VERSION 5.8 ;
BUSBITCHARS "[]" ;
DIVIDERCHAR "/" ;
UNITS
    DATABASE MICRONS 1000 ;
END UNITS

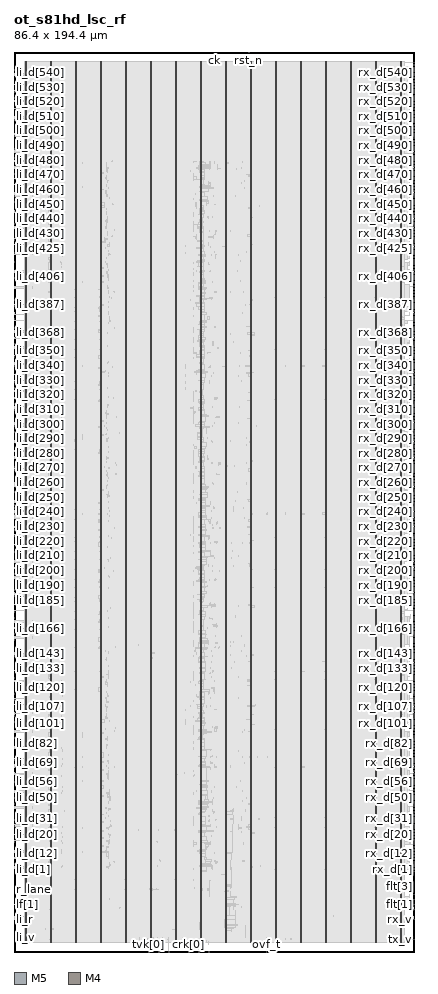
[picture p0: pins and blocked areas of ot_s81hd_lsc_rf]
MACRO ot_s81hd_lsc_rf
  FOREIGN ot_s81hd_lsc_rf 0 0 ;
  CLASS BLOCK ;
  SIZE 86.4 BY 194.4 ;
  PIN ck
    DIRECTION INPUT ;
    USE SIGNAL ;
    PORT
      LAYER M5 ;
        RECT  43.2 194.316 43.224 194.4 ;
    END
  END ck
  PIN crk[0]
    DIRECTION OUTPUT ;
    USE SIGNAL ;
    PORT
      LAYER M5 ;
        RECT  37.776 0 37.8 0.084 ;
    END
  END crk[0]
  PIN crk[1]
    DIRECTION OUTPUT ;
    USE SIGNAL ;
    PORT
      LAYER M5 ;
        RECT  39.936 0 39.96 0.084 ;
    END
  END crk[1]
  PIN crk[2]
    DIRECTION OUTPUT ;
    USE SIGNAL ;
    PORT
      LAYER M5 ;
        RECT  42.096 0 42.12 0.084 ;
    END
  END crk[2]
  PIN flt[0]
    DIRECTION OUTPUT ;
    USE SIGNAL ;
    PORT
      LAYER M4 ;
        RECT  86.316 9.168 86.4 9.192 ;
    END
  END flt[0]
  PIN flt[1]
    DIRECTION OUTPUT ;
    USE SIGNAL ;
    PORT
      LAYER M4 ;
        RECT  86.316 10.272 86.4 10.296 ;
    END
  END flt[1]
  PIN flt[2]
    DIRECTION OUTPUT ;
    USE SIGNAL ;
    PORT
      LAYER M4 ;
        RECT  86.316 11.328 86.4 11.352 ;
    END
  END flt[2]
  PIN flt[3]
    DIRECTION OUTPUT ;
    USE SIGNAL ;
    PORT
      LAYER M4 ;
        RECT  86.316 12.432 86.4 12.456 ;
    END
  END flt[3]
  PIN lf[0]
    DIRECTION INPUT ;
    USE SIGNAL ;
    PORT
      LAYER M4 ;
        RECT  0 9.168 0.084 9.192 ;
    END
  END lf[0]
  PIN lf[1]
    DIRECTION INPUT ;
    USE SIGNAL ;
    PORT
      LAYER M4 ;
        RECT  0 10.272 0.084 10.296 ;
    END
  END lf[1]
  PIN lf[2]
    DIRECTION INPUT ;
    USE SIGNAL ;
    PORT
      LAYER M4 ;
        RECT  0 11.328 0.084 11.352 ;
    END
  END lf[2]
  PIN li_d[0]
    DIRECTION INPUT ;
    USE SIGNAL ;
    PORT
      LAYER M4 ;
        RECT  0 17.424 0.084 17.448 ;
    END
  END li_d[0]
  PIN li_d[100]
    DIRECTION INPUT ;
    USE SIGNAL ;
    PORT
      LAYER M4 ;
        RECT  0 49.056 0.084 49.08 ;
    END
  END li_d[100]
  PIN li_d[101]
    DIRECTION INPUT ;
    USE SIGNAL ;
    PORT
      LAYER M4 ;
        RECT  0 49.392 0.084 49.416 ;
    END
  END li_d[101]
  PIN li_d[102]
    DIRECTION INPUT ;
    USE SIGNAL ;
    PORT
      LAYER M4 ;
        RECT  0 49.68 0.084 49.704 ;
    END
  END li_d[102]
  PIN li_d[103]
    DIRECTION INPUT ;
    USE SIGNAL ;
    PORT
      LAYER M4 ;
        RECT  0 50.016 0.084 50.04 ;
    END
  END li_d[103]
  PIN li_d[104]
    DIRECTION INPUT ;
    USE SIGNAL ;
    PORT
      LAYER M4 ;
        RECT  0 50.352 0.084 50.376 ;
    END
  END li_d[104]
  PIN li_d[105]
    DIRECTION INPUT ;
    USE SIGNAL ;
    PORT
      LAYER M4 ;
        RECT  0 50.64 0.084 50.664 ;
    END
  END li_d[105]
  PIN li_d[106]
    DIRECTION INPUT ;
    USE SIGNAL ;
    PORT
      LAYER M4 ;
        RECT  0 50.976 0.084 51 ;
    END
  END li_d[106]
  PIN li_d[107]
    DIRECTION INPUT ;
    USE SIGNAL ;
    PORT
      LAYER M4 ;
        RECT  0 51.264 0.084 51.288 ;
    END
  END li_d[107]
  PIN li_d[108]
    DIRECTION INPUT ;
    USE SIGNAL ;
    PORT
      LAYER M4 ;
        RECT  0 51.6 0.084 51.624 ;
    END
  END li_d[108]
  PIN li_d[109]
    DIRECTION INPUT ;
    USE SIGNAL ;
    PORT
      LAYER M4 ;
        RECT  0 51.936 0.084 51.96 ;
    END
  END li_d[109]
  PIN li_d[10]
    DIRECTION INPUT ;
    USE SIGNAL ;
    PORT
      LAYER M4 ;
        RECT  0 20.592 0.084 20.616 ;
    END
  END li_d[10]
  PIN li_d[110]
    DIRECTION INPUT ;
    USE SIGNAL ;
    PORT
      LAYER M4 ;
        RECT  0 52.224 0.084 52.248 ;
    END
  END li_d[110]
  PIN li_d[111]
    DIRECTION INPUT ;
    USE SIGNAL ;
    PORT
      LAYER M4 ;
        RECT  0 52.56 0.084 52.584 ;
    END
  END li_d[111]
  PIN li_d[112]
    DIRECTION INPUT ;
    USE SIGNAL ;
    PORT
      LAYER M4 ;
        RECT  0 52.848 0.084 52.872 ;
    END
  END li_d[112]
  PIN li_d[113]
    DIRECTION INPUT ;
    USE SIGNAL ;
    PORT
      LAYER M4 ;
        RECT  0 53.184 0.084 53.208 ;
    END
  END li_d[113]
  PIN li_d[114]
    DIRECTION INPUT ;
    USE SIGNAL ;
    PORT
      LAYER M4 ;
        RECT  0 53.472 0.084 53.496 ;
    END
  END li_d[114]
  PIN li_d[115]
    DIRECTION INPUT ;
    USE SIGNAL ;
    PORT
      LAYER M4 ;
        RECT  0 53.808 0.084 53.832 ;
    END
  END li_d[115]
  PIN li_d[116]
    DIRECTION INPUT ;
    USE SIGNAL ;
    PORT
      LAYER M4 ;
        RECT  0 54.144 0.084 54.168 ;
    END
  END li_d[116]
  PIN li_d[117]
    DIRECTION INPUT ;
    USE SIGNAL ;
    PORT
      LAYER M4 ;
        RECT  0 54.432 0.084 54.456 ;
    END
  END li_d[117]
  PIN li_d[118]
    DIRECTION INPUT ;
    USE SIGNAL ;
    PORT
      LAYER M4 ;
        RECT  0 54.768 0.084 54.792 ;
    END
  END li_d[118]
  PIN li_d[119]
    DIRECTION INPUT ;
    USE SIGNAL ;
    PORT
      LAYER M4 ;
        RECT  0 55.056 0.084 55.08 ;
    END
  END li_d[119]
  PIN li_d[11]
    DIRECTION INPUT ;
    USE SIGNAL ;
    PORT
      LAYER M4 ;
        RECT  0 20.928 0.084 20.952 ;
    END
  END li_d[11]
  PIN li_d[120]
    DIRECTION INPUT ;
    USE SIGNAL ;
    PORT
      LAYER M4 ;
        RECT  0 55.392 0.084 55.416 ;
    END
  END li_d[120]
  PIN li_d[121]
    DIRECTION INPUT ;
    USE SIGNAL ;
    PORT
      LAYER M4 ;
        RECT  0 55.728 0.084 55.752 ;
    END
  END li_d[121]
  PIN li_d[122]
    DIRECTION INPUT ;
    USE SIGNAL ;
    PORT
      LAYER M4 ;
        RECT  0 56.016 0.084 56.04 ;
    END
  END li_d[122]
  PIN li_d[123]
    DIRECTION INPUT ;
    USE SIGNAL ;
    PORT
      LAYER M4 ;
        RECT  0 56.352 0.084 56.376 ;
    END
  END li_d[123]
  PIN li_d[124]
    DIRECTION INPUT ;
    USE SIGNAL ;
    PORT
      LAYER M4 ;
        RECT  0 56.64 0.084 56.664 ;
    END
  END li_d[124]
  PIN li_d[125]
    DIRECTION INPUT ;
    USE SIGNAL ;
    PORT
      LAYER M4 ;
        RECT  0 56.976 0.084 57 ;
    END
  END li_d[125]
  PIN li_d[126]
    DIRECTION INPUT ;
    USE SIGNAL ;
    PORT
      LAYER M4 ;
        RECT  0 57.312 0.084 57.336 ;
    END
  END li_d[126]
  PIN li_d[127]
    DIRECTION INPUT ;
    USE SIGNAL ;
    PORT
      LAYER M4 ;
        RECT  0 57.6 0.084 57.624 ;
    END
  END li_d[127]
  PIN li_d[128]
    DIRECTION INPUT ;
    USE SIGNAL ;
    PORT
      LAYER M4 ;
        RECT  0 57.936 0.084 57.96 ;
    END
  END li_d[128]
  PIN li_d[129]
    DIRECTION INPUT ;
    USE SIGNAL ;
    PORT
      LAYER M4 ;
        RECT  0 58.224 0.084 58.248 ;
    END
  END li_d[129]
  PIN li_d[12]
    DIRECTION INPUT ;
    USE SIGNAL ;
    PORT
      LAYER M4 ;
        RECT  0 21.216 0.084 21.24 ;
    END
  END li_d[12]
  PIN li_d[130]
    DIRECTION INPUT ;
    USE SIGNAL ;
    PORT
      LAYER M4 ;
        RECT  0 58.56 0.084 58.584 ;
    END
  END li_d[130]
  PIN li_d[131]
    DIRECTION INPUT ;
    USE SIGNAL ;
    PORT
      LAYER M4 ;
        RECT  0 58.896 0.084 58.92 ;
    END
  END li_d[131]
  PIN li_d[132]
    DIRECTION INPUT ;
    USE SIGNAL ;
    PORT
      LAYER M4 ;
        RECT  0 59.184 0.084 59.208 ;
    END
  END li_d[132]
  PIN li_d[133]
    DIRECTION INPUT ;
    USE SIGNAL ;
    PORT
      LAYER M4 ;
        RECT  0 59.52 0.084 59.544 ;
    END
  END li_d[133]
  PIN li_d[134]
    DIRECTION INPUT ;
    USE SIGNAL ;
    PORT
      LAYER M4 ;
        RECT  0 59.808 0.084 59.832 ;
    END
  END li_d[134]
  PIN li_d[135]
    DIRECTION INPUT ;
    USE SIGNAL ;
    PORT
      LAYER M4 ;
        RECT  0 60.144 0.084 60.168 ;
    END
  END li_d[135]
  PIN li_d[136]
    DIRECTION INPUT ;
    USE SIGNAL ;
    PORT
      LAYER M4 ;
        RECT  0 60.432 0.084 60.456 ;
    END
  END li_d[136]
  PIN li_d[137]
    DIRECTION INPUT ;
    USE SIGNAL ;
    PORT
      LAYER M4 ;
        RECT  0 60.768 0.084 60.792 ;
    END
  END li_d[137]
  PIN li_d[138]
    DIRECTION INPUT ;
    USE SIGNAL ;
    PORT
      LAYER M4 ;
        RECT  0 61.104 0.084 61.128 ;
    END
  END li_d[138]
  PIN li_d[139]
    DIRECTION INPUT ;
    USE SIGNAL ;
    PORT
      LAYER M4 ;
        RECT  0 61.392 0.084 61.416 ;
    END
  END li_d[139]
  PIN li_d[13]
    DIRECTION INPUT ;
    USE SIGNAL ;
    PORT
      LAYER M4 ;
        RECT  0 21.552 0.084 21.576 ;
    END
  END li_d[13]
  PIN li_d[140]
    DIRECTION INPUT ;
    USE SIGNAL ;
    PORT
      LAYER M4 ;
        RECT  0 61.728 0.084 61.752 ;
    END
  END li_d[140]
  PIN li_d[141]
    DIRECTION INPUT ;
    USE SIGNAL ;
    PORT
      LAYER M4 ;
        RECT  0 62.016 0.084 62.04 ;
    END
  END li_d[141]
  PIN li_d[142]
    DIRECTION INPUT ;
    USE SIGNAL ;
    PORT
      LAYER M4 ;
        RECT  0 62.352 0.084 62.376 ;
    END
  END li_d[142]
  PIN li_d[143]
    DIRECTION INPUT ;
    USE SIGNAL ;
    PORT
      LAYER M4 ;
        RECT  0 62.688 0.084 62.712 ;
    END
  END li_d[143]
  PIN li_d[144]
    DIRECTION INPUT ;
    USE SIGNAL ;
    PORT
      LAYER M4 ;
        RECT  0 62.976 0.084 63 ;
    END
  END li_d[144]
  PIN li_d[145]
    DIRECTION INPUT ;
    USE SIGNAL ;
    PORT
      LAYER M4 ;
        RECT  0 63.312 0.084 63.336 ;
    END
  END li_d[145]
  PIN li_d[146]
    DIRECTION INPUT ;
    USE SIGNAL ;
    PORT
      LAYER M4 ;
        RECT  0 63.6 0.084 63.624 ;
    END
  END li_d[146]
  PIN li_d[147]
    DIRECTION INPUT ;
    USE SIGNAL ;
    PORT
      LAYER M4 ;
        RECT  0 63.936 0.084 63.96 ;
    END
  END li_d[147]
  PIN li_d[148]
    DIRECTION INPUT ;
    USE SIGNAL ;
    PORT
      LAYER M4 ;
        RECT  0 64.272 0.084 64.296 ;
    END
  END li_d[148]
  PIN li_d[149]
    DIRECTION INPUT ;
    USE SIGNAL ;
    PORT
      LAYER M4 ;
        RECT  0 64.56 0.084 64.584 ;
    END
  END li_d[149]
  PIN li_d[14]
    DIRECTION INPUT ;
    USE SIGNAL ;
    PORT
      LAYER M4 ;
        RECT  0 21.84 0.084 21.864 ;
    END
  END li_d[14]
  PIN li_d[150]
    DIRECTION INPUT ;
    USE SIGNAL ;
    PORT
      LAYER M4 ;
        RECT  0 64.896 0.084 64.92 ;
    END
  END li_d[150]
  PIN li_d[151]
    DIRECTION INPUT ;
    USE SIGNAL ;
    PORT
      LAYER M4 ;
        RECT  0 65.184 0.084 65.208 ;
    END
  END li_d[151]
  PIN li_d[152]
    DIRECTION INPUT ;
    USE SIGNAL ;
    PORT
      LAYER M4 ;
        RECT  0 65.52 0.084 65.544 ;
    END
  END li_d[152]
  PIN li_d[153]
    DIRECTION INPUT ;
    USE SIGNAL ;
    PORT
      LAYER M4 ;
        RECT  0 65.856 0.084 65.88 ;
    END
  END li_d[153]
  PIN li_d[154]
    DIRECTION INPUT ;
    USE SIGNAL ;
    PORT
      LAYER M4 ;
        RECT  0 66.144 0.084 66.168 ;
    END
  END li_d[154]
  PIN li_d[155]
    DIRECTION INPUT ;
    USE SIGNAL ;
    PORT
      LAYER M4 ;
        RECT  0 66.48 0.084 66.504 ;
    END
  END li_d[155]
  PIN li_d[156]
    DIRECTION INPUT ;
    USE SIGNAL ;
    PORT
      LAYER M4 ;
        RECT  0 66.768 0.084 66.792 ;
    END
  END li_d[156]
  PIN li_d[157]
    DIRECTION INPUT ;
    USE SIGNAL ;
    PORT
      LAYER M4 ;
        RECT  0 67.104 0.084 67.128 ;
    END
  END li_d[157]
  PIN li_d[158]
    DIRECTION INPUT ;
    USE SIGNAL ;
    PORT
      LAYER M4 ;
        RECT  0 67.392 0.084 67.416 ;
    END
  END li_d[158]
  PIN li_d[159]
    DIRECTION INPUT ;
    USE SIGNAL ;
    PORT
      LAYER M4 ;
        RECT  0 67.728 0.084 67.752 ;
    END
  END li_d[159]
  PIN li_d[15]
    DIRECTION INPUT ;
    USE SIGNAL ;
    PORT
      LAYER M4 ;
        RECT  0 22.176 0.084 22.2 ;
    END
  END li_d[15]
  PIN li_d[160]
    DIRECTION INPUT ;
    USE SIGNAL ;
    PORT
      LAYER M4 ;
        RECT  0 68.064 0.084 68.088 ;
    END
  END li_d[160]
  PIN li_d[161]
    DIRECTION INPUT ;
    USE SIGNAL ;
    PORT
      LAYER M4 ;
        RECT  0 68.352 0.084 68.376 ;
    END
  END li_d[161]
  PIN li_d[162]
    DIRECTION INPUT ;
    USE SIGNAL ;
    PORT
      LAYER M4 ;
        RECT  0 68.688 0.084 68.712 ;
    END
  END li_d[162]
  PIN li_d[163]
    DIRECTION INPUT ;
    USE SIGNAL ;
    PORT
      LAYER M4 ;
        RECT  0 68.976 0.084 69 ;
    END
  END li_d[163]
  PIN li_d[164]
    DIRECTION INPUT ;
    USE SIGNAL ;
    PORT
      LAYER M4 ;
        RECT  0 69.312 0.084 69.336 ;
    END
  END li_d[164]
  PIN li_d[165]
    DIRECTION INPUT ;
    USE SIGNAL ;
    PORT
      LAYER M4 ;
        RECT  0 69.648 0.084 69.672 ;
    END
  END li_d[165]
  PIN li_d[166]
    DIRECTION INPUT ;
    USE SIGNAL ;
    PORT
      LAYER M4 ;
        RECT  0 69.936 0.084 69.96 ;
    END
  END li_d[166]
  PIN li_d[167]
    DIRECTION INPUT ;
    USE SIGNAL ;
    PORT
      LAYER M4 ;
        RECT  0 70.272 0.084 70.296 ;
    END
  END li_d[167]
  PIN li_d[168]
    DIRECTION INPUT ;
    USE SIGNAL ;
    PORT
      LAYER M4 ;
        RECT  0 70.56 0.084 70.584 ;
    END
  END li_d[168]
  PIN li_d[169]
    DIRECTION INPUT ;
    USE SIGNAL ;
    PORT
      LAYER M4 ;
        RECT  0 70.896 0.084 70.92 ;
    END
  END li_d[169]
  PIN li_d[16]
    DIRECTION INPUT ;
    USE SIGNAL ;
    PORT
      LAYER M4 ;
        RECT  0 22.512 0.084 22.536 ;
    END
  END li_d[16]
  PIN li_d[170]
    DIRECTION INPUT ;
    USE SIGNAL ;
    PORT
      LAYER M4 ;
        RECT  0 71.232 0.084 71.256 ;
    END
  END li_d[170]
  PIN li_d[171]
    DIRECTION INPUT ;
    USE SIGNAL ;
    PORT
      LAYER M4 ;
        RECT  0 71.52 0.084 71.544 ;
    END
  END li_d[171]
  PIN li_d[172]
    DIRECTION INPUT ;
    USE SIGNAL ;
    PORT
      LAYER M4 ;
        RECT  0 71.856 0.084 71.88 ;
    END
  END li_d[172]
  PIN li_d[173]
    DIRECTION INPUT ;
    USE SIGNAL ;
    PORT
      LAYER M4 ;
        RECT  0 72.144 0.084 72.168 ;
    END
  END li_d[173]
  PIN li_d[174]
    DIRECTION INPUT ;
    USE SIGNAL ;
    PORT
      LAYER M4 ;
        RECT  0 72.48 0.084 72.504 ;
    END
  END li_d[174]
  PIN li_d[175]
    DIRECTION INPUT ;
    USE SIGNAL ;
    PORT
      LAYER M4 ;
        RECT  0 72.816 0.084 72.84 ;
    END
  END li_d[175]
  PIN li_d[176]
    DIRECTION INPUT ;
    USE SIGNAL ;
    PORT
      LAYER M4 ;
        RECT  0 73.104 0.084 73.128 ;
    END
  END li_d[176]
  PIN li_d[177]
    DIRECTION INPUT ;
    USE SIGNAL ;
    PORT
      LAYER M4 ;
        RECT  0 73.44 0.084 73.464 ;
    END
  END li_d[177]
  PIN li_d[178]
    DIRECTION INPUT ;
    USE SIGNAL ;
    PORT
      LAYER M4 ;
        RECT  0 73.728 0.084 73.752 ;
    END
  END li_d[178]
  PIN li_d[179]
    DIRECTION INPUT ;
    USE SIGNAL ;
    PORT
      LAYER M4 ;
        RECT  0 74.064 0.084 74.088 ;
    END
  END li_d[179]
  PIN li_d[17]
    DIRECTION INPUT ;
    USE SIGNAL ;
    PORT
      LAYER M4 ;
        RECT  0 22.8 0.084 22.824 ;
    END
  END li_d[17]
  PIN li_d[180]
    DIRECTION INPUT ;
    USE SIGNAL ;
    PORT
      LAYER M4 ;
        RECT  0 74.352 0.084 74.376 ;
    END
  END li_d[180]
  PIN li_d[181]
    DIRECTION INPUT ;
    USE SIGNAL ;
    PORT
      LAYER M4 ;
        RECT  0 74.688 0.084 74.712 ;
    END
  END li_d[181]
  PIN li_d[182]
    DIRECTION INPUT ;
    USE SIGNAL ;
    PORT
      LAYER M4 ;
        RECT  0 75.024 0.084 75.048 ;
    END
  END li_d[182]
  PIN li_d[183]
    DIRECTION INPUT ;
    USE SIGNAL ;
    PORT
      LAYER M4 ;
        RECT  0 75.312 0.084 75.336 ;
    END
  END li_d[183]
  PIN li_d[184]
    DIRECTION INPUT ;
    USE SIGNAL ;
    PORT
      LAYER M4 ;
        RECT  0 75.648 0.084 75.672 ;
    END
  END li_d[184]
  PIN li_d[185]
    DIRECTION INPUT ;
    USE SIGNAL ;
    PORT
      LAYER M4 ;
        RECT  0 75.936 0.084 75.96 ;
    END
  END li_d[185]
  PIN li_d[186]
    DIRECTION INPUT ;
    USE SIGNAL ;
    PORT
      LAYER M4 ;
        RECT  0 76.272 0.084 76.296 ;
    END
  END li_d[186]
  PIN li_d[187]
    DIRECTION INPUT ;
    USE SIGNAL ;
    PORT
      LAYER M4 ;
        RECT  0 76.608 0.084 76.632 ;
    END
  END li_d[187]
  PIN li_d[188]
    DIRECTION INPUT ;
    USE SIGNAL ;
    PORT
      LAYER M4 ;
        RECT  0 76.896 0.084 76.92 ;
    END
  END li_d[188]
  PIN li_d[189]
    DIRECTION INPUT ;
    USE SIGNAL ;
    PORT
      LAYER M4 ;
        RECT  0 77.232 0.084 77.256 ;
    END
  END li_d[189]
  PIN li_d[18]
    DIRECTION INPUT ;
    USE SIGNAL ;
    PORT
      LAYER M4 ;
        RECT  0 23.136 0.084 23.16 ;
    END
  END li_d[18]
  PIN li_d[190]
    DIRECTION INPUT ;
    USE SIGNAL ;
    PORT
      LAYER M4 ;
        RECT  0 77.52 0.084 77.544 ;
    END
  END li_d[190]
  PIN li_d[191]
    DIRECTION INPUT ;
    USE SIGNAL ;
    PORT
      LAYER M4 ;
        RECT  0 77.856 0.084 77.88 ;
    END
  END li_d[191]
  PIN li_d[192]
    DIRECTION INPUT ;
    USE SIGNAL ;
    PORT
      LAYER M4 ;
        RECT  0 78.192 0.084 78.216 ;
    END
  END li_d[192]
  PIN li_d[193]
    DIRECTION INPUT ;
    USE SIGNAL ;
    PORT
      LAYER M4 ;
        RECT  0 78.48 0.084 78.504 ;
    END
  END li_d[193]
  PIN li_d[194]
    DIRECTION INPUT ;
    USE SIGNAL ;
    PORT
      LAYER M4 ;
        RECT  0 78.816 0.084 78.84 ;
    END
  END li_d[194]
  PIN li_d[195]
    DIRECTION INPUT ;
    USE SIGNAL ;
    PORT
      LAYER M4 ;
        RECT  0 79.104 0.084 79.128 ;
    END
  END li_d[195]
  PIN li_d[196]
    DIRECTION INPUT ;
    USE SIGNAL ;
    PORT
      LAYER M4 ;
        RECT  0 79.44 0.084 79.464 ;
    END
  END li_d[196]
  PIN li_d[197]
    DIRECTION INPUT ;
    USE SIGNAL ;
    PORT
      LAYER M4 ;
        RECT  0 79.776 0.084 79.8 ;
    END
  END li_d[197]
  PIN li_d[198]
    DIRECTION INPUT ;
    USE SIGNAL ;
    PORT
      LAYER M4 ;
        RECT  0 80.064 0.084 80.088 ;
    END
  END li_d[198]
  PIN li_d[199]
    DIRECTION INPUT ;
    USE SIGNAL ;
    PORT
      LAYER M4 ;
        RECT  0 80.4 0.084 80.424 ;
    END
  END li_d[199]
  PIN li_d[19]
    DIRECTION INPUT ;
    USE SIGNAL ;
    PORT
      LAYER M4 ;
        RECT  0 23.424 0.084 23.448 ;
    END
  END li_d[19]
  PIN li_d[1]
    DIRECTION INPUT ;
    USE SIGNAL ;
    PORT
      LAYER M4 ;
        RECT  0 17.76 0.084 17.784 ;
    END
  END li_d[1]
  PIN li_d[200]
    DIRECTION INPUT ;
    USE SIGNAL ;
    PORT
      LAYER M4 ;
        RECT  0 80.688 0.084 80.712 ;
    END
  END li_d[200]
  PIN li_d[201]
    DIRECTION INPUT ;
    USE SIGNAL ;
    PORT
      LAYER M4 ;
        RECT  0 81.024 0.084 81.048 ;
    END
  END li_d[201]
  PIN li_d[202]
    DIRECTION INPUT ;
    USE SIGNAL ;
    PORT
      LAYER M4 ;
        RECT  0 81.36 0.084 81.384 ;
    END
  END li_d[202]
  PIN li_d[203]
    DIRECTION INPUT ;
    USE SIGNAL ;
    PORT
      LAYER M4 ;
        RECT  0 81.648 0.084 81.672 ;
    END
  END li_d[203]
  PIN li_d[204]
    DIRECTION INPUT ;
    USE SIGNAL ;
    PORT
      LAYER M4 ;
        RECT  0 81.984 0.084 82.008 ;
    END
  END li_d[204]
  PIN li_d[205]
    DIRECTION INPUT ;
    USE SIGNAL ;
    PORT
      LAYER M4 ;
        RECT  0 82.272 0.084 82.296 ;
    END
  END li_d[205]
  PIN li_d[206]
    DIRECTION INPUT ;
    USE SIGNAL ;
    PORT
      LAYER M4 ;
        RECT  0 82.608 0.084 82.632 ;
    END
  END li_d[206]
  PIN li_d[207]
    DIRECTION INPUT ;
    USE SIGNAL ;
    PORT
      LAYER M4 ;
        RECT  0 82.896 0.084 82.92 ;
    END
  END li_d[207]
  PIN li_d[208]
    DIRECTION INPUT ;
    USE SIGNAL ;
    PORT
      LAYER M4 ;
        RECT  0 83.232 0.084 83.256 ;
    END
  END li_d[208]
  PIN li_d[209]
    DIRECTION INPUT ;
    USE SIGNAL ;
    PORT
      LAYER M4 ;
        RECT  0 83.568 0.084 83.592 ;
    END
  END li_d[209]
  PIN li_d[20]
    DIRECTION INPUT ;
    USE SIGNAL ;
    PORT
      LAYER M4 ;
        RECT  0 23.76 0.084 23.784 ;
    END
  END li_d[20]
  PIN li_d[210]
    DIRECTION INPUT ;
    USE SIGNAL ;
    PORT
      LAYER M4 ;
        RECT  0 83.856 0.084 83.88 ;
    END
  END li_d[210]
  PIN li_d[211]
    DIRECTION INPUT ;
    USE SIGNAL ;
    PORT
      LAYER M4 ;
        RECT  0 84.192 0.084 84.216 ;
    END
  END li_d[211]
  PIN li_d[212]
    DIRECTION INPUT ;
    USE SIGNAL ;
    PORT
      LAYER M4 ;
        RECT  0 84.48 0.084 84.504 ;
    END
  END li_d[212]
  PIN li_d[213]
    DIRECTION INPUT ;
    USE SIGNAL ;
    PORT
      LAYER M4 ;
        RECT  0 84.816 0.084 84.84 ;
    END
  END li_d[213]
  PIN li_d[214]
    DIRECTION INPUT ;
    USE SIGNAL ;
    PORT
      LAYER M4 ;
        RECT  0 85.152 0.084 85.176 ;
    END
  END li_d[214]
  PIN li_d[215]
    DIRECTION INPUT ;
    USE SIGNAL ;
    PORT
      LAYER M4 ;
        RECT  0 85.44 0.084 85.464 ;
    END
  END li_d[215]
  PIN li_d[216]
    DIRECTION INPUT ;
    USE SIGNAL ;
    PORT
      LAYER M4 ;
        RECT  0 85.776 0.084 85.8 ;
    END
  END li_d[216]
  PIN li_d[217]
    DIRECTION INPUT ;
    USE SIGNAL ;
    PORT
      LAYER M4 ;
        RECT  0 86.064 0.084 86.088 ;
    END
  END li_d[217]
  PIN li_d[218]
    DIRECTION INPUT ;
    USE SIGNAL ;
    PORT
      LAYER M4 ;
        RECT  0 86.4 0.084 86.424 ;
    END
  END li_d[218]
  PIN li_d[219]
    DIRECTION INPUT ;
    USE SIGNAL ;
    PORT
      LAYER M4 ;
        RECT  0 86.736 0.084 86.76 ;
    END
  END li_d[219]
  PIN li_d[21]
    DIRECTION INPUT ;
    USE SIGNAL ;
    PORT
      LAYER M4 ;
        RECT  0 24.048 0.084 24.072 ;
    END
  END li_d[21]
  PIN li_d[220]
    DIRECTION INPUT ;
    USE SIGNAL ;
    PORT
      LAYER M4 ;
        RECT  0 87.024 0.084 87.048 ;
    END
  END li_d[220]
  PIN li_d[221]
    DIRECTION INPUT ;
    USE SIGNAL ;
    PORT
      LAYER M4 ;
        RECT  0 87.36 0.084 87.384 ;
    END
  END li_d[221]
  PIN li_d[222]
    DIRECTION INPUT ;
    USE SIGNAL ;
    PORT
      LAYER M4 ;
        RECT  0 87.648 0.084 87.672 ;
    END
  END li_d[222]
  PIN li_d[223]
    DIRECTION INPUT ;
    USE SIGNAL ;
    PORT
      LAYER M4 ;
        RECT  0 87.984 0.084 88.008 ;
    END
  END li_d[223]
  PIN li_d[224]
    DIRECTION INPUT ;
    USE SIGNAL ;
    PORT
      LAYER M4 ;
        RECT  0 88.32 0.084 88.344 ;
    END
  END li_d[224]
  PIN li_d[225]
    DIRECTION INPUT ;
    USE SIGNAL ;
    PORT
      LAYER M4 ;
        RECT  0 88.608 0.084 88.632 ;
    END
  END li_d[225]
  PIN li_d[226]
    DIRECTION INPUT ;
    USE SIGNAL ;
    PORT
      LAYER M4 ;
        RECT  0 88.944 0.084 88.968 ;
    END
  END li_d[226]
  PIN li_d[227]
    DIRECTION INPUT ;
    USE SIGNAL ;
    PORT
      LAYER M4 ;
        RECT  0 89.232 0.084 89.256 ;
    END
  END li_d[227]
  PIN li_d[228]
    DIRECTION INPUT ;
    USE SIGNAL ;
    PORT
      LAYER M4 ;
        RECT  0 89.568 0.084 89.592 ;
    END
  END li_d[228]
  PIN li_d[229]
    DIRECTION INPUT ;
    USE SIGNAL ;
    PORT
      LAYER M4 ;
        RECT  0 89.856 0.084 89.88 ;
    END
  END li_d[229]
  PIN li_d[22]
    DIRECTION INPUT ;
    USE SIGNAL ;
    PORT
      LAYER M4 ;
        RECT  0 24.384 0.084 24.408 ;
    END
  END li_d[22]
  PIN li_d[230]
    DIRECTION INPUT ;
    USE SIGNAL ;
    PORT
      LAYER M4 ;
        RECT  0 90.192 0.084 90.216 ;
    END
  END li_d[230]
  PIN li_d[231]
    DIRECTION INPUT ;
    USE SIGNAL ;
    PORT
      LAYER M4 ;
        RECT  0 90.528 0.084 90.552 ;
    END
  END li_d[231]
  PIN li_d[232]
    DIRECTION INPUT ;
    USE SIGNAL ;
    PORT
      LAYER M4 ;
        RECT  0 90.816 0.084 90.84 ;
    END
  END li_d[232]
  PIN li_d[233]
    DIRECTION INPUT ;
    USE SIGNAL ;
    PORT
      LAYER M4 ;
        RECT  0 91.152 0.084 91.176 ;
    END
  END li_d[233]
  PIN li_d[234]
    DIRECTION INPUT ;
    USE SIGNAL ;
    PORT
      LAYER M4 ;
        RECT  0 91.44 0.084 91.464 ;
    END
  END li_d[234]
  PIN li_d[235]
    DIRECTION INPUT ;
    USE SIGNAL ;
    PORT
      LAYER M4 ;
        RECT  0 91.776 0.084 91.8 ;
    END
  END li_d[235]
  PIN li_d[236]
    DIRECTION INPUT ;
    USE SIGNAL ;
    PORT
      LAYER M4 ;
        RECT  0 92.112 0.084 92.136 ;
    END
  END li_d[236]
  PIN li_d[237]
    DIRECTION INPUT ;
    USE SIGNAL ;
    PORT
      LAYER M4 ;
        RECT  0 92.4 0.084 92.424 ;
    END
  END li_d[237]
  PIN li_d[238]
    DIRECTION INPUT ;
    USE SIGNAL ;
    PORT
      LAYER M4 ;
        RECT  0 92.736 0.084 92.76 ;
    END
  END li_d[238]
  PIN li_d[239]
    DIRECTION INPUT ;
    USE SIGNAL ;
    PORT
      LAYER M4 ;
        RECT  0 93.024 0.084 93.048 ;
    END
  END li_d[239]
  PIN li_d[23]
    DIRECTION INPUT ;
    USE SIGNAL ;
    PORT
      LAYER M4 ;
        RECT  0 24.72 0.084 24.744 ;
    END
  END li_d[23]
  PIN li_d[240]
    DIRECTION INPUT ;
    USE SIGNAL ;
    PORT
      LAYER M4 ;
        RECT  0 93.36 0.084 93.384 ;
    END
  END li_d[240]
  PIN li_d[241]
    DIRECTION INPUT ;
    USE SIGNAL ;
    PORT
      LAYER M4 ;
        RECT  0 93.696 0.084 93.72 ;
    END
  END li_d[241]
  PIN li_d[242]
    DIRECTION INPUT ;
    USE SIGNAL ;
    PORT
      LAYER M4 ;
        RECT  0 93.984 0.084 94.008 ;
    END
  END li_d[242]
  PIN li_d[243]
    DIRECTION INPUT ;
    USE SIGNAL ;
    PORT
      LAYER M4 ;
        RECT  0 94.32 0.084 94.344 ;
    END
  END li_d[243]
  PIN li_d[244]
    DIRECTION INPUT ;
    USE SIGNAL ;
    PORT
      LAYER M4 ;
        RECT  0 94.608 0.084 94.632 ;
    END
  END li_d[244]
  PIN li_d[245]
    DIRECTION INPUT ;
    USE SIGNAL ;
    PORT
      LAYER M4 ;
        RECT  0 94.944 0.084 94.968 ;
    END
  END li_d[245]
  PIN li_d[246]
    DIRECTION INPUT ;
    USE SIGNAL ;
    PORT
      LAYER M4 ;
        RECT  0 95.28 0.084 95.304 ;
    END
  END li_d[246]
  PIN li_d[247]
    DIRECTION INPUT ;
    USE SIGNAL ;
    PORT
      LAYER M4 ;
        RECT  0 95.568 0.084 95.592 ;
    END
  END li_d[247]
  PIN li_d[248]
    DIRECTION INPUT ;
    USE SIGNAL ;
    PORT
      LAYER M4 ;
        RECT  0 95.904 0.084 95.928 ;
    END
  END li_d[248]
  PIN li_d[249]
    DIRECTION INPUT ;
    USE SIGNAL ;
    PORT
      LAYER M4 ;
        RECT  0 96.192 0.084 96.216 ;
    END
  END li_d[249]
  PIN li_d[24]
    DIRECTION INPUT ;
    USE SIGNAL ;
    PORT
      LAYER M4 ;
        RECT  0 25.008 0.084 25.032 ;
    END
  END li_d[24]
  PIN li_d[250]
    DIRECTION INPUT ;
    USE SIGNAL ;
    PORT
      LAYER M4 ;
        RECT  0 96.528 0.084 96.552 ;
    END
  END li_d[250]
  PIN li_d[251]
    DIRECTION INPUT ;
    USE SIGNAL ;
    PORT
      LAYER M4 ;
        RECT  0 96.816 0.084 96.84 ;
    END
  END li_d[251]
  PIN li_d[252]
    DIRECTION INPUT ;
    USE SIGNAL ;
    PORT
      LAYER M4 ;
        RECT  0 97.152 0.084 97.176 ;
    END
  END li_d[252]
  PIN li_d[253]
    DIRECTION INPUT ;
    USE SIGNAL ;
    PORT
      LAYER M4 ;
        RECT  0 97.488 0.084 97.512 ;
    END
  END li_d[253]
  PIN li_d[254]
    DIRECTION INPUT ;
    USE SIGNAL ;
    PORT
      LAYER M4 ;
        RECT  0 97.776 0.084 97.8 ;
    END
  END li_d[254]
  PIN li_d[255]
    DIRECTION INPUT ;
    USE SIGNAL ;
    PORT
      LAYER M4 ;
        RECT  0 98.112 0.084 98.136 ;
    END
  END li_d[255]
  PIN li_d[256]
    DIRECTION INPUT ;
    USE SIGNAL ;
    PORT
      LAYER M4 ;
        RECT  0 98.4 0.084 98.424 ;
    END
  END li_d[256]
  PIN li_d[257]
    DIRECTION INPUT ;
    USE SIGNAL ;
    PORT
      LAYER M4 ;
        RECT  0 98.736 0.084 98.76 ;
    END
  END li_d[257]
  PIN li_d[258]
    DIRECTION INPUT ;
    USE SIGNAL ;
    PORT
      LAYER M4 ;
        RECT  0 99.072 0.084 99.096 ;
    END
  END li_d[258]
  PIN li_d[259]
    DIRECTION INPUT ;
    USE SIGNAL ;
    PORT
      LAYER M4 ;
        RECT  0 99.36 0.084 99.384 ;
    END
  END li_d[259]
  PIN li_d[25]
    DIRECTION INPUT ;
    USE SIGNAL ;
    PORT
      LAYER M4 ;
        RECT  0 25.344 0.084 25.368 ;
    END
  END li_d[25]
  PIN li_d[260]
    DIRECTION INPUT ;
    USE SIGNAL ;
    PORT
      LAYER M4 ;
        RECT  0 99.696 0.084 99.72 ;
    END
  END li_d[260]
  PIN li_d[261]
    DIRECTION INPUT ;
    USE SIGNAL ;
    PORT
      LAYER M4 ;
        RECT  0 99.984 0.084 100.008 ;
    END
  END li_d[261]
  PIN li_d[262]
    DIRECTION INPUT ;
    USE SIGNAL ;
    PORT
      LAYER M4 ;
        RECT  0 100.32 0.084 100.344 ;
    END
  END li_d[262]
  PIN li_d[263]
    DIRECTION INPUT ;
    USE SIGNAL ;
    PORT
      LAYER M4 ;
        RECT  0 100.656 0.084 100.68 ;
    END
  END li_d[263]
  PIN li_d[264]
    DIRECTION INPUT ;
    USE SIGNAL ;
    PORT
      LAYER M4 ;
        RECT  0 100.944 0.084 100.968 ;
    END
  END li_d[264]
  PIN li_d[265]
    DIRECTION INPUT ;
    USE SIGNAL ;
    PORT
      LAYER M4 ;
        RECT  0 101.28 0.084 101.304 ;
    END
  END li_d[265]
  PIN li_d[266]
    DIRECTION INPUT ;
    USE SIGNAL ;
    PORT
      LAYER M4 ;
        RECT  0 101.568 0.084 101.592 ;
    END
  END li_d[266]
  PIN li_d[267]
    DIRECTION INPUT ;
    USE SIGNAL ;
    PORT
      LAYER M4 ;
        RECT  0 101.904 0.084 101.928 ;
    END
  END li_d[267]
  PIN li_d[268]
    DIRECTION INPUT ;
    USE SIGNAL ;
    PORT
      LAYER M4 ;
        RECT  0 102.24 0.084 102.264 ;
    END
  END li_d[268]
  PIN li_d[269]
    DIRECTION INPUT ;
    USE SIGNAL ;
    PORT
      LAYER M4 ;
        RECT  0 102.528 0.084 102.552 ;
    END
  END li_d[269]
  PIN li_d[26]
    DIRECTION INPUT ;
    USE SIGNAL ;
    PORT
      LAYER M4 ;
        RECT  0 25.632 0.084 25.656 ;
    END
  END li_d[26]
  PIN li_d[270]
    DIRECTION INPUT ;
    USE SIGNAL ;
    PORT
      LAYER M4 ;
        RECT  0 102.864 0.084 102.888 ;
    END
  END li_d[270]
  PIN li_d[271]
    DIRECTION INPUT ;
    USE SIGNAL ;
    PORT
      LAYER M4 ;
        RECT  0 103.152 0.084 103.176 ;
    END
  END li_d[271]
  PIN li_d[272]
    DIRECTION INPUT ;
    USE SIGNAL ;
    PORT
      LAYER M4 ;
        RECT  0 103.488 0.084 103.512 ;
    END
  END li_d[272]
  PIN li_d[273]
    DIRECTION INPUT ;
    USE SIGNAL ;
    PORT
      LAYER M4 ;
        RECT  0 103.776 0.084 103.8 ;
    END
  END li_d[273]
  PIN li_d[274]
    DIRECTION INPUT ;
    USE SIGNAL ;
    PORT
      LAYER M4 ;
        RECT  0 104.112 0.084 104.136 ;
    END
  END li_d[274]
  PIN li_d[275]
    DIRECTION INPUT ;
    USE SIGNAL ;
    PORT
      LAYER M4 ;
        RECT  0 104.448 0.084 104.472 ;
    END
  END li_d[275]
  PIN li_d[276]
    DIRECTION INPUT ;
    USE SIGNAL ;
    PORT
      LAYER M4 ;
        RECT  0 104.736 0.084 104.76 ;
    END
  END li_d[276]
  PIN li_d[277]
    DIRECTION INPUT ;
    USE SIGNAL ;
    PORT
      LAYER M4 ;
        RECT  0 105.072 0.084 105.096 ;
    END
  END li_d[277]
  PIN li_d[278]
    DIRECTION INPUT ;
    USE SIGNAL ;
    PORT
      LAYER M4 ;
        RECT  0 105.36 0.084 105.384 ;
    END
  END li_d[278]
  PIN li_d[279]
    DIRECTION INPUT ;
    USE SIGNAL ;
    PORT
      LAYER M4 ;
        RECT  0 105.696 0.084 105.72 ;
    END
  END li_d[279]
  PIN li_d[27]
    DIRECTION INPUT ;
    USE SIGNAL ;
    PORT
      LAYER M4 ;
        RECT  0 25.968 0.084 25.992 ;
    END
  END li_d[27]
  PIN li_d[280]
    DIRECTION INPUT ;
    USE SIGNAL ;
    PORT
      LAYER M4 ;
        RECT  0 106.032 0.084 106.056 ;
    END
  END li_d[280]
  PIN li_d[281]
    DIRECTION INPUT ;
    USE SIGNAL ;
    PORT
      LAYER M4 ;
        RECT  0 106.32 0.084 106.344 ;
    END
  END li_d[281]
  PIN li_d[282]
    DIRECTION INPUT ;
    USE SIGNAL ;
    PORT
      LAYER M4 ;
        RECT  0 106.656 0.084 106.68 ;
    END
  END li_d[282]
  PIN li_d[283]
    DIRECTION INPUT ;
    USE SIGNAL ;
    PORT
      LAYER M4 ;
        RECT  0 106.944 0.084 106.968 ;
    END
  END li_d[283]
  PIN li_d[284]
    DIRECTION INPUT ;
    USE SIGNAL ;
    PORT
      LAYER M4 ;
        RECT  0 107.28 0.084 107.304 ;
    END
  END li_d[284]
  PIN li_d[285]
    DIRECTION INPUT ;
    USE SIGNAL ;
    PORT
      LAYER M4 ;
        RECT  0 107.616 0.084 107.64 ;
    END
  END li_d[285]
  PIN li_d[286]
    DIRECTION INPUT ;
    USE SIGNAL ;
    PORT
      LAYER M4 ;
        RECT  0 107.904 0.084 107.928 ;
    END
  END li_d[286]
  PIN li_d[287]
    DIRECTION INPUT ;
    USE SIGNAL ;
    PORT
      LAYER M4 ;
        RECT  0 108.24 0.084 108.264 ;
    END
  END li_d[287]
  PIN li_d[288]
    DIRECTION INPUT ;
    USE SIGNAL ;
    PORT
      LAYER M4 ;
        RECT  0 108.528 0.084 108.552 ;
    END
  END li_d[288]
  PIN li_d[289]
    DIRECTION INPUT ;
    USE SIGNAL ;
    PORT
      LAYER M4 ;
        RECT  0 108.864 0.084 108.888 ;
    END
  END li_d[289]
  PIN li_d[28]
    DIRECTION INPUT ;
    USE SIGNAL ;
    PORT
      LAYER M4 ;
        RECT  0 26.304 0.084 26.328 ;
    END
  END li_d[28]
  PIN li_d[290]
    DIRECTION INPUT ;
    USE SIGNAL ;
    PORT
      LAYER M4 ;
        RECT  0 109.2 0.084 109.224 ;
    END
  END li_d[290]
  PIN li_d[291]
    DIRECTION INPUT ;
    USE SIGNAL ;
    PORT
      LAYER M4 ;
        RECT  0 109.488 0.084 109.512 ;
    END
  END li_d[291]
  PIN li_d[292]
    DIRECTION INPUT ;
    USE SIGNAL ;
    PORT
      LAYER M4 ;
        RECT  0 109.824 0.084 109.848 ;
    END
  END li_d[292]
  PIN li_d[293]
    DIRECTION INPUT ;
    USE SIGNAL ;
    PORT
      LAYER M4 ;
        RECT  0 110.112 0.084 110.136 ;
    END
  END li_d[293]
  PIN li_d[294]
    DIRECTION INPUT ;
    USE SIGNAL ;
    PORT
      LAYER M4 ;
        RECT  0 110.448 0.084 110.472 ;
    END
  END li_d[294]
  PIN li_d[295]
    DIRECTION INPUT ;
    USE SIGNAL ;
    PORT
      LAYER M4 ;
        RECT  0 110.736 0.084 110.76 ;
    END
  END li_d[295]
  PIN li_d[296]
    DIRECTION INPUT ;
    USE SIGNAL ;
    PORT
      LAYER M4 ;
        RECT  0 111.072 0.084 111.096 ;
    END
  END li_d[296]
  PIN li_d[297]
    DIRECTION INPUT ;
    USE SIGNAL ;
    PORT
      LAYER M4 ;
        RECT  0 111.408 0.084 111.432 ;
    END
  END li_d[297]
  PIN li_d[298]
    DIRECTION INPUT ;
    USE SIGNAL ;
    PORT
      LAYER M4 ;
        RECT  0 111.696 0.084 111.72 ;
    END
  END li_d[298]
  PIN li_d[299]
    DIRECTION INPUT ;
    USE SIGNAL ;
    PORT
      LAYER M4 ;
        RECT  0 112.032 0.084 112.056 ;
    END
  END li_d[299]
  PIN li_d[29]
    DIRECTION INPUT ;
    USE SIGNAL ;
    PORT
      LAYER M4 ;
        RECT  0 26.592 0.084 26.616 ;
    END
  END li_d[29]
  PIN li_d[2]
    DIRECTION INPUT ;
    USE SIGNAL ;
    PORT
      LAYER M4 ;
        RECT  0 18.048 0.084 18.072 ;
    END
  END li_d[2]
  PIN li_d[300]
    DIRECTION INPUT ;
    USE SIGNAL ;
    PORT
      LAYER M4 ;
        RECT  0 112.32 0.084 112.344 ;
    END
  END li_d[300]
  PIN li_d[301]
    DIRECTION INPUT ;
    USE SIGNAL ;
    PORT
      LAYER M4 ;
        RECT  0 112.656 0.084 112.68 ;
    END
  END li_d[301]
  PIN li_d[302]
    DIRECTION INPUT ;
    USE SIGNAL ;
    PORT
      LAYER M4 ;
        RECT  0 112.992 0.084 113.016 ;
    END
  END li_d[302]
  PIN li_d[303]
    DIRECTION INPUT ;
    USE SIGNAL ;
    PORT
      LAYER M4 ;
        RECT  0 113.28 0.084 113.304 ;
    END
  END li_d[303]
  PIN li_d[304]
    DIRECTION INPUT ;
    USE SIGNAL ;
    PORT
      LAYER M4 ;
        RECT  0 113.616 0.084 113.64 ;
    END
  END li_d[304]
  PIN li_d[305]
    DIRECTION INPUT ;
    USE SIGNAL ;
    PORT
      LAYER M4 ;
        RECT  0 113.904 0.084 113.928 ;
    END
  END li_d[305]
  PIN li_d[306]
    DIRECTION INPUT ;
    USE SIGNAL ;
    PORT
      LAYER M4 ;
        RECT  0 114.24 0.084 114.264 ;
    END
  END li_d[306]
  PIN li_d[307]
    DIRECTION INPUT ;
    USE SIGNAL ;
    PORT
      LAYER M4 ;
        RECT  0 114.576 0.084 114.6 ;
    END
  END li_d[307]
  PIN li_d[308]
    DIRECTION INPUT ;
    USE SIGNAL ;
    PORT
      LAYER M4 ;
        RECT  0 114.864 0.084 114.888 ;
    END
  END li_d[308]
  PIN li_d[309]
    DIRECTION INPUT ;
    USE SIGNAL ;
    PORT
      LAYER M4 ;
        RECT  0 115.2 0.084 115.224 ;
    END
  END li_d[309]
  PIN li_d[30]
    DIRECTION INPUT ;
    USE SIGNAL ;
    PORT
      LAYER M4 ;
        RECT  0 26.928 0.084 26.952 ;
    END
  END li_d[30]
  PIN li_d[310]
    DIRECTION INPUT ;
    USE SIGNAL ;
    PORT
      LAYER M4 ;
        RECT  0 115.488 0.084 115.512 ;
    END
  END li_d[310]
  PIN li_d[311]
    DIRECTION INPUT ;
    USE SIGNAL ;
    PORT
      LAYER M4 ;
        RECT  0 115.824 0.084 115.848 ;
    END
  END li_d[311]
  PIN li_d[312]
    DIRECTION INPUT ;
    USE SIGNAL ;
    PORT
      LAYER M4 ;
        RECT  0 116.16 0.084 116.184 ;
    END
  END li_d[312]
  PIN li_d[313]
    DIRECTION INPUT ;
    USE SIGNAL ;
    PORT
      LAYER M4 ;
        RECT  0 116.448 0.084 116.472 ;
    END
  END li_d[313]
  PIN li_d[314]
    DIRECTION INPUT ;
    USE SIGNAL ;
    PORT
      LAYER M4 ;
        RECT  0 116.784 0.084 116.808 ;
    END
  END li_d[314]
  PIN li_d[315]
    DIRECTION INPUT ;
    USE SIGNAL ;
    PORT
      LAYER M4 ;
        RECT  0 117.072 0.084 117.096 ;
    END
  END li_d[315]
  PIN li_d[316]
    DIRECTION INPUT ;
    USE SIGNAL ;
    PORT
      LAYER M4 ;
        RECT  0 117.408 0.084 117.432 ;
    END
  END li_d[316]
  PIN li_d[317]
    DIRECTION INPUT ;
    USE SIGNAL ;
    PORT
      LAYER M4 ;
        RECT  0 117.744 0.084 117.768 ;
    END
  END li_d[317]
  PIN li_d[318]
    DIRECTION INPUT ;
    USE SIGNAL ;
    PORT
      LAYER M4 ;
        RECT  0 118.032 0.084 118.056 ;
    END
  END li_d[318]
  PIN li_d[319]
    DIRECTION INPUT ;
    USE SIGNAL ;
    PORT
      LAYER M4 ;
        RECT  0 118.368 0.084 118.392 ;
    END
  END li_d[319]
  PIN li_d[31]
    DIRECTION INPUT ;
    USE SIGNAL ;
    PORT
      LAYER M4 ;
        RECT  0 27.216 0.084 27.24 ;
    END
  END li_d[31]
  PIN li_d[320]
    DIRECTION INPUT ;
    USE SIGNAL ;
    PORT
      LAYER M4 ;
        RECT  0 118.656 0.084 118.68 ;
    END
  END li_d[320]
  PIN li_d[321]
    DIRECTION INPUT ;
    USE SIGNAL ;
    PORT
      LAYER M4 ;
        RECT  0 118.992 0.084 119.016 ;
    END
  END li_d[321]
  PIN li_d[322]
    DIRECTION INPUT ;
    USE SIGNAL ;
    PORT
      LAYER M4 ;
        RECT  0 119.28 0.084 119.304 ;
    END
  END li_d[322]
  PIN li_d[323]
    DIRECTION INPUT ;
    USE SIGNAL ;
    PORT
      LAYER M4 ;
        RECT  0 119.616 0.084 119.64 ;
    END
  END li_d[323]
  PIN li_d[324]
    DIRECTION INPUT ;
    USE SIGNAL ;
    PORT
      LAYER M4 ;
        RECT  0 119.952 0.084 119.976 ;
    END
  END li_d[324]
  PIN li_d[325]
    DIRECTION INPUT ;
    USE SIGNAL ;
    PORT
      LAYER M4 ;
        RECT  0 120.24 0.084 120.264 ;
    END
  END li_d[325]
  PIN li_d[326]
    DIRECTION INPUT ;
    USE SIGNAL ;
    PORT
      LAYER M4 ;
        RECT  0 120.576 0.084 120.6 ;
    END
  END li_d[326]
  PIN li_d[327]
    DIRECTION INPUT ;
    USE SIGNAL ;
    PORT
      LAYER M4 ;
        RECT  0 120.864 0.084 120.888 ;
    END
  END li_d[327]
  PIN li_d[328]
    DIRECTION INPUT ;
    USE SIGNAL ;
    PORT
      LAYER M4 ;
        RECT  0 121.2 0.084 121.224 ;
    END
  END li_d[328]
  PIN li_d[329]
    DIRECTION INPUT ;
    USE SIGNAL ;
    PORT
      LAYER M4 ;
        RECT  0 121.536 0.084 121.56 ;
    END
  END li_d[329]
  PIN li_d[32]
    DIRECTION INPUT ;
    USE SIGNAL ;
    PORT
      LAYER M4 ;
        RECT  0 27.552 0.084 27.576 ;
    END
  END li_d[32]
  PIN li_d[330]
    DIRECTION INPUT ;
    USE SIGNAL ;
    PORT
      LAYER M4 ;
        RECT  0 121.824 0.084 121.848 ;
    END
  END li_d[330]
  PIN li_d[331]
    DIRECTION INPUT ;
    USE SIGNAL ;
    PORT
      LAYER M4 ;
        RECT  0 122.16 0.084 122.184 ;
    END
  END li_d[331]
  PIN li_d[332]
    DIRECTION INPUT ;
    USE SIGNAL ;
    PORT
      LAYER M4 ;
        RECT  0 122.448 0.084 122.472 ;
    END
  END li_d[332]
  PIN li_d[333]
    DIRECTION INPUT ;
    USE SIGNAL ;
    PORT
      LAYER M4 ;
        RECT  0 122.784 0.084 122.808 ;
    END
  END li_d[333]
  PIN li_d[334]
    DIRECTION INPUT ;
    USE SIGNAL ;
    PORT
      LAYER M4 ;
        RECT  0 123.12 0.084 123.144 ;
    END
  END li_d[334]
  PIN li_d[335]
    DIRECTION INPUT ;
    USE SIGNAL ;
    PORT
      LAYER M4 ;
        RECT  0 123.408 0.084 123.432 ;
    END
  END li_d[335]
  PIN li_d[336]
    DIRECTION INPUT ;
    USE SIGNAL ;
    PORT
      LAYER M4 ;
        RECT  0 123.744 0.084 123.768 ;
    END
  END li_d[336]
  PIN li_d[337]
    DIRECTION INPUT ;
    USE SIGNAL ;
    PORT
      LAYER M4 ;
        RECT  0 124.032 0.084 124.056 ;
    END
  END li_d[337]
  PIN li_d[338]
    DIRECTION INPUT ;
    USE SIGNAL ;
    PORT
      LAYER M4 ;
        RECT  0 124.368 0.084 124.392 ;
    END
  END li_d[338]
  PIN li_d[339]
    DIRECTION INPUT ;
    USE SIGNAL ;
    PORT
      LAYER M4 ;
        RECT  0 124.704 0.084 124.728 ;
    END
  END li_d[339]
  PIN li_d[33]
    DIRECTION INPUT ;
    USE SIGNAL ;
    PORT
      LAYER M4 ;
        RECT  0 27.888 0.084 27.912 ;
    END
  END li_d[33]
  PIN li_d[340]
    DIRECTION INPUT ;
    USE SIGNAL ;
    PORT
      LAYER M4 ;
        RECT  0 124.992 0.084 125.016 ;
    END
  END li_d[340]
  PIN li_d[341]
    DIRECTION INPUT ;
    USE SIGNAL ;
    PORT
      LAYER M4 ;
        RECT  0 125.328 0.084 125.352 ;
    END
  END li_d[341]
  PIN li_d[342]
    DIRECTION INPUT ;
    USE SIGNAL ;
    PORT
      LAYER M4 ;
        RECT  0 125.616 0.084 125.64 ;
    END
  END li_d[342]
  PIN li_d[343]
    DIRECTION INPUT ;
    USE SIGNAL ;
    PORT
      LAYER M4 ;
        RECT  0 125.952 0.084 125.976 ;
    END
  END li_d[343]
  PIN li_d[344]
    DIRECTION INPUT ;
    USE SIGNAL ;
    PORT
      LAYER M4 ;
        RECT  0 126.24 0.084 126.264 ;
    END
  END li_d[344]
  PIN li_d[345]
    DIRECTION INPUT ;
    USE SIGNAL ;
    PORT
      LAYER M4 ;
        RECT  0 126.576 0.084 126.6 ;
    END
  END li_d[345]
  PIN li_d[346]
    DIRECTION INPUT ;
    USE SIGNAL ;
    PORT
      LAYER M4 ;
        RECT  0 126.912 0.084 126.936 ;
    END
  END li_d[346]
  PIN li_d[347]
    DIRECTION INPUT ;
    USE SIGNAL ;
    PORT
      LAYER M4 ;
        RECT  0 127.2 0.084 127.224 ;
    END
  END li_d[347]
  PIN li_d[348]
    DIRECTION INPUT ;
    USE SIGNAL ;
    PORT
      LAYER M4 ;
        RECT  0 127.536 0.084 127.56 ;
    END
  END li_d[348]
  PIN li_d[349]
    DIRECTION INPUT ;
    USE SIGNAL ;
    PORT
      LAYER M4 ;
        RECT  0 127.824 0.084 127.848 ;
    END
  END li_d[349]
  PIN li_d[34]
    DIRECTION INPUT ;
    USE SIGNAL ;
    PORT
      LAYER M4 ;
        RECT  0 28.176 0.084 28.2 ;
    END
  END li_d[34]
  PIN li_d[350]
    DIRECTION INPUT ;
    USE SIGNAL ;
    PORT
      LAYER M4 ;
        RECT  0 128.16 0.084 128.184 ;
    END
  END li_d[350]
  PIN li_d[351]
    DIRECTION INPUT ;
    USE SIGNAL ;
    PORT
      LAYER M4 ;
        RECT  0 128.496 0.084 128.52 ;
    END
  END li_d[351]
  PIN li_d[352]
    DIRECTION INPUT ;
    USE SIGNAL ;
    PORT
      LAYER M4 ;
        RECT  0 128.784 0.084 128.808 ;
    END
  END li_d[352]
  PIN li_d[353]
    DIRECTION INPUT ;
    USE SIGNAL ;
    PORT
      LAYER M4 ;
        RECT  0 129.12 0.084 129.144 ;
    END
  END li_d[353]
  PIN li_d[354]
    DIRECTION INPUT ;
    USE SIGNAL ;
    PORT
      LAYER M4 ;
        RECT  0 129.408 0.084 129.432 ;
    END
  END li_d[354]
  PIN li_d[355]
    DIRECTION INPUT ;
    USE SIGNAL ;
    PORT
      LAYER M4 ;
        RECT  0 129.744 0.084 129.768 ;
    END
  END li_d[355]
  PIN li_d[356]
    DIRECTION INPUT ;
    USE SIGNAL ;
    PORT
      LAYER M4 ;
        RECT  0 130.08 0.084 130.104 ;
    END
  END li_d[356]
  PIN li_d[357]
    DIRECTION INPUT ;
    USE SIGNAL ;
    PORT
      LAYER M4 ;
        RECT  0 130.368 0.084 130.392 ;
    END
  END li_d[357]
  PIN li_d[358]
    DIRECTION INPUT ;
    USE SIGNAL ;
    PORT
      LAYER M4 ;
        RECT  0 130.704 0.084 130.728 ;
    END
  END li_d[358]
  PIN li_d[359]
    DIRECTION INPUT ;
    USE SIGNAL ;
    PORT
      LAYER M4 ;
        RECT  0 130.992 0.084 131.016 ;
    END
  END li_d[359]
  PIN li_d[35]
    DIRECTION INPUT ;
    USE SIGNAL ;
    PORT
      LAYER M4 ;
        RECT  0 28.512 0.084 28.536 ;
    END
  END li_d[35]
  PIN li_d[360]
    DIRECTION INPUT ;
    USE SIGNAL ;
    PORT
      LAYER M4 ;
        RECT  0 131.328 0.084 131.352 ;
    END
  END li_d[360]
  PIN li_d[361]
    DIRECTION INPUT ;
    USE SIGNAL ;
    PORT
      LAYER M4 ;
        RECT  0 131.664 0.084 131.688 ;
    END
  END li_d[361]
  PIN li_d[362]
    DIRECTION INPUT ;
    USE SIGNAL ;
    PORT
      LAYER M4 ;
        RECT  0 131.952 0.084 131.976 ;
    END
  END li_d[362]
  PIN li_d[363]
    DIRECTION INPUT ;
    USE SIGNAL ;
    PORT
      LAYER M4 ;
        RECT  0 132.288 0.084 132.312 ;
    END
  END li_d[363]
  PIN li_d[364]
    DIRECTION INPUT ;
    USE SIGNAL ;
    PORT
      LAYER M4 ;
        RECT  0 132.576 0.084 132.6 ;
    END
  END li_d[364]
  PIN li_d[365]
    DIRECTION INPUT ;
    USE SIGNAL ;
    PORT
      LAYER M4 ;
        RECT  0 132.912 0.084 132.936 ;
    END
  END li_d[365]
  PIN li_d[366]
    DIRECTION INPUT ;
    USE SIGNAL ;
    PORT
      LAYER M4 ;
        RECT  0 133.2 0.084 133.224 ;
    END
  END li_d[366]
  PIN li_d[367]
    DIRECTION INPUT ;
    USE SIGNAL ;
    PORT
      LAYER M4 ;
        RECT  0 133.536 0.084 133.56 ;
    END
  END li_d[367]
  PIN li_d[368]
    DIRECTION INPUT ;
    USE SIGNAL ;
    PORT
      LAYER M4 ;
        RECT  0 133.872 0.084 133.896 ;
    END
  END li_d[368]
  PIN li_d[369]
    DIRECTION INPUT ;
    USE SIGNAL ;
    PORT
      LAYER M4 ;
        RECT  0 134.16 0.084 134.184 ;
    END
  END li_d[369]
  PIN li_d[36]
    DIRECTION INPUT ;
    USE SIGNAL ;
    PORT
      LAYER M4 ;
        RECT  0 28.8 0.084 28.824 ;
    END
  END li_d[36]
  PIN li_d[370]
    DIRECTION INPUT ;
    USE SIGNAL ;
    PORT
      LAYER M4 ;
        RECT  0 134.496 0.084 134.52 ;
    END
  END li_d[370]
  PIN li_d[371]
    DIRECTION INPUT ;
    USE SIGNAL ;
    PORT
      LAYER M4 ;
        RECT  0 134.784 0.084 134.808 ;
    END
  END li_d[371]
  PIN li_d[372]
    DIRECTION INPUT ;
    USE SIGNAL ;
    PORT
      LAYER M4 ;
        RECT  0 135.12 0.084 135.144 ;
    END
  END li_d[372]
  PIN li_d[373]
    DIRECTION INPUT ;
    USE SIGNAL ;
    PORT
      LAYER M4 ;
        RECT  0 135.456 0.084 135.48 ;
    END
  END li_d[373]
  PIN li_d[374]
    DIRECTION INPUT ;
    USE SIGNAL ;
    PORT
      LAYER M4 ;
        RECT  0 135.744 0.084 135.768 ;
    END
  END li_d[374]
  PIN li_d[375]
    DIRECTION INPUT ;
    USE SIGNAL ;
    PORT
      LAYER M4 ;
        RECT  0 136.08 0.084 136.104 ;
    END
  END li_d[375]
  PIN li_d[376]
    DIRECTION INPUT ;
    USE SIGNAL ;
    PORT
      LAYER M4 ;
        RECT  0 136.368 0.084 136.392 ;
    END
  END li_d[376]
  PIN li_d[377]
    DIRECTION INPUT ;
    USE SIGNAL ;
    PORT
      LAYER M4 ;
        RECT  0 136.704 0.084 136.728 ;
    END
  END li_d[377]
  PIN li_d[378]
    DIRECTION INPUT ;
    USE SIGNAL ;
    PORT
      LAYER M4 ;
        RECT  0 137.04 0.084 137.064 ;
    END
  END li_d[378]
  PIN li_d[379]
    DIRECTION INPUT ;
    USE SIGNAL ;
    PORT
      LAYER M4 ;
        RECT  0 137.328 0.084 137.352 ;
    END
  END li_d[379]
  PIN li_d[37]
    DIRECTION INPUT ;
    USE SIGNAL ;
    PORT
      LAYER M4 ;
        RECT  0 29.136 0.084 29.16 ;
    END
  END li_d[37]
  PIN li_d[380]
    DIRECTION INPUT ;
    USE SIGNAL ;
    PORT
      LAYER M4 ;
        RECT  0 137.664 0.084 137.688 ;
    END
  END li_d[380]
  PIN li_d[381]
    DIRECTION INPUT ;
    USE SIGNAL ;
    PORT
      LAYER M4 ;
        RECT  0 137.952 0.084 137.976 ;
    END
  END li_d[381]
  PIN li_d[382]
    DIRECTION INPUT ;
    USE SIGNAL ;
    PORT
      LAYER M4 ;
        RECT  0 138.288 0.084 138.312 ;
    END
  END li_d[382]
  PIN li_d[383]
    DIRECTION INPUT ;
    USE SIGNAL ;
    PORT
      LAYER M4 ;
        RECT  0 138.624 0.084 138.648 ;
    END
  END li_d[383]
  PIN li_d[384]
    DIRECTION INPUT ;
    USE SIGNAL ;
    PORT
      LAYER M4 ;
        RECT  0 138.912 0.084 138.936 ;
    END
  END li_d[384]
  PIN li_d[385]
    DIRECTION INPUT ;
    USE SIGNAL ;
    PORT
      LAYER M4 ;
        RECT  0 139.248 0.084 139.272 ;
    END
  END li_d[385]
  PIN li_d[386]
    DIRECTION INPUT ;
    USE SIGNAL ;
    PORT
      LAYER M4 ;
        RECT  0 139.536 0.084 139.56 ;
    END
  END li_d[386]
  PIN li_d[387]
    DIRECTION INPUT ;
    USE SIGNAL ;
    PORT
      LAYER M4 ;
        RECT  0 139.872 0.084 139.896 ;
    END
  END li_d[387]
  PIN li_d[388]
    DIRECTION INPUT ;
    USE SIGNAL ;
    PORT
      LAYER M4 ;
        RECT  0 140.16 0.084 140.184 ;
    END
  END li_d[388]
  PIN li_d[389]
    DIRECTION INPUT ;
    USE SIGNAL ;
    PORT
      LAYER M4 ;
        RECT  0 140.496 0.084 140.52 ;
    END
  END li_d[389]
  PIN li_d[38]
    DIRECTION INPUT ;
    USE SIGNAL ;
    PORT
      LAYER M4 ;
        RECT  0 29.472 0.084 29.496 ;
    END
  END li_d[38]
  PIN li_d[390]
    DIRECTION INPUT ;
    USE SIGNAL ;
    PORT
      LAYER M4 ;
        RECT  0 140.832 0.084 140.856 ;
    END
  END li_d[390]
  PIN li_d[391]
    DIRECTION INPUT ;
    USE SIGNAL ;
    PORT
      LAYER M4 ;
        RECT  0 141.12 0.084 141.144 ;
    END
  END li_d[391]
  PIN li_d[392]
    DIRECTION INPUT ;
    USE SIGNAL ;
    PORT
      LAYER M4 ;
        RECT  0 141.456 0.084 141.48 ;
    END
  END li_d[392]
  PIN li_d[393]
    DIRECTION INPUT ;
    USE SIGNAL ;
    PORT
      LAYER M4 ;
        RECT  0 141.744 0.084 141.768 ;
    END
  END li_d[393]
  PIN li_d[394]
    DIRECTION INPUT ;
    USE SIGNAL ;
    PORT
      LAYER M4 ;
        RECT  0 142.08 0.084 142.104 ;
    END
  END li_d[394]
  PIN li_d[395]
    DIRECTION INPUT ;
    USE SIGNAL ;
    PORT
      LAYER M4 ;
        RECT  0 142.416 0.084 142.44 ;
    END
  END li_d[395]
  PIN li_d[396]
    DIRECTION INPUT ;
    USE SIGNAL ;
    PORT
      LAYER M4 ;
        RECT  0 142.704 0.084 142.728 ;
    END
  END li_d[396]
  PIN li_d[397]
    DIRECTION INPUT ;
    USE SIGNAL ;
    PORT
      LAYER M4 ;
        RECT  0 143.04 0.084 143.064 ;
    END
  END li_d[397]
  PIN li_d[398]
    DIRECTION INPUT ;
    USE SIGNAL ;
    PORT
      LAYER M4 ;
        RECT  0 143.328 0.084 143.352 ;
    END
  END li_d[398]
  PIN li_d[399]
    DIRECTION INPUT ;
    USE SIGNAL ;
    PORT
      LAYER M4 ;
        RECT  0 143.664 0.084 143.688 ;
    END
  END li_d[399]
  PIN li_d[39]
    DIRECTION INPUT ;
    USE SIGNAL ;
    PORT
      LAYER M4 ;
        RECT  0 29.76 0.084 29.784 ;
    END
  END li_d[39]
  PIN li_d[3]
    DIRECTION INPUT ;
    USE SIGNAL ;
    PORT
      LAYER M4 ;
        RECT  0 18.384 0.084 18.408 ;
    END
  END li_d[3]
  PIN li_d[400]
    DIRECTION INPUT ;
    USE SIGNAL ;
    PORT
      LAYER M4 ;
        RECT  0 144 0.084 144.024 ;
    END
  END li_d[400]
  PIN li_d[401]
    DIRECTION INPUT ;
    USE SIGNAL ;
    PORT
      LAYER M4 ;
        RECT  0 144.288 0.084 144.312 ;
    END
  END li_d[401]
  PIN li_d[402]
    DIRECTION INPUT ;
    USE SIGNAL ;
    PORT
      LAYER M4 ;
        RECT  0 144.624 0.084 144.648 ;
    END
  END li_d[402]
  PIN li_d[403]
    DIRECTION INPUT ;
    USE SIGNAL ;
    PORT
      LAYER M4 ;
        RECT  0 144.912 0.084 144.936 ;
    END
  END li_d[403]
  PIN li_d[404]
    DIRECTION INPUT ;
    USE SIGNAL ;
    PORT
      LAYER M4 ;
        RECT  0 145.248 0.084 145.272 ;
    END
  END li_d[404]
  PIN li_d[405]
    DIRECTION INPUT ;
    USE SIGNAL ;
    PORT
      LAYER M4 ;
        RECT  0 145.584 0.084 145.608 ;
    END
  END li_d[405]
  PIN li_d[406]
    DIRECTION INPUT ;
    USE SIGNAL ;
    PORT
      LAYER M4 ;
        RECT  0 145.872 0.084 145.896 ;
    END
  END li_d[406]
  PIN li_d[407]
    DIRECTION INPUT ;
    USE SIGNAL ;
    PORT
      LAYER M4 ;
        RECT  0 146.208 0.084 146.232 ;
    END
  END li_d[407]
  PIN li_d[408]
    DIRECTION INPUT ;
    USE SIGNAL ;
    PORT
      LAYER M4 ;
        RECT  0 146.496 0.084 146.52 ;
    END
  END li_d[408]
  PIN li_d[409]
    DIRECTION INPUT ;
    USE SIGNAL ;
    PORT
      LAYER M4 ;
        RECT  0 146.832 0.084 146.856 ;
    END
  END li_d[409]
  PIN li_d[40]
    DIRECTION INPUT ;
    USE SIGNAL ;
    PORT
      LAYER M4 ;
        RECT  0 30.096 0.084 30.12 ;
    END
  END li_d[40]
  PIN li_d[410]
    DIRECTION INPUT ;
    USE SIGNAL ;
    PORT
      LAYER M4 ;
        RECT  0 147.12 0.084 147.144 ;
    END
  END li_d[410]
  PIN li_d[411]
    DIRECTION INPUT ;
    USE SIGNAL ;
    PORT
      LAYER M4 ;
        RECT  0 147.456 0.084 147.48 ;
    END
  END li_d[411]
  PIN li_d[412]
    DIRECTION INPUT ;
    USE SIGNAL ;
    PORT
      LAYER M4 ;
        RECT  0 147.792 0.084 147.816 ;
    END
  END li_d[412]
  PIN li_d[413]
    DIRECTION INPUT ;
    USE SIGNAL ;
    PORT
      LAYER M4 ;
        RECT  0 148.08 0.084 148.104 ;
    END
  END li_d[413]
  PIN li_d[414]
    DIRECTION INPUT ;
    USE SIGNAL ;
    PORT
      LAYER M4 ;
        RECT  0 148.416 0.084 148.44 ;
    END
  END li_d[414]
  PIN li_d[415]
    DIRECTION INPUT ;
    USE SIGNAL ;
    PORT
      LAYER M4 ;
        RECT  0 148.704 0.084 148.728 ;
    END
  END li_d[415]
  PIN li_d[416]
    DIRECTION INPUT ;
    USE SIGNAL ;
    PORT
      LAYER M4 ;
        RECT  0 149.04 0.084 149.064 ;
    END
  END li_d[416]
  PIN li_d[417]
    DIRECTION INPUT ;
    USE SIGNAL ;
    PORT
      LAYER M4 ;
        RECT  0 149.376 0.084 149.4 ;
    END
  END li_d[417]
  PIN li_d[418]
    DIRECTION INPUT ;
    USE SIGNAL ;
    PORT
      LAYER M4 ;
        RECT  0 149.664 0.084 149.688 ;
    END
  END li_d[418]
  PIN li_d[419]
    DIRECTION INPUT ;
    USE SIGNAL ;
    PORT
      LAYER M4 ;
        RECT  0 150 0.084 150.024 ;
    END
  END li_d[419]
  PIN li_d[41]
    DIRECTION INPUT ;
    USE SIGNAL ;
    PORT
      LAYER M4 ;
        RECT  0 30.384 0.084 30.408 ;
    END
  END li_d[41]
  PIN li_d[420]
    DIRECTION INPUT ;
    USE SIGNAL ;
    PORT
      LAYER M4 ;
        RECT  0 150.288 0.084 150.312 ;
    END
  END li_d[420]
  PIN li_d[421]
    DIRECTION INPUT ;
    USE SIGNAL ;
    PORT
      LAYER M4 ;
        RECT  0 150.624 0.084 150.648 ;
    END
  END li_d[421]
  PIN li_d[422]
    DIRECTION INPUT ;
    USE SIGNAL ;
    PORT
      LAYER M4 ;
        RECT  0 150.96 0.084 150.984 ;
    END
  END li_d[422]
  PIN li_d[423]
    DIRECTION INPUT ;
    USE SIGNAL ;
    PORT
      LAYER M4 ;
        RECT  0 151.248 0.084 151.272 ;
    END
  END li_d[423]
  PIN li_d[424]
    DIRECTION INPUT ;
    USE SIGNAL ;
    PORT
      LAYER M4 ;
        RECT  0 151.584 0.084 151.608 ;
    END
  END li_d[424]
  PIN li_d[425]
    DIRECTION INPUT ;
    USE SIGNAL ;
    PORT
      LAYER M4 ;
        RECT  0 151.872 0.084 151.896 ;
    END
  END li_d[425]
  PIN li_d[426]
    DIRECTION INPUT ;
    USE SIGNAL ;
    PORT
      LAYER M4 ;
        RECT  0 152.208 0.084 152.232 ;
    END
  END li_d[426]
  PIN li_d[427]
    DIRECTION INPUT ;
    USE SIGNAL ;
    PORT
      LAYER M4 ;
        RECT  0 152.544 0.084 152.568 ;
    END
  END li_d[427]
  PIN li_d[428]
    DIRECTION INPUT ;
    USE SIGNAL ;
    PORT
      LAYER M4 ;
        RECT  0 152.832 0.084 152.856 ;
    END
  END li_d[428]
  PIN li_d[429]
    DIRECTION INPUT ;
    USE SIGNAL ;
    PORT
      LAYER M4 ;
        RECT  0 153.168 0.084 153.192 ;
    END
  END li_d[429]
  PIN li_d[42]
    DIRECTION INPUT ;
    USE SIGNAL ;
    PORT
      LAYER M4 ;
        RECT  0 30.72 0.084 30.744 ;
    END
  END li_d[42]
  PIN li_d[430]
    DIRECTION INPUT ;
    USE SIGNAL ;
    PORT
      LAYER M4 ;
        RECT  0 153.456 0.084 153.48 ;
    END
  END li_d[430]
  PIN li_d[431]
    DIRECTION INPUT ;
    USE SIGNAL ;
    PORT
      LAYER M4 ;
        RECT  0 153.792 0.084 153.816 ;
    END
  END li_d[431]
  PIN li_d[432]
    DIRECTION INPUT ;
    USE SIGNAL ;
    PORT
      LAYER M4 ;
        RECT  0 154.128 0.084 154.152 ;
    END
  END li_d[432]
  PIN li_d[433]
    DIRECTION INPUT ;
    USE SIGNAL ;
    PORT
      LAYER M4 ;
        RECT  0 154.416 0.084 154.44 ;
    END
  END li_d[433]
  PIN li_d[434]
    DIRECTION INPUT ;
    USE SIGNAL ;
    PORT
      LAYER M4 ;
        RECT  0 154.752 0.084 154.776 ;
    END
  END li_d[434]
  PIN li_d[435]
    DIRECTION INPUT ;
    USE SIGNAL ;
    PORT
      LAYER M4 ;
        RECT  0 155.04 0.084 155.064 ;
    END
  END li_d[435]
  PIN li_d[436]
    DIRECTION INPUT ;
    USE SIGNAL ;
    PORT
      LAYER M4 ;
        RECT  0 155.376 0.084 155.4 ;
    END
  END li_d[436]
  PIN li_d[437]
    DIRECTION INPUT ;
    USE SIGNAL ;
    PORT
      LAYER M4 ;
        RECT  0 155.664 0.084 155.688 ;
    END
  END li_d[437]
  PIN li_d[438]
    DIRECTION INPUT ;
    USE SIGNAL ;
    PORT
      LAYER M4 ;
        RECT  0 156 0.084 156.024 ;
    END
  END li_d[438]
  PIN li_d[439]
    DIRECTION INPUT ;
    USE SIGNAL ;
    PORT
      LAYER M4 ;
        RECT  0 156.336 0.084 156.36 ;
    END
  END li_d[439]
  PIN li_d[43]
    DIRECTION INPUT ;
    USE SIGNAL ;
    PORT
      LAYER M4 ;
        RECT  0 31.008 0.084 31.032 ;
    END
  END li_d[43]
  PIN li_d[440]
    DIRECTION INPUT ;
    USE SIGNAL ;
    PORT
      LAYER M4 ;
        RECT  0 156.624 0.084 156.648 ;
    END
  END li_d[440]
  PIN li_d[441]
    DIRECTION INPUT ;
    USE SIGNAL ;
    PORT
      LAYER M4 ;
        RECT  0 156.96 0.084 156.984 ;
    END
  END li_d[441]
  PIN li_d[442]
    DIRECTION INPUT ;
    USE SIGNAL ;
    PORT
      LAYER M4 ;
        RECT  0 157.248 0.084 157.272 ;
    END
  END li_d[442]
  PIN li_d[443]
    DIRECTION INPUT ;
    USE SIGNAL ;
    PORT
      LAYER M4 ;
        RECT  0 157.584 0.084 157.608 ;
    END
  END li_d[443]
  PIN li_d[444]
    DIRECTION INPUT ;
    USE SIGNAL ;
    PORT
      LAYER M4 ;
        RECT  0 157.92 0.084 157.944 ;
    END
  END li_d[444]
  PIN li_d[445]
    DIRECTION INPUT ;
    USE SIGNAL ;
    PORT
      LAYER M4 ;
        RECT  0 158.208 0.084 158.232 ;
    END
  END li_d[445]
  PIN li_d[446]
    DIRECTION INPUT ;
    USE SIGNAL ;
    PORT
      LAYER M4 ;
        RECT  0 158.544 0.084 158.568 ;
    END
  END li_d[446]
  PIN li_d[447]
    DIRECTION INPUT ;
    USE SIGNAL ;
    PORT
      LAYER M4 ;
        RECT  0 158.832 0.084 158.856 ;
    END
  END li_d[447]
  PIN li_d[448]
    DIRECTION INPUT ;
    USE SIGNAL ;
    PORT
      LAYER M4 ;
        RECT  0 159.168 0.084 159.192 ;
    END
  END li_d[448]
  PIN li_d[449]
    DIRECTION INPUT ;
    USE SIGNAL ;
    PORT
      LAYER M4 ;
        RECT  0 159.504 0.084 159.528 ;
    END
  END li_d[449]
  PIN li_d[44]
    DIRECTION INPUT ;
    USE SIGNAL ;
    PORT
      LAYER M4 ;
        RECT  0 31.344 0.084 31.368 ;
    END
  END li_d[44]
  PIN li_d[450]
    DIRECTION INPUT ;
    USE SIGNAL ;
    PORT
      LAYER M4 ;
        RECT  0 159.792 0.084 159.816 ;
    END
  END li_d[450]
  PIN li_d[451]
    DIRECTION INPUT ;
    USE SIGNAL ;
    PORT
      LAYER M4 ;
        RECT  0 160.128 0.084 160.152 ;
    END
  END li_d[451]
  PIN li_d[452]
    DIRECTION INPUT ;
    USE SIGNAL ;
    PORT
      LAYER M4 ;
        RECT  0 160.416 0.084 160.44 ;
    END
  END li_d[452]
  PIN li_d[453]
    DIRECTION INPUT ;
    USE SIGNAL ;
    PORT
      LAYER M4 ;
        RECT  0 160.752 0.084 160.776 ;
    END
  END li_d[453]
  PIN li_d[454]
    DIRECTION INPUT ;
    USE SIGNAL ;
    PORT
      LAYER M4 ;
        RECT  0 161.088 0.084 161.112 ;
    END
  END li_d[454]
  PIN li_d[455]
    DIRECTION INPUT ;
    USE SIGNAL ;
    PORT
      LAYER M4 ;
        RECT  0 161.376 0.084 161.4 ;
    END
  END li_d[455]
  PIN li_d[456]
    DIRECTION INPUT ;
    USE SIGNAL ;
    PORT
      LAYER M4 ;
        RECT  0 161.712 0.084 161.736 ;
    END
  END li_d[456]
  PIN li_d[457]
    DIRECTION INPUT ;
    USE SIGNAL ;
    PORT
      LAYER M4 ;
        RECT  0 162 0.084 162.024 ;
    END
  END li_d[457]
  PIN li_d[458]
    DIRECTION INPUT ;
    USE SIGNAL ;
    PORT
      LAYER M4 ;
        RECT  0 162.336 0.084 162.36 ;
    END
  END li_d[458]
  PIN li_d[459]
    DIRECTION INPUT ;
    USE SIGNAL ;
    PORT
      LAYER M4 ;
        RECT  0 162.624 0.084 162.648 ;
    END
  END li_d[459]
  PIN li_d[45]
    DIRECTION INPUT ;
    USE SIGNAL ;
    PORT
      LAYER M4 ;
        RECT  0 31.68 0.084 31.704 ;
    END
  END li_d[45]
  PIN li_d[460]
    DIRECTION INPUT ;
    USE SIGNAL ;
    PORT
      LAYER M4 ;
        RECT  0 162.96 0.084 162.984 ;
    END
  END li_d[460]
  PIN li_d[461]
    DIRECTION INPUT ;
    USE SIGNAL ;
    PORT
      LAYER M4 ;
        RECT  0 163.296 0.084 163.32 ;
    END
  END li_d[461]
  PIN li_d[462]
    DIRECTION INPUT ;
    USE SIGNAL ;
    PORT
      LAYER M4 ;
        RECT  0 163.584 0.084 163.608 ;
    END
  END li_d[462]
  PIN li_d[463]
    DIRECTION INPUT ;
    USE SIGNAL ;
    PORT
      LAYER M4 ;
        RECT  0 163.92 0.084 163.944 ;
    END
  END li_d[463]
  PIN li_d[464]
    DIRECTION INPUT ;
    USE SIGNAL ;
    PORT
      LAYER M4 ;
        RECT  0 164.208 0.084 164.232 ;
    END
  END li_d[464]
  PIN li_d[465]
    DIRECTION INPUT ;
    USE SIGNAL ;
    PORT
      LAYER M4 ;
        RECT  0 164.544 0.084 164.568 ;
    END
  END li_d[465]
  PIN li_d[466]
    DIRECTION INPUT ;
    USE SIGNAL ;
    PORT
      LAYER M4 ;
        RECT  0 164.88 0.084 164.904 ;
    END
  END li_d[466]
  PIN li_d[467]
    DIRECTION INPUT ;
    USE SIGNAL ;
    PORT
      LAYER M4 ;
        RECT  0 165.168 0.084 165.192 ;
    END
  END li_d[467]
  PIN li_d[468]
    DIRECTION INPUT ;
    USE SIGNAL ;
    PORT
      LAYER M4 ;
        RECT  0 165.504 0.084 165.528 ;
    END
  END li_d[468]
  PIN li_d[469]
    DIRECTION INPUT ;
    USE SIGNAL ;
    PORT
      LAYER M4 ;
        RECT  0 165.792 0.084 165.816 ;
    END
  END li_d[469]
  PIN li_d[46]
    DIRECTION INPUT ;
    USE SIGNAL ;
    PORT
      LAYER M4 ;
        RECT  0 31.968 0.084 31.992 ;
    END
  END li_d[46]
  PIN li_d[470]
    DIRECTION INPUT ;
    USE SIGNAL ;
    PORT
      LAYER M4 ;
        RECT  0 166.128 0.084 166.152 ;
    END
  END li_d[470]
  PIN li_d[471]
    DIRECTION INPUT ;
    USE SIGNAL ;
    PORT
      LAYER M4 ;
        RECT  0 166.464 0.084 166.488 ;
    END
  END li_d[471]
  PIN li_d[472]
    DIRECTION INPUT ;
    USE SIGNAL ;
    PORT
      LAYER M4 ;
        RECT  0 166.752 0.084 166.776 ;
    END
  END li_d[472]
  PIN li_d[473]
    DIRECTION INPUT ;
    USE SIGNAL ;
    PORT
      LAYER M4 ;
        RECT  0 167.088 0.084 167.112 ;
    END
  END li_d[473]
  PIN li_d[474]
    DIRECTION INPUT ;
    USE SIGNAL ;
    PORT
      LAYER M4 ;
        RECT  0 167.376 0.084 167.4 ;
    END
  END li_d[474]
  PIN li_d[475]
    DIRECTION INPUT ;
    USE SIGNAL ;
    PORT
      LAYER M4 ;
        RECT  0 167.712 0.084 167.736 ;
    END
  END li_d[475]
  PIN li_d[476]
    DIRECTION INPUT ;
    USE SIGNAL ;
    PORT
      LAYER M4 ;
        RECT  0 168.048 0.084 168.072 ;
    END
  END li_d[476]
  PIN li_d[477]
    DIRECTION INPUT ;
    USE SIGNAL ;
    PORT
      LAYER M4 ;
        RECT  0 168.336 0.084 168.36 ;
    END
  END li_d[477]
  PIN li_d[478]
    DIRECTION INPUT ;
    USE SIGNAL ;
    PORT
      LAYER M4 ;
        RECT  0 168.672 0.084 168.696 ;
    END
  END li_d[478]
  PIN li_d[479]
    DIRECTION INPUT ;
    USE SIGNAL ;
    PORT
      LAYER M4 ;
        RECT  0 168.96 0.084 168.984 ;
    END
  END li_d[479]
  PIN li_d[47]
    DIRECTION INPUT ;
    USE SIGNAL ;
    PORT
      LAYER M4 ;
        RECT  0 32.304 0.084 32.328 ;
    END
  END li_d[47]
  PIN li_d[480]
    DIRECTION INPUT ;
    USE SIGNAL ;
    PORT
      LAYER M4 ;
        RECT  0 169.296 0.084 169.32 ;
    END
  END li_d[480]
  PIN li_d[481]
    DIRECTION INPUT ;
    USE SIGNAL ;
    PORT
      LAYER M4 ;
        RECT  0 169.584 0.084 169.608 ;
    END
  END li_d[481]
  PIN li_d[482]
    DIRECTION INPUT ;
    USE SIGNAL ;
    PORT
      LAYER M4 ;
        RECT  0 169.92 0.084 169.944 ;
    END
  END li_d[482]
  PIN li_d[483]
    DIRECTION INPUT ;
    USE SIGNAL ;
    PORT
      LAYER M4 ;
        RECT  0 170.256 0.084 170.28 ;
    END
  END li_d[483]
  PIN li_d[484]
    DIRECTION INPUT ;
    USE SIGNAL ;
    PORT
      LAYER M4 ;
        RECT  0 170.544 0.084 170.568 ;
    END
  END li_d[484]
  PIN li_d[485]
    DIRECTION INPUT ;
    USE SIGNAL ;
    PORT
      LAYER M4 ;
        RECT  0 170.88 0.084 170.904 ;
    END
  END li_d[485]
  PIN li_d[486]
    DIRECTION INPUT ;
    USE SIGNAL ;
    PORT
      LAYER M4 ;
        RECT  0 171.168 0.084 171.192 ;
    END
  END li_d[486]
  PIN li_d[487]
    DIRECTION INPUT ;
    USE SIGNAL ;
    PORT
      LAYER M4 ;
        RECT  0 171.504 0.084 171.528 ;
    END
  END li_d[487]
  PIN li_d[488]
    DIRECTION INPUT ;
    USE SIGNAL ;
    PORT
      LAYER M4 ;
        RECT  0 171.84 0.084 171.864 ;
    END
  END li_d[488]
  PIN li_d[489]
    DIRECTION INPUT ;
    USE SIGNAL ;
    PORT
      LAYER M4 ;
        RECT  0 172.128 0.084 172.152 ;
    END
  END li_d[489]
  PIN li_d[48]
    DIRECTION INPUT ;
    USE SIGNAL ;
    PORT
      LAYER M4 ;
        RECT  0 32.592 0.084 32.616 ;
    END
  END li_d[48]
  PIN li_d[490]
    DIRECTION INPUT ;
    USE SIGNAL ;
    PORT
      LAYER M4 ;
        RECT  0 172.464 0.084 172.488 ;
    END
  END li_d[490]
  PIN li_d[491]
    DIRECTION INPUT ;
    USE SIGNAL ;
    PORT
      LAYER M4 ;
        RECT  0 172.752 0.084 172.776 ;
    END
  END li_d[491]
  PIN li_d[492]
    DIRECTION INPUT ;
    USE SIGNAL ;
    PORT
      LAYER M4 ;
        RECT  0 173.088 0.084 173.112 ;
    END
  END li_d[492]
  PIN li_d[493]
    DIRECTION INPUT ;
    USE SIGNAL ;
    PORT
      LAYER M4 ;
        RECT  0 173.424 0.084 173.448 ;
    END
  END li_d[493]
  PIN li_d[494]
    DIRECTION INPUT ;
    USE SIGNAL ;
    PORT
      LAYER M4 ;
        RECT  0 173.712 0.084 173.736 ;
    END
  END li_d[494]
  PIN li_d[495]
    DIRECTION INPUT ;
    USE SIGNAL ;
    PORT
      LAYER M4 ;
        RECT  0 174.048 0.084 174.072 ;
    END
  END li_d[495]
  PIN li_d[496]
    DIRECTION INPUT ;
    USE SIGNAL ;
    PORT
      LAYER M4 ;
        RECT  0 174.336 0.084 174.36 ;
    END
  END li_d[496]
  PIN li_d[497]
    DIRECTION INPUT ;
    USE SIGNAL ;
    PORT
      LAYER M4 ;
        RECT  0 174.672 0.084 174.696 ;
    END
  END li_d[497]
  PIN li_d[498]
    DIRECTION INPUT ;
    USE SIGNAL ;
    PORT
      LAYER M4 ;
        RECT  0 175.008 0.084 175.032 ;
    END
  END li_d[498]
  PIN li_d[499]
    DIRECTION INPUT ;
    USE SIGNAL ;
    PORT
      LAYER M4 ;
        RECT  0 175.296 0.084 175.32 ;
    END
  END li_d[499]
  PIN li_d[49]
    DIRECTION INPUT ;
    USE SIGNAL ;
    PORT
      LAYER M4 ;
        RECT  0 32.928 0.084 32.952 ;
    END
  END li_d[49]
  PIN li_d[4]
    DIRECTION INPUT ;
    USE SIGNAL ;
    PORT
      LAYER M4 ;
        RECT  0 18.672 0.084 18.696 ;
    END
  END li_d[4]
  PIN li_d[500]
    DIRECTION INPUT ;
    USE SIGNAL ;
    PORT
      LAYER M4 ;
        RECT  0 175.632 0.084 175.656 ;
    END
  END li_d[500]
  PIN li_d[501]
    DIRECTION INPUT ;
    USE SIGNAL ;
    PORT
      LAYER M4 ;
        RECT  0 175.92 0.084 175.944 ;
    END
  END li_d[501]
  PIN li_d[502]
    DIRECTION INPUT ;
    USE SIGNAL ;
    PORT
      LAYER M4 ;
        RECT  0 176.256 0.084 176.28 ;
    END
  END li_d[502]
  PIN li_d[503]
    DIRECTION INPUT ;
    USE SIGNAL ;
    PORT
      LAYER M4 ;
        RECT  0 176.544 0.084 176.568 ;
    END
  END li_d[503]
  PIN li_d[504]
    DIRECTION INPUT ;
    USE SIGNAL ;
    PORT
      LAYER M4 ;
        RECT  0 176.88 0.084 176.904 ;
    END
  END li_d[504]
  PIN li_d[505]
    DIRECTION INPUT ;
    USE SIGNAL ;
    PORT
      LAYER M4 ;
        RECT  0 177.216 0.084 177.24 ;
    END
  END li_d[505]
  PIN li_d[506]
    DIRECTION INPUT ;
    USE SIGNAL ;
    PORT
      LAYER M4 ;
        RECT  0 177.504 0.084 177.528 ;
    END
  END li_d[506]
  PIN li_d[507]
    DIRECTION INPUT ;
    USE SIGNAL ;
    PORT
      LAYER M4 ;
        RECT  0 177.84 0.084 177.864 ;
    END
  END li_d[507]
  PIN li_d[508]
    DIRECTION INPUT ;
    USE SIGNAL ;
    PORT
      LAYER M4 ;
        RECT  0 178.128 0.084 178.152 ;
    END
  END li_d[508]
  PIN li_d[509]
    DIRECTION INPUT ;
    USE SIGNAL ;
    PORT
      LAYER M4 ;
        RECT  0 178.464 0.084 178.488 ;
    END
  END li_d[509]
  PIN li_d[50]
    DIRECTION INPUT ;
    USE SIGNAL ;
    PORT
      LAYER M4 ;
        RECT  0 33.264 0.084 33.288 ;
    END
  END li_d[50]
  PIN li_d[510]
    DIRECTION INPUT ;
    USE SIGNAL ;
    PORT
      LAYER M4 ;
        RECT  0 178.8 0.084 178.824 ;
    END
  END li_d[510]
  PIN li_d[511]
    DIRECTION INPUT ;
    USE SIGNAL ;
    PORT
      LAYER M4 ;
        RECT  0 179.088 0.084 179.112 ;
    END
  END li_d[511]
  PIN li_d[512]
    DIRECTION INPUT ;
    USE SIGNAL ;
    PORT
      LAYER M4 ;
        RECT  0 179.424 0.084 179.448 ;
    END
  END li_d[512]
  PIN li_d[513]
    DIRECTION INPUT ;
    USE SIGNAL ;
    PORT
      LAYER M4 ;
        RECT  0 179.712 0.084 179.736 ;
    END
  END li_d[513]
  PIN li_d[514]
    DIRECTION INPUT ;
    USE SIGNAL ;
    PORT
      LAYER M4 ;
        RECT  0 180.048 0.084 180.072 ;
    END
  END li_d[514]
  PIN li_d[515]
    DIRECTION INPUT ;
    USE SIGNAL ;
    PORT
      LAYER M4 ;
        RECT  0 180.384 0.084 180.408 ;
    END
  END li_d[515]
  PIN li_d[516]
    DIRECTION INPUT ;
    USE SIGNAL ;
    PORT
      LAYER M4 ;
        RECT  0 180.672 0.084 180.696 ;
    END
  END li_d[516]
  PIN li_d[517]
    DIRECTION INPUT ;
    USE SIGNAL ;
    PORT
      LAYER M4 ;
        RECT  0 181.008 0.084 181.032 ;
    END
  END li_d[517]
  PIN li_d[518]
    DIRECTION INPUT ;
    USE SIGNAL ;
    PORT
      LAYER M4 ;
        RECT  0 181.296 0.084 181.32 ;
    END
  END li_d[518]
  PIN li_d[519]
    DIRECTION INPUT ;
    USE SIGNAL ;
    PORT
      LAYER M4 ;
        RECT  0 181.632 0.084 181.656 ;
    END
  END li_d[519]
  PIN li_d[51]
    DIRECTION INPUT ;
    USE SIGNAL ;
    PORT
      LAYER M4 ;
        RECT  0 33.552 0.084 33.576 ;
    END
  END li_d[51]
  PIN li_d[520]
    DIRECTION INPUT ;
    USE SIGNAL ;
    PORT
      LAYER M4 ;
        RECT  0 181.968 0.084 181.992 ;
    END
  END li_d[520]
  PIN li_d[521]
    DIRECTION INPUT ;
    USE SIGNAL ;
    PORT
      LAYER M4 ;
        RECT  0 182.256 0.084 182.28 ;
    END
  END li_d[521]
  PIN li_d[522]
    DIRECTION INPUT ;
    USE SIGNAL ;
    PORT
      LAYER M4 ;
        RECT  0 182.592 0.084 182.616 ;
    END
  END li_d[522]
  PIN li_d[523]
    DIRECTION INPUT ;
    USE SIGNAL ;
    PORT
      LAYER M4 ;
        RECT  0 182.88 0.084 182.904 ;
    END
  END li_d[523]
  PIN li_d[524]
    DIRECTION INPUT ;
    USE SIGNAL ;
    PORT
      LAYER M4 ;
        RECT  0 183.216 0.084 183.24 ;
    END
  END li_d[524]
  PIN li_d[525]
    DIRECTION INPUT ;
    USE SIGNAL ;
    PORT
      LAYER M4 ;
        RECT  0 183.504 0.084 183.528 ;
    END
  END li_d[525]
  PIN li_d[526]
    DIRECTION INPUT ;
    USE SIGNAL ;
    PORT
      LAYER M4 ;
        RECT  0 183.84 0.084 183.864 ;
    END
  END li_d[526]
  PIN li_d[527]
    DIRECTION INPUT ;
    USE SIGNAL ;
    PORT
      LAYER M4 ;
        RECT  0 184.176 0.084 184.2 ;
    END
  END li_d[527]
  PIN li_d[528]
    DIRECTION INPUT ;
    USE SIGNAL ;
    PORT
      LAYER M4 ;
        RECT  0 184.464 0.084 184.488 ;
    END
  END li_d[528]
  PIN li_d[529]
    DIRECTION INPUT ;
    USE SIGNAL ;
    PORT
      LAYER M4 ;
        RECT  0 184.8 0.084 184.824 ;
    END
  END li_d[529]
  PIN li_d[52]
    DIRECTION INPUT ;
    USE SIGNAL ;
    PORT
      LAYER M4 ;
        RECT  0 33.888 0.084 33.912 ;
    END
  END li_d[52]
  PIN li_d[530]
    DIRECTION INPUT ;
    USE SIGNAL ;
    PORT
      LAYER M4 ;
        RECT  0 185.088 0.084 185.112 ;
    END
  END li_d[530]
  PIN li_d[531]
    DIRECTION INPUT ;
    USE SIGNAL ;
    PORT
      LAYER M4 ;
        RECT  0 185.424 0.084 185.448 ;
    END
  END li_d[531]
  PIN li_d[532]
    DIRECTION INPUT ;
    USE SIGNAL ;
    PORT
      LAYER M4 ;
        RECT  0 185.76 0.084 185.784 ;
    END
  END li_d[532]
  PIN li_d[533]
    DIRECTION INPUT ;
    USE SIGNAL ;
    PORT
      LAYER M4 ;
        RECT  0 186.048 0.084 186.072 ;
    END
  END li_d[533]
  PIN li_d[534]
    DIRECTION INPUT ;
    USE SIGNAL ;
    PORT
      LAYER M4 ;
        RECT  0 186.384 0.084 186.408 ;
    END
  END li_d[534]
  PIN li_d[535]
    DIRECTION INPUT ;
    USE SIGNAL ;
    PORT
      LAYER M4 ;
        RECT  0 186.672 0.084 186.696 ;
    END
  END li_d[535]
  PIN li_d[536]
    DIRECTION INPUT ;
    USE SIGNAL ;
    PORT
      LAYER M4 ;
        RECT  0 187.008 0.084 187.032 ;
    END
  END li_d[536]
  PIN li_d[537]
    DIRECTION INPUT ;
    USE SIGNAL ;
    PORT
      LAYER M4 ;
        RECT  0 187.344 0.084 187.368 ;
    END
  END li_d[537]
  PIN li_d[538]
    DIRECTION INPUT ;
    USE SIGNAL ;
    PORT
      LAYER M4 ;
        RECT  0 187.632 0.084 187.656 ;
    END
  END li_d[538]
  PIN li_d[539]
    DIRECTION INPUT ;
    USE SIGNAL ;
    PORT
      LAYER M4 ;
        RECT  0 187.968 0.084 187.992 ;
    END
  END li_d[539]
  PIN li_d[53]
    DIRECTION INPUT ;
    USE SIGNAL ;
    PORT
      LAYER M4 ;
        RECT  0 34.176 0.084 34.2 ;
    END
  END li_d[53]
  PIN li_d[540]
    DIRECTION INPUT ;
    USE SIGNAL ;
    PORT
      LAYER M4 ;
        RECT  0 188.256 0.084 188.28 ;
    END
  END li_d[540]
  PIN li_d[541]
    DIRECTION INPUT ;
    USE SIGNAL ;
    PORT
      LAYER M4 ;
        RECT  0 188.592 0.084 188.616 ;
    END
  END li_d[541]
  PIN li_d[542]
    DIRECTION INPUT ;
    USE SIGNAL ;
    PORT
      LAYER M4 ;
        RECT  0 188.928 0.084 188.952 ;
    END
  END li_d[542]
  PIN li_d[543]
    DIRECTION INPUT ;
    USE SIGNAL ;
    PORT
      LAYER M4 ;
        RECT  0 189.216 0.084 189.24 ;
    END
  END li_d[543]
  PIN li_d[544]
    DIRECTION INPUT ;
    USE SIGNAL ;
    PORT
      LAYER M4 ;
        RECT  0 189.552 0.084 189.576 ;
    END
  END li_d[544]
  PIN li_d[545]
    DIRECTION INPUT ;
    USE SIGNAL ;
    PORT
      LAYER M4 ;
        RECT  0 189.84 0.084 189.864 ;
    END
  END li_d[545]
  PIN li_d[546]
    DIRECTION INPUT ;
    USE SIGNAL ;
    PORT
      LAYER M4 ;
        RECT  0 190.176 0.084 190.2 ;
    END
  END li_d[546]
  PIN li_d[547]
    DIRECTION INPUT ;
    USE SIGNAL ;
    PORT
      LAYER M4 ;
        RECT  0 190.512 0.084 190.536 ;
    END
  END li_d[547]
  PIN li_d[548]
    DIRECTION INPUT ;
    USE SIGNAL ;
    PORT
      LAYER M4 ;
        RECT  0 190.8 0.084 190.824 ;
    END
  END li_d[548]
  PIN li_d[549]
    DIRECTION INPUT ;
    USE SIGNAL ;
    PORT
      LAYER M4 ;
        RECT  0 191.136 0.084 191.16 ;
    END
  END li_d[549]
  PIN li_d[54]
    DIRECTION INPUT ;
    USE SIGNAL ;
    PORT
      LAYER M4 ;
        RECT  0 34.512 0.084 34.536 ;
    END
  END li_d[54]
  PIN li_d[550]
    DIRECTION INPUT ;
    USE SIGNAL ;
    PORT
      LAYER M4 ;
        RECT  0 191.424 0.084 191.448 ;
    END
  END li_d[550]
  PIN li_d[551]
    DIRECTION INPUT ;
    USE SIGNAL ;
    PORT
      LAYER M4 ;
        RECT  0 191.76 0.084 191.784 ;
    END
  END li_d[551]
  PIN li_d[552]
    DIRECTION INPUT ;
    USE SIGNAL ;
    PORT
      LAYER M4 ;
        RECT  0 192.048 0.084 192.072 ;
    END
  END li_d[552]
  PIN li_d[55]
    DIRECTION INPUT ;
    USE SIGNAL ;
    PORT
      LAYER M4 ;
        RECT  0 34.848 0.084 34.872 ;
    END
  END li_d[55]
  PIN li_d[56]
    DIRECTION INPUT ;
    USE SIGNAL ;
    PORT
      LAYER M4 ;
        RECT  0 35.136 0.084 35.16 ;
    END
  END li_d[56]
  PIN li_d[57]
    DIRECTION INPUT ;
    USE SIGNAL ;
    PORT
      LAYER M4 ;
        RECT  0 35.472 0.084 35.496 ;
    END
  END li_d[57]
  PIN li_d[58]
    DIRECTION INPUT ;
    USE SIGNAL ;
    PORT
      LAYER M4 ;
        RECT  0 35.76 0.084 35.784 ;
    END
  END li_d[58]
  PIN li_d[59]
    DIRECTION INPUT ;
    USE SIGNAL ;
    PORT
      LAYER M4 ;
        RECT  0 36.096 0.084 36.12 ;
    END
  END li_d[59]
  PIN li_d[5]
    DIRECTION INPUT ;
    USE SIGNAL ;
    PORT
      LAYER M4 ;
        RECT  0 19.008 0.084 19.032 ;
    END
  END li_d[5]
  PIN li_d[60]
    DIRECTION INPUT ;
    USE SIGNAL ;
    PORT
      LAYER M4 ;
        RECT  0 36.432 0.084 36.456 ;
    END
  END li_d[60]
  PIN li_d[61]
    DIRECTION INPUT ;
    USE SIGNAL ;
    PORT
      LAYER M4 ;
        RECT  0 36.72 0.084 36.744 ;
    END
  END li_d[61]
  PIN li_d[62]
    DIRECTION INPUT ;
    USE SIGNAL ;
    PORT
      LAYER M4 ;
        RECT  0 37.056 0.084 37.08 ;
    END
  END li_d[62]
  PIN li_d[63]
    DIRECTION INPUT ;
    USE SIGNAL ;
    PORT
      LAYER M4 ;
        RECT  0 37.344 0.084 37.368 ;
    END
  END li_d[63]
  PIN li_d[64]
    DIRECTION INPUT ;
    USE SIGNAL ;
    PORT
      LAYER M4 ;
        RECT  0 37.68 0.084 37.704 ;
    END
  END li_d[64]
  PIN li_d[65]
    DIRECTION INPUT ;
    USE SIGNAL ;
    PORT
      LAYER M4 ;
        RECT  0 37.968 0.084 37.992 ;
    END
  END li_d[65]
  PIN li_d[66]
    DIRECTION INPUT ;
    USE SIGNAL ;
    PORT
      LAYER M4 ;
        RECT  0 38.304 0.084 38.328 ;
    END
  END li_d[66]
  PIN li_d[67]
    DIRECTION INPUT ;
    USE SIGNAL ;
    PORT
      LAYER M4 ;
        RECT  0 38.64 0.084 38.664 ;
    END
  END li_d[67]
  PIN li_d[68]
    DIRECTION INPUT ;
    USE SIGNAL ;
    PORT
      LAYER M4 ;
        RECT  0 38.928 0.084 38.952 ;
    END
  END li_d[68]
  PIN li_d[69]
    DIRECTION INPUT ;
    USE SIGNAL ;
    PORT
      LAYER M4 ;
        RECT  0 39.264 0.084 39.288 ;
    END
  END li_d[69]
  PIN li_d[6]
    DIRECTION INPUT ;
    USE SIGNAL ;
    PORT
      LAYER M4 ;
        RECT  0 19.344 0.084 19.368 ;
    END
  END li_d[6]
  PIN li_d[70]
    DIRECTION INPUT ;
    USE SIGNAL ;
    PORT
      LAYER M4 ;
        RECT  0 39.552 0.084 39.576 ;
    END
  END li_d[70]
  PIN li_d[71]
    DIRECTION INPUT ;
    USE SIGNAL ;
    PORT
      LAYER M4 ;
        RECT  0 39.888 0.084 39.912 ;
    END
  END li_d[71]
  PIN li_d[72]
    DIRECTION INPUT ;
    USE SIGNAL ;
    PORT
      LAYER M4 ;
        RECT  0 40.224 0.084 40.248 ;
    END
  END li_d[72]
  PIN li_d[73]
    DIRECTION INPUT ;
    USE SIGNAL ;
    PORT
      LAYER M4 ;
        RECT  0 40.512 0.084 40.536 ;
    END
  END li_d[73]
  PIN li_d[74]
    DIRECTION INPUT ;
    USE SIGNAL ;
    PORT
      LAYER M4 ;
        RECT  0 40.848 0.084 40.872 ;
    END
  END li_d[74]
  PIN li_d[75]
    DIRECTION INPUT ;
    USE SIGNAL ;
    PORT
      LAYER M4 ;
        RECT  0 41.136 0.084 41.16 ;
    END
  END li_d[75]
  PIN li_d[76]
    DIRECTION INPUT ;
    USE SIGNAL ;
    PORT
      LAYER M4 ;
        RECT  0 41.472 0.084 41.496 ;
    END
  END li_d[76]
  PIN li_d[77]
    DIRECTION INPUT ;
    USE SIGNAL ;
    PORT
      LAYER M4 ;
        RECT  0 41.808 0.084 41.832 ;
    END
  END li_d[77]
  PIN li_d[78]
    DIRECTION INPUT ;
    USE SIGNAL ;
    PORT
      LAYER M4 ;
        RECT  0 42.096 0.084 42.12 ;
    END
  END li_d[78]
  PIN li_d[79]
    DIRECTION INPUT ;
    USE SIGNAL ;
    PORT
      LAYER M4 ;
        RECT  0 42.432 0.084 42.456 ;
    END
  END li_d[79]
  PIN li_d[7]
    DIRECTION INPUT ;
    USE SIGNAL ;
    PORT
      LAYER M4 ;
        RECT  0 19.632 0.084 19.656 ;
    END
  END li_d[7]
  PIN li_d[80]
    DIRECTION INPUT ;
    USE SIGNAL ;
    PORT
      LAYER M4 ;
        RECT  0 42.72 0.084 42.744 ;
    END
  END li_d[80]
  PIN li_d[81]
    DIRECTION INPUT ;
    USE SIGNAL ;
    PORT
      LAYER M4 ;
        RECT  0 43.056 0.084 43.08 ;
    END
  END li_d[81]
  PIN li_d[82]
    DIRECTION INPUT ;
    USE SIGNAL ;
    PORT
      LAYER M4 ;
        RECT  0 43.392 0.084 43.416 ;
    END
  END li_d[82]
  PIN li_d[83]
    DIRECTION INPUT ;
    USE SIGNAL ;
    PORT
      LAYER M4 ;
        RECT  0 43.68 0.084 43.704 ;
    END
  END li_d[83]
  PIN li_d[84]
    DIRECTION INPUT ;
    USE SIGNAL ;
    PORT
      LAYER M4 ;
        RECT  0 44.016 0.084 44.04 ;
    END
  END li_d[84]
  PIN li_d[85]
    DIRECTION INPUT ;
    USE SIGNAL ;
    PORT
      LAYER M4 ;
        RECT  0 44.304 0.084 44.328 ;
    END
  END li_d[85]
  PIN li_d[86]
    DIRECTION INPUT ;
    USE SIGNAL ;
    PORT
      LAYER M4 ;
        RECT  0 44.64 0.084 44.664 ;
    END
  END li_d[86]
  PIN li_d[87]
    DIRECTION INPUT ;
    USE SIGNAL ;
    PORT
      LAYER M4 ;
        RECT  0 44.976 0.084 45 ;
    END
  END li_d[87]
  PIN li_d[88]
    DIRECTION INPUT ;
    USE SIGNAL ;
    PORT
      LAYER M4 ;
        RECT  0 45.264 0.084 45.288 ;
    END
  END li_d[88]
  PIN li_d[89]
    DIRECTION INPUT ;
    USE SIGNAL ;
    PORT
      LAYER M4 ;
        RECT  0 45.6 0.084 45.624 ;
    END
  END li_d[89]
  PIN li_d[8]
    DIRECTION INPUT ;
    USE SIGNAL ;
    PORT
      LAYER M4 ;
        RECT  0 19.968 0.084 19.992 ;
    END
  END li_d[8]
  PIN li_d[90]
    DIRECTION INPUT ;
    USE SIGNAL ;
    PORT
      LAYER M4 ;
        RECT  0 45.888 0.084 45.912 ;
    END
  END li_d[90]
  PIN li_d[91]
    DIRECTION INPUT ;
    USE SIGNAL ;
    PORT
      LAYER M4 ;
        RECT  0 46.224 0.084 46.248 ;
    END
  END li_d[91]
  PIN li_d[92]
    DIRECTION INPUT ;
    USE SIGNAL ;
    PORT
      LAYER M4 ;
        RECT  0 46.512 0.084 46.536 ;
    END
  END li_d[92]
  PIN li_d[93]
    DIRECTION INPUT ;
    USE SIGNAL ;
    PORT
      LAYER M4 ;
        RECT  0 46.848 0.084 46.872 ;
    END
  END li_d[93]
  PIN li_d[94]
    DIRECTION INPUT ;
    USE SIGNAL ;
    PORT
      LAYER M4 ;
        RECT  0 47.184 0.084 47.208 ;
    END
  END li_d[94]
  PIN li_d[95]
    DIRECTION INPUT ;
    USE SIGNAL ;
    PORT
      LAYER M4 ;
        RECT  0 47.472 0.084 47.496 ;
    END
  END li_d[95]
  PIN li_d[96]
    DIRECTION INPUT ;
    USE SIGNAL ;
    PORT
      LAYER M4 ;
        RECT  0 47.808 0.084 47.832 ;
    END
  END li_d[96]
  PIN li_d[97]
    DIRECTION INPUT ;
    USE SIGNAL ;
    PORT
      LAYER M4 ;
        RECT  0 48.096 0.084 48.12 ;
    END
  END li_d[97]
  PIN li_d[98]
    DIRECTION INPUT ;
    USE SIGNAL ;
    PORT
      LAYER M4 ;
        RECT  0 48.432 0.084 48.456 ;
    END
  END li_d[98]
  PIN li_d[99]
    DIRECTION INPUT ;
    USE SIGNAL ;
    PORT
      LAYER M4 ;
        RECT  0 48.768 0.084 48.792 ;
    END
  END li_d[99]
  PIN li_d[9]
    DIRECTION INPUT ;
    USE SIGNAL ;
    PORT
      LAYER M4 ;
        RECT  0 20.256 0.084 20.28 ;
    END
  END li_d[9]
  PIN li_r
    DIRECTION OUTPUT ;
    USE SIGNAL ;
    PORT
      LAYER M4 ;
        RECT  0 7.008 0.084 7.032 ;
    END
  END li_r
  PIN li_v
    DIRECTION INPUT ;
    USE SIGNAL ;
    PORT
      LAYER M4 ;
        RECT  0 4.848 0.084 4.872 ;
    END
  END li_v
  PIN lo_r
    DIRECTION INPUT ;
    USE SIGNAL ;
    PORT
      LAYER M4 ;
        RECT  0 2.688 0.084 2.712 ;
    END
  END lo_r
  PIN ovf_t
    DIRECTION INPUT ;
    USE SIGNAL ;
    PORT
      LAYER M5 ;
        RECT  54.528 0 54.552 0.084 ;
    END
  END ovf_t
  PIN r_lane
    DIRECTION OUTPUT ;
    USE SIGNAL ;
    PORT
      LAYER M4 ;
        RECT  0 13.488 0.084 13.512 ;
    END
  END r_lane
  PIN r_misc_o
    DIRECTION OUTPUT ;
    USE SIGNAL ;
    PORT
      LAYER M4 ;
        RECT  0 15.648 0.084 15.672 ;
    END
  END r_misc_o
  PIN rst_n
    DIRECTION INPUT ;
    USE SIGNAL ;
    PORT
      LAYER M5 ;
        RECT  50.736 194.316 50.76 194.4 ;
    END
  END rst_n
  PIN rx_d[0]
    DIRECTION OUTPUT ;
    USE SIGNAL ;
    PORT
      LAYER M4 ;
        RECT  86.316 17.424 86.4 17.448 ;
    END
  END rx_d[0]
  PIN rx_d[100]
    DIRECTION OUTPUT ;
    USE SIGNAL ;
    PORT
      LAYER M4 ;
        RECT  86.316 49.056 86.4 49.08 ;
    END
  END rx_d[100]
  PIN rx_d[101]
    DIRECTION OUTPUT ;
    USE SIGNAL ;
    PORT
      LAYER M4 ;
        RECT  86.316 49.392 86.4 49.416 ;
    END
  END rx_d[101]
  PIN rx_d[102]
    DIRECTION OUTPUT ;
    USE SIGNAL ;
    PORT
      LAYER M4 ;
        RECT  86.316 49.68 86.4 49.704 ;
    END
  END rx_d[102]
  PIN rx_d[103]
    DIRECTION OUTPUT ;
    USE SIGNAL ;
    PORT
      LAYER M4 ;
        RECT  86.316 50.016 86.4 50.04 ;
    END
  END rx_d[103]
  PIN rx_d[104]
    DIRECTION OUTPUT ;
    USE SIGNAL ;
    PORT
      LAYER M4 ;
        RECT  86.316 50.352 86.4 50.376 ;
    END
  END rx_d[104]
  PIN rx_d[105]
    DIRECTION OUTPUT ;
    USE SIGNAL ;
    PORT
      LAYER M4 ;
        RECT  86.316 50.64 86.4 50.664 ;
    END
  END rx_d[105]
  PIN rx_d[106]
    DIRECTION OUTPUT ;
    USE SIGNAL ;
    PORT
      LAYER M4 ;
        RECT  86.316 50.976 86.4 51 ;
    END
  END rx_d[106]
  PIN rx_d[107]
    DIRECTION OUTPUT ;
    USE SIGNAL ;
    PORT
      LAYER M4 ;
        RECT  86.316 51.264 86.4 51.288 ;
    END
  END rx_d[107]
  PIN rx_d[108]
    DIRECTION OUTPUT ;
    USE SIGNAL ;
    PORT
      LAYER M4 ;
        RECT  86.316 51.6 86.4 51.624 ;
    END
  END rx_d[108]
  PIN rx_d[109]
    DIRECTION OUTPUT ;
    USE SIGNAL ;
    PORT
      LAYER M4 ;
        RECT  86.316 51.936 86.4 51.96 ;
    END
  END rx_d[109]
  PIN rx_d[10]
    DIRECTION OUTPUT ;
    USE SIGNAL ;
    PORT
      LAYER M4 ;
        RECT  86.316 20.592 86.4 20.616 ;
    END
  END rx_d[10]
  PIN rx_d[110]
    DIRECTION OUTPUT ;
    USE SIGNAL ;
    PORT
      LAYER M4 ;
        RECT  86.316 52.224 86.4 52.248 ;
    END
  END rx_d[110]
  PIN rx_d[111]
    DIRECTION OUTPUT ;
    USE SIGNAL ;
    PORT
      LAYER M4 ;
        RECT  86.316 52.56 86.4 52.584 ;
    END
  END rx_d[111]
  PIN rx_d[112]
    DIRECTION OUTPUT ;
    USE SIGNAL ;
    PORT
      LAYER M4 ;
        RECT  86.316 52.848 86.4 52.872 ;
    END
  END rx_d[112]
  PIN rx_d[113]
    DIRECTION OUTPUT ;
    USE SIGNAL ;
    PORT
      LAYER M4 ;
        RECT  86.316 53.184 86.4 53.208 ;
    END
  END rx_d[113]
  PIN rx_d[114]
    DIRECTION OUTPUT ;
    USE SIGNAL ;
    PORT
      LAYER M4 ;
        RECT  86.316 53.472 86.4 53.496 ;
    END
  END rx_d[114]
  PIN rx_d[115]
    DIRECTION OUTPUT ;
    USE SIGNAL ;
    PORT
      LAYER M4 ;
        RECT  86.316 53.808 86.4 53.832 ;
    END
  END rx_d[115]
  PIN rx_d[116]
    DIRECTION OUTPUT ;
    USE SIGNAL ;
    PORT
      LAYER M4 ;
        RECT  86.316 54.144 86.4 54.168 ;
    END
  END rx_d[116]
  PIN rx_d[117]
    DIRECTION OUTPUT ;
    USE SIGNAL ;
    PORT
      LAYER M4 ;
        RECT  86.316 54.432 86.4 54.456 ;
    END
  END rx_d[117]
  PIN rx_d[118]
    DIRECTION OUTPUT ;
    USE SIGNAL ;
    PORT
      LAYER M4 ;
        RECT  86.316 54.768 86.4 54.792 ;
    END
  END rx_d[118]
  PIN rx_d[119]
    DIRECTION OUTPUT ;
    USE SIGNAL ;
    PORT
      LAYER M4 ;
        RECT  86.316 55.056 86.4 55.08 ;
    END
  END rx_d[119]
  PIN rx_d[11]
    DIRECTION OUTPUT ;
    USE SIGNAL ;
    PORT
      LAYER M4 ;
        RECT  86.316 20.928 86.4 20.952 ;
    END
  END rx_d[11]
  PIN rx_d[120]
    DIRECTION OUTPUT ;
    USE SIGNAL ;
    PORT
      LAYER M4 ;
        RECT  86.316 55.392 86.4 55.416 ;
    END
  END rx_d[120]
  PIN rx_d[121]
    DIRECTION OUTPUT ;
    USE SIGNAL ;
    PORT
      LAYER M4 ;
        RECT  86.316 55.728 86.4 55.752 ;
    END
  END rx_d[121]
  PIN rx_d[122]
    DIRECTION OUTPUT ;
    USE SIGNAL ;
    PORT
      LAYER M4 ;
        RECT  86.316 56.016 86.4 56.04 ;
    END
  END rx_d[122]
  PIN rx_d[123]
    DIRECTION OUTPUT ;
    USE SIGNAL ;
    PORT
      LAYER M4 ;
        RECT  86.316 56.352 86.4 56.376 ;
    END
  END rx_d[123]
  PIN rx_d[124]
    DIRECTION OUTPUT ;
    USE SIGNAL ;
    PORT
      LAYER M4 ;
        RECT  86.316 56.64 86.4 56.664 ;
    END
  END rx_d[124]
  PIN rx_d[125]
    DIRECTION OUTPUT ;
    USE SIGNAL ;
    PORT
      LAYER M4 ;
        RECT  86.316 56.976 86.4 57 ;
    END
  END rx_d[125]
  PIN rx_d[126]
    DIRECTION OUTPUT ;
    USE SIGNAL ;
    PORT
      LAYER M4 ;
        RECT  86.316 57.312 86.4 57.336 ;
    END
  END rx_d[126]
  PIN rx_d[127]
    DIRECTION OUTPUT ;
    USE SIGNAL ;
    PORT
      LAYER M4 ;
        RECT  86.316 57.6 86.4 57.624 ;
    END
  END rx_d[127]
  PIN rx_d[128]
    DIRECTION OUTPUT ;
    USE SIGNAL ;
    PORT
      LAYER M4 ;
        RECT  86.316 57.936 86.4 57.96 ;
    END
  END rx_d[128]
  PIN rx_d[129]
    DIRECTION OUTPUT ;
    USE SIGNAL ;
    PORT
      LAYER M4 ;
        RECT  86.316 58.224 86.4 58.248 ;
    END
  END rx_d[129]
  PIN rx_d[12]
    DIRECTION OUTPUT ;
    USE SIGNAL ;
    PORT
      LAYER M4 ;
        RECT  86.316 21.216 86.4 21.24 ;
    END
  END rx_d[12]
  PIN rx_d[130]
    DIRECTION OUTPUT ;
    USE SIGNAL ;
    PORT
      LAYER M4 ;
        RECT  86.316 58.56 86.4 58.584 ;
    END
  END rx_d[130]
  PIN rx_d[131]
    DIRECTION OUTPUT ;
    USE SIGNAL ;
    PORT
      LAYER M4 ;
        RECT  86.316 58.896 86.4 58.92 ;
    END
  END rx_d[131]
  PIN rx_d[132]
    DIRECTION OUTPUT ;
    USE SIGNAL ;
    PORT
      LAYER M4 ;
        RECT  86.316 59.184 86.4 59.208 ;
    END
  END rx_d[132]
  PIN rx_d[133]
    DIRECTION OUTPUT ;
    USE SIGNAL ;
    PORT
      LAYER M4 ;
        RECT  86.316 59.52 86.4 59.544 ;
    END
  END rx_d[133]
  PIN rx_d[134]
    DIRECTION OUTPUT ;
    USE SIGNAL ;
    PORT
      LAYER M4 ;
        RECT  86.316 59.808 86.4 59.832 ;
    END
  END rx_d[134]
  PIN rx_d[135]
    DIRECTION OUTPUT ;
    USE SIGNAL ;
    PORT
      LAYER M4 ;
        RECT  86.316 60.144 86.4 60.168 ;
    END
  END rx_d[135]
  PIN rx_d[136]
    DIRECTION OUTPUT ;
    USE SIGNAL ;
    PORT
      LAYER M4 ;
        RECT  86.316 60.432 86.4 60.456 ;
    END
  END rx_d[136]
  PIN rx_d[137]
    DIRECTION OUTPUT ;
    USE SIGNAL ;
    PORT
      LAYER M4 ;
        RECT  86.316 60.768 86.4 60.792 ;
    END
  END rx_d[137]
  PIN rx_d[138]
    DIRECTION OUTPUT ;
    USE SIGNAL ;
    PORT
      LAYER M4 ;
        RECT  86.316 61.104 86.4 61.128 ;
    END
  END rx_d[138]
  PIN rx_d[139]
    DIRECTION OUTPUT ;
    USE SIGNAL ;
    PORT
      LAYER M4 ;
        RECT  86.316 61.392 86.4 61.416 ;
    END
  END rx_d[139]
  PIN rx_d[13]
    DIRECTION OUTPUT ;
    USE SIGNAL ;
    PORT
      LAYER M4 ;
        RECT  86.316 21.552 86.4 21.576 ;
    END
  END rx_d[13]
  PIN rx_d[140]
    DIRECTION OUTPUT ;
    USE SIGNAL ;
    PORT
      LAYER M4 ;
        RECT  86.316 61.728 86.4 61.752 ;
    END
  END rx_d[140]
  PIN rx_d[141]
    DIRECTION OUTPUT ;
    USE SIGNAL ;
    PORT
      LAYER M4 ;
        RECT  86.316 62.016 86.4 62.04 ;
    END
  END rx_d[141]
  PIN rx_d[142]
    DIRECTION OUTPUT ;
    USE SIGNAL ;
    PORT
      LAYER M4 ;
        RECT  86.316 62.352 86.4 62.376 ;
    END
  END rx_d[142]
  PIN rx_d[143]
    DIRECTION OUTPUT ;
    USE SIGNAL ;
    PORT
      LAYER M4 ;
        RECT  86.316 62.688 86.4 62.712 ;
    END
  END rx_d[143]
  PIN rx_d[144]
    DIRECTION OUTPUT ;
    USE SIGNAL ;
    PORT
      LAYER M4 ;
        RECT  86.316 62.976 86.4 63 ;
    END
  END rx_d[144]
  PIN rx_d[145]
    DIRECTION OUTPUT ;
    USE SIGNAL ;
    PORT
      LAYER M4 ;
        RECT  86.316 63.312 86.4 63.336 ;
    END
  END rx_d[145]
  PIN rx_d[146]
    DIRECTION OUTPUT ;
    USE SIGNAL ;
    PORT
      LAYER M4 ;
        RECT  86.316 63.6 86.4 63.624 ;
    END
  END rx_d[146]
  PIN rx_d[147]
    DIRECTION OUTPUT ;
    USE SIGNAL ;
    PORT
      LAYER M4 ;
        RECT  86.316 63.936 86.4 63.96 ;
    END
  END rx_d[147]
  PIN rx_d[148]
    DIRECTION OUTPUT ;
    USE SIGNAL ;
    PORT
      LAYER M4 ;
        RECT  86.316 64.272 86.4 64.296 ;
    END
  END rx_d[148]
  PIN rx_d[149]
    DIRECTION OUTPUT ;
    USE SIGNAL ;
    PORT
      LAYER M4 ;
        RECT  86.316 64.56 86.4 64.584 ;
    END
  END rx_d[149]
  PIN rx_d[14]
    DIRECTION OUTPUT ;
    USE SIGNAL ;
    PORT
      LAYER M4 ;
        RECT  86.316 21.84 86.4 21.864 ;
    END
  END rx_d[14]
  PIN rx_d[150]
    DIRECTION OUTPUT ;
    USE SIGNAL ;
    PORT
      LAYER M4 ;
        RECT  86.316 64.896 86.4 64.92 ;
    END
  END rx_d[150]
  PIN rx_d[151]
    DIRECTION OUTPUT ;
    USE SIGNAL ;
    PORT
      LAYER M4 ;
        RECT  86.316 65.184 86.4 65.208 ;
    END
  END rx_d[151]
  PIN rx_d[152]
    DIRECTION OUTPUT ;
    USE SIGNAL ;
    PORT
      LAYER M4 ;
        RECT  86.316 65.52 86.4 65.544 ;
    END
  END rx_d[152]
  PIN rx_d[153]
    DIRECTION OUTPUT ;
    USE SIGNAL ;
    PORT
      LAYER M4 ;
        RECT  86.316 65.856 86.4 65.88 ;
    END
  END rx_d[153]
  PIN rx_d[154]
    DIRECTION OUTPUT ;
    USE SIGNAL ;
    PORT
      LAYER M4 ;
        RECT  86.316 66.144 86.4 66.168 ;
    END
  END rx_d[154]
  PIN rx_d[155]
    DIRECTION OUTPUT ;
    USE SIGNAL ;
    PORT
      LAYER M4 ;
        RECT  86.316 66.48 86.4 66.504 ;
    END
  END rx_d[155]
  PIN rx_d[156]
    DIRECTION OUTPUT ;
    USE SIGNAL ;
    PORT
      LAYER M4 ;
        RECT  86.316 66.768 86.4 66.792 ;
    END
  END rx_d[156]
  PIN rx_d[157]
    DIRECTION OUTPUT ;
    USE SIGNAL ;
    PORT
      LAYER M4 ;
        RECT  86.316 67.104 86.4 67.128 ;
    END
  END rx_d[157]
  PIN rx_d[158]
    DIRECTION OUTPUT ;
    USE SIGNAL ;
    PORT
      LAYER M4 ;
        RECT  86.316 67.392 86.4 67.416 ;
    END
  END rx_d[158]
  PIN rx_d[159]
    DIRECTION OUTPUT ;
    USE SIGNAL ;
    PORT
      LAYER M4 ;
        RECT  86.316 67.728 86.4 67.752 ;
    END
  END rx_d[159]
  PIN rx_d[15]
    DIRECTION OUTPUT ;
    USE SIGNAL ;
    PORT
      LAYER M4 ;
        RECT  86.316 22.176 86.4 22.2 ;
    END
  END rx_d[15]
  PIN rx_d[160]
    DIRECTION OUTPUT ;
    USE SIGNAL ;
    PORT
      LAYER M4 ;
        RECT  86.316 68.064 86.4 68.088 ;
    END
  END rx_d[160]
  PIN rx_d[161]
    DIRECTION OUTPUT ;
    USE SIGNAL ;
    PORT
      LAYER M4 ;
        RECT  86.316 68.352 86.4 68.376 ;
    END
  END rx_d[161]
  PIN rx_d[162]
    DIRECTION OUTPUT ;
    USE SIGNAL ;
    PORT
      LAYER M4 ;
        RECT  86.316 68.688 86.4 68.712 ;
    END
  END rx_d[162]
  PIN rx_d[163]
    DIRECTION OUTPUT ;
    USE SIGNAL ;
    PORT
      LAYER M4 ;
        RECT  86.316 68.976 86.4 69 ;
    END
  END rx_d[163]
  PIN rx_d[164]
    DIRECTION OUTPUT ;
    USE SIGNAL ;
    PORT
      LAYER M4 ;
        RECT  86.316 69.312 86.4 69.336 ;
    END
  END rx_d[164]
  PIN rx_d[165]
    DIRECTION OUTPUT ;
    USE SIGNAL ;
    PORT
      LAYER M4 ;
        RECT  86.316 69.648 86.4 69.672 ;
    END
  END rx_d[165]
  PIN rx_d[166]
    DIRECTION OUTPUT ;
    USE SIGNAL ;
    PORT
      LAYER M4 ;
        RECT  86.316 69.936 86.4 69.96 ;
    END
  END rx_d[166]
  PIN rx_d[167]
    DIRECTION OUTPUT ;
    USE SIGNAL ;
    PORT
      LAYER M4 ;
        RECT  86.316 70.272 86.4 70.296 ;
    END
  END rx_d[167]
  PIN rx_d[168]
    DIRECTION OUTPUT ;
    USE SIGNAL ;
    PORT
      LAYER M4 ;
        RECT  86.316 70.56 86.4 70.584 ;
    END
  END rx_d[168]
  PIN rx_d[169]
    DIRECTION OUTPUT ;
    USE SIGNAL ;
    PORT
      LAYER M4 ;
        RECT  86.316 70.896 86.4 70.92 ;
    END
  END rx_d[169]
  PIN rx_d[16]
    DIRECTION OUTPUT ;
    USE SIGNAL ;
    PORT
      LAYER M4 ;
        RECT  86.316 22.512 86.4 22.536 ;
    END
  END rx_d[16]
  PIN rx_d[170]
    DIRECTION OUTPUT ;
    USE SIGNAL ;
    PORT
      LAYER M4 ;
        RECT  86.316 71.232 86.4 71.256 ;
    END
  END rx_d[170]
  PIN rx_d[171]
    DIRECTION OUTPUT ;
    USE SIGNAL ;
    PORT
      LAYER M4 ;
        RECT  86.316 71.52 86.4 71.544 ;
    END
  END rx_d[171]
  PIN rx_d[172]
    DIRECTION OUTPUT ;
    USE SIGNAL ;
    PORT
      LAYER M4 ;
        RECT  86.316 71.856 86.4 71.88 ;
    END
  END rx_d[172]
  PIN rx_d[173]
    DIRECTION OUTPUT ;
    USE SIGNAL ;
    PORT
      LAYER M4 ;
        RECT  86.316 72.144 86.4 72.168 ;
    END
  END rx_d[173]
  PIN rx_d[174]
    DIRECTION OUTPUT ;
    USE SIGNAL ;
    PORT
      LAYER M4 ;
        RECT  86.316 72.48 86.4 72.504 ;
    END
  END rx_d[174]
  PIN rx_d[175]
    DIRECTION OUTPUT ;
    USE SIGNAL ;
    PORT
      LAYER M4 ;
        RECT  86.316 72.816 86.4 72.84 ;
    END
  END rx_d[175]
  PIN rx_d[176]
    DIRECTION OUTPUT ;
    USE SIGNAL ;
    PORT
      LAYER M4 ;
        RECT  86.316 73.104 86.4 73.128 ;
    END
  END rx_d[176]
  PIN rx_d[177]
    DIRECTION OUTPUT ;
    USE SIGNAL ;
    PORT
      LAYER M4 ;
        RECT  86.316 73.44 86.4 73.464 ;
    END
  END rx_d[177]
  PIN rx_d[178]
    DIRECTION OUTPUT ;
    USE SIGNAL ;
    PORT
      LAYER M4 ;
        RECT  86.316 73.728 86.4 73.752 ;
    END
  END rx_d[178]
  PIN rx_d[179]
    DIRECTION OUTPUT ;
    USE SIGNAL ;
    PORT
      LAYER M4 ;
        RECT  86.316 74.064 86.4 74.088 ;
    END
  END rx_d[179]
  PIN rx_d[17]
    DIRECTION OUTPUT ;
    USE SIGNAL ;
    PORT
      LAYER M4 ;
        RECT  86.316 22.8 86.4 22.824 ;
    END
  END rx_d[17]
  PIN rx_d[180]
    DIRECTION OUTPUT ;
    USE SIGNAL ;
    PORT
      LAYER M4 ;
        RECT  86.316 74.352 86.4 74.376 ;
    END
  END rx_d[180]
  PIN rx_d[181]
    DIRECTION OUTPUT ;
    USE SIGNAL ;
    PORT
      LAYER M4 ;
        RECT  86.316 74.688 86.4 74.712 ;
    END
  END rx_d[181]
  PIN rx_d[182]
    DIRECTION OUTPUT ;
    USE SIGNAL ;
    PORT
      LAYER M4 ;
        RECT  86.316 75.024 86.4 75.048 ;
    END
  END rx_d[182]
  PIN rx_d[183]
    DIRECTION OUTPUT ;
    USE SIGNAL ;
    PORT
      LAYER M4 ;
        RECT  86.316 75.312 86.4 75.336 ;
    END
  END rx_d[183]
  PIN rx_d[184]
    DIRECTION OUTPUT ;
    USE SIGNAL ;
    PORT
      LAYER M4 ;
        RECT  86.316 75.648 86.4 75.672 ;
    END
  END rx_d[184]
  PIN rx_d[185]
    DIRECTION OUTPUT ;
    USE SIGNAL ;
    PORT
      LAYER M4 ;
        RECT  86.316 75.936 86.4 75.96 ;
    END
  END rx_d[185]
  PIN rx_d[186]
    DIRECTION OUTPUT ;
    USE SIGNAL ;
    PORT
      LAYER M4 ;
        RECT  86.316 76.272 86.4 76.296 ;
    END
  END rx_d[186]
  PIN rx_d[187]
    DIRECTION OUTPUT ;
    USE SIGNAL ;
    PORT
      LAYER M4 ;
        RECT  86.316 76.608 86.4 76.632 ;
    END
  END rx_d[187]
  PIN rx_d[188]
    DIRECTION OUTPUT ;
    USE SIGNAL ;
    PORT
      LAYER M4 ;
        RECT  86.316 76.896 86.4 76.92 ;
    END
  END rx_d[188]
  PIN rx_d[189]
    DIRECTION OUTPUT ;
    USE SIGNAL ;
    PORT
      LAYER M4 ;
        RECT  86.316 77.232 86.4 77.256 ;
    END
  END rx_d[189]
  PIN rx_d[18]
    DIRECTION OUTPUT ;
    USE SIGNAL ;
    PORT
      LAYER M4 ;
        RECT  86.316 23.136 86.4 23.16 ;
    END
  END rx_d[18]
  PIN rx_d[190]
    DIRECTION OUTPUT ;
    USE SIGNAL ;
    PORT
      LAYER M4 ;
        RECT  86.316 77.52 86.4 77.544 ;
    END
  END rx_d[190]
  PIN rx_d[191]
    DIRECTION OUTPUT ;
    USE SIGNAL ;
    PORT
      LAYER M4 ;
        RECT  86.316 77.856 86.4 77.88 ;
    END
  END rx_d[191]
  PIN rx_d[192]
    DIRECTION OUTPUT ;
    USE SIGNAL ;
    PORT
      LAYER M4 ;
        RECT  86.316 78.192 86.4 78.216 ;
    END
  END rx_d[192]
  PIN rx_d[193]
    DIRECTION OUTPUT ;
    USE SIGNAL ;
    PORT
      LAYER M4 ;
        RECT  86.316 78.48 86.4 78.504 ;
    END
  END rx_d[193]
  PIN rx_d[194]
    DIRECTION OUTPUT ;
    USE SIGNAL ;
    PORT
      LAYER M4 ;
        RECT  86.316 78.816 86.4 78.84 ;
    END
  END rx_d[194]
  PIN rx_d[195]
    DIRECTION OUTPUT ;
    USE SIGNAL ;
    PORT
      LAYER M4 ;
        RECT  86.316 79.104 86.4 79.128 ;
    END
  END rx_d[195]
  PIN rx_d[196]
    DIRECTION OUTPUT ;
    USE SIGNAL ;
    PORT
      LAYER M4 ;
        RECT  86.316 79.44 86.4 79.464 ;
    END
  END rx_d[196]
  PIN rx_d[197]
    DIRECTION OUTPUT ;
    USE SIGNAL ;
    PORT
      LAYER M4 ;
        RECT  86.316 79.776 86.4 79.8 ;
    END
  END rx_d[197]
  PIN rx_d[198]
    DIRECTION OUTPUT ;
    USE SIGNAL ;
    PORT
      LAYER M4 ;
        RECT  86.316 80.064 86.4 80.088 ;
    END
  END rx_d[198]
  PIN rx_d[199]
    DIRECTION OUTPUT ;
    USE SIGNAL ;
    PORT
      LAYER M4 ;
        RECT  86.316 80.4 86.4 80.424 ;
    END
  END rx_d[199]
  PIN rx_d[19]
    DIRECTION OUTPUT ;
    USE SIGNAL ;
    PORT
      LAYER M4 ;
        RECT  86.316 23.424 86.4 23.448 ;
    END
  END rx_d[19]
  PIN rx_d[1]
    DIRECTION OUTPUT ;
    USE SIGNAL ;
    PORT
      LAYER M4 ;
        RECT  86.316 17.76 86.4 17.784 ;
    END
  END rx_d[1]
  PIN rx_d[200]
    DIRECTION OUTPUT ;
    USE SIGNAL ;
    PORT
      LAYER M4 ;
        RECT  86.316 80.688 86.4 80.712 ;
    END
  END rx_d[200]
  PIN rx_d[201]
    DIRECTION OUTPUT ;
    USE SIGNAL ;
    PORT
      LAYER M4 ;
        RECT  86.316 81.024 86.4 81.048 ;
    END
  END rx_d[201]
  PIN rx_d[202]
    DIRECTION OUTPUT ;
    USE SIGNAL ;
    PORT
      LAYER M4 ;
        RECT  86.316 81.36 86.4 81.384 ;
    END
  END rx_d[202]
  PIN rx_d[203]
    DIRECTION OUTPUT ;
    USE SIGNAL ;
    PORT
      LAYER M4 ;
        RECT  86.316 81.648 86.4 81.672 ;
    END
  END rx_d[203]
  PIN rx_d[204]
    DIRECTION OUTPUT ;
    USE SIGNAL ;
    PORT
      LAYER M4 ;
        RECT  86.316 81.984 86.4 82.008 ;
    END
  END rx_d[204]
  PIN rx_d[205]
    DIRECTION OUTPUT ;
    USE SIGNAL ;
    PORT
      LAYER M4 ;
        RECT  86.316 82.272 86.4 82.296 ;
    END
  END rx_d[205]
  PIN rx_d[206]
    DIRECTION OUTPUT ;
    USE SIGNAL ;
    PORT
      LAYER M4 ;
        RECT  86.316 82.608 86.4 82.632 ;
    END
  END rx_d[206]
  PIN rx_d[207]
    DIRECTION OUTPUT ;
    USE SIGNAL ;
    PORT
      LAYER M4 ;
        RECT  86.316 82.896 86.4 82.92 ;
    END
  END rx_d[207]
  PIN rx_d[208]
    DIRECTION OUTPUT ;
    USE SIGNAL ;
    PORT
      LAYER M4 ;
        RECT  86.316 83.232 86.4 83.256 ;
    END
  END rx_d[208]
  PIN rx_d[209]
    DIRECTION OUTPUT ;
    USE SIGNAL ;
    PORT
      LAYER M4 ;
        RECT  86.316 83.568 86.4 83.592 ;
    END
  END rx_d[209]
  PIN rx_d[20]
    DIRECTION OUTPUT ;
    USE SIGNAL ;
    PORT
      LAYER M4 ;
        RECT  86.316 23.76 86.4 23.784 ;
    END
  END rx_d[20]
  PIN rx_d[210]
    DIRECTION OUTPUT ;
    USE SIGNAL ;
    PORT
      LAYER M4 ;
        RECT  86.316 83.856 86.4 83.88 ;
    END
  END rx_d[210]
  PIN rx_d[211]
    DIRECTION OUTPUT ;
    USE SIGNAL ;
    PORT
      LAYER M4 ;
        RECT  86.316 84.192 86.4 84.216 ;
    END
  END rx_d[211]
  PIN rx_d[212]
    DIRECTION OUTPUT ;
    USE SIGNAL ;
    PORT
      LAYER M4 ;
        RECT  86.316 84.48 86.4 84.504 ;
    END
  END rx_d[212]
  PIN rx_d[213]
    DIRECTION OUTPUT ;
    USE SIGNAL ;
    PORT
      LAYER M4 ;
        RECT  86.316 84.816 86.4 84.84 ;
    END
  END rx_d[213]
  PIN rx_d[214]
    DIRECTION OUTPUT ;
    USE SIGNAL ;
    PORT
      LAYER M4 ;
        RECT  86.316 85.152 86.4 85.176 ;
    END
  END rx_d[214]
  PIN rx_d[215]
    DIRECTION OUTPUT ;
    USE SIGNAL ;
    PORT
      LAYER M4 ;
        RECT  86.316 85.44 86.4 85.464 ;
    END
  END rx_d[215]
  PIN rx_d[216]
    DIRECTION OUTPUT ;
    USE SIGNAL ;
    PORT
      LAYER M4 ;
        RECT  86.316 85.776 86.4 85.8 ;
    END
  END rx_d[216]
  PIN rx_d[217]
    DIRECTION OUTPUT ;
    USE SIGNAL ;
    PORT
      LAYER M4 ;
        RECT  86.316 86.064 86.4 86.088 ;
    END
  END rx_d[217]
  PIN rx_d[218]
    DIRECTION OUTPUT ;
    USE SIGNAL ;
    PORT
      LAYER M4 ;
        RECT  86.316 86.4 86.4 86.424 ;
    END
  END rx_d[218]
  PIN rx_d[219]
    DIRECTION OUTPUT ;
    USE SIGNAL ;
    PORT
      LAYER M4 ;
        RECT  86.316 86.736 86.4 86.76 ;
    END
  END rx_d[219]
  PIN rx_d[21]
    DIRECTION OUTPUT ;
    USE SIGNAL ;
    PORT
      LAYER M4 ;
        RECT  86.316 24.048 86.4 24.072 ;
    END
  END rx_d[21]
  PIN rx_d[220]
    DIRECTION OUTPUT ;
    USE SIGNAL ;
    PORT
      LAYER M4 ;
        RECT  86.316 87.024 86.4 87.048 ;
    END
  END rx_d[220]
  PIN rx_d[221]
    DIRECTION OUTPUT ;
    USE SIGNAL ;
    PORT
      LAYER M4 ;
        RECT  86.316 87.36 86.4 87.384 ;
    END
  END rx_d[221]
  PIN rx_d[222]
    DIRECTION OUTPUT ;
    USE SIGNAL ;
    PORT
      LAYER M4 ;
        RECT  86.316 87.648 86.4 87.672 ;
    END
  END rx_d[222]
  PIN rx_d[223]
    DIRECTION OUTPUT ;
    USE SIGNAL ;
    PORT
      LAYER M4 ;
        RECT  86.316 87.984 86.4 88.008 ;
    END
  END rx_d[223]
  PIN rx_d[224]
    DIRECTION OUTPUT ;
    USE SIGNAL ;
    PORT
      LAYER M4 ;
        RECT  86.316 88.32 86.4 88.344 ;
    END
  END rx_d[224]
  PIN rx_d[225]
    DIRECTION OUTPUT ;
    USE SIGNAL ;
    PORT
      LAYER M4 ;
        RECT  86.316 88.608 86.4 88.632 ;
    END
  END rx_d[225]
  PIN rx_d[226]
    DIRECTION OUTPUT ;
    USE SIGNAL ;
    PORT
      LAYER M4 ;
        RECT  86.316 88.944 86.4 88.968 ;
    END
  END rx_d[226]
  PIN rx_d[227]
    DIRECTION OUTPUT ;
    USE SIGNAL ;
    PORT
      LAYER M4 ;
        RECT  86.316 89.232 86.4 89.256 ;
    END
  END rx_d[227]
  PIN rx_d[228]
    DIRECTION OUTPUT ;
    USE SIGNAL ;
    PORT
      LAYER M4 ;
        RECT  86.316 89.568 86.4 89.592 ;
    END
  END rx_d[228]
  PIN rx_d[229]
    DIRECTION OUTPUT ;
    USE SIGNAL ;
    PORT
      LAYER M4 ;
        RECT  86.316 89.856 86.4 89.88 ;
    END
  END rx_d[229]
  PIN rx_d[22]
    DIRECTION OUTPUT ;
    USE SIGNAL ;
    PORT
      LAYER M4 ;
        RECT  86.316 24.384 86.4 24.408 ;
    END
  END rx_d[22]
  PIN rx_d[230]
    DIRECTION OUTPUT ;
    USE SIGNAL ;
    PORT
      LAYER M4 ;
        RECT  86.316 90.192 86.4 90.216 ;
    END
  END rx_d[230]
  PIN rx_d[231]
    DIRECTION OUTPUT ;
    USE SIGNAL ;
    PORT
      LAYER M4 ;
        RECT  86.316 90.528 86.4 90.552 ;
    END
  END rx_d[231]
  PIN rx_d[232]
    DIRECTION OUTPUT ;
    USE SIGNAL ;
    PORT
      LAYER M4 ;
        RECT  86.316 90.816 86.4 90.84 ;
    END
  END rx_d[232]
  PIN rx_d[233]
    DIRECTION OUTPUT ;
    USE SIGNAL ;
    PORT
      LAYER M4 ;
        RECT  86.316 91.152 86.4 91.176 ;
    END
  END rx_d[233]
  PIN rx_d[234]
    DIRECTION OUTPUT ;
    USE SIGNAL ;
    PORT
      LAYER M4 ;
        RECT  86.316 91.44 86.4 91.464 ;
    END
  END rx_d[234]
  PIN rx_d[235]
    DIRECTION OUTPUT ;
    USE SIGNAL ;
    PORT
      LAYER M4 ;
        RECT  86.316 91.776 86.4 91.8 ;
    END
  END rx_d[235]
  PIN rx_d[236]
    DIRECTION OUTPUT ;
    USE SIGNAL ;
    PORT
      LAYER M4 ;
        RECT  86.316 92.112 86.4 92.136 ;
    END
  END rx_d[236]
  PIN rx_d[237]
    DIRECTION OUTPUT ;
    USE SIGNAL ;
    PORT
      LAYER M4 ;
        RECT  86.316 92.4 86.4 92.424 ;
    END
  END rx_d[237]
  PIN rx_d[238]
    DIRECTION OUTPUT ;
    USE SIGNAL ;
    PORT
      LAYER M4 ;
        RECT  86.316 92.736 86.4 92.76 ;
    END
  END rx_d[238]
  PIN rx_d[239]
    DIRECTION OUTPUT ;
    USE SIGNAL ;
    PORT
      LAYER M4 ;
        RECT  86.316 93.024 86.4 93.048 ;
    END
  END rx_d[239]
  PIN rx_d[23]
    DIRECTION OUTPUT ;
    USE SIGNAL ;
    PORT
      LAYER M4 ;
        RECT  86.316 24.72 86.4 24.744 ;
    END
  END rx_d[23]
  PIN rx_d[240]
    DIRECTION OUTPUT ;
    USE SIGNAL ;
    PORT
      LAYER M4 ;
        RECT  86.316 93.36 86.4 93.384 ;
    END
  END rx_d[240]
  PIN rx_d[241]
    DIRECTION OUTPUT ;
    USE SIGNAL ;
    PORT
      LAYER M4 ;
        RECT  86.316 93.696 86.4 93.72 ;
    END
  END rx_d[241]
  PIN rx_d[242]
    DIRECTION OUTPUT ;
    USE SIGNAL ;
    PORT
      LAYER M4 ;
        RECT  86.316 93.984 86.4 94.008 ;
    END
  END rx_d[242]
  PIN rx_d[243]
    DIRECTION OUTPUT ;
    USE SIGNAL ;
    PORT
      LAYER M4 ;
        RECT  86.316 94.32 86.4 94.344 ;
    END
  END rx_d[243]
  PIN rx_d[244]
    DIRECTION OUTPUT ;
    USE SIGNAL ;
    PORT
      LAYER M4 ;
        RECT  86.316 94.608 86.4 94.632 ;
    END
  END rx_d[244]
  PIN rx_d[245]
    DIRECTION OUTPUT ;
    USE SIGNAL ;
    PORT
      LAYER M4 ;
        RECT  86.316 94.944 86.4 94.968 ;
    END
  END rx_d[245]
  PIN rx_d[246]
    DIRECTION OUTPUT ;
    USE SIGNAL ;
    PORT
      LAYER M4 ;
        RECT  86.316 95.28 86.4 95.304 ;
    END
  END rx_d[246]
  PIN rx_d[247]
    DIRECTION OUTPUT ;
    USE SIGNAL ;
    PORT
      LAYER M4 ;
        RECT  86.316 95.568 86.4 95.592 ;
    END
  END rx_d[247]
  PIN rx_d[248]
    DIRECTION OUTPUT ;
    USE SIGNAL ;
    PORT
      LAYER M4 ;
        RECT  86.316 95.904 86.4 95.928 ;
    END
  END rx_d[248]
  PIN rx_d[249]
    DIRECTION OUTPUT ;
    USE SIGNAL ;
    PORT
      LAYER M4 ;
        RECT  86.316 96.192 86.4 96.216 ;
    END
  END rx_d[249]
  PIN rx_d[24]
    DIRECTION OUTPUT ;
    USE SIGNAL ;
    PORT
      LAYER M4 ;
        RECT  86.316 25.008 86.4 25.032 ;
    END
  END rx_d[24]
  PIN rx_d[250]
    DIRECTION OUTPUT ;
    USE SIGNAL ;
    PORT
      LAYER M4 ;
        RECT  86.316 96.528 86.4 96.552 ;
    END
  END rx_d[250]
  PIN rx_d[251]
    DIRECTION OUTPUT ;
    USE SIGNAL ;
    PORT
      LAYER M4 ;
        RECT  86.316 96.816 86.4 96.84 ;
    END
  END rx_d[251]
  PIN rx_d[252]
    DIRECTION OUTPUT ;
    USE SIGNAL ;
    PORT
      LAYER M4 ;
        RECT  86.316 97.152 86.4 97.176 ;
    END
  END rx_d[252]
  PIN rx_d[253]
    DIRECTION OUTPUT ;
    USE SIGNAL ;
    PORT
      LAYER M4 ;
        RECT  86.316 97.488 86.4 97.512 ;
    END
  END rx_d[253]
  PIN rx_d[254]
    DIRECTION OUTPUT ;
    USE SIGNAL ;
    PORT
      LAYER M4 ;
        RECT  86.316 97.776 86.4 97.8 ;
    END
  END rx_d[254]
  PIN rx_d[255]
    DIRECTION OUTPUT ;
    USE SIGNAL ;
    PORT
      LAYER M4 ;
        RECT  86.316 98.112 86.4 98.136 ;
    END
  END rx_d[255]
  PIN rx_d[256]
    DIRECTION OUTPUT ;
    USE SIGNAL ;
    PORT
      LAYER M4 ;
        RECT  86.316 98.4 86.4 98.424 ;
    END
  END rx_d[256]
  PIN rx_d[257]
    DIRECTION OUTPUT ;
    USE SIGNAL ;
    PORT
      LAYER M4 ;
        RECT  86.316 98.736 86.4 98.76 ;
    END
  END rx_d[257]
  PIN rx_d[258]
    DIRECTION OUTPUT ;
    USE SIGNAL ;
    PORT
      LAYER M4 ;
        RECT  86.316 99.072 86.4 99.096 ;
    END
  END rx_d[258]
  PIN rx_d[259]
    DIRECTION OUTPUT ;
    USE SIGNAL ;
    PORT
      LAYER M4 ;
        RECT  86.316 99.36 86.4 99.384 ;
    END
  END rx_d[259]
  PIN rx_d[25]
    DIRECTION OUTPUT ;
    USE SIGNAL ;
    PORT
      LAYER M4 ;
        RECT  86.316 25.344 86.4 25.368 ;
    END
  END rx_d[25]
  PIN rx_d[260]
    DIRECTION OUTPUT ;
    USE SIGNAL ;
    PORT
      LAYER M4 ;
        RECT  86.316 99.696 86.4 99.72 ;
    END
  END rx_d[260]
  PIN rx_d[261]
    DIRECTION OUTPUT ;
    USE SIGNAL ;
    PORT
      LAYER M4 ;
        RECT  86.316 99.984 86.4 100.008 ;
    END
  END rx_d[261]
  PIN rx_d[262]
    DIRECTION OUTPUT ;
    USE SIGNAL ;
    PORT
      LAYER M4 ;
        RECT  86.316 100.32 86.4 100.344 ;
    END
  END rx_d[262]
  PIN rx_d[263]
    DIRECTION OUTPUT ;
    USE SIGNAL ;
    PORT
      LAYER M4 ;
        RECT  86.316 100.656 86.4 100.68 ;
    END
  END rx_d[263]
  PIN rx_d[264]
    DIRECTION OUTPUT ;
    USE SIGNAL ;
    PORT
      LAYER M4 ;
        RECT  86.316 100.944 86.4 100.968 ;
    END
  END rx_d[264]
  PIN rx_d[265]
    DIRECTION OUTPUT ;
    USE SIGNAL ;
    PORT
      LAYER M4 ;
        RECT  86.316 101.28 86.4 101.304 ;
    END
  END rx_d[265]
  PIN rx_d[266]
    DIRECTION OUTPUT ;
    USE SIGNAL ;
    PORT
      LAYER M4 ;
        RECT  86.316 101.568 86.4 101.592 ;
    END
  END rx_d[266]
  PIN rx_d[267]
    DIRECTION OUTPUT ;
    USE SIGNAL ;
    PORT
      LAYER M4 ;
        RECT  86.316 101.904 86.4 101.928 ;
    END
  END rx_d[267]
  PIN rx_d[268]
    DIRECTION OUTPUT ;
    USE SIGNAL ;
    PORT
      LAYER M4 ;
        RECT  86.316 102.24 86.4 102.264 ;
    END
  END rx_d[268]
  PIN rx_d[269]
    DIRECTION OUTPUT ;
    USE SIGNAL ;
    PORT
      LAYER M4 ;
        RECT  86.316 102.528 86.4 102.552 ;
    END
  END rx_d[269]
  PIN rx_d[26]
    DIRECTION OUTPUT ;
    USE SIGNAL ;
    PORT
      LAYER M4 ;
        RECT  86.316 25.632 86.4 25.656 ;
    END
  END rx_d[26]
  PIN rx_d[270]
    DIRECTION OUTPUT ;
    USE SIGNAL ;
    PORT
      LAYER M4 ;
        RECT  86.316 102.864 86.4 102.888 ;
    END
  END rx_d[270]
  PIN rx_d[271]
    DIRECTION OUTPUT ;
    USE SIGNAL ;
    PORT
      LAYER M4 ;
        RECT  86.316 103.152 86.4 103.176 ;
    END
  END rx_d[271]
  PIN rx_d[272]
    DIRECTION OUTPUT ;
    USE SIGNAL ;
    PORT
      LAYER M4 ;
        RECT  86.316 103.488 86.4 103.512 ;
    END
  END rx_d[272]
  PIN rx_d[273]
    DIRECTION OUTPUT ;
    USE SIGNAL ;
    PORT
      LAYER M4 ;
        RECT  86.316 103.776 86.4 103.8 ;
    END
  END rx_d[273]
  PIN rx_d[274]
    DIRECTION OUTPUT ;
    USE SIGNAL ;
    PORT
      LAYER M4 ;
        RECT  86.316 104.112 86.4 104.136 ;
    END
  END rx_d[274]
  PIN rx_d[275]
    DIRECTION OUTPUT ;
    USE SIGNAL ;
    PORT
      LAYER M4 ;
        RECT  86.316 104.448 86.4 104.472 ;
    END
  END rx_d[275]
  PIN rx_d[276]
    DIRECTION OUTPUT ;
    USE SIGNAL ;
    PORT
      LAYER M4 ;
        RECT  86.316 104.736 86.4 104.76 ;
    END
  END rx_d[276]
  PIN rx_d[277]
    DIRECTION OUTPUT ;
    USE SIGNAL ;
    PORT
      LAYER M4 ;
        RECT  86.316 105.072 86.4 105.096 ;
    END
  END rx_d[277]
  PIN rx_d[278]
    DIRECTION OUTPUT ;
    USE SIGNAL ;
    PORT
      LAYER M4 ;
        RECT  86.316 105.36 86.4 105.384 ;
    END
  END rx_d[278]
  PIN rx_d[279]
    DIRECTION OUTPUT ;
    USE SIGNAL ;
    PORT
      LAYER M4 ;
        RECT  86.316 105.696 86.4 105.72 ;
    END
  END rx_d[279]
  PIN rx_d[27]
    DIRECTION OUTPUT ;
    USE SIGNAL ;
    PORT
      LAYER M4 ;
        RECT  86.316 25.968 86.4 25.992 ;
    END
  END rx_d[27]
  PIN rx_d[280]
    DIRECTION OUTPUT ;
    USE SIGNAL ;
    PORT
      LAYER M4 ;
        RECT  86.316 106.032 86.4 106.056 ;
    END
  END rx_d[280]
  PIN rx_d[281]
    DIRECTION OUTPUT ;
    USE SIGNAL ;
    PORT
      LAYER M4 ;
        RECT  86.316 106.32 86.4 106.344 ;
    END
  END rx_d[281]
  PIN rx_d[282]
    DIRECTION OUTPUT ;
    USE SIGNAL ;
    PORT
      LAYER M4 ;
        RECT  86.316 106.656 86.4 106.68 ;
    END
  END rx_d[282]
  PIN rx_d[283]
    DIRECTION OUTPUT ;
    USE SIGNAL ;
    PORT
      LAYER M4 ;
        RECT  86.316 106.944 86.4 106.968 ;
    END
  END rx_d[283]
  PIN rx_d[284]
    DIRECTION OUTPUT ;
    USE SIGNAL ;
    PORT
      LAYER M4 ;
        RECT  86.316 107.28 86.4 107.304 ;
    END
  END rx_d[284]
  PIN rx_d[285]
    DIRECTION OUTPUT ;
    USE SIGNAL ;
    PORT
      LAYER M4 ;
        RECT  86.316 107.616 86.4 107.64 ;
    END
  END rx_d[285]
  PIN rx_d[286]
    DIRECTION OUTPUT ;
    USE SIGNAL ;
    PORT
      LAYER M4 ;
        RECT  86.316 107.904 86.4 107.928 ;
    END
  END rx_d[286]
  PIN rx_d[287]
    DIRECTION OUTPUT ;
    USE SIGNAL ;
    PORT
      LAYER M4 ;
        RECT  86.316 108.24 86.4 108.264 ;
    END
  END rx_d[287]
  PIN rx_d[288]
    DIRECTION OUTPUT ;
    USE SIGNAL ;
    PORT
      LAYER M4 ;
        RECT  86.316 108.528 86.4 108.552 ;
    END
  END rx_d[288]
  PIN rx_d[289]
    DIRECTION OUTPUT ;
    USE SIGNAL ;
    PORT
      LAYER M4 ;
        RECT  86.316 108.864 86.4 108.888 ;
    END
  END rx_d[289]
  PIN rx_d[28]
    DIRECTION OUTPUT ;
    USE SIGNAL ;
    PORT
      LAYER M4 ;
        RECT  86.316 26.304 86.4 26.328 ;
    END
  END rx_d[28]
  PIN rx_d[290]
    DIRECTION OUTPUT ;
    USE SIGNAL ;
    PORT
      LAYER M4 ;
        RECT  86.316 109.2 86.4 109.224 ;
    END
  END rx_d[290]
  PIN rx_d[291]
    DIRECTION OUTPUT ;
    USE SIGNAL ;
    PORT
      LAYER M4 ;
        RECT  86.316 109.488 86.4 109.512 ;
    END
  END rx_d[291]
  PIN rx_d[292]
    DIRECTION OUTPUT ;
    USE SIGNAL ;
    PORT
      LAYER M4 ;
        RECT  86.316 109.824 86.4 109.848 ;
    END
  END rx_d[292]
  PIN rx_d[293]
    DIRECTION OUTPUT ;
    USE SIGNAL ;
    PORT
      LAYER M4 ;
        RECT  86.316 110.112 86.4 110.136 ;
    END
  END rx_d[293]
  PIN rx_d[294]
    DIRECTION OUTPUT ;
    USE SIGNAL ;
    PORT
      LAYER M4 ;
        RECT  86.316 110.448 86.4 110.472 ;
    END
  END rx_d[294]
  PIN rx_d[295]
    DIRECTION OUTPUT ;
    USE SIGNAL ;
    PORT
      LAYER M4 ;
        RECT  86.316 110.736 86.4 110.76 ;
    END
  END rx_d[295]
  PIN rx_d[296]
    DIRECTION OUTPUT ;
    USE SIGNAL ;
    PORT
      LAYER M4 ;
        RECT  86.316 111.072 86.4 111.096 ;
    END
  END rx_d[296]
  PIN rx_d[297]
    DIRECTION OUTPUT ;
    USE SIGNAL ;
    PORT
      LAYER M4 ;
        RECT  86.316 111.408 86.4 111.432 ;
    END
  END rx_d[297]
  PIN rx_d[298]
    DIRECTION OUTPUT ;
    USE SIGNAL ;
    PORT
      LAYER M4 ;
        RECT  86.316 111.696 86.4 111.72 ;
    END
  END rx_d[298]
  PIN rx_d[299]
    DIRECTION OUTPUT ;
    USE SIGNAL ;
    PORT
      LAYER M4 ;
        RECT  86.316 112.032 86.4 112.056 ;
    END
  END rx_d[299]
  PIN rx_d[29]
    DIRECTION OUTPUT ;
    USE SIGNAL ;
    PORT
      LAYER M4 ;
        RECT  86.316 26.592 86.4 26.616 ;
    END
  END rx_d[29]
  PIN rx_d[2]
    DIRECTION OUTPUT ;
    USE SIGNAL ;
    PORT
      LAYER M4 ;
        RECT  86.316 18.048 86.4 18.072 ;
    END
  END rx_d[2]
  PIN rx_d[300]
    DIRECTION OUTPUT ;
    USE SIGNAL ;
    PORT
      LAYER M4 ;
        RECT  86.316 112.32 86.4 112.344 ;
    END
  END rx_d[300]
  PIN rx_d[301]
    DIRECTION OUTPUT ;
    USE SIGNAL ;
    PORT
      LAYER M4 ;
        RECT  86.316 112.656 86.4 112.68 ;
    END
  END rx_d[301]
  PIN rx_d[302]
    DIRECTION OUTPUT ;
    USE SIGNAL ;
    PORT
      LAYER M4 ;
        RECT  86.316 112.992 86.4 113.016 ;
    END
  END rx_d[302]
  PIN rx_d[303]
    DIRECTION OUTPUT ;
    USE SIGNAL ;
    PORT
      LAYER M4 ;
        RECT  86.316 113.28 86.4 113.304 ;
    END
  END rx_d[303]
  PIN rx_d[304]
    DIRECTION OUTPUT ;
    USE SIGNAL ;
    PORT
      LAYER M4 ;
        RECT  86.316 113.616 86.4 113.64 ;
    END
  END rx_d[304]
  PIN rx_d[305]
    DIRECTION OUTPUT ;
    USE SIGNAL ;
    PORT
      LAYER M4 ;
        RECT  86.316 113.904 86.4 113.928 ;
    END
  END rx_d[305]
  PIN rx_d[306]
    DIRECTION OUTPUT ;
    USE SIGNAL ;
    PORT
      LAYER M4 ;
        RECT  86.316 114.24 86.4 114.264 ;
    END
  END rx_d[306]
  PIN rx_d[307]
    DIRECTION OUTPUT ;
    USE SIGNAL ;
    PORT
      LAYER M4 ;
        RECT  86.316 114.576 86.4 114.6 ;
    END
  END rx_d[307]
  PIN rx_d[308]
    DIRECTION OUTPUT ;
    USE SIGNAL ;
    PORT
      LAYER M4 ;
        RECT  86.316 114.864 86.4 114.888 ;
    END
  END rx_d[308]
  PIN rx_d[309]
    DIRECTION OUTPUT ;
    USE SIGNAL ;
    PORT
      LAYER M4 ;
        RECT  86.316 115.2 86.4 115.224 ;
    END
  END rx_d[309]
  PIN rx_d[30]
    DIRECTION OUTPUT ;
    USE SIGNAL ;
    PORT
      LAYER M4 ;
        RECT  86.316 26.928 86.4 26.952 ;
    END
  END rx_d[30]
  PIN rx_d[310]
    DIRECTION OUTPUT ;
    USE SIGNAL ;
    PORT
      LAYER M4 ;
        RECT  86.316 115.488 86.4 115.512 ;
    END
  END rx_d[310]
  PIN rx_d[311]
    DIRECTION OUTPUT ;
    USE SIGNAL ;
    PORT
      LAYER M4 ;
        RECT  86.316 115.824 86.4 115.848 ;
    END
  END rx_d[311]
  PIN rx_d[312]
    DIRECTION OUTPUT ;
    USE SIGNAL ;
    PORT
      LAYER M4 ;
        RECT  86.316 116.16 86.4 116.184 ;
    END
  END rx_d[312]
  PIN rx_d[313]
    DIRECTION OUTPUT ;
    USE SIGNAL ;
    PORT
      LAYER M4 ;
        RECT  86.316 116.448 86.4 116.472 ;
    END
  END rx_d[313]
  PIN rx_d[314]
    DIRECTION OUTPUT ;
    USE SIGNAL ;
    PORT
      LAYER M4 ;
        RECT  86.316 116.784 86.4 116.808 ;
    END
  END rx_d[314]
  PIN rx_d[315]
    DIRECTION OUTPUT ;
    USE SIGNAL ;
    PORT
      LAYER M4 ;
        RECT  86.316 117.072 86.4 117.096 ;
    END
  END rx_d[315]
  PIN rx_d[316]
    DIRECTION OUTPUT ;
    USE SIGNAL ;
    PORT
      LAYER M4 ;
        RECT  86.316 117.408 86.4 117.432 ;
    END
  END rx_d[316]
  PIN rx_d[317]
    DIRECTION OUTPUT ;
    USE SIGNAL ;
    PORT
      LAYER M4 ;
        RECT  86.316 117.744 86.4 117.768 ;
    END
  END rx_d[317]
  PIN rx_d[318]
    DIRECTION OUTPUT ;
    USE SIGNAL ;
    PORT
      LAYER M4 ;
        RECT  86.316 118.032 86.4 118.056 ;
    END
  END rx_d[318]
  PIN rx_d[319]
    DIRECTION OUTPUT ;
    USE SIGNAL ;
    PORT
      LAYER M4 ;
        RECT  86.316 118.368 86.4 118.392 ;
    END
  END rx_d[319]
  PIN rx_d[31]
    DIRECTION OUTPUT ;
    USE SIGNAL ;
    PORT
      LAYER M4 ;
        RECT  86.316 27.216 86.4 27.24 ;
    END
  END rx_d[31]
  PIN rx_d[320]
    DIRECTION OUTPUT ;
    USE SIGNAL ;
    PORT
      LAYER M4 ;
        RECT  86.316 118.656 86.4 118.68 ;
    END
  END rx_d[320]
  PIN rx_d[321]
    DIRECTION OUTPUT ;
    USE SIGNAL ;
    PORT
      LAYER M4 ;
        RECT  86.316 118.992 86.4 119.016 ;
    END
  END rx_d[321]
  PIN rx_d[322]
    DIRECTION OUTPUT ;
    USE SIGNAL ;
    PORT
      LAYER M4 ;
        RECT  86.316 119.28 86.4 119.304 ;
    END
  END rx_d[322]
  PIN rx_d[323]
    DIRECTION OUTPUT ;
    USE SIGNAL ;
    PORT
      LAYER M4 ;
        RECT  86.316 119.616 86.4 119.64 ;
    END
  END rx_d[323]
  PIN rx_d[324]
    DIRECTION OUTPUT ;
    USE SIGNAL ;
    PORT
      LAYER M4 ;
        RECT  86.316 119.952 86.4 119.976 ;
    END
  END rx_d[324]
  PIN rx_d[325]
    DIRECTION OUTPUT ;
    USE SIGNAL ;
    PORT
      LAYER M4 ;
        RECT  86.316 120.24 86.4 120.264 ;
    END
  END rx_d[325]
  PIN rx_d[326]
    DIRECTION OUTPUT ;
    USE SIGNAL ;
    PORT
      LAYER M4 ;
        RECT  86.316 120.576 86.4 120.6 ;
    END
  END rx_d[326]
  PIN rx_d[327]
    DIRECTION OUTPUT ;
    USE SIGNAL ;
    PORT
      LAYER M4 ;
        RECT  86.316 120.864 86.4 120.888 ;
    END
  END rx_d[327]
  PIN rx_d[328]
    DIRECTION OUTPUT ;
    USE SIGNAL ;
    PORT
      LAYER M4 ;
        RECT  86.316 121.2 86.4 121.224 ;
    END
  END rx_d[328]
  PIN rx_d[329]
    DIRECTION OUTPUT ;
    USE SIGNAL ;
    PORT
      LAYER M4 ;
        RECT  86.316 121.536 86.4 121.56 ;
    END
  END rx_d[329]
  PIN rx_d[32]
    DIRECTION OUTPUT ;
    USE SIGNAL ;
    PORT
      LAYER M4 ;
        RECT  86.316 27.552 86.4 27.576 ;
    END
  END rx_d[32]
  PIN rx_d[330]
    DIRECTION OUTPUT ;
    USE SIGNAL ;
    PORT
      LAYER M4 ;
        RECT  86.316 121.824 86.4 121.848 ;
    END
  END rx_d[330]
  PIN rx_d[331]
    DIRECTION OUTPUT ;
    USE SIGNAL ;
    PORT
      LAYER M4 ;
        RECT  86.316 122.16 86.4 122.184 ;
    END
  END rx_d[331]
  PIN rx_d[332]
    DIRECTION OUTPUT ;
    USE SIGNAL ;
    PORT
      LAYER M4 ;
        RECT  86.316 122.448 86.4 122.472 ;
    END
  END rx_d[332]
  PIN rx_d[333]
    DIRECTION OUTPUT ;
    USE SIGNAL ;
    PORT
      LAYER M4 ;
        RECT  86.316 122.784 86.4 122.808 ;
    END
  END rx_d[333]
  PIN rx_d[334]
    DIRECTION OUTPUT ;
    USE SIGNAL ;
    PORT
      LAYER M4 ;
        RECT  86.316 123.12 86.4 123.144 ;
    END
  END rx_d[334]
  PIN rx_d[335]
    DIRECTION OUTPUT ;
    USE SIGNAL ;
    PORT
      LAYER M4 ;
        RECT  86.316 123.408 86.4 123.432 ;
    END
  END rx_d[335]
  PIN rx_d[336]
    DIRECTION OUTPUT ;
    USE SIGNAL ;
    PORT
      LAYER M4 ;
        RECT  86.316 123.744 86.4 123.768 ;
    END
  END rx_d[336]
  PIN rx_d[337]
    DIRECTION OUTPUT ;
    USE SIGNAL ;
    PORT
      LAYER M4 ;
        RECT  86.316 124.032 86.4 124.056 ;
    END
  END rx_d[337]
  PIN rx_d[338]
    DIRECTION OUTPUT ;
    USE SIGNAL ;
    PORT
      LAYER M4 ;
        RECT  86.316 124.368 86.4 124.392 ;
    END
  END rx_d[338]
  PIN rx_d[339]
    DIRECTION OUTPUT ;
    USE SIGNAL ;
    PORT
      LAYER M4 ;
        RECT  86.316 124.704 86.4 124.728 ;
    END
  END rx_d[339]
  PIN rx_d[33]
    DIRECTION OUTPUT ;
    USE SIGNAL ;
    PORT
      LAYER M4 ;
        RECT  86.316 27.888 86.4 27.912 ;
    END
  END rx_d[33]
  PIN rx_d[340]
    DIRECTION OUTPUT ;
    USE SIGNAL ;
    PORT
      LAYER M4 ;
        RECT  86.316 124.992 86.4 125.016 ;
    END
  END rx_d[340]
  PIN rx_d[341]
    DIRECTION OUTPUT ;
    USE SIGNAL ;
    PORT
      LAYER M4 ;
        RECT  86.316 125.328 86.4 125.352 ;
    END
  END rx_d[341]
  PIN rx_d[342]
    DIRECTION OUTPUT ;
    USE SIGNAL ;
    PORT
      LAYER M4 ;
        RECT  86.316 125.616 86.4 125.64 ;
    END
  END rx_d[342]
  PIN rx_d[343]
    DIRECTION OUTPUT ;
    USE SIGNAL ;
    PORT
      LAYER M4 ;
        RECT  86.316 125.952 86.4 125.976 ;
    END
  END rx_d[343]
  PIN rx_d[344]
    DIRECTION OUTPUT ;
    USE SIGNAL ;
    PORT
      LAYER M4 ;
        RECT  86.316 126.24 86.4 126.264 ;
    END
  END rx_d[344]
  PIN rx_d[345]
    DIRECTION OUTPUT ;
    USE SIGNAL ;
    PORT
      LAYER M4 ;
        RECT  86.316 126.576 86.4 126.6 ;
    END
  END rx_d[345]
  PIN rx_d[346]
    DIRECTION OUTPUT ;
    USE SIGNAL ;
    PORT
      LAYER M4 ;
        RECT  86.316 126.912 86.4 126.936 ;
    END
  END rx_d[346]
  PIN rx_d[347]
    DIRECTION OUTPUT ;
    USE SIGNAL ;
    PORT
      LAYER M4 ;
        RECT  86.316 127.2 86.4 127.224 ;
    END
  END rx_d[347]
  PIN rx_d[348]
    DIRECTION OUTPUT ;
    USE SIGNAL ;
    PORT
      LAYER M4 ;
        RECT  86.316 127.536 86.4 127.56 ;
    END
  END rx_d[348]
  PIN rx_d[349]
    DIRECTION OUTPUT ;
    USE SIGNAL ;
    PORT
      LAYER M4 ;
        RECT  86.316 127.824 86.4 127.848 ;
    END
  END rx_d[349]
  PIN rx_d[34]
    DIRECTION OUTPUT ;
    USE SIGNAL ;
    PORT
      LAYER M4 ;
        RECT  86.316 28.176 86.4 28.2 ;
    END
  END rx_d[34]
  PIN rx_d[350]
    DIRECTION OUTPUT ;
    USE SIGNAL ;
    PORT
      LAYER M4 ;
        RECT  86.316 128.16 86.4 128.184 ;
    END
  END rx_d[350]
  PIN rx_d[351]
    DIRECTION OUTPUT ;
    USE SIGNAL ;
    PORT
      LAYER M4 ;
        RECT  86.316 128.496 86.4 128.52 ;
    END
  END rx_d[351]
  PIN rx_d[352]
    DIRECTION OUTPUT ;
    USE SIGNAL ;
    PORT
      LAYER M4 ;
        RECT  86.316 128.784 86.4 128.808 ;
    END
  END rx_d[352]
  PIN rx_d[353]
    DIRECTION OUTPUT ;
    USE SIGNAL ;
    PORT
      LAYER M4 ;
        RECT  86.316 129.12 86.4 129.144 ;
    END
  END rx_d[353]
  PIN rx_d[354]
    DIRECTION OUTPUT ;
    USE SIGNAL ;
    PORT
      LAYER M4 ;
        RECT  86.316 129.408 86.4 129.432 ;
    END
  END rx_d[354]
  PIN rx_d[355]
    DIRECTION OUTPUT ;
    USE SIGNAL ;
    PORT
      LAYER M4 ;
        RECT  86.316 129.744 86.4 129.768 ;
    END
  END rx_d[355]
  PIN rx_d[356]
    DIRECTION OUTPUT ;
    USE SIGNAL ;
    PORT
      LAYER M4 ;
        RECT  86.316 130.08 86.4 130.104 ;
    END
  END rx_d[356]
  PIN rx_d[357]
    DIRECTION OUTPUT ;
    USE SIGNAL ;
    PORT
      LAYER M4 ;
        RECT  86.316 130.368 86.4 130.392 ;
    END
  END rx_d[357]
  PIN rx_d[358]
    DIRECTION OUTPUT ;
    USE SIGNAL ;
    PORT
      LAYER M4 ;
        RECT  86.316 130.704 86.4 130.728 ;
    END
  END rx_d[358]
  PIN rx_d[359]
    DIRECTION OUTPUT ;
    USE SIGNAL ;
    PORT
      LAYER M4 ;
        RECT  86.316 130.992 86.4 131.016 ;
    END
  END rx_d[359]
  PIN rx_d[35]
    DIRECTION OUTPUT ;
    USE SIGNAL ;
    PORT
      LAYER M4 ;
        RECT  86.316 28.512 86.4 28.536 ;
    END
  END rx_d[35]
  PIN rx_d[360]
    DIRECTION OUTPUT ;
    USE SIGNAL ;
    PORT
      LAYER M4 ;
        RECT  86.316 131.328 86.4 131.352 ;
    END
  END rx_d[360]
  PIN rx_d[361]
    DIRECTION OUTPUT ;
    USE SIGNAL ;
    PORT
      LAYER M4 ;
        RECT  86.316 131.664 86.4 131.688 ;
    END
  END rx_d[361]
  PIN rx_d[362]
    DIRECTION OUTPUT ;
    USE SIGNAL ;
    PORT
      LAYER M4 ;
        RECT  86.316 131.952 86.4 131.976 ;
    END
  END rx_d[362]
  PIN rx_d[363]
    DIRECTION OUTPUT ;
    USE SIGNAL ;
    PORT
      LAYER M4 ;
        RECT  86.316 132.288 86.4 132.312 ;
    END
  END rx_d[363]
  PIN rx_d[364]
    DIRECTION OUTPUT ;
    USE SIGNAL ;
    PORT
      LAYER M4 ;
        RECT  86.316 132.576 86.4 132.6 ;
    END
  END rx_d[364]
  PIN rx_d[365]
    DIRECTION OUTPUT ;
    USE SIGNAL ;
    PORT
      LAYER M4 ;
        RECT  86.316 132.912 86.4 132.936 ;
    END
  END rx_d[365]
  PIN rx_d[366]
    DIRECTION OUTPUT ;
    USE SIGNAL ;
    PORT
      LAYER M4 ;
        RECT  86.316 133.2 86.4 133.224 ;
    END
  END rx_d[366]
  PIN rx_d[367]
    DIRECTION OUTPUT ;
    USE SIGNAL ;
    PORT
      LAYER M4 ;
        RECT  86.316 133.536 86.4 133.56 ;
    END
  END rx_d[367]
  PIN rx_d[368]
    DIRECTION OUTPUT ;
    USE SIGNAL ;
    PORT
      LAYER M4 ;
        RECT  86.316 133.872 86.4 133.896 ;
    END
  END rx_d[368]
  PIN rx_d[369]
    DIRECTION OUTPUT ;
    USE SIGNAL ;
    PORT
      LAYER M4 ;
        RECT  86.316 134.16 86.4 134.184 ;
    END
  END rx_d[369]
  PIN rx_d[36]
    DIRECTION OUTPUT ;
    USE SIGNAL ;
    PORT
      LAYER M4 ;
        RECT  86.316 28.8 86.4 28.824 ;
    END
  END rx_d[36]
  PIN rx_d[370]
    DIRECTION OUTPUT ;
    USE SIGNAL ;
    PORT
      LAYER M4 ;
        RECT  86.316 134.496 86.4 134.52 ;
    END
  END rx_d[370]
  PIN rx_d[371]
    DIRECTION OUTPUT ;
    USE SIGNAL ;
    PORT
      LAYER M4 ;
        RECT  86.316 134.784 86.4 134.808 ;
    END
  END rx_d[371]
  PIN rx_d[372]
    DIRECTION OUTPUT ;
    USE SIGNAL ;
    PORT
      LAYER M4 ;
        RECT  86.316 135.12 86.4 135.144 ;
    END
  END rx_d[372]
  PIN rx_d[373]
    DIRECTION OUTPUT ;
    USE SIGNAL ;
    PORT
      LAYER M4 ;
        RECT  86.316 135.456 86.4 135.48 ;
    END
  END rx_d[373]
  PIN rx_d[374]
    DIRECTION OUTPUT ;
    USE SIGNAL ;
    PORT
      LAYER M4 ;
        RECT  86.316 135.744 86.4 135.768 ;
    END
  END rx_d[374]
  PIN rx_d[375]
    DIRECTION OUTPUT ;
    USE SIGNAL ;
    PORT
      LAYER M4 ;
        RECT  86.316 136.08 86.4 136.104 ;
    END
  END rx_d[375]
  PIN rx_d[376]
    DIRECTION OUTPUT ;
    USE SIGNAL ;
    PORT
      LAYER M4 ;
        RECT  86.316 136.368 86.4 136.392 ;
    END
  END rx_d[376]
  PIN rx_d[377]
    DIRECTION OUTPUT ;
    USE SIGNAL ;
    PORT
      LAYER M4 ;
        RECT  86.316 136.704 86.4 136.728 ;
    END
  END rx_d[377]
  PIN rx_d[378]
    DIRECTION OUTPUT ;
    USE SIGNAL ;
    PORT
      LAYER M4 ;
        RECT  86.316 137.04 86.4 137.064 ;
    END
  END rx_d[378]
  PIN rx_d[379]
    DIRECTION OUTPUT ;
    USE SIGNAL ;
    PORT
      LAYER M4 ;
        RECT  86.316 137.328 86.4 137.352 ;
    END
  END rx_d[379]
  PIN rx_d[37]
    DIRECTION OUTPUT ;
    USE SIGNAL ;
    PORT
      LAYER M4 ;
        RECT  86.316 29.136 86.4 29.16 ;
    END
  END rx_d[37]
  PIN rx_d[380]
    DIRECTION OUTPUT ;
    USE SIGNAL ;
    PORT
      LAYER M4 ;
        RECT  86.316 137.664 86.4 137.688 ;
    END
  END rx_d[380]
  PIN rx_d[381]
    DIRECTION OUTPUT ;
    USE SIGNAL ;
    PORT
      LAYER M4 ;
        RECT  86.316 137.952 86.4 137.976 ;
    END
  END rx_d[381]
  PIN rx_d[382]
    DIRECTION OUTPUT ;
    USE SIGNAL ;
    PORT
      LAYER M4 ;
        RECT  86.316 138.288 86.4 138.312 ;
    END
  END rx_d[382]
  PIN rx_d[383]
    DIRECTION OUTPUT ;
    USE SIGNAL ;
    PORT
      LAYER M4 ;
        RECT  86.316 138.624 86.4 138.648 ;
    END
  END rx_d[383]
  PIN rx_d[384]
    DIRECTION OUTPUT ;
    USE SIGNAL ;
    PORT
      LAYER M4 ;
        RECT  86.316 138.912 86.4 138.936 ;
    END
  END rx_d[384]
  PIN rx_d[385]
    DIRECTION OUTPUT ;
    USE SIGNAL ;
    PORT
      LAYER M4 ;
        RECT  86.316 139.248 86.4 139.272 ;
    END
  END rx_d[385]
  PIN rx_d[386]
    DIRECTION OUTPUT ;
    USE SIGNAL ;
    PORT
      LAYER M4 ;
        RECT  86.316 139.536 86.4 139.56 ;
    END
  END rx_d[386]
  PIN rx_d[387]
    DIRECTION OUTPUT ;
    USE SIGNAL ;
    PORT
      LAYER M4 ;
        RECT  86.316 139.872 86.4 139.896 ;
    END
  END rx_d[387]
  PIN rx_d[388]
    DIRECTION OUTPUT ;
    USE SIGNAL ;
    PORT
      LAYER M4 ;
        RECT  86.316 140.16 86.4 140.184 ;
    END
  END rx_d[388]
  PIN rx_d[389]
    DIRECTION OUTPUT ;
    USE SIGNAL ;
    PORT
      LAYER M4 ;
        RECT  86.316 140.496 86.4 140.52 ;
    END
  END rx_d[389]
  PIN rx_d[38]
    DIRECTION OUTPUT ;
    USE SIGNAL ;
    PORT
      LAYER M4 ;
        RECT  86.316 29.472 86.4 29.496 ;
    END
  END rx_d[38]
  PIN rx_d[390]
    DIRECTION OUTPUT ;
    USE SIGNAL ;
    PORT
      LAYER M4 ;
        RECT  86.316 140.832 86.4 140.856 ;
    END
  END rx_d[390]
  PIN rx_d[391]
    DIRECTION OUTPUT ;
    USE SIGNAL ;
    PORT
      LAYER M4 ;
        RECT  86.316 141.12 86.4 141.144 ;
    END
  END rx_d[391]
  PIN rx_d[392]
    DIRECTION OUTPUT ;
    USE SIGNAL ;
    PORT
      LAYER M4 ;
        RECT  86.316 141.456 86.4 141.48 ;
    END
  END rx_d[392]
  PIN rx_d[393]
    DIRECTION OUTPUT ;
    USE SIGNAL ;
    PORT
      LAYER M4 ;
        RECT  86.316 141.744 86.4 141.768 ;
    END
  END rx_d[393]
  PIN rx_d[394]
    DIRECTION OUTPUT ;
    USE SIGNAL ;
    PORT
      LAYER M4 ;
        RECT  86.316 142.08 86.4 142.104 ;
    END
  END rx_d[394]
  PIN rx_d[395]
    DIRECTION OUTPUT ;
    USE SIGNAL ;
    PORT
      LAYER M4 ;
        RECT  86.316 142.416 86.4 142.44 ;
    END
  END rx_d[395]
  PIN rx_d[396]
    DIRECTION OUTPUT ;
    USE SIGNAL ;
    PORT
      LAYER M4 ;
        RECT  86.316 142.704 86.4 142.728 ;
    END
  END rx_d[396]
  PIN rx_d[397]
    DIRECTION OUTPUT ;
    USE SIGNAL ;
    PORT
      LAYER M4 ;
        RECT  86.316 143.04 86.4 143.064 ;
    END
  END rx_d[397]
  PIN rx_d[398]
    DIRECTION OUTPUT ;
    USE SIGNAL ;
    PORT
      LAYER M4 ;
        RECT  86.316 143.328 86.4 143.352 ;
    END
  END rx_d[398]
  PIN rx_d[399]
    DIRECTION OUTPUT ;
    USE SIGNAL ;
    PORT
      LAYER M4 ;
        RECT  86.316 143.664 86.4 143.688 ;
    END
  END rx_d[399]
  PIN rx_d[39]
    DIRECTION OUTPUT ;
    USE SIGNAL ;
    PORT
      LAYER M4 ;
        RECT  86.316 29.76 86.4 29.784 ;
    END
  END rx_d[39]
  PIN rx_d[3]
    DIRECTION OUTPUT ;
    USE SIGNAL ;
    PORT
      LAYER M4 ;
        RECT  86.316 18.384 86.4 18.408 ;
    END
  END rx_d[3]
  PIN rx_d[400]
    DIRECTION OUTPUT ;
    USE SIGNAL ;
    PORT
      LAYER M4 ;
        RECT  86.316 144 86.4 144.024 ;
    END
  END rx_d[400]
  PIN rx_d[401]
    DIRECTION OUTPUT ;
    USE SIGNAL ;
    PORT
      LAYER M4 ;
        RECT  86.316 144.288 86.4 144.312 ;
    END
  END rx_d[401]
  PIN rx_d[402]
    DIRECTION OUTPUT ;
    USE SIGNAL ;
    PORT
      LAYER M4 ;
        RECT  86.316 144.624 86.4 144.648 ;
    END
  END rx_d[402]
  PIN rx_d[403]
    DIRECTION OUTPUT ;
    USE SIGNAL ;
    PORT
      LAYER M4 ;
        RECT  86.316 144.912 86.4 144.936 ;
    END
  END rx_d[403]
  PIN rx_d[404]
    DIRECTION OUTPUT ;
    USE SIGNAL ;
    PORT
      LAYER M4 ;
        RECT  86.316 145.248 86.4 145.272 ;
    END
  END rx_d[404]
  PIN rx_d[405]
    DIRECTION OUTPUT ;
    USE SIGNAL ;
    PORT
      LAYER M4 ;
        RECT  86.316 145.584 86.4 145.608 ;
    END
  END rx_d[405]
  PIN rx_d[406]
    DIRECTION OUTPUT ;
    USE SIGNAL ;
    PORT
      LAYER M4 ;
        RECT  86.316 145.872 86.4 145.896 ;
    END
  END rx_d[406]
  PIN rx_d[407]
    DIRECTION OUTPUT ;
    USE SIGNAL ;
    PORT
      LAYER M4 ;
        RECT  86.316 146.208 86.4 146.232 ;
    END
  END rx_d[407]
  PIN rx_d[408]
    DIRECTION OUTPUT ;
    USE SIGNAL ;
    PORT
      LAYER M4 ;
        RECT  86.316 146.496 86.4 146.52 ;
    END
  END rx_d[408]
  PIN rx_d[409]
    DIRECTION OUTPUT ;
    USE SIGNAL ;
    PORT
      LAYER M4 ;
        RECT  86.316 146.832 86.4 146.856 ;
    END
  END rx_d[409]
  PIN rx_d[40]
    DIRECTION OUTPUT ;
    USE SIGNAL ;
    PORT
      LAYER M4 ;
        RECT  86.316 30.096 86.4 30.12 ;
    END
  END rx_d[40]
  PIN rx_d[410]
    DIRECTION OUTPUT ;
    USE SIGNAL ;
    PORT
      LAYER M4 ;
        RECT  86.316 147.12 86.4 147.144 ;
    END
  END rx_d[410]
  PIN rx_d[411]
    DIRECTION OUTPUT ;
    USE SIGNAL ;
    PORT
      LAYER M4 ;
        RECT  86.316 147.456 86.4 147.48 ;
    END
  END rx_d[411]
  PIN rx_d[412]
    DIRECTION OUTPUT ;
    USE SIGNAL ;
    PORT
      LAYER M4 ;
        RECT  86.316 147.792 86.4 147.816 ;
    END
  END rx_d[412]
  PIN rx_d[413]
    DIRECTION OUTPUT ;
    USE SIGNAL ;
    PORT
      LAYER M4 ;
        RECT  86.316 148.08 86.4 148.104 ;
    END
  END rx_d[413]
  PIN rx_d[414]
    DIRECTION OUTPUT ;
    USE SIGNAL ;
    PORT
      LAYER M4 ;
        RECT  86.316 148.416 86.4 148.44 ;
    END
  END rx_d[414]
  PIN rx_d[415]
    DIRECTION OUTPUT ;
    USE SIGNAL ;
    PORT
      LAYER M4 ;
        RECT  86.316 148.704 86.4 148.728 ;
    END
  END rx_d[415]
  PIN rx_d[416]
    DIRECTION OUTPUT ;
    USE SIGNAL ;
    PORT
      LAYER M4 ;
        RECT  86.316 149.04 86.4 149.064 ;
    END
  END rx_d[416]
  PIN rx_d[417]
    DIRECTION OUTPUT ;
    USE SIGNAL ;
    PORT
      LAYER M4 ;
        RECT  86.316 149.376 86.4 149.4 ;
    END
  END rx_d[417]
  PIN rx_d[418]
    DIRECTION OUTPUT ;
    USE SIGNAL ;
    PORT
      LAYER M4 ;
        RECT  86.316 149.664 86.4 149.688 ;
    END
  END rx_d[418]
  PIN rx_d[419]
    DIRECTION OUTPUT ;
    USE SIGNAL ;
    PORT
      LAYER M4 ;
        RECT  86.316 150 86.4 150.024 ;
    END
  END rx_d[419]
  PIN rx_d[41]
    DIRECTION OUTPUT ;
    USE SIGNAL ;
    PORT
      LAYER M4 ;
        RECT  86.316 30.384 86.4 30.408 ;
    END
  END rx_d[41]
  PIN rx_d[420]
    DIRECTION OUTPUT ;
    USE SIGNAL ;
    PORT
      LAYER M4 ;
        RECT  86.316 150.288 86.4 150.312 ;
    END
  END rx_d[420]
  PIN rx_d[421]
    DIRECTION OUTPUT ;
    USE SIGNAL ;
    PORT
      LAYER M4 ;
        RECT  86.316 150.624 86.4 150.648 ;
    END
  END rx_d[421]
  PIN rx_d[422]
    DIRECTION OUTPUT ;
    USE SIGNAL ;
    PORT
      LAYER M4 ;
        RECT  86.316 150.96 86.4 150.984 ;
    END
  END rx_d[422]
  PIN rx_d[423]
    DIRECTION OUTPUT ;
    USE SIGNAL ;
    PORT
      LAYER M4 ;
        RECT  86.316 151.248 86.4 151.272 ;
    END
  END rx_d[423]
  PIN rx_d[424]
    DIRECTION OUTPUT ;
    USE SIGNAL ;
    PORT
      LAYER M4 ;
        RECT  86.316 151.584 86.4 151.608 ;
    END
  END rx_d[424]
  PIN rx_d[425]
    DIRECTION OUTPUT ;
    USE SIGNAL ;
    PORT
      LAYER M4 ;
        RECT  86.316 151.872 86.4 151.896 ;
    END
  END rx_d[425]
  PIN rx_d[426]
    DIRECTION OUTPUT ;
    USE SIGNAL ;
    PORT
      LAYER M4 ;
        RECT  86.316 152.208 86.4 152.232 ;
    END
  END rx_d[426]
  PIN rx_d[427]
    DIRECTION OUTPUT ;
    USE SIGNAL ;
    PORT
      LAYER M4 ;
        RECT  86.316 152.544 86.4 152.568 ;
    END
  END rx_d[427]
  PIN rx_d[428]
    DIRECTION OUTPUT ;
    USE SIGNAL ;
    PORT
      LAYER M4 ;
        RECT  86.316 152.832 86.4 152.856 ;
    END
  END rx_d[428]
  PIN rx_d[429]
    DIRECTION OUTPUT ;
    USE SIGNAL ;
    PORT
      LAYER M4 ;
        RECT  86.316 153.168 86.4 153.192 ;
    END
  END rx_d[429]
  PIN rx_d[42]
    DIRECTION OUTPUT ;
    USE SIGNAL ;
    PORT
      LAYER M4 ;
        RECT  86.316 30.72 86.4 30.744 ;
    END
  END rx_d[42]
  PIN rx_d[430]
    DIRECTION OUTPUT ;
    USE SIGNAL ;
    PORT
      LAYER M4 ;
        RECT  86.316 153.456 86.4 153.48 ;
    END
  END rx_d[430]
  PIN rx_d[431]
    DIRECTION OUTPUT ;
    USE SIGNAL ;
    PORT
      LAYER M4 ;
        RECT  86.316 153.792 86.4 153.816 ;
    END
  END rx_d[431]
  PIN rx_d[432]
    DIRECTION OUTPUT ;
    USE SIGNAL ;
    PORT
      LAYER M4 ;
        RECT  86.316 154.128 86.4 154.152 ;
    END
  END rx_d[432]
  PIN rx_d[433]
    DIRECTION OUTPUT ;
    USE SIGNAL ;
    PORT
      LAYER M4 ;
        RECT  86.316 154.416 86.4 154.44 ;
    END
  END rx_d[433]
  PIN rx_d[434]
    DIRECTION OUTPUT ;
    USE SIGNAL ;
    PORT
      LAYER M4 ;
        RECT  86.316 154.752 86.4 154.776 ;
    END
  END rx_d[434]
  PIN rx_d[435]
    DIRECTION OUTPUT ;
    USE SIGNAL ;
    PORT
      LAYER M4 ;
        RECT  86.316 155.04 86.4 155.064 ;
    END
  END rx_d[435]
  PIN rx_d[436]
    DIRECTION OUTPUT ;
    USE SIGNAL ;
    PORT
      LAYER M4 ;
        RECT  86.316 155.376 86.4 155.4 ;
    END
  END rx_d[436]
  PIN rx_d[437]
    DIRECTION OUTPUT ;
    USE SIGNAL ;
    PORT
      LAYER M4 ;
        RECT  86.316 155.664 86.4 155.688 ;
    END
  END rx_d[437]
  PIN rx_d[438]
    DIRECTION OUTPUT ;
    USE SIGNAL ;
    PORT
      LAYER M4 ;
        RECT  86.316 156 86.4 156.024 ;
    END
  END rx_d[438]
  PIN rx_d[439]
    DIRECTION OUTPUT ;
    USE SIGNAL ;
    PORT
      LAYER M4 ;
        RECT  86.316 156.336 86.4 156.36 ;
    END
  END rx_d[439]
  PIN rx_d[43]
    DIRECTION OUTPUT ;
    USE SIGNAL ;
    PORT
      LAYER M4 ;
        RECT  86.316 31.008 86.4 31.032 ;
    END
  END rx_d[43]
  PIN rx_d[440]
    DIRECTION OUTPUT ;
    USE SIGNAL ;
    PORT
      LAYER M4 ;
        RECT  86.316 156.624 86.4 156.648 ;
    END
  END rx_d[440]
  PIN rx_d[441]
    DIRECTION OUTPUT ;
    USE SIGNAL ;
    PORT
      LAYER M4 ;
        RECT  86.316 156.96 86.4 156.984 ;
    END
  END rx_d[441]
  PIN rx_d[442]
    DIRECTION OUTPUT ;
    USE SIGNAL ;
    PORT
      LAYER M4 ;
        RECT  86.316 157.248 86.4 157.272 ;
    END
  END rx_d[442]
  PIN rx_d[443]
    DIRECTION OUTPUT ;
    USE SIGNAL ;
    PORT
      LAYER M4 ;
        RECT  86.316 157.584 86.4 157.608 ;
    END
  END rx_d[443]
  PIN rx_d[444]
    DIRECTION OUTPUT ;
    USE SIGNAL ;
    PORT
      LAYER M4 ;
        RECT  86.316 157.92 86.4 157.944 ;
    END
  END rx_d[444]
  PIN rx_d[445]
    DIRECTION OUTPUT ;
    USE SIGNAL ;
    PORT
      LAYER M4 ;
        RECT  86.316 158.208 86.4 158.232 ;
    END
  END rx_d[445]
  PIN rx_d[446]
    DIRECTION OUTPUT ;
    USE SIGNAL ;
    PORT
      LAYER M4 ;
        RECT  86.316 158.544 86.4 158.568 ;
    END
  END rx_d[446]
  PIN rx_d[447]
    DIRECTION OUTPUT ;
    USE SIGNAL ;
    PORT
      LAYER M4 ;
        RECT  86.316 158.832 86.4 158.856 ;
    END
  END rx_d[447]
  PIN rx_d[448]
    DIRECTION OUTPUT ;
    USE SIGNAL ;
    PORT
      LAYER M4 ;
        RECT  86.316 159.168 86.4 159.192 ;
    END
  END rx_d[448]
  PIN rx_d[449]
    DIRECTION OUTPUT ;
    USE SIGNAL ;
    PORT
      LAYER M4 ;
        RECT  86.316 159.504 86.4 159.528 ;
    END
  END rx_d[449]
  PIN rx_d[44]
    DIRECTION OUTPUT ;
    USE SIGNAL ;
    PORT
      LAYER M4 ;
        RECT  86.316 31.344 86.4 31.368 ;
    END
  END rx_d[44]
  PIN rx_d[450]
    DIRECTION OUTPUT ;
    USE SIGNAL ;
    PORT
      LAYER M4 ;
        RECT  86.316 159.792 86.4 159.816 ;
    END
  END rx_d[450]
  PIN rx_d[451]
    DIRECTION OUTPUT ;
    USE SIGNAL ;
    PORT
      LAYER M4 ;
        RECT  86.316 160.128 86.4 160.152 ;
    END
  END rx_d[451]
  PIN rx_d[452]
    DIRECTION OUTPUT ;
    USE SIGNAL ;
    PORT
      LAYER M4 ;
        RECT  86.316 160.416 86.4 160.44 ;
    END
  END rx_d[452]
  PIN rx_d[453]
    DIRECTION OUTPUT ;
    USE SIGNAL ;
    PORT
      LAYER M4 ;
        RECT  86.316 160.752 86.4 160.776 ;
    END
  END rx_d[453]
  PIN rx_d[454]
    DIRECTION OUTPUT ;
    USE SIGNAL ;
    PORT
      LAYER M4 ;
        RECT  86.316 161.088 86.4 161.112 ;
    END
  END rx_d[454]
  PIN rx_d[455]
    DIRECTION OUTPUT ;
    USE SIGNAL ;
    PORT
      LAYER M4 ;
        RECT  86.316 161.376 86.4 161.4 ;
    END
  END rx_d[455]
  PIN rx_d[456]
    DIRECTION OUTPUT ;
    USE SIGNAL ;
    PORT
      LAYER M4 ;
        RECT  86.316 161.712 86.4 161.736 ;
    END
  END rx_d[456]
  PIN rx_d[457]
    DIRECTION OUTPUT ;
    USE SIGNAL ;
    PORT
      LAYER M4 ;
        RECT  86.316 162 86.4 162.024 ;
    END
  END rx_d[457]
  PIN rx_d[458]
    DIRECTION OUTPUT ;
    USE SIGNAL ;
    PORT
      LAYER M4 ;
        RECT  86.316 162.336 86.4 162.36 ;
    END
  END rx_d[458]
  PIN rx_d[459]
    DIRECTION OUTPUT ;
    USE SIGNAL ;
    PORT
      LAYER M4 ;
        RECT  86.316 162.624 86.4 162.648 ;
    END
  END rx_d[459]
  PIN rx_d[45]
    DIRECTION OUTPUT ;
    USE SIGNAL ;
    PORT
      LAYER M4 ;
        RECT  86.316 31.68 86.4 31.704 ;
    END
  END rx_d[45]
  PIN rx_d[460]
    DIRECTION OUTPUT ;
    USE SIGNAL ;
    PORT
      LAYER M4 ;
        RECT  86.316 162.96 86.4 162.984 ;
    END
  END rx_d[460]
  PIN rx_d[461]
    DIRECTION OUTPUT ;
    USE SIGNAL ;
    PORT
      LAYER M4 ;
        RECT  86.316 163.296 86.4 163.32 ;
    END
  END rx_d[461]
  PIN rx_d[462]
    DIRECTION OUTPUT ;
    USE SIGNAL ;
    PORT
      LAYER M4 ;
        RECT  86.316 163.584 86.4 163.608 ;
    END
  END rx_d[462]
  PIN rx_d[463]
    DIRECTION OUTPUT ;
    USE SIGNAL ;
    PORT
      LAYER M4 ;
        RECT  86.316 163.92 86.4 163.944 ;
    END
  END rx_d[463]
  PIN rx_d[464]
    DIRECTION OUTPUT ;
    USE SIGNAL ;
    PORT
      LAYER M4 ;
        RECT  86.316 164.208 86.4 164.232 ;
    END
  END rx_d[464]
  PIN rx_d[465]
    DIRECTION OUTPUT ;
    USE SIGNAL ;
    PORT
      LAYER M4 ;
        RECT  86.316 164.544 86.4 164.568 ;
    END
  END rx_d[465]
  PIN rx_d[466]
    DIRECTION OUTPUT ;
    USE SIGNAL ;
    PORT
      LAYER M4 ;
        RECT  86.316 164.88 86.4 164.904 ;
    END
  END rx_d[466]
  PIN rx_d[467]
    DIRECTION OUTPUT ;
    USE SIGNAL ;
    PORT
      LAYER M4 ;
        RECT  86.316 165.168 86.4 165.192 ;
    END
  END rx_d[467]
  PIN rx_d[468]
    DIRECTION OUTPUT ;
    USE SIGNAL ;
    PORT
      LAYER M4 ;
        RECT  86.316 165.504 86.4 165.528 ;
    END
  END rx_d[468]
  PIN rx_d[469]
    DIRECTION OUTPUT ;
    USE SIGNAL ;
    PORT
      LAYER M4 ;
        RECT  86.316 165.792 86.4 165.816 ;
    END
  END rx_d[469]
  PIN rx_d[46]
    DIRECTION OUTPUT ;
    USE SIGNAL ;
    PORT
      LAYER M4 ;
        RECT  86.316 31.968 86.4 31.992 ;
    END
  END rx_d[46]
  PIN rx_d[470]
    DIRECTION OUTPUT ;
    USE SIGNAL ;
    PORT
      LAYER M4 ;
        RECT  86.316 166.128 86.4 166.152 ;
    END
  END rx_d[470]
  PIN rx_d[471]
    DIRECTION OUTPUT ;
    USE SIGNAL ;
    PORT
      LAYER M4 ;
        RECT  86.316 166.464 86.4 166.488 ;
    END
  END rx_d[471]
  PIN rx_d[472]
    DIRECTION OUTPUT ;
    USE SIGNAL ;
    PORT
      LAYER M4 ;
        RECT  86.316 166.752 86.4 166.776 ;
    END
  END rx_d[472]
  PIN rx_d[473]
    DIRECTION OUTPUT ;
    USE SIGNAL ;
    PORT
      LAYER M4 ;
        RECT  86.316 167.088 86.4 167.112 ;
    END
  END rx_d[473]
  PIN rx_d[474]
    DIRECTION OUTPUT ;
    USE SIGNAL ;
    PORT
      LAYER M4 ;
        RECT  86.316 167.376 86.4 167.4 ;
    END
  END rx_d[474]
  PIN rx_d[475]
    DIRECTION OUTPUT ;
    USE SIGNAL ;
    PORT
      LAYER M4 ;
        RECT  86.316 167.712 86.4 167.736 ;
    END
  END rx_d[475]
  PIN rx_d[476]
    DIRECTION OUTPUT ;
    USE SIGNAL ;
    PORT
      LAYER M4 ;
        RECT  86.316 168.048 86.4 168.072 ;
    END
  END rx_d[476]
  PIN rx_d[477]
    DIRECTION OUTPUT ;
    USE SIGNAL ;
    PORT
      LAYER M4 ;
        RECT  86.316 168.336 86.4 168.36 ;
    END
  END rx_d[477]
  PIN rx_d[478]
    DIRECTION OUTPUT ;
    USE SIGNAL ;
    PORT
      LAYER M4 ;
        RECT  86.316 168.672 86.4 168.696 ;
    END
  END rx_d[478]
  PIN rx_d[479]
    DIRECTION OUTPUT ;
    USE SIGNAL ;
    PORT
      LAYER M4 ;
        RECT  86.316 168.96 86.4 168.984 ;
    END
  END rx_d[479]
  PIN rx_d[47]
    DIRECTION OUTPUT ;
    USE SIGNAL ;
    PORT
      LAYER M4 ;
        RECT  86.316 32.304 86.4 32.328 ;
    END
  END rx_d[47]
  PIN rx_d[480]
    DIRECTION OUTPUT ;
    USE SIGNAL ;
    PORT
      LAYER M4 ;
        RECT  86.316 169.296 86.4 169.32 ;
    END
  END rx_d[480]
  PIN rx_d[481]
    DIRECTION OUTPUT ;
    USE SIGNAL ;
    PORT
      LAYER M4 ;
        RECT  86.316 169.584 86.4 169.608 ;
    END
  END rx_d[481]
  PIN rx_d[482]
    DIRECTION OUTPUT ;
    USE SIGNAL ;
    PORT
      LAYER M4 ;
        RECT  86.316 169.92 86.4 169.944 ;
    END
  END rx_d[482]
  PIN rx_d[483]
    DIRECTION OUTPUT ;
    USE SIGNAL ;
    PORT
      LAYER M4 ;
        RECT  86.316 170.256 86.4 170.28 ;
    END
  END rx_d[483]
  PIN rx_d[484]
    DIRECTION OUTPUT ;
    USE SIGNAL ;
    PORT
      LAYER M4 ;
        RECT  86.316 170.544 86.4 170.568 ;
    END
  END rx_d[484]
  PIN rx_d[485]
    DIRECTION OUTPUT ;
    USE SIGNAL ;
    PORT
      LAYER M4 ;
        RECT  86.316 170.88 86.4 170.904 ;
    END
  END rx_d[485]
  PIN rx_d[486]
    DIRECTION OUTPUT ;
    USE SIGNAL ;
    PORT
      LAYER M4 ;
        RECT  86.316 171.168 86.4 171.192 ;
    END
  END rx_d[486]
  PIN rx_d[487]
    DIRECTION OUTPUT ;
    USE SIGNAL ;
    PORT
      LAYER M4 ;
        RECT  86.316 171.504 86.4 171.528 ;
    END
  END rx_d[487]
  PIN rx_d[488]
    DIRECTION OUTPUT ;
    USE SIGNAL ;
    PORT
      LAYER M4 ;
        RECT  86.316 171.84 86.4 171.864 ;
    END
  END rx_d[488]
  PIN rx_d[489]
    DIRECTION OUTPUT ;
    USE SIGNAL ;
    PORT
      LAYER M4 ;
        RECT  86.316 172.128 86.4 172.152 ;
    END
  END rx_d[489]
  PIN rx_d[48]
    DIRECTION OUTPUT ;
    USE SIGNAL ;
    PORT
      LAYER M4 ;
        RECT  86.316 32.592 86.4 32.616 ;
    END
  END rx_d[48]
  PIN rx_d[490]
    DIRECTION OUTPUT ;
    USE SIGNAL ;
    PORT
      LAYER M4 ;
        RECT  86.316 172.464 86.4 172.488 ;
    END
  END rx_d[490]
  PIN rx_d[491]
    DIRECTION OUTPUT ;
    USE SIGNAL ;
    PORT
      LAYER M4 ;
        RECT  86.316 172.752 86.4 172.776 ;
    END
  END rx_d[491]
  PIN rx_d[492]
    DIRECTION OUTPUT ;
    USE SIGNAL ;
    PORT
      LAYER M4 ;
        RECT  86.316 173.088 86.4 173.112 ;
    END
  END rx_d[492]
  PIN rx_d[493]
    DIRECTION OUTPUT ;
    USE SIGNAL ;
    PORT
      LAYER M4 ;
        RECT  86.316 173.424 86.4 173.448 ;
    END
  END rx_d[493]
  PIN rx_d[494]
    DIRECTION OUTPUT ;
    USE SIGNAL ;
    PORT
      LAYER M4 ;
        RECT  86.316 173.712 86.4 173.736 ;
    END
  END rx_d[494]
  PIN rx_d[495]
    DIRECTION OUTPUT ;
    USE SIGNAL ;
    PORT
      LAYER M4 ;
        RECT  86.316 174.048 86.4 174.072 ;
    END
  END rx_d[495]
  PIN rx_d[496]
    DIRECTION OUTPUT ;
    USE SIGNAL ;
    PORT
      LAYER M4 ;
        RECT  86.316 174.336 86.4 174.36 ;
    END
  END rx_d[496]
  PIN rx_d[497]
    DIRECTION OUTPUT ;
    USE SIGNAL ;
    PORT
      LAYER M4 ;
        RECT  86.316 174.672 86.4 174.696 ;
    END
  END rx_d[497]
  PIN rx_d[498]
    DIRECTION OUTPUT ;
    USE SIGNAL ;
    PORT
      LAYER M4 ;
        RECT  86.316 175.008 86.4 175.032 ;
    END
  END rx_d[498]
  PIN rx_d[499]
    DIRECTION OUTPUT ;
    USE SIGNAL ;
    PORT
      LAYER M4 ;
        RECT  86.316 175.296 86.4 175.32 ;
    END
  END rx_d[499]
  PIN rx_d[49]
    DIRECTION OUTPUT ;
    USE SIGNAL ;
    PORT
      LAYER M4 ;
        RECT  86.316 32.928 86.4 32.952 ;
    END
  END rx_d[49]
  PIN rx_d[4]
    DIRECTION OUTPUT ;
    USE SIGNAL ;
    PORT
      LAYER M4 ;
        RECT  86.316 18.672 86.4 18.696 ;
    END
  END rx_d[4]
  PIN rx_d[500]
    DIRECTION OUTPUT ;
    USE SIGNAL ;
    PORT
      LAYER M4 ;
        RECT  86.316 175.632 86.4 175.656 ;
    END
  END rx_d[500]
  PIN rx_d[501]
    DIRECTION OUTPUT ;
    USE SIGNAL ;
    PORT
      LAYER M4 ;
        RECT  86.316 175.92 86.4 175.944 ;
    END
  END rx_d[501]
  PIN rx_d[502]
    DIRECTION OUTPUT ;
    USE SIGNAL ;
    PORT
      LAYER M4 ;
        RECT  86.316 176.256 86.4 176.28 ;
    END
  END rx_d[502]
  PIN rx_d[503]
    DIRECTION OUTPUT ;
    USE SIGNAL ;
    PORT
      LAYER M4 ;
        RECT  86.316 176.544 86.4 176.568 ;
    END
  END rx_d[503]
  PIN rx_d[504]
    DIRECTION OUTPUT ;
    USE SIGNAL ;
    PORT
      LAYER M4 ;
        RECT  86.316 176.88 86.4 176.904 ;
    END
  END rx_d[504]
  PIN rx_d[505]
    DIRECTION OUTPUT ;
    USE SIGNAL ;
    PORT
      LAYER M4 ;
        RECT  86.316 177.216 86.4 177.24 ;
    END
  END rx_d[505]
  PIN rx_d[506]
    DIRECTION OUTPUT ;
    USE SIGNAL ;
    PORT
      LAYER M4 ;
        RECT  86.316 177.504 86.4 177.528 ;
    END
  END rx_d[506]
  PIN rx_d[507]
    DIRECTION OUTPUT ;
    USE SIGNAL ;
    PORT
      LAYER M4 ;
        RECT  86.316 177.84 86.4 177.864 ;
    END
  END rx_d[507]
  PIN rx_d[508]
    DIRECTION OUTPUT ;
    USE SIGNAL ;
    PORT
      LAYER M4 ;
        RECT  86.316 178.128 86.4 178.152 ;
    END
  END rx_d[508]
  PIN rx_d[509]
    DIRECTION OUTPUT ;
    USE SIGNAL ;
    PORT
      LAYER M4 ;
        RECT  86.316 178.464 86.4 178.488 ;
    END
  END rx_d[509]
  PIN rx_d[50]
    DIRECTION OUTPUT ;
    USE SIGNAL ;
    PORT
      LAYER M4 ;
        RECT  86.316 33.264 86.4 33.288 ;
    END
  END rx_d[50]
  PIN rx_d[510]
    DIRECTION OUTPUT ;
    USE SIGNAL ;
    PORT
      LAYER M4 ;
        RECT  86.316 178.8 86.4 178.824 ;
    END
  END rx_d[510]
  PIN rx_d[511]
    DIRECTION OUTPUT ;
    USE SIGNAL ;
    PORT
      LAYER M4 ;
        RECT  86.316 179.088 86.4 179.112 ;
    END
  END rx_d[511]
  PIN rx_d[512]
    DIRECTION OUTPUT ;
    USE SIGNAL ;
    PORT
      LAYER M4 ;
        RECT  86.316 179.424 86.4 179.448 ;
    END
  END rx_d[512]
  PIN rx_d[513]
    DIRECTION OUTPUT ;
    USE SIGNAL ;
    PORT
      LAYER M4 ;
        RECT  86.316 179.712 86.4 179.736 ;
    END
  END rx_d[513]
  PIN rx_d[514]
    DIRECTION OUTPUT ;
    USE SIGNAL ;
    PORT
      LAYER M4 ;
        RECT  86.316 180.048 86.4 180.072 ;
    END
  END rx_d[514]
  PIN rx_d[515]
    DIRECTION OUTPUT ;
    USE SIGNAL ;
    PORT
      LAYER M4 ;
        RECT  86.316 180.384 86.4 180.408 ;
    END
  END rx_d[515]
  PIN rx_d[516]
    DIRECTION OUTPUT ;
    USE SIGNAL ;
    PORT
      LAYER M4 ;
        RECT  86.316 180.672 86.4 180.696 ;
    END
  END rx_d[516]
  PIN rx_d[517]
    DIRECTION OUTPUT ;
    USE SIGNAL ;
    PORT
      LAYER M4 ;
        RECT  86.316 181.008 86.4 181.032 ;
    END
  END rx_d[517]
  PIN rx_d[518]
    DIRECTION OUTPUT ;
    USE SIGNAL ;
    PORT
      LAYER M4 ;
        RECT  86.316 181.296 86.4 181.32 ;
    END
  END rx_d[518]
  PIN rx_d[519]
    DIRECTION OUTPUT ;
    USE SIGNAL ;
    PORT
      LAYER M4 ;
        RECT  86.316 181.632 86.4 181.656 ;
    END
  END rx_d[519]
  PIN rx_d[51]
    DIRECTION OUTPUT ;
    USE SIGNAL ;
    PORT
      LAYER M4 ;
        RECT  86.316 33.552 86.4 33.576 ;
    END
  END rx_d[51]
  PIN rx_d[520]
    DIRECTION OUTPUT ;
    USE SIGNAL ;
    PORT
      LAYER M4 ;
        RECT  86.316 181.968 86.4 181.992 ;
    END
  END rx_d[520]
  PIN rx_d[521]
    DIRECTION OUTPUT ;
    USE SIGNAL ;
    PORT
      LAYER M4 ;
        RECT  86.316 182.256 86.4 182.28 ;
    END
  END rx_d[521]
  PIN rx_d[522]
    DIRECTION OUTPUT ;
    USE SIGNAL ;
    PORT
      LAYER M4 ;
        RECT  86.316 182.592 86.4 182.616 ;
    END
  END rx_d[522]
  PIN rx_d[523]
    DIRECTION OUTPUT ;
    USE SIGNAL ;
    PORT
      LAYER M4 ;
        RECT  86.316 182.88 86.4 182.904 ;
    END
  END rx_d[523]
  PIN rx_d[524]
    DIRECTION OUTPUT ;
    USE SIGNAL ;
    PORT
      LAYER M4 ;
        RECT  86.316 183.216 86.4 183.24 ;
    END
  END rx_d[524]
  PIN rx_d[525]
    DIRECTION OUTPUT ;
    USE SIGNAL ;
    PORT
      LAYER M4 ;
        RECT  86.316 183.504 86.4 183.528 ;
    END
  END rx_d[525]
  PIN rx_d[526]
    DIRECTION OUTPUT ;
    USE SIGNAL ;
    PORT
      LAYER M4 ;
        RECT  86.316 183.84 86.4 183.864 ;
    END
  END rx_d[526]
  PIN rx_d[527]
    DIRECTION OUTPUT ;
    USE SIGNAL ;
    PORT
      LAYER M4 ;
        RECT  86.316 184.176 86.4 184.2 ;
    END
  END rx_d[527]
  PIN rx_d[528]
    DIRECTION OUTPUT ;
    USE SIGNAL ;
    PORT
      LAYER M4 ;
        RECT  86.316 184.464 86.4 184.488 ;
    END
  END rx_d[528]
  PIN rx_d[529]
    DIRECTION OUTPUT ;
    USE SIGNAL ;
    PORT
      LAYER M4 ;
        RECT  86.316 184.8 86.4 184.824 ;
    END
  END rx_d[529]
  PIN rx_d[52]
    DIRECTION OUTPUT ;
    USE SIGNAL ;
    PORT
      LAYER M4 ;
        RECT  86.316 33.888 86.4 33.912 ;
    END
  END rx_d[52]
  PIN rx_d[530]
    DIRECTION OUTPUT ;
    USE SIGNAL ;
    PORT
      LAYER M4 ;
        RECT  86.316 185.088 86.4 185.112 ;
    END
  END rx_d[530]
  PIN rx_d[531]
    DIRECTION OUTPUT ;
    USE SIGNAL ;
    PORT
      LAYER M4 ;
        RECT  86.316 185.424 86.4 185.448 ;
    END
  END rx_d[531]
  PIN rx_d[532]
    DIRECTION OUTPUT ;
    USE SIGNAL ;
    PORT
      LAYER M4 ;
        RECT  86.316 185.76 86.4 185.784 ;
    END
  END rx_d[532]
  PIN rx_d[533]
    DIRECTION OUTPUT ;
    USE SIGNAL ;
    PORT
      LAYER M4 ;
        RECT  86.316 186.048 86.4 186.072 ;
    END
  END rx_d[533]
  PIN rx_d[534]
    DIRECTION OUTPUT ;
    USE SIGNAL ;
    PORT
      LAYER M4 ;
        RECT  86.316 186.384 86.4 186.408 ;
    END
  END rx_d[534]
  PIN rx_d[535]
    DIRECTION OUTPUT ;
    USE SIGNAL ;
    PORT
      LAYER M4 ;
        RECT  86.316 186.672 86.4 186.696 ;
    END
  END rx_d[535]
  PIN rx_d[536]
    DIRECTION OUTPUT ;
    USE SIGNAL ;
    PORT
      LAYER M4 ;
        RECT  86.316 187.008 86.4 187.032 ;
    END
  END rx_d[536]
  PIN rx_d[537]
    DIRECTION OUTPUT ;
    USE SIGNAL ;
    PORT
      LAYER M4 ;
        RECT  86.316 187.344 86.4 187.368 ;
    END
  END rx_d[537]
  PIN rx_d[538]
    DIRECTION OUTPUT ;
    USE SIGNAL ;
    PORT
      LAYER M4 ;
        RECT  86.316 187.632 86.4 187.656 ;
    END
  END rx_d[538]
  PIN rx_d[539]
    DIRECTION OUTPUT ;
    USE SIGNAL ;
    PORT
      LAYER M4 ;
        RECT  86.316 187.968 86.4 187.992 ;
    END
  END rx_d[539]
  PIN rx_d[53]
    DIRECTION OUTPUT ;
    USE SIGNAL ;
    PORT
      LAYER M4 ;
        RECT  86.316 34.176 86.4 34.2 ;
    END
  END rx_d[53]
  PIN rx_d[540]
    DIRECTION OUTPUT ;
    USE SIGNAL ;
    PORT
      LAYER M4 ;
        RECT  86.316 188.256 86.4 188.28 ;
    END
  END rx_d[540]
  PIN rx_d[541]
    DIRECTION OUTPUT ;
    USE SIGNAL ;
    PORT
      LAYER M4 ;
        RECT  86.316 188.592 86.4 188.616 ;
    END
  END rx_d[541]
  PIN rx_d[542]
    DIRECTION OUTPUT ;
    USE SIGNAL ;
    PORT
      LAYER M4 ;
        RECT  86.316 188.928 86.4 188.952 ;
    END
  END rx_d[542]
  PIN rx_d[543]
    DIRECTION OUTPUT ;
    USE SIGNAL ;
    PORT
      LAYER M4 ;
        RECT  86.316 189.216 86.4 189.24 ;
    END
  END rx_d[543]
  PIN rx_d[544]
    DIRECTION OUTPUT ;
    USE SIGNAL ;
    PORT
      LAYER M4 ;
        RECT  86.316 189.552 86.4 189.576 ;
    END
  END rx_d[544]
  PIN rx_d[545]
    DIRECTION OUTPUT ;
    USE SIGNAL ;
    PORT
      LAYER M4 ;
        RECT  86.316 189.84 86.4 189.864 ;
    END
  END rx_d[545]
  PIN rx_d[546]
    DIRECTION OUTPUT ;
    USE SIGNAL ;
    PORT
      LAYER M4 ;
        RECT  86.316 190.176 86.4 190.2 ;
    END
  END rx_d[546]
  PIN rx_d[547]
    DIRECTION OUTPUT ;
    USE SIGNAL ;
    PORT
      LAYER M4 ;
        RECT  86.316 190.512 86.4 190.536 ;
    END
  END rx_d[547]
  PIN rx_d[548]
    DIRECTION OUTPUT ;
    USE SIGNAL ;
    PORT
      LAYER M4 ;
        RECT  86.316 190.8 86.4 190.824 ;
    END
  END rx_d[548]
  PIN rx_d[549]
    DIRECTION OUTPUT ;
    USE SIGNAL ;
    PORT
      LAYER M4 ;
        RECT  86.316 191.136 86.4 191.16 ;
    END
  END rx_d[549]
  PIN rx_d[54]
    DIRECTION OUTPUT ;
    USE SIGNAL ;
    PORT
      LAYER M4 ;
        RECT  86.316 34.512 86.4 34.536 ;
    END
  END rx_d[54]
  PIN rx_d[550]
    DIRECTION OUTPUT ;
    USE SIGNAL ;
    PORT
      LAYER M4 ;
        RECT  86.316 191.424 86.4 191.448 ;
    END
  END rx_d[550]
  PIN rx_d[551]
    DIRECTION OUTPUT ;
    USE SIGNAL ;
    PORT
      LAYER M4 ;
        RECT  86.316 191.76 86.4 191.784 ;
    END
  END rx_d[551]
  PIN rx_d[552]
    DIRECTION OUTPUT ;
    USE SIGNAL ;
    PORT
      LAYER M4 ;
        RECT  86.316 192.048 86.4 192.072 ;
    END
  END rx_d[552]
  PIN rx_d[55]
    DIRECTION OUTPUT ;
    USE SIGNAL ;
    PORT
      LAYER M4 ;
        RECT  86.316 34.848 86.4 34.872 ;
    END
  END rx_d[55]
  PIN rx_d[56]
    DIRECTION OUTPUT ;
    USE SIGNAL ;
    PORT
      LAYER M4 ;
        RECT  86.316 35.136 86.4 35.16 ;
    END
  END rx_d[56]
  PIN rx_d[57]
    DIRECTION OUTPUT ;
    USE SIGNAL ;
    PORT
      LAYER M4 ;
        RECT  86.316 35.472 86.4 35.496 ;
    END
  END rx_d[57]
  PIN rx_d[58]
    DIRECTION OUTPUT ;
    USE SIGNAL ;
    PORT
      LAYER M4 ;
        RECT  86.316 35.76 86.4 35.784 ;
    END
  END rx_d[58]
  PIN rx_d[59]
    DIRECTION OUTPUT ;
    USE SIGNAL ;
    PORT
      LAYER M4 ;
        RECT  86.316 36.096 86.4 36.12 ;
    END
  END rx_d[59]
  PIN rx_d[5]
    DIRECTION OUTPUT ;
    USE SIGNAL ;
    PORT
      LAYER M4 ;
        RECT  86.316 19.008 86.4 19.032 ;
    END
  END rx_d[5]
  PIN rx_d[60]
    DIRECTION OUTPUT ;
    USE SIGNAL ;
    PORT
      LAYER M4 ;
        RECT  86.316 36.432 86.4 36.456 ;
    END
  END rx_d[60]
  PIN rx_d[61]
    DIRECTION OUTPUT ;
    USE SIGNAL ;
    PORT
      LAYER M4 ;
        RECT  86.316 36.72 86.4 36.744 ;
    END
  END rx_d[61]
  PIN rx_d[62]
    DIRECTION OUTPUT ;
    USE SIGNAL ;
    PORT
      LAYER M4 ;
        RECT  86.316 37.056 86.4 37.08 ;
    END
  END rx_d[62]
  PIN rx_d[63]
    DIRECTION OUTPUT ;
    USE SIGNAL ;
    PORT
      LAYER M4 ;
        RECT  86.316 37.344 86.4 37.368 ;
    END
  END rx_d[63]
  PIN rx_d[64]
    DIRECTION OUTPUT ;
    USE SIGNAL ;
    PORT
      LAYER M4 ;
        RECT  86.316 37.68 86.4 37.704 ;
    END
  END rx_d[64]
  PIN rx_d[65]
    DIRECTION OUTPUT ;
    USE SIGNAL ;
    PORT
      LAYER M4 ;
        RECT  86.316 37.968 86.4 37.992 ;
    END
  END rx_d[65]
  PIN rx_d[66]
    DIRECTION OUTPUT ;
    USE SIGNAL ;
    PORT
      LAYER M4 ;
        RECT  86.316 38.304 86.4 38.328 ;
    END
  END rx_d[66]
  PIN rx_d[67]
    DIRECTION OUTPUT ;
    USE SIGNAL ;
    PORT
      LAYER M4 ;
        RECT  86.316 38.64 86.4 38.664 ;
    END
  END rx_d[67]
  PIN rx_d[68]
    DIRECTION OUTPUT ;
    USE SIGNAL ;
    PORT
      LAYER M4 ;
        RECT  86.316 38.928 86.4 38.952 ;
    END
  END rx_d[68]
  PIN rx_d[69]
    DIRECTION OUTPUT ;
    USE SIGNAL ;
    PORT
      LAYER M4 ;
        RECT  86.316 39.264 86.4 39.288 ;
    END
  END rx_d[69]
  PIN rx_d[6]
    DIRECTION OUTPUT ;
    USE SIGNAL ;
    PORT
      LAYER M4 ;
        RECT  86.316 19.344 86.4 19.368 ;
    END
  END rx_d[6]
  PIN rx_d[70]
    DIRECTION OUTPUT ;
    USE SIGNAL ;
    PORT
      LAYER M4 ;
        RECT  86.316 39.552 86.4 39.576 ;
    END
  END rx_d[70]
  PIN rx_d[71]
    DIRECTION OUTPUT ;
    USE SIGNAL ;
    PORT
      LAYER M4 ;
        RECT  86.316 39.888 86.4 39.912 ;
    END
  END rx_d[71]
  PIN rx_d[72]
    DIRECTION OUTPUT ;
    USE SIGNAL ;
    PORT
      LAYER M4 ;
        RECT  86.316 40.224 86.4 40.248 ;
    END
  END rx_d[72]
  PIN rx_d[73]
    DIRECTION OUTPUT ;
    USE SIGNAL ;
    PORT
      LAYER M4 ;
        RECT  86.316 40.512 86.4 40.536 ;
    END
  END rx_d[73]
  PIN rx_d[74]
    DIRECTION OUTPUT ;
    USE SIGNAL ;
    PORT
      LAYER M4 ;
        RECT  86.316 40.848 86.4 40.872 ;
    END
  END rx_d[74]
  PIN rx_d[75]
    DIRECTION OUTPUT ;
    USE SIGNAL ;
    PORT
      LAYER M4 ;
        RECT  86.316 41.136 86.4 41.16 ;
    END
  END rx_d[75]
  PIN rx_d[76]
    DIRECTION OUTPUT ;
    USE SIGNAL ;
    PORT
      LAYER M4 ;
        RECT  86.316 41.472 86.4 41.496 ;
    END
  END rx_d[76]
  PIN rx_d[77]
    DIRECTION OUTPUT ;
    USE SIGNAL ;
    PORT
      LAYER M4 ;
        RECT  86.316 41.808 86.4 41.832 ;
    END
  END rx_d[77]
  PIN rx_d[78]
    DIRECTION OUTPUT ;
    USE SIGNAL ;
    PORT
      LAYER M4 ;
        RECT  86.316 42.096 86.4 42.12 ;
    END
  END rx_d[78]
  PIN rx_d[79]
    DIRECTION OUTPUT ;
    USE SIGNAL ;
    PORT
      LAYER M4 ;
        RECT  86.316 42.432 86.4 42.456 ;
    END
  END rx_d[79]
  PIN rx_d[7]
    DIRECTION OUTPUT ;
    USE SIGNAL ;
    PORT
      LAYER M4 ;
        RECT  86.316 19.632 86.4 19.656 ;
    END
  END rx_d[7]
  PIN rx_d[80]
    DIRECTION OUTPUT ;
    USE SIGNAL ;
    PORT
      LAYER M4 ;
        RECT  86.316 42.72 86.4 42.744 ;
    END
  END rx_d[80]
  PIN rx_d[81]
    DIRECTION OUTPUT ;
    USE SIGNAL ;
    PORT
      LAYER M4 ;
        RECT  86.316 43.056 86.4 43.08 ;
    END
  END rx_d[81]
  PIN rx_d[82]
    DIRECTION OUTPUT ;
    USE SIGNAL ;
    PORT
      LAYER M4 ;
        RECT  86.316 43.392 86.4 43.416 ;
    END
  END rx_d[82]
  PIN rx_d[83]
    DIRECTION OUTPUT ;
    USE SIGNAL ;
    PORT
      LAYER M4 ;
        RECT  86.316 43.68 86.4 43.704 ;
    END
  END rx_d[83]
  PIN rx_d[84]
    DIRECTION OUTPUT ;
    USE SIGNAL ;
    PORT
      LAYER M4 ;
        RECT  86.316 44.016 86.4 44.04 ;
    END
  END rx_d[84]
  PIN rx_d[85]
    DIRECTION OUTPUT ;
    USE SIGNAL ;
    PORT
      LAYER M4 ;
        RECT  86.316 44.304 86.4 44.328 ;
    END
  END rx_d[85]
  PIN rx_d[86]
    DIRECTION OUTPUT ;
    USE SIGNAL ;
    PORT
      LAYER M4 ;
        RECT  86.316 44.64 86.4 44.664 ;
    END
  END rx_d[86]
  PIN rx_d[87]
    DIRECTION OUTPUT ;
    USE SIGNAL ;
    PORT
      LAYER M4 ;
        RECT  86.316 44.976 86.4 45 ;
    END
  END rx_d[87]
  PIN rx_d[88]
    DIRECTION OUTPUT ;
    USE SIGNAL ;
    PORT
      LAYER M4 ;
        RECT  86.316 45.264 86.4 45.288 ;
    END
  END rx_d[88]
  PIN rx_d[89]
    DIRECTION OUTPUT ;
    USE SIGNAL ;
    PORT
      LAYER M4 ;
        RECT  86.316 45.6 86.4 45.624 ;
    END
  END rx_d[89]
  PIN rx_d[8]
    DIRECTION OUTPUT ;
    USE SIGNAL ;
    PORT
      LAYER M4 ;
        RECT  86.316 19.968 86.4 19.992 ;
    END
  END rx_d[8]
  PIN rx_d[90]
    DIRECTION OUTPUT ;
    USE SIGNAL ;
    PORT
      LAYER M4 ;
        RECT  86.316 45.888 86.4 45.912 ;
    END
  END rx_d[90]
  PIN rx_d[91]
    DIRECTION OUTPUT ;
    USE SIGNAL ;
    PORT
      LAYER M4 ;
        RECT  86.316 46.224 86.4 46.248 ;
    END
  END rx_d[91]
  PIN rx_d[92]
    DIRECTION OUTPUT ;
    USE SIGNAL ;
    PORT
      LAYER M4 ;
        RECT  86.316 46.512 86.4 46.536 ;
    END
  END rx_d[92]
  PIN rx_d[93]
    DIRECTION OUTPUT ;
    USE SIGNAL ;
    PORT
      LAYER M4 ;
        RECT  86.316 46.848 86.4 46.872 ;
    END
  END rx_d[93]
  PIN rx_d[94]
    DIRECTION OUTPUT ;
    USE SIGNAL ;
    PORT
      LAYER M4 ;
        RECT  86.316 47.184 86.4 47.208 ;
    END
  END rx_d[94]
  PIN rx_d[95]
    DIRECTION OUTPUT ;
    USE SIGNAL ;
    PORT
      LAYER M4 ;
        RECT  86.316 47.472 86.4 47.496 ;
    END
  END rx_d[95]
  PIN rx_d[96]
    DIRECTION OUTPUT ;
    USE SIGNAL ;
    PORT
      LAYER M4 ;
        RECT  86.316 47.808 86.4 47.832 ;
    END
  END rx_d[96]
  PIN rx_d[97]
    DIRECTION OUTPUT ;
    USE SIGNAL ;
    PORT
      LAYER M4 ;
        RECT  86.316 48.096 86.4 48.12 ;
    END
  END rx_d[97]
  PIN rx_d[98]
    DIRECTION OUTPUT ;
    USE SIGNAL ;
    PORT
      LAYER M4 ;
        RECT  86.316 48.432 86.4 48.456 ;
    END
  END rx_d[98]
  PIN rx_d[99]
    DIRECTION OUTPUT ;
    USE SIGNAL ;
    PORT
      LAYER M4 ;
        RECT  86.316 48.768 86.4 48.792 ;
    END
  END rx_d[99]
  PIN rx_d[9]
    DIRECTION OUTPUT ;
    USE SIGNAL ;
    PORT
      LAYER M4 ;
        RECT  86.316 20.256 86.4 20.28 ;
    END
  END rx_d[9]
  PIN rx_v
    DIRECTION OUTPUT ;
    USE SIGNAL ;
    PORT
      LAYER M4 ;
        RECT  86.316 7.008 86.4 7.032 ;
    END
  END rx_v
  PIN tvk[0]
    DIRECTION OUTPUT ;
    USE SIGNAL ;
    PORT
      LAYER M5 ;
        RECT  29.136 0 29.16 0.084 ;
    END
  END tvk[0]
  PIN tvk[1]
    DIRECTION OUTPUT ;
    USE SIGNAL ;
    PORT
      LAYER M5 ;
        RECT  31.296 0 31.32 0.084 ;
    END
  END tvk[1]
  PIN tvk[2]
    DIRECTION OUTPUT ;
    USE SIGNAL ;
    PORT
      LAYER M5 ;
        RECT  33.456 0 33.48 0.084 ;
    END
  END tvk[2]
  PIN tx_v
    DIRECTION INPUT ;
    USE SIGNAL ;
    PORT
      LAYER M4 ;
        RECT  86.316 2.688 86.4 2.712 ;
    END
  END tx_v
  PIN VDD
    DIRECTION INOUT ;
    USE POWER ;
    PORT
      LAYER M5 ;
        RECT  83.592 2.151 83.712 192.249 ;
        RECT  78.192 2.151 78.312 192.249 ;
        RECT  72.792 2.151 72.912 192.249 ;
        RECT  67.392 2.151 67.512 192.249 ;
        RECT  61.992 2.151 62.112 192.249 ;
        RECT  56.592 2.151 56.712 192.249 ;
        RECT  51.192 2.151 51.312 192.249 ;
        RECT  45.792 2.151 45.912 192.249 ;
        RECT  40.392 2.151 40.512 192.249 ;
        RECT  34.992 2.151 35.112 192.249 ;
        RECT  29.592 2.151 29.712 192.249 ;
        RECT  24.192 2.151 24.312 192.249 ;
        RECT  18.792 2.151 18.912 192.249 ;
        RECT  13.392 2.151 13.512 192.249 ;
        RECT  7.992 2.151 8.112 192.249 ;
        RECT  2.592 2.151 2.712 192.249 ;
    END
  END VDD
  PIN VSS
    DIRECTION INOUT ;
    USE GROUND ;
    PORT
      LAYER M5 ;
        RECT  83.4 2.137 83.52 192.263 ;
        RECT  78 2.137 78.12 192.263 ;
        RECT  72.6 2.137 72.72 192.263 ;
        RECT  67.2 2.137 67.32 192.263 ;
        RECT  61.8 2.137 61.92 192.263 ;
        RECT  56.4 2.137 56.52 192.263 ;
        RECT  51 2.137 51.12 192.263 ;
        RECT  45.6 2.137 45.72 192.263 ;
        RECT  40.2 2.137 40.32 192.263 ;
        RECT  34.8 2.137 34.92 192.263 ;
        RECT  29.4 2.137 29.52 192.263 ;
        RECT  24 2.137 24.12 192.263 ;
        RECT  18.6 2.137 18.72 192.263 ;
        RECT  13.2 2.137 13.32 192.263 ;
        RECT  7.8 2.137 7.92 192.263 ;
        RECT  2.4 2.137 2.52 192.263 ;
    END
  END VSS
  OBS
    LAYER RVTN ;
     RECT  2.16 2.16 84.24 2.295 ;
     RECT  2.16 2.565 84.24 2.835 ;
     RECT  2.16 3.105 84.24 3.375 ;
     RECT  2.16 3.645 84.24 3.915 ;
     RECT  2.16 4.185 84.24 4.455 ;
     RECT  2.16 4.725 84.24 4.995 ;
     RECT  2.16 5.265 84.24 5.535 ;
     RECT  2.16 5.805 84.24 6.075 ;
     RECT  2.16 6.345 84.24 6.615 ;
     RECT  2.16 6.885 84.24 7.155 ;
     RECT  2.16 7.425 84.24 7.695 ;
     RECT  2.16 7.965 84.24 8.235 ;
     RECT  2.16 8.505 84.24 8.775 ;
     RECT  2.16 9.045 84.24 9.315 ;
     RECT  2.16 9.585 84.24 9.855 ;
     RECT  2.16 10.125 84.24 10.395 ;
     RECT  2.16 10.665 84.24 10.935 ;
     RECT  2.16 11.205 84.24 11.475 ;
     RECT  2.16 11.745 84.24 12.015 ;
     RECT  2.16 12.285 84.24 12.555 ;
     RECT  2.16 12.825 84.24 13.095 ;
     RECT  2.16 13.365 84.24 13.635 ;
     RECT  2.16 13.905 84.24 14.175 ;
     RECT  2.16 14.445 84.24 14.715 ;
     RECT  2.16 14.985 84.24 15.255 ;
     RECT  2.16 15.525 84.24 15.795 ;
     RECT  2.16 16.065 84.24 16.335 ;
     RECT  2.16 16.605 84.24 16.875 ;
     RECT  2.16 17.145 84.24 17.415 ;
     RECT  2.16 17.685 84.24 17.955 ;
     RECT  2.16 18.225 84.24 18.495 ;
     RECT  2.16 18.765 84.24 19.035 ;
     RECT  2.16 19.305 84.24 19.575 ;
     RECT  2.16 19.845 84.24 20.115 ;
     RECT  2.16 20.385 84.24 20.655 ;
     RECT  2.16 20.925 84.24 21.195 ;
     RECT  2.16 21.465 84.24 21.735 ;
     RECT  2.16 22.005 84.24 22.275 ;
     RECT  2.16 22.545 84.24 22.815 ;
     RECT  2.16 23.085 84.24 23.355 ;
     RECT  2.16 23.625 84.24 23.895 ;
     RECT  2.16 24.165 84.24 24.435 ;
     RECT  2.16 24.705 84.24 24.975 ;
     RECT  2.16 25.245 84.24 25.515 ;
     RECT  2.16 25.785 84.24 26.055 ;
     RECT  2.16 26.325 84.24 26.595 ;
     RECT  2.16 26.865 84.24 27.135 ;
     RECT  2.16 27.405 84.24 27.675 ;
     RECT  2.16 27.945 84.24 28.215 ;
     RECT  2.16 28.485 84.24 28.755 ;
     RECT  2.16 29.025 84.24 29.295 ;
     RECT  2.16 29.565 84.24 29.835 ;
     RECT  2.16 30.105 84.24 30.375 ;
     RECT  2.16 30.645 84.24 30.915 ;
     RECT  2.16 31.185 84.24 31.455 ;
     RECT  2.16 31.725 84.24 31.995 ;
     RECT  2.16 32.265 84.24 32.535 ;
     RECT  2.16 32.805 84.24 33.075 ;
     RECT  2.16 33.345 84.24 33.615 ;
     RECT  2.16 33.885 84.24 34.155 ;
     RECT  2.16 34.425 84.24 34.695 ;
     RECT  2.16 34.965 84.24 35.235 ;
     RECT  2.16 35.505 84.24 35.775 ;
     RECT  2.16 36.045 84.24 36.315 ;
     RECT  2.16 36.585 84.24 36.855 ;
     RECT  2.16 37.125 84.24 37.395 ;
     RECT  2.16 37.665 84.24 37.935 ;
     RECT  2.16 38.205 84.24 38.475 ;
     RECT  2.16 38.745 84.24 39.015 ;
     RECT  2.16 39.285 84.24 39.555 ;
     RECT  2.16 39.825 84.24 40.095 ;
     RECT  2.16 40.365 84.24 40.635 ;
     RECT  2.16 40.905 84.24 41.175 ;
     RECT  2.16 41.445 84.24 41.715 ;
     RECT  2.16 41.985 84.24 42.255 ;
     RECT  2.16 42.525 84.24 42.795 ;
     RECT  2.16 43.065 84.24 43.335 ;
     RECT  2.16 43.605 84.24 43.875 ;
     RECT  2.16 44.145 84.24 44.415 ;
     RECT  2.16 44.685 84.24 44.955 ;
     RECT  2.16 45.225 84.24 45.495 ;
     RECT  2.16 45.765 84.24 46.035 ;
     RECT  2.16 46.305 84.24 46.575 ;
     RECT  2.16 46.845 84.24 47.115 ;
     RECT  2.16 47.385 84.24 47.655 ;
     RECT  2.16 47.925 84.24 48.195 ;
     RECT  2.16 48.465 84.24 48.735 ;
     RECT  2.16 49.005 84.24 49.275 ;
     RECT  2.16 49.545 84.24 49.815 ;
     RECT  2.16 50.085 84.24 50.355 ;
     RECT  2.16 50.625 84.24 50.895 ;
     RECT  2.16 51.165 84.24 51.435 ;
     RECT  2.16 51.705 84.24 51.975 ;
     RECT  2.16 52.245 84.24 52.515 ;
     RECT  2.16 52.785 84.24 53.055 ;
     RECT  2.16 53.325 84.24 53.595 ;
     RECT  2.16 53.865 84.24 54.135 ;
     RECT  2.16 54.405 84.24 54.675 ;
     RECT  2.16 54.945 84.24 55.215 ;
     RECT  2.16 55.485 84.24 55.755 ;
     RECT  2.16 56.025 84.24 56.295 ;
     RECT  2.16 56.565 84.24 56.835 ;
     RECT  2.16 57.105 84.24 57.375 ;
     RECT  2.16 57.645 84.24 57.915 ;
     RECT  2.16 58.185 84.24 58.455 ;
     RECT  2.16 58.725 84.24 58.995 ;
     RECT  2.16 59.265 84.24 59.535 ;
     RECT  2.16 59.805 84.24 60.075 ;
     RECT  2.16 60.345 84.24 60.615 ;
     RECT  2.16 60.885 84.24 61.155 ;
     RECT  2.16 61.425 84.24 61.695 ;
     RECT  2.16 61.965 84.24 62.235 ;
     RECT  2.16 62.505 84.24 62.775 ;
     RECT  2.16 63.045 84.24 63.315 ;
     RECT  2.16 63.585 84.24 63.855 ;
     RECT  2.16 64.125 84.24 64.395 ;
     RECT  2.16 64.665 84.24 64.935 ;
     RECT  2.16 65.205 84.24 65.475 ;
     RECT  2.16 65.745 84.24 66.015 ;
     RECT  2.16 66.285 84.24 66.555 ;
     RECT  2.16 66.825 84.24 67.095 ;
     RECT  2.16 67.365 84.24 67.635 ;
     RECT  2.16 67.905 84.24 68.175 ;
     RECT  2.16 68.445 84.24 68.715 ;
     RECT  2.16 68.985 84.24 69.255 ;
     RECT  2.16 69.525 84.24 69.795 ;
     RECT  2.16 70.065 84.24 70.335 ;
     RECT  2.16 70.605 84.24 70.875 ;
     RECT  2.16 71.145 84.24 71.415 ;
     RECT  2.16 71.685 84.24 71.955 ;
     RECT  2.16 72.225 84.24 72.495 ;
     RECT  2.16 72.765 84.24 73.035 ;
     RECT  2.16 73.305 84.24 73.575 ;
     RECT  2.16 73.845 84.24 74.115 ;
     RECT  2.16 74.385 84.24 74.655 ;
     RECT  2.16 74.925 84.24 75.195 ;
     RECT  2.16 75.465 84.24 75.735 ;
     RECT  2.16 76.005 84.24 76.275 ;
     RECT  2.16 76.545 84.24 76.815 ;
     RECT  2.16 77.085 84.24 77.355 ;
     RECT  2.16 77.625 84.24 77.895 ;
     RECT  2.16 78.165 84.24 78.435 ;
     RECT  2.16 78.705 84.24 78.975 ;
     RECT  2.16 79.245 84.24 79.515 ;
     RECT  2.16 79.785 84.24 80.055 ;
     RECT  2.16 80.325 84.24 80.595 ;
     RECT  2.16 80.865 84.24 81.135 ;
     RECT  2.16 81.405 84.24 81.675 ;
     RECT  2.16 81.945 84.24 82.215 ;
     RECT  2.16 82.485 84.24 82.755 ;
     RECT  2.16 83.025 84.24 83.295 ;
     RECT  2.16 83.565 84.24 83.835 ;
     RECT  2.16 84.105 84.24 84.375 ;
     RECT  2.16 84.645 84.24 84.915 ;
     RECT  2.16 85.185 84.24 85.455 ;
     RECT  2.16 85.725 84.24 85.995 ;
     RECT  2.16 86.265 84.24 86.535 ;
     RECT  2.16 86.805 84.24 87.075 ;
     RECT  2.16 87.345 84.24 87.615 ;
     RECT  2.16 87.885 84.24 88.155 ;
     RECT  2.16 88.425 84.24 88.695 ;
     RECT  2.16 88.965 84.24 89.235 ;
     RECT  2.16 89.505 84.24 89.775 ;
     RECT  2.16 90.045 84.24 90.315 ;
     RECT  2.16 90.585 84.24 90.855 ;
     RECT  2.16 91.125 84.24 91.395 ;
     RECT  2.16 91.665 84.24 91.935 ;
     RECT  2.16 92.205 84.24 92.475 ;
     RECT  2.16 92.745 84.24 93.015 ;
     RECT  2.16 93.285 84.24 93.555 ;
     RECT  2.16 93.825 84.24 94.095 ;
     RECT  2.16 94.365 84.24 94.635 ;
     RECT  2.16 94.905 84.24 95.175 ;
     RECT  2.16 95.445 84.24 95.715 ;
     RECT  2.16 95.985 84.24 96.255 ;
     RECT  2.16 96.525 84.24 96.795 ;
     RECT  2.16 97.065 84.24 97.335 ;
     RECT  2.16 97.605 84.24 97.875 ;
     RECT  2.16 98.145 84.24 98.415 ;
     RECT  2.16 98.685 84.24 98.955 ;
     RECT  2.16 99.225 84.24 99.495 ;
     RECT  2.16 99.765 84.24 100.035 ;
     RECT  2.16 100.305 84.24 100.575 ;
     RECT  2.16 100.845 84.24 101.115 ;
     RECT  2.16 101.385 84.24 101.655 ;
     RECT  2.16 101.925 84.24 102.195 ;
     RECT  2.16 102.465 84.24 102.735 ;
     RECT  2.16 103.005 84.24 103.275 ;
     RECT  2.16 103.545 84.24 103.815 ;
     RECT  2.16 104.085 84.24 104.355 ;
     RECT  2.16 104.625 84.24 104.895 ;
     RECT  2.16 105.165 84.24 105.435 ;
     RECT  2.16 105.705 84.24 105.975 ;
     RECT  2.16 106.245 84.24 106.515 ;
     RECT  2.16 106.785 84.24 107.055 ;
     RECT  2.16 107.325 84.24 107.595 ;
     RECT  2.16 107.865 84.24 108.135 ;
     RECT  2.16 108.405 84.24 108.675 ;
     RECT  2.16 108.945 84.24 109.215 ;
     RECT  2.16 109.485 84.24 109.755 ;
     RECT  2.16 110.025 84.24 110.295 ;
     RECT  2.16 110.565 84.24 110.835 ;
     RECT  2.16 111.105 84.24 111.375 ;
     RECT  2.16 111.645 84.24 111.915 ;
     RECT  2.16 112.185 84.24 112.455 ;
     RECT  2.16 112.725 84.24 112.995 ;
     RECT  2.16 113.265 84.24 113.535 ;
     RECT  2.16 113.805 84.24 114.075 ;
     RECT  2.16 114.345 84.24 114.615 ;
     RECT  2.16 114.885 84.24 115.155 ;
     RECT  2.16 115.425 84.24 115.695 ;
     RECT  2.16 115.965 84.24 116.235 ;
     RECT  2.16 116.505 84.24 116.775 ;
     RECT  2.16 117.045 84.24 117.315 ;
     RECT  2.16 117.585 84.24 117.855 ;
     RECT  2.16 118.125 84.24 118.395 ;
     RECT  2.16 118.665 84.24 118.935 ;
     RECT  2.16 119.205 84.24 119.475 ;
     RECT  2.16 119.745 84.24 120.015 ;
     RECT  2.16 120.285 84.24 120.555 ;
     RECT  2.16 120.825 84.24 121.095 ;
     RECT  2.16 121.365 84.24 121.635 ;
     RECT  2.16 121.905 84.24 122.175 ;
     RECT  2.16 122.445 84.24 122.715 ;
     RECT  2.16 122.985 84.24 123.255 ;
     RECT  2.16 123.525 84.24 123.795 ;
     RECT  2.16 124.065 84.24 124.335 ;
     RECT  2.16 124.605 84.24 124.875 ;
     RECT  2.16 125.145 84.24 125.415 ;
     RECT  2.16 125.685 84.24 125.955 ;
     RECT  2.16 126.225 84.24 126.495 ;
     RECT  2.16 126.765 84.24 127.035 ;
     RECT  2.16 127.305 84.24 127.575 ;
     RECT  2.16 127.845 84.24 128.115 ;
     RECT  2.16 128.385 84.24 128.655 ;
     RECT  2.16 128.925 84.24 129.195 ;
     RECT  2.16 129.465 84.24 129.735 ;
     RECT  2.16 130.005 84.24 130.275 ;
     RECT  2.16 130.545 84.24 130.815 ;
     RECT  2.16 131.085 84.24 131.355 ;
     RECT  2.16 131.625 84.24 131.895 ;
     RECT  2.16 132.165 84.24 132.435 ;
     RECT  2.16 132.705 84.24 132.975 ;
     RECT  2.16 133.245 84.24 133.515 ;
     RECT  2.16 133.785 84.24 134.055 ;
     RECT  2.16 134.325 84.24 134.595 ;
     RECT  2.16 134.865 84.24 135.135 ;
     RECT  2.16 135.405 84.24 135.675 ;
     RECT  2.16 135.945 84.24 136.215 ;
     RECT  2.16 136.485 84.24 136.755 ;
     RECT  2.16 137.025 84.24 137.295 ;
     RECT  2.16 137.565 84.24 137.835 ;
     RECT  2.16 138.105 84.24 138.375 ;
     RECT  2.16 138.645 84.24 138.915 ;
     RECT  2.16 139.185 84.24 139.455 ;
     RECT  2.16 139.725 84.24 139.995 ;
     RECT  2.16 140.265 84.24 140.535 ;
     RECT  2.16 140.805 84.24 141.075 ;
     RECT  2.16 141.345 84.24 141.615 ;
     RECT  2.16 141.885 84.24 142.155 ;
     RECT  2.16 142.425 84.24 142.695 ;
     RECT  2.16 142.965 84.24 143.235 ;
     RECT  2.16 143.505 84.24 143.775 ;
     RECT  2.16 144.045 84.24 144.315 ;
     RECT  2.16 144.585 84.24 144.855 ;
     RECT  2.16 145.125 84.24 145.395 ;
     RECT  2.16 145.665 84.24 145.935 ;
     RECT  2.16 146.205 84.24 146.475 ;
     RECT  2.16 146.745 84.24 147.015 ;
     RECT  2.16 147.285 84.24 147.555 ;
     RECT  2.16 147.825 84.24 148.095 ;
     RECT  2.16 148.365 84.24 148.635 ;
     RECT  2.16 148.905 84.24 149.175 ;
     RECT  2.16 149.445 84.24 149.715 ;
     RECT  2.16 149.985 84.24 150.255 ;
     RECT  2.16 150.525 84.24 150.795 ;
     RECT  2.16 151.065 84.24 151.335 ;
     RECT  2.16 151.605 84.24 151.875 ;
     RECT  2.16 152.145 84.24 152.415 ;
     RECT  2.16 152.685 84.24 152.955 ;
     RECT  2.16 153.225 84.24 153.495 ;
     RECT  2.16 153.765 84.24 154.035 ;
     RECT  2.16 154.305 84.24 154.575 ;
     RECT  2.16 154.845 84.24 155.115 ;
     RECT  2.16 155.385 84.24 155.655 ;
     RECT  2.16 155.925 84.24 156.195 ;
     RECT  2.16 156.465 84.24 156.735 ;
     RECT  2.16 157.005 84.24 157.275 ;
     RECT  2.16 157.545 84.24 157.815 ;
     RECT  2.16 158.085 84.24 158.355 ;
     RECT  2.16 158.625 84.24 158.895 ;
     RECT  2.16 159.165 84.24 159.435 ;
     RECT  2.16 159.705 84.24 159.975 ;
     RECT  2.16 160.245 84.24 160.515 ;
     RECT  2.16 160.785 84.24 161.055 ;
     RECT  2.16 161.325 84.24 161.595 ;
     RECT  2.16 161.865 84.24 162.135 ;
     RECT  2.16 162.405 84.24 162.675 ;
     RECT  2.16 162.945 84.24 163.215 ;
     RECT  2.16 163.485 84.24 163.755 ;
     RECT  2.16 164.025 84.24 164.295 ;
     RECT  2.16 164.565 84.24 164.835 ;
     RECT  2.16 165.105 84.24 165.375 ;
     RECT  2.16 165.645 84.24 165.915 ;
     RECT  2.16 166.185 84.24 166.455 ;
     RECT  2.16 166.725 84.24 166.995 ;
     RECT  2.16 167.265 84.24 167.535 ;
     RECT  2.16 167.805 84.24 168.075 ;
     RECT  2.16 168.345 84.24 168.615 ;
     RECT  2.16 168.885 84.24 169.155 ;
     RECT  2.16 169.425 84.24 169.695 ;
     RECT  2.16 169.965 84.24 170.235 ;
     RECT  2.16 170.505 84.24 170.775 ;
     RECT  2.16 171.045 84.24 171.315 ;
     RECT  2.16 171.585 84.24 171.855 ;
     RECT  2.16 172.125 84.24 172.395 ;
     RECT  2.16 172.665 84.24 172.935 ;
     RECT  2.16 173.205 84.24 173.475 ;
     RECT  2.16 173.745 84.24 174.015 ;
     RECT  2.16 174.285 84.24 174.555 ;
     RECT  2.16 174.825 84.24 175.095 ;
     RECT  2.16 175.365 84.24 175.635 ;
     RECT  2.16 175.905 84.24 176.175 ;
     RECT  2.16 176.445 84.24 176.715 ;
     RECT  2.16 176.985 84.24 177.255 ;
     RECT  2.16 177.525 84.24 177.795 ;
     RECT  2.16 178.065 84.24 178.335 ;
     RECT  2.16 178.605 84.24 178.875 ;
     RECT  2.16 179.145 84.24 179.415 ;
     RECT  2.16 179.685 84.24 179.955 ;
     RECT  2.16 180.225 84.24 180.495 ;
     RECT  2.16 180.765 84.24 181.035 ;
     RECT  2.16 181.305 84.24 181.575 ;
     RECT  2.16 181.845 84.24 182.115 ;
     RECT  2.16 182.385 84.24 182.655 ;
     RECT  2.16 182.925 84.24 183.195 ;
     RECT  2.16 183.465 84.24 183.735 ;
     RECT  2.16 184.005 84.24 184.275 ;
     RECT  2.16 184.545 84.24 184.815 ;
     RECT  2.16 185.085 84.24 185.355 ;
     RECT  2.16 185.625 84.24 185.895 ;
     RECT  2.16 186.165 84.24 186.435 ;
     RECT  2.16 186.705 84.24 186.975 ;
     RECT  2.16 187.245 84.24 187.515 ;
     RECT  2.16 187.785 84.24 188.055 ;
     RECT  2.16 188.325 84.24 188.595 ;
     RECT  2.16 188.865 84.24 189.135 ;
     RECT  2.16 189.405 84.24 189.675 ;
     RECT  2.16 189.945 84.24 190.215 ;
     RECT  2.16 190.485 84.24 190.755 ;
     RECT  2.16 191.025 84.24 191.295 ;
     RECT  2.16 191.565 84.24 191.835 ;
     RECT  2.16 192.105 84.24 192.24 ;
    LAYER RVTP ;
     RECT  2.16 2.295 84.24 2.565 ;
     RECT  2.16 2.835 84.24 3.105 ;
     RECT  2.16 3.375 84.24 3.645 ;
     RECT  2.16 3.915 84.24 4.185 ;
     RECT  2.16 4.455 84.24 4.725 ;
     RECT  2.16 4.995 84.24 5.265 ;
     RECT  2.16 5.535 84.24 5.805 ;
     RECT  2.16 6.075 84.24 6.345 ;
     RECT  2.16 6.615 84.24 6.885 ;
     RECT  2.16 7.155 84.24 7.425 ;
     RECT  2.16 7.695 84.24 7.965 ;
     RECT  2.16 8.235 84.24 8.505 ;
     RECT  2.16 8.775 84.24 9.045 ;
     RECT  2.16 9.315 84.24 9.585 ;
     RECT  2.16 9.855 84.24 10.125 ;
     RECT  2.16 10.395 84.24 10.665 ;
     RECT  2.16 10.935 84.24 11.205 ;
     RECT  2.16 11.475 84.24 11.745 ;
     RECT  2.16 12.015 84.24 12.285 ;
     RECT  2.16 12.555 84.24 12.825 ;
     RECT  2.16 13.095 84.24 13.365 ;
     RECT  2.16 13.635 84.24 13.905 ;
     RECT  2.16 14.175 84.24 14.445 ;
     RECT  2.16 14.715 84.24 14.985 ;
     RECT  2.16 15.255 84.24 15.525 ;
     RECT  2.16 15.795 84.24 16.065 ;
     RECT  2.16 16.335 84.24 16.605 ;
     RECT  2.16 16.875 84.24 17.145 ;
     RECT  2.16 17.415 84.24 17.685 ;
     RECT  2.16 17.955 84.24 18.225 ;
     RECT  2.16 18.495 84.24 18.765 ;
     RECT  2.16 19.035 84.24 19.305 ;
     RECT  2.16 19.575 84.24 19.845 ;
     RECT  2.16 20.115 84.24 20.385 ;
     RECT  2.16 20.655 84.24 20.925 ;
     RECT  2.16 21.195 84.24 21.465 ;
     RECT  2.16 21.735 84.24 22.005 ;
     RECT  2.16 22.275 84.24 22.545 ;
     RECT  2.16 22.815 84.24 23.085 ;
     RECT  2.16 23.355 84.24 23.625 ;
     RECT  2.16 23.895 84.24 24.165 ;
     RECT  2.16 24.435 84.24 24.705 ;
     RECT  2.16 24.975 84.24 25.245 ;
     RECT  2.16 25.515 84.24 25.785 ;
     RECT  2.16 26.055 84.24 26.325 ;
     RECT  2.16 26.595 84.24 26.865 ;
     RECT  2.16 27.135 84.24 27.405 ;
     RECT  2.16 27.675 84.24 27.945 ;
     RECT  2.16 28.215 84.24 28.485 ;
     RECT  2.16 28.755 84.24 29.025 ;
     RECT  2.16 29.295 84.24 29.565 ;
     RECT  2.16 29.835 84.24 30.105 ;
     RECT  2.16 30.375 84.24 30.645 ;
     RECT  2.16 30.915 84.24 31.185 ;
     RECT  2.16 31.455 84.24 31.725 ;
     RECT  2.16 31.995 84.24 32.265 ;
     RECT  2.16 32.535 84.24 32.805 ;
     RECT  2.16 33.075 84.24 33.345 ;
     RECT  2.16 33.615 84.24 33.885 ;
     RECT  2.16 34.155 84.24 34.425 ;
     RECT  2.16 34.695 84.24 34.965 ;
     RECT  2.16 35.235 84.24 35.505 ;
     RECT  2.16 35.775 84.24 36.045 ;
     RECT  2.16 36.315 84.24 36.585 ;
     RECT  2.16 36.855 84.24 37.125 ;
     RECT  2.16 37.395 84.24 37.665 ;
     RECT  2.16 37.935 84.24 38.205 ;
     RECT  2.16 38.475 84.24 38.745 ;
     RECT  2.16 39.015 84.24 39.285 ;
     RECT  2.16 39.555 84.24 39.825 ;
     RECT  2.16 40.095 84.24 40.365 ;
     RECT  2.16 40.635 84.24 40.905 ;
     RECT  2.16 41.175 84.24 41.445 ;
     RECT  2.16 41.715 84.24 41.985 ;
     RECT  2.16 42.255 84.24 42.525 ;
     RECT  2.16 42.795 84.24 43.065 ;
     RECT  2.16 43.335 84.24 43.605 ;
     RECT  2.16 43.875 84.24 44.145 ;
     RECT  2.16 44.415 84.24 44.685 ;
     RECT  2.16 44.955 84.24 45.225 ;
     RECT  2.16 45.495 84.24 45.765 ;
     RECT  2.16 46.035 84.24 46.305 ;
     RECT  2.16 46.575 84.24 46.845 ;
     RECT  2.16 47.115 84.24 47.385 ;
     RECT  2.16 47.655 84.24 47.925 ;
     RECT  2.16 48.195 84.24 48.465 ;
     RECT  2.16 48.735 84.24 49.005 ;
     RECT  2.16 49.275 84.24 49.545 ;
     RECT  2.16 49.815 84.24 50.085 ;
     RECT  2.16 50.355 84.24 50.625 ;
     RECT  2.16 50.895 84.24 51.165 ;
     RECT  2.16 51.435 84.24 51.705 ;
     RECT  2.16 51.975 84.24 52.245 ;
     RECT  2.16 52.515 84.24 52.785 ;
     RECT  2.16 53.055 84.24 53.325 ;
     RECT  2.16 53.595 84.24 53.865 ;
     RECT  2.16 54.135 84.24 54.405 ;
     RECT  2.16 54.675 84.24 54.945 ;
     RECT  2.16 55.215 84.24 55.485 ;
     RECT  2.16 55.755 84.24 56.025 ;
     RECT  2.16 56.295 84.24 56.565 ;
     RECT  2.16 56.835 84.24 57.105 ;
     RECT  2.16 57.375 84.24 57.645 ;
     RECT  2.16 57.915 84.24 58.185 ;
     RECT  2.16 58.455 84.24 58.725 ;
     RECT  2.16 58.995 84.24 59.265 ;
     RECT  2.16 59.535 84.24 59.805 ;
     RECT  2.16 60.075 84.24 60.345 ;
     RECT  2.16 60.615 84.24 60.885 ;
     RECT  2.16 61.155 84.24 61.425 ;
     RECT  2.16 61.695 84.24 61.965 ;
     RECT  2.16 62.235 84.24 62.505 ;
     RECT  2.16 62.775 84.24 63.045 ;
     RECT  2.16 63.315 84.24 63.585 ;
     RECT  2.16 63.855 84.24 64.125 ;
     RECT  2.16 64.395 84.24 64.665 ;
     RECT  2.16 64.935 84.24 65.205 ;
     RECT  2.16 65.475 84.24 65.745 ;
     RECT  2.16 66.015 84.24 66.285 ;
     RECT  2.16 66.555 84.24 66.825 ;
     RECT  2.16 67.095 84.24 67.365 ;
     RECT  2.16 67.635 84.24 67.905 ;
     RECT  2.16 68.175 84.24 68.445 ;
     RECT  2.16 68.715 84.24 68.985 ;
     RECT  2.16 69.255 84.24 69.525 ;
     RECT  2.16 69.795 84.24 70.065 ;
     RECT  2.16 70.335 84.24 70.605 ;
     RECT  2.16 70.875 84.24 71.145 ;
     RECT  2.16 71.415 84.24 71.685 ;
     RECT  2.16 71.955 84.24 72.225 ;
     RECT  2.16 72.495 84.24 72.765 ;
     RECT  2.16 73.035 84.24 73.305 ;
     RECT  2.16 73.575 84.24 73.845 ;
     RECT  2.16 74.115 84.24 74.385 ;
     RECT  2.16 74.655 84.24 74.925 ;
     RECT  2.16 75.195 84.24 75.465 ;
     RECT  2.16 75.735 84.24 76.005 ;
     RECT  2.16 76.275 84.24 76.545 ;
     RECT  2.16 76.815 84.24 77.085 ;
     RECT  2.16 77.355 84.24 77.625 ;
     RECT  2.16 77.895 84.24 78.165 ;
     RECT  2.16 78.435 84.24 78.705 ;
     RECT  2.16 78.975 84.24 79.245 ;
     RECT  2.16 79.515 84.24 79.785 ;
     RECT  2.16 80.055 84.24 80.325 ;
     RECT  2.16 80.595 84.24 80.865 ;
     RECT  2.16 81.135 84.24 81.405 ;
     RECT  2.16 81.675 84.24 81.945 ;
     RECT  2.16 82.215 84.24 82.485 ;
     RECT  2.16 82.755 84.24 83.025 ;
     RECT  2.16 83.295 84.24 83.565 ;
     RECT  2.16 83.835 84.24 84.105 ;
     RECT  2.16 84.375 84.24 84.645 ;
     RECT  2.16 84.915 84.24 85.185 ;
     RECT  2.16 85.455 84.24 85.725 ;
     RECT  2.16 85.995 84.24 86.265 ;
     RECT  2.16 86.535 84.24 86.805 ;
     RECT  2.16 87.075 84.24 87.345 ;
     RECT  2.16 87.615 84.24 87.885 ;
     RECT  2.16 88.155 84.24 88.425 ;
     RECT  2.16 88.695 84.24 88.965 ;
     RECT  2.16 89.235 84.24 89.505 ;
     RECT  2.16 89.775 84.24 90.045 ;
     RECT  2.16 90.315 84.24 90.585 ;
     RECT  2.16 90.855 84.24 91.125 ;
     RECT  2.16 91.395 84.24 91.665 ;
     RECT  2.16 91.935 84.24 92.205 ;
     RECT  2.16 92.475 84.24 92.745 ;
     RECT  2.16 93.015 84.24 93.285 ;
     RECT  2.16 93.555 84.24 93.825 ;
     RECT  2.16 94.095 84.24 94.365 ;
     RECT  2.16 94.635 84.24 94.905 ;
     RECT  2.16 95.175 84.24 95.445 ;
     RECT  2.16 95.715 84.24 95.985 ;
     RECT  2.16 96.255 84.24 96.525 ;
     RECT  2.16 96.795 84.24 97.065 ;
     RECT  2.16 97.335 84.24 97.605 ;
     RECT  2.16 97.875 84.24 98.145 ;
     RECT  2.16 98.415 84.24 98.685 ;
     RECT  2.16 98.955 84.24 99.225 ;
     RECT  2.16 99.495 84.24 99.765 ;
     RECT  2.16 100.035 84.24 100.305 ;
     RECT  2.16 100.575 84.24 100.845 ;
     RECT  2.16 101.115 84.24 101.385 ;
     RECT  2.16 101.655 84.24 101.925 ;
     RECT  2.16 102.195 84.24 102.465 ;
     RECT  2.16 102.735 84.24 103.005 ;
     RECT  2.16 103.275 84.24 103.545 ;
     RECT  2.16 103.815 84.24 104.085 ;
     RECT  2.16 104.355 84.24 104.625 ;
     RECT  2.16 104.895 84.24 105.165 ;
     RECT  2.16 105.435 84.24 105.705 ;
     RECT  2.16 105.975 84.24 106.245 ;
     RECT  2.16 106.515 84.24 106.785 ;
     RECT  2.16 107.055 84.24 107.325 ;
     RECT  2.16 107.595 84.24 107.865 ;
     RECT  2.16 108.135 84.24 108.405 ;
     RECT  2.16 108.675 84.24 108.945 ;
     RECT  2.16 109.215 84.24 109.485 ;
     RECT  2.16 109.755 84.24 110.025 ;
     RECT  2.16 110.295 84.24 110.565 ;
     RECT  2.16 110.835 84.24 111.105 ;
     RECT  2.16 111.375 84.24 111.645 ;
     RECT  2.16 111.915 84.24 112.185 ;
     RECT  2.16 112.455 84.24 112.725 ;
     RECT  2.16 112.995 84.24 113.265 ;
     RECT  2.16 113.535 84.24 113.805 ;
     RECT  2.16 114.075 84.24 114.345 ;
     RECT  2.16 114.615 84.24 114.885 ;
     RECT  2.16 115.155 84.24 115.425 ;
     RECT  2.16 115.695 84.24 115.965 ;
     RECT  2.16 116.235 84.24 116.505 ;
     RECT  2.16 116.775 84.24 117.045 ;
     RECT  2.16 117.315 84.24 117.585 ;
     RECT  2.16 117.855 84.24 118.125 ;
     RECT  2.16 118.395 84.24 118.665 ;
     RECT  2.16 118.935 84.24 119.205 ;
     RECT  2.16 119.475 84.24 119.745 ;
     RECT  2.16 120.015 84.24 120.285 ;
     RECT  2.16 120.555 84.24 120.825 ;
     RECT  2.16 121.095 84.24 121.365 ;
     RECT  2.16 121.635 84.24 121.905 ;
     RECT  2.16 122.175 84.24 122.445 ;
     RECT  2.16 122.715 84.24 122.985 ;
     RECT  2.16 123.255 84.24 123.525 ;
     RECT  2.16 123.795 84.24 124.065 ;
     RECT  2.16 124.335 84.24 124.605 ;
     RECT  2.16 124.875 84.24 125.145 ;
     RECT  2.16 125.415 84.24 125.685 ;
     RECT  2.16 125.955 84.24 126.225 ;
     RECT  2.16 126.495 84.24 126.765 ;
     RECT  2.16 127.035 84.24 127.305 ;
     RECT  2.16 127.575 84.24 127.845 ;
     RECT  2.16 128.115 84.24 128.385 ;
     RECT  2.16 128.655 84.24 128.925 ;
     RECT  2.16 129.195 84.24 129.465 ;
     RECT  2.16 129.735 84.24 130.005 ;
     RECT  2.16 130.275 84.24 130.545 ;
     RECT  2.16 130.815 84.24 131.085 ;
     RECT  2.16 131.355 84.24 131.625 ;
     RECT  2.16 131.895 84.24 132.165 ;
     RECT  2.16 132.435 84.24 132.705 ;
     RECT  2.16 132.975 84.24 133.245 ;
     RECT  2.16 133.515 84.24 133.785 ;
     RECT  2.16 134.055 84.24 134.325 ;
     RECT  2.16 134.595 84.24 134.865 ;
     RECT  2.16 135.135 84.24 135.405 ;
     RECT  2.16 135.675 84.24 135.945 ;
     RECT  2.16 136.215 84.24 136.485 ;
     RECT  2.16 136.755 84.24 137.025 ;
     RECT  2.16 137.295 84.24 137.565 ;
     RECT  2.16 137.835 84.24 138.105 ;
     RECT  2.16 138.375 84.24 138.645 ;
     RECT  2.16 138.915 84.24 139.185 ;
     RECT  2.16 139.455 84.24 139.725 ;
     RECT  2.16 139.995 84.24 140.265 ;
     RECT  2.16 140.535 84.24 140.805 ;
     RECT  2.16 141.075 84.24 141.345 ;
     RECT  2.16 141.615 84.24 141.885 ;
     RECT  2.16 142.155 84.24 142.425 ;
     RECT  2.16 142.695 84.24 142.965 ;
     RECT  2.16 143.235 84.24 143.505 ;
     RECT  2.16 143.775 84.24 144.045 ;
     RECT  2.16 144.315 84.24 144.585 ;
     RECT  2.16 144.855 84.24 145.125 ;
     RECT  2.16 145.395 84.24 145.665 ;
     RECT  2.16 145.935 84.24 146.205 ;
     RECT  2.16 146.475 84.24 146.745 ;
     RECT  2.16 147.015 84.24 147.285 ;
     RECT  2.16 147.555 84.24 147.825 ;
     RECT  2.16 148.095 84.24 148.365 ;
     RECT  2.16 148.635 84.24 148.905 ;
     RECT  2.16 149.175 84.24 149.445 ;
     RECT  2.16 149.715 84.24 149.985 ;
     RECT  2.16 150.255 84.24 150.525 ;
     RECT  2.16 150.795 84.24 151.065 ;
     RECT  2.16 151.335 84.24 151.605 ;
     RECT  2.16 151.875 84.24 152.145 ;
     RECT  2.16 152.415 84.24 152.685 ;
     RECT  2.16 152.955 84.24 153.225 ;
     RECT  2.16 153.495 84.24 153.765 ;
     RECT  2.16 154.035 84.24 154.305 ;
     RECT  2.16 154.575 84.24 154.845 ;
     RECT  2.16 155.115 84.24 155.385 ;
     RECT  2.16 155.655 84.24 155.925 ;
     RECT  2.16 156.195 84.24 156.465 ;
     RECT  2.16 156.735 84.24 157.005 ;
     RECT  2.16 157.275 84.24 157.545 ;
     RECT  2.16 157.815 84.24 158.085 ;
     RECT  2.16 158.355 84.24 158.625 ;
     RECT  2.16 158.895 84.24 159.165 ;
     RECT  2.16 159.435 84.24 159.705 ;
     RECT  2.16 159.975 84.24 160.245 ;
     RECT  2.16 160.515 84.24 160.785 ;
     RECT  2.16 161.055 84.24 161.325 ;
     RECT  2.16 161.595 84.24 161.865 ;
     RECT  2.16 162.135 84.24 162.405 ;
     RECT  2.16 162.675 84.24 162.945 ;
     RECT  2.16 163.215 84.24 163.485 ;
     RECT  2.16 163.755 84.24 164.025 ;
     RECT  2.16 164.295 84.24 164.565 ;
     RECT  2.16 164.835 84.24 165.105 ;
     RECT  2.16 165.375 84.24 165.645 ;
     RECT  2.16 165.915 84.24 166.185 ;
     RECT  2.16 166.455 84.24 166.725 ;
     RECT  2.16 166.995 84.24 167.265 ;
     RECT  2.16 167.535 84.24 167.805 ;
     RECT  2.16 168.075 84.24 168.345 ;
     RECT  2.16 168.615 84.24 168.885 ;
     RECT  2.16 169.155 84.24 169.425 ;
     RECT  2.16 169.695 84.24 169.965 ;
     RECT  2.16 170.235 84.24 170.505 ;
     RECT  2.16 170.775 84.24 171.045 ;
     RECT  2.16 171.315 84.24 171.585 ;
     RECT  2.16 171.855 84.24 172.125 ;
     RECT  2.16 172.395 84.24 172.665 ;
     RECT  2.16 172.935 84.24 173.205 ;
     RECT  2.16 173.475 84.24 173.745 ;
     RECT  2.16 174.015 84.24 174.285 ;
     RECT  2.16 174.555 84.24 174.825 ;
     RECT  2.16 175.095 84.24 175.365 ;
     RECT  2.16 175.635 84.24 175.905 ;
     RECT  2.16 176.175 84.24 176.445 ;
     RECT  2.16 176.715 84.24 176.985 ;
     RECT  2.16 177.255 84.24 177.525 ;
     RECT  2.16 177.795 84.24 178.065 ;
     RECT  2.16 178.335 84.24 178.605 ;
     RECT  2.16 178.875 84.24 179.145 ;
     RECT  2.16 179.415 84.24 179.685 ;
     RECT  2.16 179.955 84.24 180.225 ;
     RECT  2.16 180.495 84.24 180.765 ;
     RECT  2.16 181.035 84.24 181.305 ;
     RECT  2.16 181.575 84.24 181.845 ;
     RECT  2.16 182.115 84.24 182.385 ;
     RECT  2.16 182.655 84.24 182.925 ;
     RECT  2.16 183.195 84.24 183.465 ;
     RECT  2.16 183.735 84.24 184.005 ;
     RECT  2.16 184.275 84.24 184.545 ;
     RECT  2.16 184.815 84.24 185.085 ;
     RECT  2.16 185.355 84.24 185.625 ;
     RECT  2.16 185.895 84.24 186.165 ;
     RECT  2.16 186.435 84.24 186.705 ;
     RECT  2.16 186.975 84.24 187.245 ;
     RECT  2.16 187.515 84.24 187.785 ;
     RECT  2.16 188.055 84.24 188.325 ;
     RECT  2.16 188.595 84.24 188.865 ;
     RECT  2.16 189.135 84.24 189.405 ;
     RECT  2.16 189.675 84.24 189.945 ;
     RECT  2.16 190.215 84.24 190.485 ;
     RECT  2.16 190.755 84.24 191.025 ;
     RECT  2.16 191.295 84.24 191.565 ;
     RECT  2.16 191.835 84.24 192.105 ;
    LAYER M1 ;
     RECT  2.16 2.151 84.24 192.249 ;
    LAYER M2 ;
     RECT  0.103 18.036 0.139 18.054 ;
     RECT  0.103 89.856 0.139 89.874 ;
     RECT  0.103 110.466 0.139 110.484 ;
     RECT  0.103 130.356 0.139 130.374 ;
     RECT  0.103 189.216 0.139 189.594 ;
     RECT  0.103 51.174 0.203 51.624 ;
     RECT  0.103 7.596 2.16 7.614 ;
     RECT  0.103 10.296 2.16 10.314 ;
     RECT  0.139 18.036 2.16 18.414 ;
     RECT  0.103 20.286 2.16 20.304 ;
     RECT  0.103 21.546 2.16 21.834 ;
     RECT  0.103 24.066 2.16 24.084 ;
     RECT  0.103 25.326 2.16 25.344 ;
     RECT  0.103 27.216 2.16 27.594 ;
     RECT  0.103 30.996 2.16 31.374 ;
     RECT  0.103 34.506 2.16 34.884 ;
     RECT  0.139 38.286 2.16 38.664 ;
     RECT  0.103 40.536 2.16 40.554 ;
     RECT  0.103 41.796 2.16 41.814 ;
     RECT  0.103 44.046 2.16 44.334 ;
     RECT  0.103 47.466 2.16 47.844 ;
     RECT  0.203 51.606 2.16 51.624 ;
     RECT  0.103 53.496 2.16 53.514 ;
     RECT  0.139 54.756 2.16 54.774 ;
     RECT  0.103 58.536 2.16 58.554 ;
     RECT  0.103 60.786 2.16 60.804 ;
     RECT  0.103 63.936 2.16 64.584 ;
     RECT  0.103 67.716 2.16 68.094 ;
     RECT  0.103 69.966 2.16 69.984 ;
     RECT  0.103 71.226 2.16 71.514 ;
     RECT  0.103 73.746 2.16 73.764 ;
     RECT  0.103 75.006 2.16 75.024 ;
     RECT  0.103 76.896 2.16 77.544 ;
     RECT  0.103 80.676 2.16 81.054 ;
     RECT  0.139 82.926 2.16 82.944 ;
     RECT  0.103 84.186 2.16 84.474 ;
     RECT  0.103 87.966 2.16 87.984 ;
     RECT  0.139 89.856 2.16 90.234 ;
     RECT  0.103 93.726 2.16 94.014 ;
     RECT  0.103 95.256 2.16 95.274 ;
     RECT  0.103 97.146 2.16 97.524 ;
     RECT  0.103 100.656 2.16 101.304 ;
     RECT  0.103 104.436 2.16 104.454 ;
     RECT  0.103 106.686 2.16 106.974 ;
     RECT  0.103 108.216 2.16 108.234 ;
     RECT  0.139 110.106 2.16 110.484 ;
     RECT  0.103 113.616 2.16 114.264 ;
     RECT  0.103 117.756 2.16 117.774 ;
     RECT  0.103 119.646 2.16 119.664 ;
     RECT  0.103 121.176 2.16 121.194 ;
     RECT  0.103 123.426 2.16 123.444 ;
     RECT  0.103 124.686 2.16 124.704 ;
     RECT  0.103 126.936 2.16 127.224 ;
     RECT  0.139 130.356 2.16 130.734 ;
     RECT  0.103 132.606 2.16 132.624 ;
     RECT  0.139 133.866 2.16 134.154 ;
     RECT  0.103 136.386 2.16 136.404 ;
     RECT  0.139 137.646 2.16 137.664 ;
     RECT  0.103 139.896 2.16 139.914 ;
     RECT  0.103 143.316 2.16 143.694 ;
     RECT  0.103 146.826 2.16 147.114 ;
     RECT  0.103 150.606 2.16 150.984 ;
     RECT  0.103 152.856 2.16 152.874 ;
     RECT  0.139 154.116 2.16 154.134 ;
     RECT  0.103 156.366 2.16 156.654 ;
     RECT  0.103 159.786 2.16 159.804 ;
     RECT  0.103 163.296 2.16 163.944 ;
     RECT  0.139 165.816 2.16 165.834 ;
     RECT  0.103 167.076 2.16 167.094 ;
     RECT  0.103 169.326 2.16 169.614 ;
     RECT  0.139 170.856 2.16 170.874 ;
     RECT  0.103 172.746 2.16 173.124 ;
     RECT  0.103 176.256 2.16 176.904 ;
     RECT  0.103 180.036 2.16 180.414 ;
     RECT  0.103 182.286 2.16 182.304 ;
     RECT  0.103 183.816 2.16 183.834 ;
     RECT  0.103 186.066 2.16 186.084 ;
     RECT  0.103 187.326 2.16 187.344 ;
     RECT  0.139 189.216 2.16 189.864 ;
     RECT  2.16 2.151 84.24 192.249 ;
     RECT  84.24 114.246 84.371 128.304 ;
     RECT  84.24 140.976 84.371 148.824 ;
     RECT  84.24 17.316 84.407 22.464 ;
     RECT  84.24 23.292 84.407 27.054 ;
     RECT  84.24 37.566 84.407 47.61 ;
     RECT  84.24 48.366 84.407 52.434 ;
     RECT  84.24 58.626 84.407 65.664 ;
     RECT  84.24 73.206 84.407 74.034 ;
     RECT  84.24 92.106 84.407 98.874 ;
     RECT  84.24 100.746 84.407 104.544 ;
     RECT  84.24 112.086 84.407 113.454 ;
     RECT  84.371 117.756 84.407 128.304 ;
     RECT  84.24 129.096 84.407 134.784 ;
     RECT  84.24 135.846 84.407 137.484 ;
     RECT  84.24 138.276 84.407 139.914 ;
     RECT  84.24 149.616 84.407 155.304 ;
     RECT  84.24 167.976 84.407 170.694 ;
     RECT  84.24 178.776 84.407 185.814 ;
     RECT  84.407 42.156 84.911 47.61 ;
     RECT  84.407 49.176 84.911 52.434 ;
     RECT  84.407 92.106 84.911 98.604 ;
     RECT  84.407 112.086 84.911 112.374 ;
     RECT  84.407 117.756 84.911 128.034 ;
     RECT  84.24 27.846 84.947 28.71 ;
     RECT  84.24 29.736 84.947 36.504 ;
     RECT  84.407 37.566 84.947 41.364 ;
     RECT  84.911 49.986 84.947 52.434 ;
     RECT  84.24 53.226 84.947 57.834 ;
     RECT  84.407 58.626 84.947 64.314 ;
     RECT  84.24 66.456 84.947 72.414 ;
     RECT  84.407 73.746 84.947 74.034 ;
     RECT  84.24 75.636 84.947 82.134 ;
     RECT  84.911 92.106 84.947 95.364 ;
     RECT  84.24 99.666 84.947 99.954 ;
     RECT  84.24 106.416 84.947 111.294 ;
     RECT  84.911 123.426 84.947 128.034 ;
     RECT  84.407 135.846 84.947 136.404 ;
     RECT  84.407 138.276 84.947 139.374 ;
     RECT  84.371 145.296 84.947 148.824 ;
     RECT  84.407 149.616 84.947 151.524 ;
     RECT  84.24 156.096 84.947 161.01 ;
     RECT  84.407 178.776 84.947 179.604 ;
     RECT  84.24 186.606 84.947 187.164 ;
     RECT  84.24 187.956 84.947 191.214 ;
     RECT  84.407 19.206 85.487 21.924 ;
     RECT  84.947 28.386 85.487 28.71 ;
     RECT  84.407 100.746 85.487 104.454 ;
     RECT  84.947 125.856 85.487 128.034 ;
     RECT  84.947 145.296 85.487 147.474 ;
     RECT  84.407 167.976 85.487 170.154 ;
     RECT  84.24 11.376 85.523 11.934 ;
     RECT  84.407 17.856 85.523 18.45 ;
     RECT  85.487 19.206 85.523 19.764 ;
     RECT  85.487 20.556 85.523 21.924 ;
     RECT  84.407 24.606 85.523 27.054 ;
     RECT  85.487 28.386 85.523 28.674 ;
     RECT  84.947 30.006 85.523 31.374 ;
     RECT  84.947 32.166 85.523 36.504 ;
     RECT  84.947 37.566 85.523 39.204 ;
     RECT  84.947 39.996 85.523 41.094 ;
     RECT  84.911 42.156 85.523 47.574 ;
     RECT  84.407 48.366 85.523 48.384 ;
     RECT  84.911 49.176 85.523 49.194 ;
     RECT  84.947 49.986 85.523 52.164 ;
     RECT  84.947 53.226 85.523 53.244 ;
     RECT  84.947 54.306 85.523 57.834 ;
     RECT  84.947 59.436 85.523 64.08 ;
     RECT  84.407 65.106 85.523 65.664 ;
     RECT  84.947 66.456 85.523 68.364 ;
     RECT  84.947 69.156 85.523 69.714 ;
     RECT  84.947 70.506 85.523 72.414 ;
     RECT  84.24 74.862 85.523 74.88 ;
     RECT  84.947 75.906 85.523 82.134 ;
     RECT  84.24 82.926 85.523 83.484 ;
     RECT  84.24 84.276 85.523 86.184 ;
     RECT  84.24 86.976 85.523 88.344 ;
     RECT  84.24 89.136 85.523 89.694 ;
     RECT  84.24 90.486 85.523 91.314 ;
     RECT  84.947 92.646 85.523 95.364 ;
     RECT  84.911 96.156 85.523 98.604 ;
     RECT  84.947 99.936 85.523 99.954 ;
     RECT  85.487 101.826 85.523 104.454 ;
     RECT  84.24 105.336 85.523 105.624 ;
     RECT  84.947 106.416 85.523 111.024 ;
     RECT  84.407 113.166 85.523 113.454 ;
     RECT  84.371 114.246 85.523 116.964 ;
     RECT  84.911 117.756 85.523 122.634 ;
     RECT  84.947 123.426 85.523 125.1 ;
     RECT  85.487 125.856 85.523 126.684 ;
     RECT  85.487 127.476 85.523 128.034 ;
     RECT  84.407 129.636 85.523 134.784 ;
     RECT  84.407 137.466 85.523 137.484 ;
     RECT  84.947 138.276 85.523 138.564 ;
     RECT  84.947 139.356 85.523 139.374 ;
     RECT  84.371 140.976 85.523 144.234 ;
     RECT  85.487 145.566 85.523 147.474 ;
     RECT  84.947 148.266 85.523 148.824 ;
     RECT  84.947 149.886 85.523 151.254 ;
     RECT  84.407 152.316 85.523 155.304 ;
     RECT  84.947 156.096 85.523 157.194 ;
     RECT  84.947 157.986 85.523 159.624 ;
     RECT  84.947 160.416 85.523 160.434 ;
     RECT  84.24 161.766 85.523 167.184 ;
     RECT  85.487 167.976 85.523 168.534 ;
     RECT  85.487 169.326 85.523 170.154 ;
     RECT  84.24 171.486 85.523 171.774 ;
     RECT  84.24 172.566 85.523 177.984 ;
     RECT  84.947 178.776 85.523 178.794 ;
     RECT  84.947 179.586 85.523 179.604 ;
     RECT  84.407 180.396 85.523 185.814 ;
     RECT  84.947 187.146 85.523 187.164 ;
     RECT  84.947 188.496 85.523 191.214 ;
     RECT  84.407 23.292 85.559 23.814 ;
     RECT  85.523 28.656 85.559 28.674 ;
     RECT  85.523 69.696 85.559 69.714 ;
     RECT  85.523 72.126 85.559 72.144 ;
     RECT  85.523 97.506 85.559 97.524 ;
     RECT  85.523 102.906 85.559 102.924 ;
     RECT  84.24 2.772 86.315 2.79 ;
     RECT  84.24 7.596 86.315 7.614 ;
     RECT  84.24 9.486 86.315 9.504 ;
     RECT  85.523 11.376 86.315 11.394 ;
     RECT  85.523 18.432 86.315 18.45 ;
     RECT  85.559 23.292 86.315 23.31 ;
     RECT  85.523 25.416 86.315 25.434 ;
     RECT  85.523 31.356 86.315 31.374 ;
     RECT  85.523 34.866 86.315 34.884 ;
     RECT  85.523 38.646 86.315 38.664 ;
     RECT  85.523 40.536 86.315 40.554 ;
     RECT  85.523 51.246 86.315 51.624 ;
     RECT  85.523 54.846 86.315 54.864 ;
     RECT  84.947 58.626 86.315 58.644 ;
     RECT  85.523 62.406 86.315 62.424 ;
     RECT  85.523 64.062 86.315 64.08 ;
     RECT  85.523 68.076 86.315 68.094 ;
     RECT  84.947 73.746 86.315 73.764 ;
     RECT  85.523 77.526 86.315 77.544 ;
     RECT  85.523 81.036 86.315 81.054 ;
     RECT  85.523 82.926 86.315 82.944 ;
     RECT  85.523 84.276 86.315 84.564 ;
     RECT  85.523 93.726 86.315 94.014 ;
     RECT  85.523 95.346 86.315 95.364 ;
     RECT  85.487 100.746 86.315 101.034 ;
     RECT  85.523 104.436 86.315 104.454 ;
     RECT  85.523 106.416 86.315 106.974 ;
     RECT  85.523 108.576 86.315 108.594 ;
     RECT  85.523 110.232 86.315 110.25 ;
     RECT  84.911 112.356 86.315 112.374 ;
     RECT  85.523 114.246 86.315 114.264 ;
     RECT  85.523 117.756 86.315 117.774 ;
     RECT  85.523 123.426 86.315 123.444 ;
     RECT  85.523 125.046 86.315 125.064 ;
     RECT  85.523 130.716 86.315 130.734 ;
     RECT  85.523 132.336 86.315 132.624 ;
     RECT  85.523 134.226 86.315 134.244 ;
     RECT  84.947 136.386 86.315 136.404 ;
     RECT  85.523 143.676 86.315 143.694 ;
     RECT  85.523 147.096 86.315 147.114 ;
     RECT  85.523 150.606 86.315 150.984 ;
     RECT  85.523 152.316 86.315 152.874 ;
     RECT  85.523 156.096 86.315 156.654 ;
     RECT  85.523 157.986 86.315 158.58 ;
     RECT  85.523 161.766 86.315 161.784 ;
     RECT  85.523 163.386 86.315 163.944 ;
     RECT  85.523 165.546 86.315 165.834 ;
     RECT  85.523 167.076 86.315 167.094 ;
     RECT  85.523 169.326 86.315 169.614 ;
     RECT  85.523 172.566 86.315 173.124 ;
     RECT  85.523 176.256 86.315 176.904 ;
     RECT  85.523 183.906 86.315 183.924 ;
     RECT  85.523 185.796 86.315 185.814 ;
     RECT  85.523 189.846 86.315 189.864 ;
     RECT  84.24 192.042 86.315 192.06 ;
    LAYER M3 ;
     RECT  29.16 1.723 29.178 2.143 ;
     RECT  39.924 0.571 39.942 2.143 ;
     RECT  31.32 1.723 31.338 2.219 ;
     RECT  37.764 1.723 37.782 2.219 ;
     RECT  41.976 1.723 41.994 2.219 ;
     RECT  29.16 2.143 29.505 2.371 ;
     RECT  39.924 2.143 40.305 2.371 ;
     RECT  2.415 2.143 2.505 2.413 ;
     RECT  7.815 2.143 7.905 2.413 ;
     RECT  13.215 2.143 13.305 2.413 ;
     RECT  18.615 2.143 18.705 2.413 ;
     RECT  24.015 2.143 24.105 2.413 ;
     RECT  34.815 2.143 34.905 2.413 ;
     RECT  39.744 2.371 40.305 2.413 ;
     RECT  45.615 2.143 45.705 2.413 ;
     RECT  51.015 2.143 51.105 2.413 ;
     RECT  56.415 2.143 56.505 2.413 ;
     RECT  61.815 2.143 61.905 2.413 ;
     RECT  67.215 2.143 67.305 2.413 ;
     RECT  72.615 2.143 72.705 2.413 ;
     RECT  78.015 2.143 78.105 2.413 ;
     RECT  83.415 2.143 83.505 2.413 ;
     RECT  33.444 0.091 33.462 2.489 ;
     RECT  37.512 2.371 37.53 2.489 ;
     RECT  41.472 2.263 41.49 2.489 ;
     RECT  39.744 2.413 40.497 2.569 ;
     RECT  39.744 2.569 40.626 2.605 ;
     RECT  7.815 2.413 8.097 2.635 ;
     RECT  2.415 2.413 2.697 2.641 ;
     RECT  39.492 2.605 40.626 2.641 ;
     RECT  2.304 2.641 2.697 2.717 ;
     RECT  31.14 2.371 31.158 2.731 ;
     RECT  38.7 2.641 38.718 2.731 ;
     RECT  30.996 2.731 31.158 2.759 ;
     RECT  33.12 2.641 33.426 2.759 ;
     RECT  37.332 2.605 37.35 2.759 ;
     RECT  38.556 2.731 38.718 2.759 ;
     RECT  39.492 2.641 40.806 2.759 ;
     RECT  34.815 2.413 35.097 2.767 ;
     RECT  36.576 2.641 36.594 2.767 ;
     RECT  29.16 2.371 30.042 2.779 ;
     RECT  7.704 2.635 8.097 2.795 ;
     RECT  86.292 2.683 86.31 2.795 ;
     RECT  28.98 2.779 30.042 2.803 ;
     RECT  32.004 2.767 32.022 2.803 ;
     RECT  60.012 2.731 60.03 2.803 ;
     RECT  32.004 2.803 32.166 2.813 ;
     RECT  38.556 2.759 38.574 2.813 ;
     RECT  28.908 2.803 30.042 2.827 ;
     RECT  39.6 2.759 40.626 2.831 ;
     RECT  58.716 2.731 58.734 2.831 ;
     RECT  59.796 2.803 60.03 2.831 ;
     RECT  28.908 2.827 30.078 2.861 ;
     RECT  39.6 2.831 40.497 2.861 ;
     RECT  59.796 2.831 59.814 2.867 ;
     RECT  34.776 2.767 35.097 2.939 ;
     RECT  29.415 2.861 30.078 3.001 ;
     RECT  30.996 2.759 31.014 3.029 ;
     RECT  36.432 2.767 36.594 3.029 ;
     RECT  27.144 2.731 27.162 3.065 ;
     RECT  33.408 2.759 33.426 3.065 ;
     RECT  36.432 3.029 36.45 3.065 ;
     RECT  54.504 0.523 54.522 3.065 ;
     RECT  29.415 3.001 30.186 3.173 ;
     RECT  32.148 2.813 32.166 3.173 ;
     RECT  29.415 3.173 30.078 3.197 ;
     RECT  46.98 4.351 46.998 4.531 ;
     RECT  45.615 2.413 45.897 4.621 ;
     RECT  46.908 4.531 46.998 4.621 ;
     RECT  2.415 2.717 2.697 4.801 ;
     RECT  34.815 2.939 35.097 4.801 ;
     RECT  2.304 4.801 2.697 4.877 ;
     RECT  40.215 2.861 40.497 4.891 ;
     RECT  17.352 4.801 17.37 4.919 ;
     RECT  7.815 2.795 8.097 4.927 ;
     RECT  34.2 4.801 35.097 4.955 ;
     RECT  6.84 4.795 6.858 4.973 ;
     RECT  7.815 4.927 8.622 4.973 ;
     RECT  45.615 4.621 46.998 4.999 ;
     RECT  45.615 4.999 47.07 5.071 ;
     RECT  45.615 5.071 47.358 5.197 ;
     RECT  45.504 5.197 47.538 5.341 ;
     RECT  50.076 3.181 50.094 5.801 ;
     RECT  45.504 5.341 47.862 5.809 ;
     RECT  45.504 5.809 48.294 5.999 ;
     RECT  45.504 5.999 48.15 6.035 ;
     RECT  40.104 4.891 40.497 6.305 ;
     RECT  45.504 6.035 47.862 7.079 ;
     RECT  0.108 7.003 0.126 7.619 ;
     RECT  86.292 7.003 86.31 7.619 ;
     RECT  45.615 7.079 47.862 7.889 ;
     RECT  68.976 7.735 68.994 7.889 ;
     RECT  47.844 7.889 47.862 9.041 ;
     RECT  7.815 4.973 8.097 9.112 ;
     RECT  2.415 4.877 2.697 9.121 ;
     RECT  7.704 9.112 8.097 9.121 ;
     RECT  7.704 9.121 8.154 9.149 ;
     RECT  2.304 9.121 2.697 9.197 ;
     RECT  86.292 9.163 86.31 9.509 ;
     RECT  22.716 9.481 22.734 9.517 ;
     RECT  7.815 9.149 8.154 9.545 ;
     RECT  22.716 9.517 22.914 9.653 ;
     RECT  22.896 9.653 22.914 9.689 ;
     RECT  49.14 9.661 49.158 9.779 ;
     RECT  45.615 7.889 46.458 9.895 ;
     RECT  47.484 9.085 47.502 9.931 ;
     RECT  45.615 9.895 46.71 10.057 ;
     RECT  47.484 9.931 47.862 10.057 ;
     RECT  45.615 10.057 47.862 10.201 ;
     RECT  83.415 2.413 83.697 10.267 ;
     RECT  0.108 10.267 0.126 10.319 ;
     RECT  43.884 10.165 43.902 10.319 ;
     RECT  45.615 10.201 48.438 10.319 ;
     RECT  83.415 10.267 83.79 10.319 ;
     RECT  3.96 10.291 3.978 10.349 ;
     RECT  45.615 10.319 47.862 10.499 ;
     RECT  45.615 10.499 47.502 11.281 ;
     RECT  2.415 9.197 2.697 11.323 ;
     RECT  2.304 11.323 2.697 11.399 ;
     RECT  86.292 11.323 86.31 11.399 ;
     RECT  11.52 11.371 11.538 11.435 ;
     RECT  20.52 11.371 20.538 11.543 ;
     RECT  45.615 11.281 47.646 11.741 ;
     RECT  46.692 11.741 47.646 11.821 ;
     RECT  46.692 11.821 48.042 11.939 ;
     RECT  46.692 11.939 47.394 11.975 ;
     RECT  85.5 11.911 85.518 12.461 ;
     RECT  45.615 11.741 45.897 12.865 ;
     RECT  46.692 11.975 46.71 13.019 ;
     RECT  45.576 12.865 45.897 13.051 ;
     RECT  45.432 13.051 45.897 13.091 ;
     RECT  45.615 13.091 45.897 13.099 ;
     RECT  29.415 3.197 29.697 13.261 ;
     RECT  40.215 6.305 40.497 13.297 ;
     RECT  42.192 11.947 42.21 13.297 ;
     RECT  45.615 13.099 46.314 13.361 ;
     RECT  29.415 13.261 29.826 13.405 ;
     RECT  13.215 2.413 13.497 13.432 ;
     RECT  24.015 2.413 24.297 13.432 ;
     RECT  29.415 13.405 30.762 13.435 ;
     RECT  2.415 11.399 2.697 13.441 ;
     RECT  29.304 13.435 30.762 13.441 ;
     RECT  13.104 13.432 13.497 13.469 ;
     RECT  23.904 13.432 24.297 13.469 ;
     RECT  2.304 13.441 2.697 13.517 ;
     RECT  29.304 13.441 31.266 13.559 ;
     RECT  41.688 13.297 42.21 13.595 ;
     RECT  29.304 13.559 30.006 13.631 ;
     RECT  40.215 13.297 40.77 13.661 ;
     RECT  41.796 13.595 42.21 13.667 ;
     RECT  30.744 13.559 30.762 13.703 ;
     RECT  38.88 13.639 38.898 13.829 ;
     RECT  46.656 13.801 46.674 13.909 ;
     RECT  45.615 13.361 45.897 14.179 ;
     RECT  46.656 13.909 46.998 14.179 ;
     RECT  45.615 14.179 46.998 14.203 ;
     RECT  45.612 14.203 46.998 14.243 ;
     RECT  45.615 14.243 46.998 14.369 ;
     RECT  45.615 14.369 46.962 14.639 ;
     RECT  42.192 13.667 42.21 15.421 ;
     RECT  42.192 15.421 42.354 15.449 ;
     RECT  42.336 15.449 42.354 15.533 ;
     RECT  13.215 13.469 13.497 15.592 ;
     RECT  24.015 13.469 24.297 15.592 ;
     RECT  34.815 4.955 35.097 15.592 ;
     RECT  2.415 13.517 2.697 15.601 ;
     RECT  13.104 15.592 13.497 15.629 ;
     RECT  23.904 15.592 24.297 15.629 ;
     RECT  34.704 15.592 35.097 15.629 ;
     RECT  38.772 15.499 38.79 15.629 ;
     RECT  2.304 15.601 2.697 15.677 ;
     RECT  45.615 14.639 45.897 16.651 ;
     RECT  45.576 16.651 45.897 16.795 ;
     RECT  44.892 16.795 45.897 16.835 ;
     RECT  45.576 16.835 45.897 17.249 ;
     RECT  83.415 10.319 83.697 17.311 ;
     RECT  7.815 9.545 8.097 17.419 ;
     RECT  83.415 17.311 84.402 17.453 ;
     RECT  40.215 13.661 40.497 17.455 ;
     RECT  40.212 17.455 40.497 17.491 ;
     RECT  41.508 17.323 41.526 17.491 ;
     RECT  40.212 17.491 41.67 17.609 ;
     RECT  49.428 17.653 49.446 17.693 ;
     RECT  2.415 15.677 2.697 17.752 ;
     RECT  56.415 2.413 56.697 17.752 ;
     RECT  67.215 2.413 67.497 17.752 ;
     RECT  78.015 2.413 78.297 17.752 ;
     RECT  7.815 17.419 8.154 17.755 ;
     RECT  2.304 17.752 2.697 17.789 ;
     RECT  56.304 17.752 56.697 17.789 ;
     RECT  67.104 17.752 67.497 17.789 ;
     RECT  77.904 17.752 78.297 17.789 ;
     RECT  46.944 14.639 46.962 17.851 ;
     RECT  44.136 17.761 44.154 17.879 ;
     RECT  7.704 17.755 8.154 17.915 ;
     RECT  38.772 17.851 38.79 17.951 ;
     RECT  42.768 17.887 42.786 18.031 ;
     RECT  0.108 18.031 0.126 18.077 ;
     RECT  46.728 17.851 46.962 18.149 ;
     RECT  7.815 17.915 8.154 18.185 ;
     RECT  20.484 18.121 20.502 18.301 ;
     RECT  42.732 18.031 42.786 18.301 ;
     RECT  51.015 2.413 51.297 18.301 ;
     RECT  34.815 15.629 35.097 18.391 ;
     RECT  40.215 17.609 41.67 18.391 ;
     RECT  42.552 18.301 42.786 18.391 ;
     RECT  0.144 18.379 0.162 18.419 ;
     RECT  10.224 18.301 10.242 18.419 ;
     RECT  19.944 18.301 20.502 18.455 ;
     RECT  86.292 18.379 86.31 18.455 ;
     RECT  3.96 17.995 3.978 18.461 ;
     RECT  34.776 18.391 35.097 18.491 ;
     RECT  51.015 18.301 51.606 18.491 ;
     RECT  40.068 18.391 42.786 18.571 ;
     RECT  53.136 18.427 53.154 18.599 ;
     RECT  10.476 18.571 10.494 18.689 ;
     RECT  31.068 18.571 31.086 18.689 ;
     RECT  40.068 18.571 42.858 18.689 ;
     RECT  20.556 18.571 20.574 18.697 ;
     RECT  40.068 18.689 42.714 18.725 ;
     RECT  40.215 18.725 42.714 18.797 ;
     RECT  20.556 18.697 20.754 18.869 ;
     RECT  83.415 17.453 83.697 18.931 ;
     RECT  7.815 18.185 8.097 19.003 ;
     RECT  83.415 18.931 84.402 19.037 ;
     RECT  40.215 18.797 42.462 19.103 ;
     RECT  43.74 19.195 43.758 19.201 ;
     RECT  20.556 18.869 20.574 19.229 ;
     RECT  7.815 19.003 8.154 19.339 ;
     RECT  43.488 19.201 43.758 19.381 ;
     RECT  21.672 19.381 21.69 19.471 ;
     RECT  85.5 17.851 85.518 19.471 ;
     RECT  21.456 19.471 21.69 19.499 ;
     RECT  43.488 19.381 43.902 19.499 ;
     RECT  7.416 19.339 8.154 19.535 ;
     RECT  43.488 19.499 43.506 19.535 ;
     RECT  21.456 19.499 21.474 19.571 ;
     RECT  41.256 19.103 42.462 19.651 ;
     RECT  84.924 19.471 85.518 19.661 ;
     RECT  31.644 19.651 31.662 19.741 ;
     RECT  31.464 19.741 31.662 19.769 ;
     RECT  43.38 19.651 43.47 19.769 ;
     RECT  46.728 18.149 46.746 19.769 ;
     RECT  49.392 19.651 49.842 19.769 ;
     RECT  7.704 19.535 8.154 19.805 ;
     RECT  20.916 19.741 20.934 19.841 ;
     RECT  43.452 19.769 43.47 19.841 ;
     RECT  49.824 19.769 49.842 19.841 ;
     RECT  41.256 19.651 42.606 19.885 ;
     RECT  31.464 19.769 31.482 19.913 ;
     RECT  2.415 17.789 2.697 19.963 ;
     RECT  2.304 19.963 2.697 20.039 ;
     RECT  41.22 19.885 42.606 20.039 ;
     RECT  7.704 19.805 8.097 20.075 ;
     RECT  42.264 20.039 42.282 20.075 ;
     RECT  0.108 20.251 0.126 20.309 ;
     RECT  41.22 20.039 41.526 20.309 ;
     RECT  85.464 19.661 85.518 20.309 ;
     RECT  3.96 20.281 3.978 20.333 ;
     RECT  7.815 20.075 8.097 20.587 ;
     RECT  20.376 20.281 20.394 20.695 ;
     RECT  40.215 19.103 40.497 20.695 ;
     RECT  41.22 20.309 41.382 20.695 ;
     RECT  83.415 19.037 83.697 20.821 ;
     RECT  7.815 20.587 8.154 20.923 ;
     RECT  83.415 20.821 84.402 20.957 ;
     RECT  39.348 20.965 39.366 21.119 ;
     RECT  46.944 19.885 46.962 21.199 ;
     RECT  40.215 20.695 41.382 21.235 ;
     RECT  45.615 17.249 45.897 21.235 ;
     RECT  46.62 21.199 46.962 21.235 ;
     RECT  45.615 21.235 46.962 21.389 ;
     RECT  43.38 21.271 43.398 21.461 ;
     RECT  46.62 21.389 46.962 21.469 ;
     RECT  46.62 21.469 47.142 21.497 ;
     RECT  18.615 2.413 18.897 21.541 ;
     RECT  20.052 20.695 20.394 21.541 ;
     RECT  47.124 21.497 47.142 21.541 ;
     RECT  47.124 21.541 47.25 21.569 ;
     RECT  40.104 21.235 41.382 21.631 ;
     RECT  14.832 21.541 14.85 21.659 ;
     RECT  18.615 21.541 20.502 21.659 ;
     RECT  7.416 20.923 8.154 21.695 ;
     RECT  18.615 21.659 20.07 21.695 ;
     RECT  3.96 21.499 3.978 21.839 ;
     RECT  0.108 21.541 0.126 21.869 ;
     RECT  39.6 21.631 41.382 21.929 ;
     RECT  7.704 21.695 8.154 21.965 ;
     RECT  39.924 21.929 41.382 21.965 ;
     RECT  19.836 21.695 20.07 22.001 ;
     RECT  2.415 20.039 2.697 22.171 ;
     RECT  40.104 21.965 41.382 22.171 ;
     RECT  10.26 21.271 10.278 22.199 ;
     RECT  40.104 22.171 41.598 22.199 ;
     RECT  85.5 20.309 85.518 22.205 ;
     RECT  2.304 22.171 2.697 22.208 ;
     RECT  7.704 21.965 8.097 22.235 ;
     RECT  40.215 22.199 41.598 22.235 ;
     RECT  83.415 20.957 83.697 22.441 ;
     RECT  20.052 22.001 20.07 22.477 ;
     RECT  83.415 22.441 84.402 22.541 ;
     RECT  41.364 22.235 41.598 22.585 ;
     RECT  20.052 22.477 20.322 22.739 ;
     RECT  18.615 21.695 18.897 22.783 ;
     RECT  41.364 22.585 41.85 22.783 ;
     RECT  7.815 22.235 8.097 22.795 ;
     RECT  49.428 22.783 49.446 22.829 ;
     RECT  18.615 22.783 19.422 23.009 ;
     RECT  7.815 22.795 8.154 23.045 ;
     RECT  41.364 22.783 41.994 23.161 ;
     RECT  86.292 23.131 86.31 23.315 ;
     RECT  38.772 22.711 38.79 23.323 ;
     RECT  51.015 18.491 51.297 23.419 ;
     RECT  20.484 23.251 20.502 23.431 ;
     RECT  41.364 23.161 42.462 23.431 ;
     RECT  10.476 23.431 10.494 23.549 ;
     RECT  38.772 23.323 39.366 23.549 ;
     RECT  40.215 22.235 40.497 23.557 ;
     RECT  41.22 23.431 42.462 23.557 ;
     RECT  20.484 23.431 20.574 23.585 ;
     RECT  49.644 23.323 49.662 23.597 ;
     RECT  51.015 23.419 51.39 23.597 ;
     RECT  40.215 23.557 42.462 23.701 ;
     RECT  40.215 23.701 42.498 23.741 ;
     RECT  2.415 22.208 2.697 23.755 ;
     RECT  85.5 23.521 85.518 23.788 ;
     RECT  85.5 23.788 85.554 23.789 ;
     RECT  30.96 23.701 30.978 23.791 ;
     RECT  7.815 23.045 8.097 23.803 ;
     RECT  2.304 23.755 2.697 23.819 ;
     RECT  30.744 23.791 30.978 23.819 ;
     RECT  42.48 23.741 42.498 23.819 ;
     RECT  30.744 23.819 30.762 23.891 ;
     RECT  20.484 23.585 20.538 23.971 ;
     RECT  40.215 23.741 41.742 23.999 ;
     RECT  85.536 23.789 85.554 24.077 ;
     RECT  0.108 24.043 0.126 24.089 ;
     RECT  10.26 23.971 10.278 24.089 ;
     RECT  38.772 23.549 38.79 24.089 ;
     RECT  3.96 24.061 3.978 24.125 ;
     RECT  20.052 23.971 20.538 24.125 ;
     RECT  83.415 22.541 83.697 24.331 ;
     RECT  20.52 24.125 20.538 24.359 ;
     RECT  7.704 23.803 8.097 24.379 ;
     RECT  83.415 24.331 84.402 24.413 ;
     RECT  18.615 23.009 18.897 24.475 ;
     RECT  18.615 24.475 19.422 24.629 ;
     RECT  10.548 24.781 10.566 24.899 ;
     RECT  40.215 23.999 41.634 24.899 ;
     RECT  85.5 24.601 85.518 25.037 ;
     RECT  42.552 25.045 42.57 25.051 ;
     RECT  42.552 25.051 42.714 25.085 ;
     RECT  42.696 25.085 42.714 25.169 ;
     RECT  20.556 24.781 20.574 25.177 ;
     RECT  10.584 25.141 10.602 25.241 ;
     RECT  3.96 25.291 3.978 25.349 ;
     RECT  20.556 25.177 20.862 25.349 ;
     RECT  0.108 25.321 0.126 25.373 ;
     RECT  86.292 25.339 86.31 25.439 ;
     RECT  20.376 25.411 20.394 25.511 ;
     RECT  2.415 23.819 2.697 25.579 ;
     RECT  51.015 23.597 51.297 25.579 ;
     RECT  83.415 24.413 83.697 25.591 ;
     RECT  2.415 25.579 2.79 25.619 ;
     RECT  83.415 25.591 83.79 25.661 ;
     RECT  51.015 25.579 51.966 25.709 ;
     RECT  10.152 25.681 10.17 25.781 ;
     RECT  47.232 21.569 47.25 25.816 ;
     RECT  40.215 24.899 41.238 25.861 ;
     RECT  19.98 25.717 19.998 25.889 ;
     RECT  2.415 25.619 2.697 25.951 ;
     RECT  29.415 13.631 29.697 25.951 ;
     RECT  49.104 25.861 49.122 25.979 ;
     RECT  47.232 25.816 47.286 25.987 ;
     RECT  2.304 25.951 2.697 25.997 ;
     RECT  39.744 25.861 41.31 26.015 ;
     RECT  46.764 25.987 47.286 26.087 ;
     RECT  18.615 24.629 18.897 26.095 ;
     RECT  39.924 26.015 41.31 26.131 ;
     RECT  42.912 26.095 42.93 26.131 ;
     RECT  39.924 26.131 43.074 26.141 ;
     RECT  18.615 26.095 19.422 26.249 ;
     RECT  39.924 26.141 42.21 26.249 ;
     RECT  43.056 26.141 43.074 26.249 ;
     RECT  34.815 18.491 35.097 26.257 ;
     RECT  29.415 25.951 29.754 26.285 ;
     RECT  39.924 26.249 41.634 26.285 ;
     RECT  26.784 26.221 26.802 26.357 ;
     RECT  31.212 26.221 31.23 26.357 ;
     RECT  51.015 25.709 51.297 26.401 ;
     RECT  34.74 26.257 35.097 26.429 ;
     RECT  20.448 26.365 20.466 26.671 ;
     RECT  48.456 26.401 48.474 26.761 ;
     RECT  14.832 26.671 14.85 26.789 ;
     RECT  7.416 24.379 8.097 26.825 ;
     RECT  19.908 26.671 20.466 26.825 ;
     RECT  48.456 26.761 49.158 26.861 ;
     RECT  2.415 25.997 2.697 26.923 ;
     RECT  56.415 17.789 56.697 26.923 ;
     RECT  67.215 17.789 67.497 26.923 ;
     RECT  78.015 17.789 78.297 26.923 ;
     RECT  50.688 26.401 51.297 26.941 ;
     RECT  2.304 26.923 2.697 26.969 ;
     RECT  56.304 26.923 56.697 26.969 ;
     RECT  67.104 26.923 67.497 26.969 ;
     RECT  77.904 26.923 78.297 26.969 ;
     RECT  10.548 26.941 10.566 27.059 ;
     RECT  43.632 26.941 43.65 27.059 ;
     RECT  50.184 26.941 51.297 27.059 ;
     RECT  40.215 26.285 41.634 27.067 ;
     RECT  7.704 26.825 8.097 27.095 ;
     RECT  20.556 26.941 20.574 27.095 ;
     RECT  7.815 27.095 8.097 27.163 ;
     RECT  40.215 27.067 41.742 27.175 ;
     RECT  40.215 27.175 42.318 27.211 ;
     RECT  40.215 27.211 42.498 27.239 ;
     RECT  85.5 25.861 85.518 27.245 ;
     RECT  20.88 27.211 21.078 27.329 ;
     RECT  42.192 27.239 42.498 27.329 ;
     RECT  7.815 27.163 8.154 27.365 ;
     RECT  42.192 27.329 42.462 27.365 ;
     RECT  20.88 27.329 20.898 27.473 ;
     RECT  50.688 27.059 51.297 27.485 ;
     RECT  48.456 26.861 48.474 27.509 ;
     RECT  86.292 27.451 86.31 27.581 ;
     RECT  0.108 27.211 0.126 27.599 ;
     RECT  40.215 27.239 41.346 27.599 ;
     RECT  42.372 27.365 42.462 27.599 ;
     RECT  47.268 26.087 47.286 27.599 ;
     RECT  3.96 27.163 3.978 27.629 ;
     RECT  7.815 27.365 8.097 27.883 ;
     RECT  18.615 26.249 18.897 27.913 ;
     RECT  84.924 27.841 84.942 27.917 ;
     RECT  83.415 25.661 83.697 28.111 ;
     RECT  18.615 27.913 19.422 28.139 ;
     RECT  40.215 27.599 41.31 28.139 ;
     RECT  7.416 27.883 8.097 28.171 ;
     RECT  7.416 28.171 8.154 28.175 ;
     RECT  83.415 28.111 84.402 28.205 ;
     RECT  20.88 28.255 20.898 28.409 ;
     RECT  42.048 28.147 42.282 28.409 ;
     RECT  42.048 28.409 42.138 28.445 ;
     RECT  42.12 28.445 42.138 28.553 ;
     RECT  43.596 28.453 43.614 28.561 ;
     RECT  51.015 27.485 51.297 28.561 ;
     RECT  85.464 28.381 85.518 28.651 ;
     RECT  43.596 28.561 43.722 28.679 ;
     RECT  51.015 28.561 51.39 28.679 ;
     RECT  47.376 27.715 47.394 28.687 ;
     RECT  52.848 28.651 52.866 28.687 ;
     RECT  85.464 28.651 85.554 28.715 ;
     RECT  34.815 26.429 35.097 28.795 ;
     RECT  85.5 28.715 85.554 28.829 ;
     RECT  46.728 28.687 47.394 28.859 ;
     RECT  52.848 28.687 52.938 28.859 ;
     RECT  34.776 28.795 35.097 28.949 ;
     RECT  7.815 28.175 8.154 28.985 ;
     RECT  19.836 28.921 19.854 29.021 ;
     RECT  7.815 28.985 8.097 29.083 ;
     RECT  56.415 26.969 56.697 29.083 ;
     RECT  67.215 26.969 67.497 29.083 ;
     RECT  78.015 26.969 78.297 29.083 ;
     RECT  83.415 28.205 83.697 29.083 ;
     RECT  2.415 26.969 2.697 29.101 ;
     RECT  56.304 29.083 56.697 29.129 ;
     RECT  67.104 29.083 67.497 29.129 ;
     RECT  77.904 29.083 78.297 29.129 ;
     RECT  83.304 29.083 83.697 29.129 ;
     RECT  2.304 29.101 2.697 29.165 ;
     RECT  38.772 27.337 38.79 29.219 ;
     RECT  49.032 28.381 49.05 29.219 ;
     RECT  40.215 28.139 41.274 29.255 ;
     RECT  40.215 29.255 40.497 29.371 ;
     RECT  42.084 29.335 42.102 29.371 ;
     RECT  42.084 29.371 42.282 29.405 ;
     RECT  7.704 29.083 8.097 29.467 ;
     RECT  20.304 29.371 20.322 29.489 ;
     RECT  42.264 29.405 42.282 29.489 ;
     RECT  47.376 28.859 47.394 29.489 ;
     RECT  41.328 29.461 41.346 29.561 ;
     RECT  18.615 28.139 18.897 29.605 ;
     RECT  45.615 21.389 45.897 29.605 ;
     RECT  45.615 29.605 46.422 29.641 ;
     RECT  40.212 29.371 40.497 29.731 ;
     RECT  85.5 28.829 85.518 29.731 ;
     RECT  7.416 29.467 8.097 29.755 ;
     RECT  18.615 29.605 19.422 29.759 ;
     RECT  39.816 29.731 40.497 29.831 ;
     RECT  19.944 29.875 19.962 30.029 ;
     RECT  40.032 29.831 40.497 30.065 ;
     RECT  40.215 30.065 40.497 30.145 ;
     RECT  43.092 29.995 43.11 30.181 ;
     RECT  40.215 30.145 41.058 30.283 ;
     RECT  43.056 30.181 43.254 30.299 ;
     RECT  45.615 29.641 47.25 30.307 ;
     RECT  43.056 30.299 43.074 30.335 ;
     RECT  45.615 30.307 47.466 30.335 ;
     RECT  40.215 30.283 41.31 30.343 ;
     RECT  32.148 30.271 32.166 30.371 ;
     RECT  84.924 29.731 85.518 30.413 ;
     RECT  10.908 30.307 10.926 30.479 ;
     RECT  46.692 30.335 47.466 30.569 ;
     RECT  47.232 30.569 47.466 30.641 ;
     RECT  42.768 30.451 42.786 30.677 ;
     RECT  49.932 30.451 49.95 30.677 ;
     RECT  2.415 29.165 2.697 30.712 ;
     RECT  40.215 30.343 41.382 30.721 ;
     RECT  2.304 30.712 2.697 30.749 ;
     RECT  20.376 30.541 20.394 30.811 ;
     RECT  47.232 30.641 47.43 30.839 ;
     RECT  7.416 29.755 8.154 30.875 ;
     RECT  20.376 30.811 20.754 30.911 ;
     RECT  40.215 30.721 41.634 30.955 ;
     RECT  20.376 30.911 20.574 30.983 ;
     RECT  47.412 30.839 47.43 30.983 ;
     RECT  85.5 30.413 85.518 31.037 ;
     RECT  7.815 30.875 8.154 31.145 ;
     RECT  39.492 30.955 41.634 31.145 ;
     RECT  40.215 31.145 41.634 31.225 ;
     RECT  19.8 31.081 19.998 31.253 ;
     RECT  40.215 31.225 41.67 31.261 ;
     RECT  19.98 31.253 19.998 31.289 ;
     RECT  0.108 30.991 0.126 31.379 ;
     RECT  40.215 31.261 41.958 31.379 ;
     RECT  86.292 31.339 86.31 31.379 ;
     RECT  3.96 30.955 3.978 31.421 ;
     RECT  10.584 31.351 10.602 31.451 ;
     RECT  7.815 31.145 8.097 31.675 ;
     RECT  84.924 31.621 84.942 31.709 ;
     RECT  40.215 31.379 41.778 31.891 ;
     RECT  51.015 28.679 51.297 31.891 ;
     RECT  20.484 31.765 20.502 31.919 ;
     RECT  7.416 31.675 8.097 31.955 ;
     RECT  7.815 31.955 8.097 31.963 ;
     RECT  50.688 31.891 51.297 31.997 ;
     RECT  39.924 31.891 41.778 32.161 ;
     RECT  39.924 32.161 42.03 32.341 ;
     RECT  42.768 31.915 42.786 32.341 ;
     RECT  39.924 32.341 42.786 32.459 ;
     RECT  20.448 32.035 20.466 32.603 ;
     RECT  49.32 32.467 49.338 32.621 ;
     RECT  39.924 32.459 40.497 32.729 ;
     RECT  20.556 32.701 20.574 32.737 ;
     RECT  7.815 31.963 8.154 32.765 ;
     RECT  7.815 32.765 8.097 32.875 ;
     RECT  2.415 30.749 2.697 32.881 ;
     RECT  2.304 32.881 2.697 32.957 ;
     RECT  10.548 32.881 10.566 32.999 ;
     RECT  41.22 32.459 42.102 32.999 ;
     RECT  42.912 32.611 42.93 32.999 ;
     RECT  41.328 32.999 42.102 33.035 ;
     RECT  42.984 33.151 43.002 33.269 ;
     RECT  50.184 33.151 50.202 33.269 ;
     RECT  20.556 32.737 20.754 33.385 ;
     RECT  40.215 32.729 40.497 33.385 ;
     RECT  20.232 33.385 20.754 33.421 ;
     RECT  20.232 33.421 20.862 33.539 ;
     RECT  7.704 32.875 8.097 33.547 ;
     RECT  18.615 29.759 18.897 33.583 ;
     RECT  18.615 33.583 19.422 33.809 ;
     RECT  40.215 33.385 40.59 33.889 ;
     RECT  41.328 33.035 41.886 33.889 ;
     RECT  20.232 33.539 20.61 34.079 ;
     RECT  40.215 33.889 41.886 34.079 ;
     RECT  20.232 34.079 20.574 34.231 ;
     RECT  10.26 34.231 10.278 34.349 ;
     RECT  38.772 34.087 38.79 34.349 ;
     RECT  7.416 33.547 8.097 34.385 ;
     RECT  20.016 34.231 20.574 34.385 ;
     RECT  85.5 32.161 85.518 34.541 ;
     RECT  40.215 34.079 41.742 34.799 ;
     RECT  83.415 29.129 83.697 34.861 ;
     RECT  0.108 34.501 0.126 34.889 ;
     RECT  10.476 34.771 10.494 34.889 ;
     RECT  39.348 34.735 39.366 34.889 ;
     RECT  42.732 34.501 42.75 34.889 ;
     RECT  86.292 34.843 86.31 34.889 ;
     RECT  3.96 34.459 3.978 34.925 ;
     RECT  49.428 34.735 49.446 34.925 ;
     RECT  83.415 34.861 83.826 34.925 ;
     RECT  2.415 32.957 2.697 35.131 ;
     RECT  7.815 34.385 8.097 35.131 ;
     RECT  20.52 34.385 20.574 35.159 ;
     RECT  84.924 35.125 84.942 35.165 ;
     RECT  2.304 35.131 2.697 35.168 ;
     RECT  18.615 33.809 18.897 35.275 ;
     RECT  40.215 34.799 41.67 35.581 ;
     RECT  20.592 35.509 20.61 35.609 ;
     RECT  10.548 35.581 10.566 35.699 ;
     RECT  43.272 35.581 43.29 35.699 ;
     RECT  48.024 35.581 48.042 35.699 ;
     RECT  40.215 35.581 41.742 35.851 ;
     RECT  18.615 35.275 19.422 35.969 ;
     RECT  40.215 35.851 41.85 35.969 ;
     RECT  40.215 35.969 41.562 36.085 ;
     RECT  83.415 34.925 83.697 36.211 ;
     RECT  10.26 36.121 10.278 36.239 ;
     RECT  40.032 36.085 41.562 36.239 ;
     RECT  20.052 36.121 20.07 36.275 ;
     RECT  40.176 36.239 41.562 36.275 ;
     RECT  2.415 35.168 2.697 36.379 ;
     RECT  2.415 36.379 2.79 36.419 ;
     RECT  83.415 36.211 84.402 36.461 ;
     RECT  7.416 35.131 8.097 36.545 ;
     RECT  2.415 36.419 2.697 36.715 ;
     RECT  85.5 35.401 85.518 36.749 ;
     RECT  2.304 36.715 2.697 36.779 ;
     RECT  7.704 36.545 8.097 36.815 ;
     RECT  20.484 36.751 20.502 36.851 ;
     RECT  18.615 35.969 18.897 36.931 ;
     RECT  40.215 36.275 41.562 36.931 ;
     RECT  14.832 36.931 14.85 37.049 ;
     RECT  40.215 36.931 42.066 37.049 ;
     RECT  18.615 36.931 19.422 37.085 ;
     RECT  48.996 36.931 49.014 37.085 ;
     RECT  83.415 36.461 83.697 37.291 ;
     RECT  7.815 36.815 8.097 37.339 ;
     RECT  83.415 37.291 83.826 37.373 ;
     RECT  20.304 37.327 20.322 37.435 ;
     RECT  20.124 37.435 20.322 37.831 ;
     RECT  85.5 37.561 85.518 37.831 ;
     RECT  38.772 37.867 38.79 37.939 ;
     RECT  84.924 37.831 85.518 37.997 ;
     RECT  38.772 37.939 38.826 38.003 ;
     RECT  10.26 38.011 10.278 38.129 ;
     RECT  38.808 38.003 38.826 38.137 ;
     RECT  7.815 37.339 8.154 38.165 ;
     RECT  38.808 38.137 38.898 38.201 ;
     RECT  38.88 38.201 38.898 38.309 ;
     RECT  20.124 37.831 20.394 38.371 ;
     RECT  34.815 28.949 35.097 38.371 ;
     RECT  34.815 38.371 35.37 38.429 ;
     RECT  19.944 38.371 20.394 38.471 ;
     RECT  0.144 38.281 0.162 38.669 ;
     RECT  86.292 38.632 86.31 38.669 ;
     RECT  3.96 38.251 3.978 38.717 ;
     RECT  36.9 38.551 36.918 38.717 ;
     RECT  20.376 38.471 20.394 38.741 ;
     RECT  36.756 38.779 36.774 38.819 ;
     RECT  2.415 36.779 2.697 38.911 ;
     RECT  2.304 38.911 2.697 38.957 ;
     RECT  7.815 38.165 8.097 39.019 ;
     RECT  18.615 37.085 18.897 39.019 ;
     RECT  6.84 38.923 6.858 39.053 ;
     RECT  20.484 39.091 20.502 39.209 ;
     RECT  38.772 39.091 38.79 39.245 ;
     RECT  7.815 39.019 8.154 39.259 ;
     RECT  18.615 39.019 18.954 39.289 ;
     RECT  85.5 37.997 85.518 39.451 ;
     RECT  18.615 39.289 19.422 39.479 ;
     RECT  7.416 39.259 8.154 39.515 ;
     RECT  84.924 39.451 85.518 39.581 ;
     RECT  42.444 39.361 42.462 39.749 ;
     RECT  7.815 39.515 8.154 39.785 ;
     RECT  40.215 37.049 41.526 39.829 ;
     RECT  2.415 38.957 2.697 39.883 ;
     RECT  13.215 15.629 13.497 39.883 ;
     RECT  56.415 29.129 56.697 39.883 ;
     RECT  61.815 2.413 62.097 39.883 ;
     RECT  78.015 29.129 78.297 39.883 ;
     RECT  20.448 39.721 20.466 39.893 ;
     RECT  43.344 39.865 43.614 39.901 ;
     RECT  13.104 39.883 13.497 39.929 ;
     RECT  46.692 39.883 46.782 39.929 ;
     RECT  56.304 39.883 56.697 39.929 ;
     RECT  77.904 39.883 78.678 39.929 ;
     RECT  40.215 39.829 42.174 39.979 ;
     RECT  21.6 39.901 21.618 40.019 ;
     RECT  40.104 39.979 42.174 40.019 ;
     RECT  43.344 39.901 43.794 40.019 ;
     RECT  2.415 39.883 2.862 40.061 ;
     RECT  14.832 39.883 14.85 40.061 ;
     RECT  46.764 39.929 46.782 40.061 ;
     RECT  61.815 39.883 62.73 40.061 ;
     RECT  78.015 39.929 78.678 40.061 ;
     RECT  42.156 40.019 42.174 40.091 ;
     RECT  40.104 40.019 41.31 40.135 ;
     RECT  43.344 40.019 43.398 40.171 ;
     RECT  10.224 40.171 10.242 40.289 ;
     RECT  39.888 40.135 41.31 40.289 ;
     RECT  2.415 40.061 2.79 40.301 ;
     RECT  19.944 40.171 19.962 40.325 ;
     RECT  40.068 40.289 41.31 40.325 ;
     RECT  46.8 40.171 46.818 40.325 ;
     RECT  43.272 40.171 43.398 40.397 ;
     RECT  40.104 40.325 41.31 40.469 ;
     RECT  83.415 37.373 83.697 40.531 ;
     RECT  0.108 39.883 0.126 40.559 ;
     RECT  86.292 39.883 86.31 40.559 ;
     RECT  3.96 40.531 3.978 40.589 ;
     RECT  49.428 40.441 49.446 40.589 ;
     RECT  83.415 40.531 83.826 40.589 ;
     RECT  10.368 40.567 10.386 40.739 ;
     RECT  20.484 40.711 20.502 40.829 ;
     RECT  42.48 40.711 42.786 40.829 ;
     RECT  49.752 40.711 49.77 40.829 ;
     RECT  7.815 39.785 8.097 40.843 ;
     RECT  40.215 40.469 41.31 40.909 ;
     RECT  18.615 39.479 18.897 40.945 ;
     RECT  18.615 40.945 19.422 41.099 ;
     RECT  40.215 40.909 41.346 41.099 ;
     RECT  42.48 40.829 42.498 41.099 ;
     RECT  7.416 40.843 8.097 41.131 ;
     RECT  85.5 39.581 85.518 41.165 ;
     RECT  20.304 41.107 20.322 41.215 ;
     RECT  20.124 41.215 20.322 41.279 ;
     RECT  20.124 41.279 20.142 41.369 ;
     RECT  84.924 41.341 84.942 41.501 ;
     RECT  83.415 40.589 83.697 41.611 ;
     RECT  3.96 41.755 3.978 41.819 ;
     RECT  10.368 41.647 10.386 41.819 ;
     RECT  0.108 41.791 0.126 41.837 ;
     RECT  83.415 41.611 84.402 41.837 ;
     RECT  40.215 41.099 41.13 41.881 ;
     RECT  7.416 41.131 8.154 41.945 ;
     RECT  51.015 31.997 51.297 41.989 ;
     RECT  2.415 40.301 2.697 42.061 ;
     RECT  18.615 41.099 18.897 42.061 ;
     RECT  2.304 42.061 2.697 42.125 ;
     RECT  83.415 41.837 83.826 42.125 ;
     RECT  40.215 41.881 41.31 42.151 ;
     RECT  42.516 42.025 42.534 42.151 ;
     RECT  14.832 42.061 14.85 42.179 ;
     RECT  42.516 42.151 42.786 42.179 ;
     RECT  43.812 42.061 43.83 42.179 ;
     RECT  49.392 42.061 49.41 42.179 ;
     RECT  50.94 41.989 51.297 42.179 ;
     RECT  52.56 42.061 52.578 42.179 ;
     RECT  54.684 41.989 54.702 42.179 ;
     RECT  39.924 42.151 41.562 42.251 ;
     RECT  42.768 42.179 42.786 42.449 ;
     RECT  20.34 42.457 20.358 42.629 ;
     RECT  10.44 42.601 10.458 42.719 ;
     RECT  18.615 42.061 19.422 42.989 ;
     RECT  7.416 41.945 8.097 43.025 ;
     RECT  7.704 43.025 8.097 43.387 ;
     RECT  48.492 43.387 48.51 43.439 ;
     RECT  7.704 43.387 8.154 43.565 ;
     RECT  40.215 42.251 41.562 43.609 ;
     RECT  2.415 42.125 2.697 43.672 ;
     RECT  40.215 43.609 41.67 43.681 ;
     RECT  42.408 43.531 42.426 43.681 ;
     RECT  2.304 43.672 2.697 43.709 ;
     RECT  10.368 43.267 10.386 43.709 ;
     RECT  85.5 42.151 85.518 43.771 ;
     RECT  21.06 43.681 21.078 43.799 ;
     RECT  40.215 43.681 42.606 43.799 ;
     RECT  7.704 43.565 8.097 43.835 ;
     RECT  40.215 43.799 41.886 43.835 ;
     RECT  84.924 43.771 85.518 44.045 ;
     RECT  10.26 43.951 10.278 44.069 ;
     RECT  38.772 43.843 38.79 44.069 ;
     RECT  0.108 44.011 0.126 44.339 ;
     RECT  40.215 43.835 41.238 44.339 ;
     RECT  3.96 44.041 3.978 44.381 ;
     RECT  20.052 43.951 20.07 44.617 ;
     RECT  20.052 44.617 20.214 44.725 ;
     RECT  20.016 44.725 20.214 44.789 ;
     RECT  85.5 44.045 85.518 44.851 ;
     RECT  20.016 44.789 20.034 44.879 ;
     RECT  7.815 43.835 8.097 44.971 ;
     RECT  7.416 44.971 8.097 45.185 ;
     RECT  40.215 44.339 41.094 45.301 ;
     RECT  38.772 44.995 38.79 45.419 ;
     RECT  84.924 44.851 85.518 45.629 ;
     RECT  42.012 45.643 42.03 45.689 ;
     RECT  0.108 45.595 0.126 45.725 ;
     RECT  40.215 45.301 41.238 45.805 ;
     RECT  2.415 43.709 2.697 45.841 ;
     RECT  2.304 45.841 2.697 45.917 ;
     RECT  20.268 45.661 20.286 45.931 ;
     RECT  39.672 45.805 41.238 45.959 ;
     RECT  42.156 45.841 42.174 45.959 ;
     RECT  19.836 45.931 20.286 46.031 ;
     RECT  39.78 45.959 41.238 46.139 ;
     RECT  39.78 46.139 40.806 46.373 ;
     RECT  85.5 45.629 85.518 46.471 ;
     RECT  20.268 46.031 20.286 46.499 ;
     RECT  7.704 45.185 8.097 46.507 ;
     RECT  40.104 46.373 40.806 46.535 ;
     RECT  84.924 46.471 85.518 46.541 ;
     RECT  18.615 42.989 18.897 46.615 ;
     RECT  40.215 46.535 40.806 46.921 ;
     RECT  40.215 46.921 40.986 47.155 ;
     RECT  18.615 46.615 18.954 47.191 ;
     RECT  40.215 47.155 41.526 47.191 ;
     RECT  14.832 46.345 14.85 47.309 ;
     RECT  7.416 46.507 8.097 47.345 ;
     RECT  18.615 47.191 19.422 47.345 ;
     RECT  40.215 47.191 41.67 47.461 ;
     RECT  85.5 46.541 85.518 47.467 ;
     RECT  40.215 47.461 42.57 47.551 ;
     RECT  51.015 42.179 51.297 47.551 ;
     RECT  39.78 47.551 42.57 47.579 ;
     RECT  49.392 47.461 49.41 47.579 ;
     RECT  84.888 47.467 85.518 47.615 ;
     RECT  39.78 47.579 42.174 47.651 ;
     RECT  50.688 47.551 51.297 47.651 ;
     RECT  19.908 47.551 19.926 47.723 ;
     RECT  39.78 47.651 41.598 47.723 ;
     RECT  43.704 47.563 43.722 47.731 ;
     RECT  0.108 47.461 0.126 47.849 ;
     RECT  21.708 47.731 21.726 47.849 ;
     RECT  3.96 47.419 3.978 47.885 ;
     RECT  39.888 47.723 41.598 47.885 ;
     RECT  49.752 47.857 49.77 47.981 ;
     RECT  2.415 45.917 2.697 48.091 ;
     RECT  7.815 47.345 8.097 48.091 ;
     RECT  56.415 39.929 56.697 48.091 ;
     RECT  67.215 29.129 67.497 48.091 ;
     RECT  78.015 40.061 78.297 48.091 ;
     RECT  39.924 47.885 41.598 48.119 ;
     RECT  2.304 48.091 2.697 48.128 ;
     RECT  56.304 48.091 56.697 48.128 ;
     RECT  67.104 48.091 67.497 48.128 ;
     RECT  77.904 48.091 78.297 48.128 ;
     RECT  7.704 48.091 8.097 48.155 ;
     RECT  39.924 48.119 40.914 48.155 ;
     RECT  19.836 48.091 19.854 48.191 ;
     RECT  43.38 47.731 43.722 48.271 ;
     RECT  43.344 48.271 43.722 48.361 ;
     RECT  21.888 48.271 21.906 48.389 ;
     RECT  43.344 48.361 43.902 48.425 ;
     RECT  43.524 48.425 43.902 48.541 ;
     RECT  83.415 42.125 83.697 48.631 ;
     RECT  42.768 48.541 42.786 48.659 ;
     RECT  43.524 48.541 44.01 48.659 ;
     RECT  43.524 48.659 43.542 48.695 ;
     RECT  7.815 48.155 8.097 48.763 ;
     RECT  83.415 48.631 84.402 48.797 ;
     RECT  40.215 48.155 40.914 48.901 ;
     RECT  38.772 46.885 38.79 48.929 ;
     RECT  7.815 48.763 8.154 48.965 ;
     RECT  51.015 47.651 51.297 49.051 ;
     RECT  51.015 49.051 51.858 49.109 ;
     RECT  2.415 48.128 2.697 49.339 ;
     RECT  40.215 48.901 41.094 49.351 ;
     RECT  2.415 49.339 2.79 49.379 ;
     RECT  10.368 48.937 10.386 49.379 ;
     RECT  40.215 49.351 41.31 49.469 ;
     RECT  18.615 47.345 18.897 49.621 ;
     RECT  2.415 49.379 2.697 49.675 ;
     RECT  85.5 47.615 85.518 49.675 ;
     RECT  7.815 48.965 8.097 49.723 ;
     RECT  2.304 49.675 2.697 49.739 ;
     RECT  10.008 49.621 10.026 49.739 ;
     RECT  84.888 49.675 85.518 49.739 ;
     RECT  40.215 49.469 41.13 49.891 ;
     RECT  20.52 49.891 20.538 50.009 ;
     RECT  39.204 49.891 41.13 50.009 ;
     RECT  7.704 49.723 8.097 50.011 ;
     RECT  39.204 50.009 41.094 50.045 ;
     RECT  37.044 49.045 37.062 50.153 ;
     RECT  51.015 49.109 51.297 50.161 ;
     RECT  18.615 49.621 19.53 50.279 ;
     RECT  42.3 50.161 42.318 50.279 ;
     RECT  50.292 50.161 51.297 50.279 ;
     RECT  7.416 50.011 8.097 50.347 ;
     RECT  39.708 50.045 41.094 50.459 ;
     RECT  19.728 50.431 20.106 50.549 ;
     RECT  39.924 50.459 41.094 50.585 ;
     RECT  38.772 50.665 38.79 50.819 ;
     RECT  19.728 50.549 20.07 50.891 ;
     RECT  0.18 50.923 0.198 50.971 ;
     RECT  85.5 49.739 85.518 51.005 ;
     RECT  10.26 50.971 10.278 51.089 ;
     RECT  7.416 50.347 8.154 51.125 ;
     RECT  19.98 50.891 20.07 51.125 ;
     RECT  51.015 50.279 51.297 51.211 ;
     RECT  83.415 48.797 83.697 51.211 ;
     RECT  83.415 51.211 83.826 51.269 ;
     RECT  51.015 51.211 51.642 51.359 ;
     RECT  0.108 50.971 0.198 51.389 ;
     RECT  7.416 51.125 8.097 51.395 ;
     RECT  18.615 50.279 18.897 51.511 ;
     RECT  40.032 50.585 40.806 51.511 ;
     RECT  19.98 51.125 19.998 51.539 ;
     RECT  40.032 51.511 41.094 51.601 ;
     RECT  0.108 51.389 0.126 51.629 ;
     RECT  10.224 51.511 10.242 51.629 ;
     RECT  39.888 51.601 41.094 51.629 ;
     RECT  86.292 51.241 86.31 51.629 ;
     RECT  18.615 51.511 18.954 51.665 ;
     RECT  3.96 51.601 3.978 51.677 ;
     RECT  39.888 51.629 40.914 51.773 ;
     RECT  7.815 51.395 8.097 51.931 ;
     RECT  40.215 51.773 40.914 52.169 ;
     RECT  85.5 51.871 85.518 52.253 ;
     RECT  37.044 52.141 37.062 52.313 ;
     RECT  43.56 52.285 43.578 52.321 ;
     RECT  43.272 52.321 43.722 52.405 ;
     RECT  43.2 52.405 43.722 52.411 ;
     RECT  43.2 52.411 43.794 52.445 ;
     RECT  43.272 52.445 43.794 52.448 ;
     RECT  43.272 52.448 43.29 52.475 ;
     RECT  40.215 52.169 40.77 52.555 ;
     RECT  84.924 52.411 84.942 52.589 ;
     RECT  20.052 52.015 20.07 52.681 ;
     RECT  7.815 51.931 8.154 52.745 ;
     RECT  2.415 49.739 2.697 52.843 ;
     RECT  7.815 52.745 8.097 52.843 ;
     RECT  19.908 52.681 20.07 52.861 ;
     RECT  2.304 52.843 2.697 52.889 ;
     RECT  19.908 52.861 20.286 52.979 ;
     RECT  39.708 52.555 40.77 52.987 ;
     RECT  83.415 51.269 83.697 52.987 ;
     RECT  7.704 52.843 8.097 53.015 ;
     RECT  19.908 52.979 20.07 53.051 ;
     RECT  51.015 51.359 51.297 53.083 ;
     RECT  51.015 53.083 51.75 53.131 ;
     RECT  50.472 53.131 52.038 53.159 ;
     RECT  83.196 52.987 83.697 53.159 ;
     RECT  86.292 52.843 86.31 53.213 ;
     RECT  2.415 52.889 2.697 53.221 ;
     RECT  52.02 53.159 52.038 53.221 ;
     RECT  38.196 52.987 38.214 53.249 ;
     RECT  41.616 52.861 41.634 53.249 ;
     RECT  42.444 53.131 42.462 53.249 ;
     RECT  50.472 53.159 51.297 53.249 ;
     RECT  52.02 53.221 52.11 53.249 ;
     RECT  2.415 53.221 2.79 53.261 ;
     RECT  39.708 52.987 40.842 53.365 ;
     RECT  52.092 53.249 52.11 53.429 ;
     RECT  85.5 53.221 85.518 53.501 ;
     RECT  0.108 53.467 0.126 53.519 ;
     RECT  10.116 53.131 10.134 53.519 ;
     RECT  39.492 53.365 40.842 53.519 ;
     RECT  3.96 53.491 3.978 53.549 ;
     RECT  19.8 53.131 19.818 53.555 ;
     RECT  39.708 53.519 40.842 53.555 ;
     RECT  40.215 53.555 40.842 53.671 ;
     RECT  20.052 53.905 20.358 54.059 ;
     RECT  7.815 53.015 8.097 54.139 ;
     RECT  84.924 53.761 84.942 54.173 ;
     RECT  10.26 54.211 10.278 54.329 ;
     RECT  38.772 54.067 38.79 54.329 ;
     RECT  40.215 53.671 41.094 54.445 ;
     RECT  85.5 54.301 85.518 54.461 ;
     RECT  40.104 54.445 41.094 54.481 ;
     RECT  10.224 54.481 10.242 54.599 ;
     RECT  40.104 54.481 41.202 54.599 ;
     RECT  3.96 54.715 3.978 54.779 ;
     RECT  0.144 54.751 0.162 54.797 ;
     RECT  20.052 54.059 20.07 54.841 ;
     RECT  42.444 54.751 42.462 54.869 ;
     RECT  48.564 54.751 48.582 54.869 ;
     RECT  86.292 54.763 86.31 54.869 ;
     RECT  7.815 54.139 8.154 54.905 ;
     RECT  19.728 54.841 20.07 54.941 ;
     RECT  7.815 54.905 8.097 55.003 ;
     RECT  2.415 53.261 2.697 55.021 ;
     RECT  40.104 54.599 41.094 55.021 ;
     RECT  2.304 55.021 2.697 55.085 ;
     RECT  39.6 55.021 41.094 55.111 ;
     RECT  84.888 55.051 84.906 55.139 ;
     RECT  7.704 55.003 8.097 55.175 ;
     RECT  39.348 55.111 41.094 55.175 ;
     RECT  10.368 55.147 10.386 55.319 ;
     RECT  20.124 55.291 20.322 55.409 ;
     RECT  39.348 55.175 39.366 55.553 ;
     RECT  20.124 55.409 20.142 55.589 ;
     RECT  41.904 55.687 41.922 55.831 ;
     RECT  20.088 55.687 20.106 55.859 ;
     RECT  40.14 55.175 41.094 56.065 ;
     RECT  10.26 55.561 10.278 56.219 ;
     RECT  39.996 56.065 41.094 56.219 ;
     RECT  20.016 56.101 20.034 56.255 ;
     RECT  40.176 56.219 41.094 56.255 ;
     RECT  40.215 56.255 41.094 56.335 ;
     RECT  41.904 55.831 42.21 56.335 ;
     RECT  18.615 51.665 18.897 56.347 ;
     RECT  43.2 55.867 43.218 56.371 ;
     RECT  40.215 56.335 42.21 56.597 ;
     RECT  2.415 55.085 2.697 56.632 ;
     RECT  13.215 39.929 13.497 56.632 ;
     RECT  2.304 56.632 2.697 56.669 ;
     RECT  13.104 56.632 13.497 56.669 ;
     RECT  40.215 56.597 41.562 56.759 ;
     RECT  43.056 56.371 43.254 56.911 ;
     RECT  0.108 56.875 0.126 57.005 ;
     RECT  42.624 56.911 43.362 57.029 ;
     RECT  18.252 56.347 18.897 57.065 ;
     RECT  42.624 57.029 42.642 57.065 ;
     RECT  40.215 56.759 40.986 57.299 ;
     RECT  7.815 55.175 8.097 57.307 ;
     RECT  20.268 57.379 20.286 57.479 ;
     RECT  51.015 53.249 51.297 57.541 ;
     RECT  10.368 57.451 10.386 57.569 ;
     RECT  7.416 57.307 8.097 57.605 ;
     RECT  50.4 57.541 51.297 57.629 ;
     RECT  39.168 57.541 39.186 57.713 ;
     RECT  7.815 57.605 8.097 57.931 ;
     RECT  85.5 55.381 85.518 57.965 ;
     RECT  40.215 57.299 40.878 57.991 ;
     RECT  40.068 57.991 40.878 58.081 ;
     RECT  19.8 57.685 20.178 58.109 ;
     RECT  10.224 57.991 10.242 58.261 ;
     RECT  10.152 58.261 10.242 58.379 ;
     RECT  38.196 58.117 38.214 58.379 ;
     RECT  19.8 58.109 20.07 58.415 ;
     RECT  39.924 58.081 40.878 58.451 ;
     RECT  34.815 38.429 35.097 58.495 ;
     RECT  40.104 58.451 40.878 58.531 ;
     RECT  51.015 57.629 51.297 58.531 ;
     RECT  3.96 58.507 3.978 58.559 ;
     RECT  0.108 58.531 0.126 58.589 ;
     RECT  10.224 58.379 10.242 58.649 ;
     RECT  34.776 58.495 35.097 58.649 ;
     RECT  43.236 58.531 43.326 58.649 ;
     RECT  86.292 58.555 86.31 58.649 ;
     RECT  7.815 57.931 8.154 58.685 ;
     RECT  40.104 58.531 40.914 58.685 ;
     RECT  50.472 58.531 51.297 58.693 ;
     RECT  50.4 58.693 51.297 58.781 ;
     RECT  40.215 58.685 40.914 58.801 ;
     RECT  2.415 56.669 2.697 58.891 ;
     RECT  7.815 58.685 8.097 58.891 ;
     RECT  56.415 48.128 56.697 58.891 ;
     RECT  67.215 48.128 67.497 58.891 ;
     RECT  78.015 48.128 78.297 58.891 ;
     RECT  10.26 58.801 10.278 58.919 ;
     RECT  40.215 58.801 41.418 58.919 ;
     RECT  2.304 58.891 2.697 58.928 ;
     RECT  56.304 58.891 56.697 58.928 ;
     RECT  67.104 58.891 67.497 58.928 ;
     RECT  77.904 58.891 78.297 58.928 ;
     RECT  19.944 58.415 20.07 58.955 ;
     RECT  7.704 58.891 8.097 59.179 ;
     RECT  20.376 59.071 20.502 59.189 ;
     RECT  84.924 59.161 84.942 59.213 ;
     RECT  18.615 57.065 18.897 59.233 ;
     RECT  18.615 59.233 19.422 59.459 ;
     RECT  42.624 59.341 42.642 59.459 ;
     RECT  48.456 59.341 48.474 59.459 ;
     RECT  7.416 59.179 8.097 59.515 ;
     RECT  83.415 53.159 83.697 59.701 ;
     RECT  7.416 59.515 8.154 59.765 ;
     RECT  83.415 59.701 84.402 59.837 ;
     RECT  20.376 59.189 20.394 59.881 ;
     RECT  10.26 59.881 10.278 59.999 ;
     RECT  7.416 59.765 8.097 60.035 ;
     RECT  20.052 59.881 20.394 60.035 ;
     RECT  40.215 58.919 41.238 60.115 ;
     RECT  42.228 60.139 42.39 60.179 ;
     RECT  40.104 60.115 41.238 60.269 ;
     RECT  42.372 60.179 42.39 60.269 ;
     RECT  51.015 58.781 51.297 60.421 ;
     RECT  2.415 58.928 2.697 60.427 ;
     RECT  13.215 56.669 13.497 60.511 ;
     RECT  56.415 58.928 56.697 60.511 ;
     RECT  61.815 40.061 62.097 60.511 ;
     RECT  67.215 58.928 67.497 60.511 ;
     RECT  78.015 58.928 78.297 60.511 ;
     RECT  83.415 59.837 83.697 60.511 ;
     RECT  18.615 59.459 18.897 60.523 ;
     RECT  2.304 60.427 2.697 60.539 ;
     RECT  20.304 60.035 20.394 60.539 ;
     RECT  40.212 60.269 41.238 60.547 ;
     RECT  13.104 60.511 13.497 60.557 ;
     RECT  51.015 60.421 51.318 60.557 ;
     RECT  56.304 60.511 56.697 60.557 ;
     RECT  67.104 60.511 67.497 60.557 ;
     RECT  77.904 60.511 78.297 60.557 ;
     RECT  82.656 60.511 83.697 60.557 ;
     RECT  18.504 60.523 18.897 60.575 ;
     RECT  38.772 58.693 38.79 60.575 ;
     RECT  54.72 60.511 54.738 60.611 ;
     RECT  61.815 60.511 62.73 60.611 ;
     RECT  74.664 60.511 74.682 60.611 ;
     RECT  82.656 60.557 82.674 60.611 ;
     RECT  42.768 60.421 42.786 60.691 ;
     RECT  0.108 60.763 0.126 60.809 ;
     RECT  20.304 60.539 20.322 60.809 ;
     RECT  42.768 60.691 43.038 60.809 ;
     RECT  3.96 60.781 3.978 60.845 ;
     RECT  83.415 60.557 83.697 61.051 ;
     RECT  7.815 60.035 8.097 61.099 ;
     RECT  83.415 61.051 84.402 61.133 ;
     RECT  20.268 61.159 20.286 61.259 ;
     RECT  40.212 60.547 41.346 61.321 ;
     RECT  10.368 61.231 10.386 61.349 ;
     RECT  42.516 61.231 42.534 61.349 ;
     RECT  46.944 61.231 46.962 61.349 ;
     RECT  40.104 61.321 41.346 61.493 ;
     RECT  20.376 61.771 20.394 61.889 ;
     RECT  7.815 61.099 8.154 61.925 ;
     RECT  7.815 61.925 8.097 62.011 ;
     RECT  85.5 59.431 85.518 62.045 ;
     RECT  38.772 62.005 38.79 62.159 ;
     RECT  7.416 62.011 8.097 62.195 ;
     RECT  10.26 62.131 10.278 62.231 ;
     RECT  2.415 60.539 2.697 62.299 ;
     RECT  34.815 58.649 35.097 62.581 ;
     RECT  40.215 61.493 41.346 62.581 ;
     RECT  2.415 62.299 2.79 62.671 ;
     RECT  67.215 60.557 67.497 62.671 ;
     RECT  78.015 60.557 78.297 62.671 ;
     RECT  2.304 62.671 2.826 62.683 ;
     RECT  51.015 60.557 51.297 62.683 ;
     RECT  77.904 62.671 78.606 62.683 ;
     RECT  34.776 62.581 35.097 62.699 ;
     RECT  42.696 62.581 42.714 62.699 ;
     RECT  66.708 62.671 67.497 62.717 ;
     RECT  39.888 62.581 41.346 62.771 ;
     RECT  0.108 62.683 0.126 62.813 ;
     RECT  2.304 62.683 2.898 62.813 ;
     RECT  6.84 62.683 6.858 62.813 ;
     RECT  47.592 62.581 47.61 62.813 ;
     RECT  50.724 62.683 51.297 62.813 ;
     RECT  58.68 62.683 58.698 62.813 ;
     RECT  70.704 62.683 70.722 62.813 ;
     RECT  74.736 62.683 74.754 62.813 ;
     RECT  77.904 62.683 78.678 62.813 ;
     RECT  82.62 62.683 82.638 62.813 ;
     RECT  86.292 62.347 86.31 62.813 ;
     RECT  19.98 62.977 19.998 63.085 ;
     RECT  19.8 63.085 19.998 63.149 ;
     RECT  19.8 63.149 19.962 63.239 ;
     RECT  7.815 62.195 8.097 63.307 ;
     RECT  39.888 62.771 41.058 63.355 ;
     RECT  29.415 26.285 29.697 63.481 ;
     RECT  10.224 63.391 10.242 63.509 ;
     RECT  39.816 63.355 41.058 63.509 ;
     RECT  7.815 63.307 8.154 63.545 ;
     RECT  19.944 63.239 19.962 63.545 ;
     RECT  29.415 63.481 30.006 63.581 ;
     RECT  40.104 63.509 41.058 63.779 ;
     RECT  40.215 63.779 41.058 63.781 ;
     RECT  40.215 63.781 41.742 63.821 ;
     RECT  18.615 60.575 18.897 63.883 ;
     RECT  42.84 63.751 42.858 63.931 ;
     RECT  51.015 62.813 51.297 64.021 ;
     RECT  38.772 63.823 38.79 64.049 ;
     RECT  42.84 63.931 42.966 64.049 ;
     RECT  50.184 63.931 50.202 64.049 ;
     RECT  18.615 63.883 18.954 64.085 ;
     RECT  86.292 63.931 86.31 64.085 ;
     RECT  51.015 64.021 51.786 64.157 ;
     RECT  46.728 64.057 46.746 64.229 ;
     RECT  51.015 64.157 51.75 64.229 ;
     RECT  85.5 62.941 85.518 64.291 ;
     RECT  84.924 64.291 85.518 64.301 ;
     RECT  20.52 64.201 20.538 64.319 ;
     RECT  29.415 63.581 29.697 64.471 ;
     RECT  0.108 63.931 0.126 64.589 ;
     RECT  39.348 64.363 39.366 64.589 ;
     RECT  40.215 63.821 41.13 64.589 ;
     RECT  84.924 64.301 84.942 64.589 ;
     RECT  29.415 64.471 30.33 64.625 ;
     RECT  3.96 63.883 3.978 64.637 ;
     RECT  83.415 61.133 83.697 64.831 ;
     RECT  20.376 64.471 20.502 64.859 ;
     RECT  83.415 64.831 84.402 64.925 ;
     RECT  19.764 65.011 19.782 65.129 ;
     RECT  42.624 65.011 42.642 65.129 ;
     RECT  49.212 65.011 49.23 65.129 ;
     RECT  39.06 65.011 39.294 65.165 ;
     RECT  40.215 64.589 41.022 65.371 ;
     RECT  18.615 64.085 18.897 65.515 ;
     RECT  39.276 65.165 39.294 65.515 ;
     RECT  40.215 65.371 41.67 65.551 ;
     RECT  39.276 65.515 39.366 65.659 ;
     RECT  40.215 65.551 41.85 65.659 ;
     RECT  39.276 65.659 41.85 65.669 ;
     RECT  18.252 65.515 18.897 65.705 ;
     RECT  39.888 65.669 41.85 65.705 ;
     RECT  44.244 65.563 44.262 65.705 ;
     RECT  13.215 60.557 13.497 65.803 ;
     RECT  2.415 62.813 2.697 65.821 ;
     RECT  43.272 65.749 43.29 65.821 ;
     RECT  13.104 65.803 13.497 65.849 ;
     RECT  43.272 65.821 43.506 65.849 ;
     RECT  2.304 65.821 2.697 65.885 ;
     RECT  21.888 65.821 21.906 65.939 ;
     RECT  44.424 65.821 44.442 65.939 ;
     RECT  18.504 65.705 18.897 65.975 ;
     RECT  43.488 65.849 43.506 65.975 ;
     RECT  46.728 65.911 46.746 66.119 ;
     RECT  83.415 64.925 83.697 66.139 ;
     RECT  2.415 65.885 2.697 66.181 ;
     RECT  51.015 64.229 51.297 66.187 ;
     RECT  83.415 66.139 83.79 66.209 ;
     RECT  2.415 66.181 2.79 66.221 ;
     RECT  49.86 66.091 49.878 66.317 ;
     RECT  51.015 66.187 51.39 66.317 ;
     RECT  26.784 66.181 26.802 66.353 ;
     RECT  39.888 65.705 41.166 66.631 ;
     RECT  41.976 66.361 41.994 66.631 ;
     RECT  39.888 66.631 41.994 66.721 ;
     RECT  43.56 66.619 44.01 66.749 ;
     RECT  43.56 66.749 43.65 66.785 ;
     RECT  39.816 66.721 41.994 66.821 ;
     RECT  43.632 66.785 43.65 66.893 ;
     RECT  46.728 66.901 46.746 67.019 ;
     RECT  47.484 66.901 47.502 67.019 ;
     RECT  40.032 66.821 41.994 67.055 ;
     RECT  18.615 65.975 18.897 67.099 ;
     RECT  38.772 66.055 38.79 67.289 ;
     RECT  40.14 67.055 41.994 67.289 ;
     RECT  20.52 67.441 20.538 67.559 ;
     RECT  40.14 67.289 41.886 67.631 ;
     RECT  40.14 67.631 41.454 67.829 ;
     RECT  18.252 67.099 18.897 67.865 ;
     RECT  0.108 67.711 0.126 68.099 ;
     RECT  86.292 68.059 86.31 68.099 ;
     RECT  3.96 67.675 3.978 68.141 ;
     RECT  43.416 68.251 43.434 68.369 ;
     RECT  49.212 68.251 49.23 68.369 ;
     RECT  85.5 65.101 85.518 68.381 ;
     RECT  40.215 67.829 41.454 68.521 ;
     RECT  40.215 68.521 41.634 68.611 ;
     RECT  83.415 66.209 83.697 68.611 ;
     RECT  39.888 68.611 41.634 68.639 ;
     RECT  39.888 68.639 41.454 68.675 ;
     RECT  83.415 68.611 84.402 68.717 ;
     RECT  39.888 68.675 41.274 68.783 ;
     RECT  84.924 68.881 84.942 69.005 ;
     RECT  18.615 67.865 18.897 69.307 ;
     RECT  39.924 68.783 41.274 69.449 ;
     RECT  18.615 69.307 18.954 69.485 ;
     RECT  13.215 65.849 13.497 69.592 ;
     RECT  18.615 69.485 18.897 69.595 ;
     RECT  2.415 66.221 2.697 69.601 ;
     RECT  13.104 69.592 13.497 69.629 ;
     RECT  85.5 69.151 85.518 69.676 ;
     RECT  2.304 69.601 2.697 69.677 ;
     RECT  18.504 69.595 18.897 69.755 ;
     RECT  85.5 69.676 85.554 69.965 ;
     RECT  0.108 69.931 0.126 69.989 ;
     RECT  41.868 69.871 41.886 69.989 ;
     RECT  3.96 69.961 3.978 70.013 ;
     RECT  43.812 70.123 43.83 70.219 ;
     RECT  85.5 69.965 85.518 70.231 ;
     RECT  20.304 70.141 20.322 70.259 ;
     RECT  43.164 70.219 43.83 70.267 ;
     RECT  84.924 70.231 85.518 70.301 ;
     RECT  40.215 69.449 40.95 70.411 ;
     RECT  43.164 70.267 43.902 70.439 ;
     RECT  40.215 70.411 41.022 70.529 ;
     RECT  43.164 70.439 43.686 70.681 ;
     RECT  83.415 68.717 83.697 70.771 ;
     RECT  42.948 70.681 43.686 70.835 ;
     RECT  18.615 69.755 18.897 70.891 ;
     RECT  83.415 70.771 83.826 70.925 ;
     RECT  43.668 70.835 43.686 70.979 ;
     RECT  34.815 62.699 35.097 71.041 ;
     RECT  34.776 71.041 35.097 71.177 ;
     RECT  38.772 68.917 38.79 71.177 ;
     RECT  18.615 70.891 18.954 71.179 ;
     RECT  38.844 71.185 38.862 71.339 ;
     RECT  18.252 71.179 18.954 71.375 ;
     RECT  3.96 71.179 3.978 71.519 ;
     RECT  0.108 71.221 0.126 71.549 ;
     RECT  18.504 71.375 18.954 71.645 ;
     RECT  40.215 70.529 40.986 71.761 ;
     RECT  2.415 69.677 2.697 71.851 ;
     RECT  13.215 69.629 13.497 71.851 ;
     RECT  83.415 70.925 83.697 71.887 ;
     RECT  2.304 71.851 2.697 71.888 ;
     RECT  13.104 71.851 13.497 71.888 ;
     RECT  18.504 71.645 18.897 71.915 ;
     RECT  42.768 71.923 42.786 72.031 ;
     RECT  42.156 72.031 42.786 72.059 ;
     RECT  85.5 70.301 85.518 72.121 ;
     RECT  20.484 72.031 20.502 72.149 ;
     RECT  42.156 72.059 42.174 72.149 ;
     RECT  83.415 71.887 83.826 72.173 ;
     RECT  85.5 72.121 85.554 72.509 ;
     RECT  40.215 71.761 41.202 72.571 ;
     RECT  47.88 72.301 47.898 72.689 ;
     RECT  40.215 72.571 41.418 72.805 ;
     RECT  18.615 71.915 18.897 72.811 ;
     RECT  85.536 72.509 85.554 72.845 ;
     RECT  39.924 72.805 41.418 72.959 ;
     RECT  18.252 72.811 18.897 72.995 ;
     RECT  51.015 66.317 51.297 73.099 ;
     RECT  51.015 73.099 51.39 73.139 ;
     RECT  83.415 72.173 83.697 73.201 ;
     RECT  2.415 71.888 2.697 73.435 ;
     RECT  83.415 73.201 84.402 73.469 ;
     RECT  13.215 71.888 13.497 73.471 ;
     RECT  2.304 73.435 2.697 73.499 ;
     RECT  39.996 72.959 41.418 73.499 ;
     RECT  13.104 73.471 13.497 73.517 ;
     RECT  18.504 72.995 18.897 73.535 ;
     RECT  0.108 73.723 0.126 73.769 ;
     RECT  20.268 73.651 20.286 73.769 ;
     RECT  86.292 73.723 86.31 73.769 ;
     RECT  3.96 73.741 3.978 73.805 ;
     RECT  40.032 73.499 41.022 73.805 ;
     RECT  20.304 73.921 20.322 74.039 ;
     RECT  84.924 74.011 84.942 74.093 ;
     RECT  20.844 74.191 20.862 74.309 ;
     RECT  51.015 73.139 51.297 74.347 ;
     RECT  40.215 73.805 41.022 74.425 ;
     RECT  40.215 74.425 41.634 74.461 ;
     RECT  42.552 74.461 42.57 74.551 ;
     RECT  18.615 73.535 18.897 74.683 ;
     RECT  42.552 74.551 43.254 74.683 ;
     RECT  82.08 74.551 82.098 74.717 ;
     RECT  40.215 74.461 41.778 74.827 ;
     RECT  42.552 74.683 43.47 74.827 ;
     RECT  40.215 74.827 43.47 74.849 ;
     RECT  48.456 74.587 48.474 74.849 ;
     RECT  51.015 74.347 51.858 74.849 ;
     RECT  51.015 74.849 51.297 74.857 ;
     RECT  18.615 74.683 18.954 74.885 ;
     RECT  41.544 74.849 43.47 74.885 ;
     RECT  50.688 74.857 51.297 74.957 ;
     RECT  42.264 74.885 43.47 75.001 ;
     RECT  3.96 74.971 3.978 75.029 ;
     RECT  42.264 75.001 43.614 75.029 ;
     RECT  0.108 75.001 0.126 75.053 ;
     RECT  85.5 74.857 85.518 75.053 ;
     RECT  21.78 75.001 21.798 75.119 ;
     RECT  43.38 75.029 43.614 75.119 ;
     RECT  43.38 75.119 43.47 75.155 ;
     RECT  42.264 75.029 42.426 75.197 ;
     RECT  43.38 75.155 43.398 75.227 ;
     RECT  2.415 73.499 2.697 75.259 ;
     RECT  83.415 73.469 83.697 75.271 ;
     RECT  2.415 75.259 2.79 75.299 ;
     RECT  49.572 75.259 49.59 75.299 ;
     RECT  83.415 75.271 83.79 75.341 ;
     RECT  38.772 72.031 38.79 75.389 ;
     RECT  42.408 75.197 42.426 75.389 ;
     RECT  40.215 74.849 40.59 75.595 ;
     RECT  2.415 75.299 2.697 75.631 ;
     RECT  13.215 73.517 13.497 75.631 ;
     RECT  40.215 75.595 40.734 75.631 ;
     RECT  18.615 74.885 18.897 75.643 ;
     RECT  2.304 75.631 2.697 75.677 ;
     RECT  13.104 75.631 13.497 75.677 ;
     RECT  84.924 75.631 84.942 75.677 ;
     RECT  40.032 75.631 40.842 76.081 ;
     RECT  39.636 76.081 40.842 76.207 ;
     RECT  39.636 76.207 40.986 76.235 ;
     RECT  18.504 75.643 18.897 76.267 ;
     RECT  40.176 76.235 40.986 76.351 ;
     RECT  2.415 75.677 2.697 76.603 ;
     RECT  13.215 75.677 13.497 76.603 ;
     RECT  40.176 76.351 41.022 76.621 ;
     RECT  2.304 76.603 2.697 76.649 ;
     RECT  13.104 76.603 13.497 76.649 ;
     RECT  40.176 76.621 41.13 76.891 ;
     RECT  38.772 76.585 38.79 77.009 ;
     RECT  18.252 76.267 18.897 77.045 ;
     RECT  40.176 76.891 41.166 77.125 ;
     RECT  39.708 77.125 41.166 77.161 ;
     RECT  39.708 77.161 41.238 77.279 ;
     RECT  39.924 77.279 41.238 77.315 ;
     RECT  40.215 77.315 41.238 77.431 ;
     RECT  0.108 76.891 0.126 77.549 ;
     RECT  86.292 77.512 86.31 77.549 ;
     RECT  3.96 76.843 3.978 77.597 ;
     RECT  40.215 77.431 41.526 77.819 ;
     RECT  38.772 78.205 38.79 78.359 ;
     RECT  18.615 77.045 18.897 78.475 ;
     RECT  20.484 78.511 20.502 78.629 ;
     RECT  18.615 78.475 18.954 78.665 ;
     RECT  13.215 76.649 13.497 78.763 ;
     RECT  18.615 78.665 18.897 78.763 ;
     RECT  51.015 74.957 51.297 78.763 ;
     RECT  56.415 60.557 56.697 78.763 ;
     RECT  67.215 62.717 67.497 78.763 ;
     RECT  78.015 62.813 78.297 78.763 ;
     RECT  83.415 75.341 83.697 78.763 ;
     RECT  2.415 76.649 2.697 78.781 ;
     RECT  40.215 77.819 41.166 78.781 ;
     RECT  13.104 78.763 13.497 78.809 ;
     RECT  51.015 78.763 51.642 78.809 ;
     RECT  56.304 78.763 56.697 78.809 ;
     RECT  67.104 78.763 67.497 78.809 ;
     RECT  77.904 78.763 78.297 78.809 ;
     RECT  83.304 78.763 83.697 78.809 ;
     RECT  2.304 78.781 2.697 78.845 ;
     RECT  40.215 78.781 41.418 78.859 ;
     RECT  18.504 78.763 18.897 78.935 ;
     RECT  40.215 78.859 41.742 78.935 ;
     RECT  2.415 78.845 2.697 79.141 ;
     RECT  41.868 79.051 41.886 79.169 ;
     RECT  2.415 79.141 2.79 79.181 ;
     RECT  20.304 79.321 20.322 79.439 ;
     RECT  42.228 79.591 42.246 79.661 ;
     RECT  85.5 75.901 85.518 79.681 ;
     RECT  18.615 78.935 18.897 79.771 ;
     RECT  84.924 79.681 85.518 79.805 ;
     RECT  40.215 78.935 41.13 79.861 ;
     RECT  38.772 79.141 38.79 79.979 ;
     RECT  40.215 79.861 41.49 79.979 ;
     RECT  18.252 79.771 18.897 80.015 ;
     RECT  40.215 79.979 41.13 80.095 ;
     RECT  39.456 80.095 41.13 80.141 ;
     RECT  9.9 80.059 9.918 80.248 ;
     RECT  39.456 80.141 41.094 80.249 ;
     RECT  9.9 80.248 10.134 80.285 ;
     RECT  19.728 80.248 19.746 80.285 ;
     RECT  39.636 80.249 41.094 80.285 ;
     RECT  43.56 80.257 43.578 80.329 ;
     RECT  39.888 80.285 41.094 80.381 ;
     RECT  2.415 79.181 2.697 80.392 ;
     RECT  13.215 78.809 13.497 80.392 ;
     RECT  43.344 80.329 43.578 80.401 ;
     RECT  2.304 80.392 2.697 80.429 ;
     RECT  13.104 80.392 13.497 80.429 ;
     RECT  42.192 80.329 42.21 80.429 ;
     RECT  21.78 80.401 21.798 80.519 ;
     RECT  43.344 80.401 43.722 80.519 ;
     RECT  18.504 80.015 18.897 80.555 ;
     RECT  43.344 80.519 43.578 80.555 ;
     RECT  18.615 80.555 18.897 80.635 ;
     RECT  43.56 80.555 43.578 80.699 ;
     RECT  40.104 80.381 41.094 80.789 ;
     RECT  18.615 80.635 18.954 80.825 ;
     RECT  0.108 80.671 0.126 81.059 ;
     RECT  20.52 80.941 20.538 81.059 ;
     RECT  86.292 81.019 86.31 81.059 ;
     RECT  3.96 80.635 3.978 81.101 ;
     RECT  20.376 81.211 20.394 81.329 ;
     RECT  40.215 80.789 41.094 81.571 ;
     RECT  39.924 81.571 41.094 81.751 ;
     RECT  18.615 80.825 18.897 81.979 ;
     RECT  44.136 82.123 44.154 82.175 ;
     RECT  18.252 81.979 18.897 82.267 ;
     RECT  85.5 79.805 85.518 82.301 ;
     RECT  38.772 82.219 38.79 82.319 ;
     RECT  21.564 82.291 21.582 82.409 ;
     RECT  39.924 81.751 41.238 82.409 ;
     RECT  44.316 82.291 44.334 82.409 ;
     RECT  18.252 82.267 18.954 82.445 ;
     RECT  42.84 82.291 42.858 82.445 ;
     RECT  13.215 80.429 13.497 82.552 ;
     RECT  56.415 78.809 56.697 82.552 ;
     RECT  67.215 78.809 67.497 82.552 ;
     RECT  78.015 78.809 78.297 82.552 ;
     RECT  51.015 78.809 51.297 82.555 ;
     RECT  83.415 78.809 83.697 82.555 ;
     RECT  2.415 80.429 2.697 82.561 ;
     RECT  13.104 82.552 13.497 82.589 ;
     RECT  56.304 82.552 56.697 82.589 ;
     RECT  67.104 82.552 67.497 82.589 ;
     RECT  77.904 82.552 78.297 82.589 ;
     RECT  83.304 82.555 83.697 82.595 ;
     RECT  2.304 82.561 2.697 82.637 ;
     RECT  39.924 82.409 41.022 82.651 ;
     RECT  51.015 82.555 51.426 82.679 ;
     RECT  18.252 82.445 18.897 82.715 ;
     RECT  39.708 82.651 41.022 82.921 ;
     RECT  10.044 82.921 10.062 82.939 ;
     RECT  0.144 82.891 0.162 82.949 ;
     RECT  86.292 82.891 86.31 82.949 ;
     RECT  3.96 82.921 3.978 82.973 ;
     RECT  9.864 82.939 10.062 82.973 ;
     RECT  9.864 82.973 9.882 82.985 ;
     RECT  19.62 82.939 19.638 82.985 ;
     RECT  39.24 82.921 41.022 83.093 ;
     RECT  51.015 82.679 51.297 83.191 ;
     RECT  39.384 83.093 41.022 83.255 ;
     RECT  39.384 83.255 39.402 83.327 ;
     RECT  40.215 83.255 41.022 83.461 ;
     RECT  42.948 83.371 42.966 83.489 ;
     RECT  47.376 83.371 47.394 83.489 ;
     RECT  85.5 83.461 85.518 83.597 ;
     RECT  42.048 83.335 42.066 83.633 ;
     RECT  40.215 83.461 41.202 83.641 ;
     RECT  18.615 82.715 18.897 83.851 ;
     RECT  50.868 83.191 51.297 83.851 ;
     RECT  50.688 83.851 51.297 83.939 ;
     RECT  40.215 83.641 41.562 84.451 ;
     RECT  3.96 84.139 3.978 84.479 ;
     RECT  0.108 84.181 0.126 84.509 ;
     RECT  86.292 84.187 86.31 84.569 ;
     RECT  18.615 83.851 18.954 84.605 ;
     RECT  20.304 84.451 20.322 84.721 ;
     RECT  40.212 84.451 41.562 84.721 ;
     RECT  2.415 82.637 2.697 84.811 ;
     RECT  13.215 82.589 13.497 84.811 ;
     RECT  18.615 84.605 18.897 84.811 ;
     RECT  20.196 84.721 20.322 84.839 ;
     RECT  2.304 84.811 2.697 84.848 ;
     RECT  13.104 84.811 13.497 84.848 ;
     RECT  18.504 84.811 18.897 84.875 ;
     RECT  39.924 84.721 41.562 84.875 ;
     RECT  20.808 84.991 20.826 85.109 ;
     RECT  43.308 84.991 43.326 85.109 ;
     RECT  46.944 84.991 46.962 85.109 ;
     RECT  40.215 84.875 41.562 85.261 ;
     RECT  40.215 85.261 41.742 85.339 ;
     RECT  85.5 84.805 85.518 85.351 ;
     RECT  40.215 85.339 42.246 85.379 ;
     RECT  40.215 85.379 41.382 85.415 ;
     RECT  84.924 85.351 85.518 85.469 ;
     RECT  42.372 85.531 43.11 85.649 ;
     RECT  48.456 85.531 48.474 85.649 ;
     RECT  34.815 71.177 35.097 85.765 ;
     RECT  34.776 85.765 35.097 85.919 ;
     RECT  51.015 83.939 51.297 86.035 ;
     RECT  51.015 86.035 51.39 86.093 ;
     RECT  38.772 86.035 38.79 86.189 ;
     RECT  40.215 85.415 41.202 86.305 ;
     RECT  2.415 84.848 2.697 86.395 ;
     RECT  13.215 84.848 13.497 86.431 ;
     RECT  18.615 84.875 18.897 86.443 ;
     RECT  2.304 86.395 2.697 86.459 ;
     RECT  39.78 86.305 41.202 86.459 ;
     RECT  13.104 86.431 13.497 86.477 ;
     RECT  18.504 86.443 18.897 86.495 ;
     RECT  39.888 86.459 41.202 86.495 ;
     RECT  40.215 86.495 41.202 86.611 ;
     RECT  42.372 85.649 42.39 86.611 ;
     RECT  40.215 86.611 42.39 86.729 ;
     RECT  47.268 86.611 47.286 86.765 ;
     RECT  20.484 86.881 20.502 86.999 ;
     RECT  40.215 86.729 41.274 87.349 ;
     RECT  40.032 87.349 41.274 87.449 ;
     RECT  85.5 85.469 85.518 87.511 ;
     RECT  20.268 87.421 20.286 87.539 ;
     RECT  18.615 86.495 18.897 87.643 ;
     RECT  84.924 87.511 85.518 87.677 ;
     RECT  38.772 87.655 38.79 87.809 ;
     RECT  40.14 87.449 41.274 87.961 ;
     RECT  3.96 87.931 3.978 87.989 ;
     RECT  0.108 87.961 0.126 88.013 ;
     RECT  51.015 86.093 51.297 88.159 ;
     RECT  2.415 86.459 2.697 88.219 ;
     RECT  50.904 88.159 51.297 88.231 ;
     RECT  83.415 82.595 83.697 88.231 ;
     RECT  2.415 88.219 2.79 88.259 ;
     RECT  40.14 87.961 41.346 88.321 ;
     RECT  42.516 88.231 42.534 88.349 ;
     RECT  46.98 88.159 46.998 88.349 ;
     RECT  49.284 88.231 49.302 88.349 ;
     RECT  50.832 88.231 51.297 88.349 ;
     RECT  83.415 88.231 84.402 88.349 ;
     RECT  18.252 87.643 18.897 88.385 ;
     RECT  39.924 88.321 41.346 88.421 ;
     RECT  43.74 88.315 43.758 88.465 ;
     RECT  43.272 88.465 43.758 88.501 ;
     RECT  2.415 88.259 2.697 88.591 ;
     RECT  13.215 86.477 13.497 88.591 ;
     RECT  40.215 88.421 41.346 88.619 ;
     RECT  43.272 88.501 43.902 88.619 ;
     RECT  2.304 88.591 2.697 88.637 ;
     RECT  13.104 88.591 13.497 88.637 ;
     RECT  18.504 88.385 18.897 88.655 ;
     RECT  43.272 88.619 43.686 88.655 ;
     RECT  43.272 88.655 43.29 88.727 ;
     RECT  51.015 88.349 51.297 88.861 ;
     RECT  51.015 88.861 51.642 88.973 ;
     RECT  18.615 88.655 18.897 89.227 ;
     RECT  41.94 89.131 41.958 89.311 ;
     RECT  20.952 89.311 20.97 89.429 ;
     RECT  2.415 88.637 2.697 89.563 ;
     RECT  13.215 88.637 13.497 89.563 ;
     RECT  18.615 89.227 18.954 89.563 ;
     RECT  56.415 82.589 56.697 89.563 ;
     RECT  67.215 82.589 67.497 89.563 ;
     RECT  78.015 82.589 78.297 89.563 ;
     RECT  2.304 89.563 2.697 89.609 ;
     RECT  13.104 89.563 13.497 89.609 ;
     RECT  56.304 89.563 56.697 89.609 ;
     RECT  67.104 89.563 67.497 89.609 ;
     RECT  77.904 89.563 78.297 89.609 ;
     RECT  38.772 88.591 38.79 89.699 ;
     RECT  18.504 89.563 18.954 89.735 ;
     RECT  40.215 88.619 41.202 89.851 ;
     RECT  41.94 89.311 42.246 89.851 ;
     RECT  0.108 89.851 0.126 89.888 ;
     RECT  40.215 89.851 42.246 89.941 ;
     RECT  20.412 89.851 20.43 89.969 ;
     RECT  39.924 89.941 42.246 89.969 ;
     RECT  18.615 89.735 18.954 90.005 ;
     RECT  39.924 89.969 41.958 90.005 ;
     RECT  51.015 88.973 51.297 90.091 ;
     RECT  50.652 90.091 51.297 90.149 ;
     RECT  86.292 90.091 86.31 90.221 ;
     RECT  0.144 90.187 0.162 90.239 ;
     RECT  38.196 89.977 38.214 90.239 ;
     RECT  3.96 89.803 3.978 90.269 ;
     RECT  39.924 90.005 41.454 90.275 ;
     RECT  40.215 90.275 41.454 91.129 ;
     RECT  18.615 90.005 18.897 91.147 ;
     RECT  40.215 91.129 41.49 91.342 ;
     RECT  18.252 91.147 18.897 91.355 ;
     RECT  18.615 91.355 18.897 91.435 ;
     RECT  44.244 91.429 44.262 91.469 ;
     RECT  85.5 87.677 85.518 91.469 ;
     RECT  42.948 91.399 42.966 91.471 ;
     RECT  44.424 91.471 44.442 91.561 ;
     RECT  21.708 91.471 21.726 91.589 ;
     RECT  44.424 91.561 44.514 91.589 ;
     RECT  18.615 91.435 18.954 91.625 ;
     RECT  42.948 91.471 43.182 91.625 ;
     RECT  44.496 91.589 44.514 91.697 ;
     RECT  40.215 91.342 41.454 91.741 ;
     RECT  51.015 90.149 51.297 91.741 ;
     RECT  39.924 91.741 41.454 91.859 ;
     RECT  39.924 91.859 41.31 91.895 ;
     RECT  0.108 91.771 0.126 91.901 ;
     RECT  50.508 91.741 51.297 91.901 ;
     RECT  86.292 91.771 86.31 91.901 ;
     RECT  84.924 92.101 84.942 92.141 ;
     RECT  42.768 92.137 42.786 92.237 ;
     RECT  40.215 91.895 41.31 92.399 ;
     RECT  44.676 92.281 44.694 92.399 ;
     RECT  47.952 92.281 47.97 92.429 ;
     RECT  43.704 92.347 43.722 92.551 ;
     RECT  42.48 92.551 42.498 92.641 ;
     RECT  18.615 91.625 18.897 92.731 ;
     RECT  43.704 92.551 43.866 92.861 ;
     RECT  83.415 88.349 83.697 92.911 ;
     RECT  43.848 92.861 43.866 92.939 ;
     RECT  42.192 92.641 42.498 92.947 ;
     RECT  18.252 92.731 18.897 93.019 ;
     RECT  83.415 92.911 84.402 93.053 ;
     RECT  42.12 92.947 42.498 93.091 ;
     RECT  51.015 91.901 51.297 93.091 ;
     RECT  20.484 93.091 20.502 93.209 ;
     RECT  18.252 93.019 18.954 93.245 ;
     RECT  2.415 89.609 2.697 93.352 ;
     RECT  13.215 89.609 13.497 93.352 ;
     RECT  40.215 92.399 41.238 93.361 ;
     RECT  42.012 93.091 42.498 93.361 ;
     RECT  2.304 93.352 2.697 93.389 ;
     RECT  13.104 93.352 13.497 93.389 ;
     RECT  85.5 92.641 85.518 93.389 ;
     RECT  40.215 93.361 42.498 93.479 ;
     RECT  50.616 93.091 51.297 93.479 ;
     RECT  18.252 93.245 18.897 93.515 ;
     RECT  42.552 93.631 42.57 93.749 ;
     RECT  49.752 93.631 49.77 93.749 ;
     RECT  40.215 93.479 41.526 93.901 ;
     RECT  38.772 90.481 38.79 94.055 ;
     RECT  39.816 93.901 41.526 94.055 ;
     RECT  3.96 93.721 3.978 94.061 ;
     RECT  20.628 94.027 20.646 94.199 ;
     RECT  39.924 94.055 41.526 94.325 ;
     RECT  61.815 60.611 62.097 94.507 ;
     RECT  51.015 93.479 51.297 94.531 ;
     RECT  18.615 93.515 18.897 94.567 ;
     RECT  67.215 89.609 67.497 94.597 ;
     RECT  2.415 93.389 2.697 94.603 ;
     RECT  14.724 94.507 14.742 94.603 ;
     RECT  54.612 94.507 54.63 94.603 ;
     RECT  61.815 94.507 62.622 94.603 ;
     RECT  66.78 94.597 67.497 94.603 ;
     RECT  78.015 89.609 78.297 94.603 ;
     RECT  14.724 94.603 14.85 94.637 ;
     RECT  54.612 94.603 54.738 94.637 ;
     RECT  2.415 94.603 2.862 94.733 ;
     RECT  14.832 94.637 14.85 94.733 ;
     RECT  18.252 94.567 18.897 94.733 ;
     RECT  51.015 94.531 51.534 94.733 ;
     RECT  61.815 94.603 62.73 94.733 ;
     RECT  78.015 94.603 78.678 94.733 ;
     RECT  82.62 94.603 82.638 94.733 ;
     RECT  20.088 94.567 20.106 94.739 ;
     RECT  39.924 94.325 41.31 94.865 ;
     RECT  6.84 94.603 6.858 94.877 ;
     RECT  10.836 94.603 10.854 94.877 ;
     RECT  54.72 94.637 54.738 94.877 ;
     RECT  58.68 94.603 58.698 94.877 ;
     RECT  66.708 94.603 67.497 94.877 ;
     RECT  74.664 94.603 74.682 94.877 ;
     RECT  85.5 94.261 85.518 94.973 ;
     RECT  18.615 94.733 18.897 95.227 ;
     RECT  3.96 95.227 3.978 95.279 ;
     RECT  20.628 95.107 20.646 95.279 ;
     RECT  0.108 93.691 0.126 95.309 ;
     RECT  40.215 94.865 41.31 95.341 ;
     RECT  42.624 95.251 42.642 95.369 ;
     RECT  86.292 93.691 86.31 95.369 ;
     RECT  18.615 95.227 18.954 95.405 ;
     RECT  13.215 93.389 13.497 95.512 ;
     RECT  18.615 95.405 18.897 95.515 ;
     RECT  2.415 94.733 2.697 95.521 ;
     RECT  13.104 95.512 13.497 95.549 ;
     RECT  2.304 95.521 2.697 95.597 ;
     RECT  42.984 95.521 43.002 95.639 ;
     RECT  49.716 95.521 49.734 95.639 ;
     RECT  84.888 95.563 84.906 95.639 ;
     RECT  18.504 95.515 18.897 95.675 ;
     RECT  40.215 95.341 41.346 95.791 ;
     RECT  20.304 95.791 20.322 95.909 ;
     RECT  43.092 95.791 43.29 95.909 ;
     RECT  49.644 95.719 49.662 95.933 ;
     RECT  40.212 95.791 41.346 95.945 ;
     RECT  40.215 95.945 41.346 96.061 ;
     RECT  43.092 95.909 43.11 96.179 ;
     RECT  47.484 95.251 47.502 96.179 ;
     RECT  38.772 96.151 38.79 96.287 ;
     RECT  40.215 96.061 41.418 96.295 ;
     RECT  40.215 96.295 41.454 96.331 ;
     RECT  83.415 93.053 83.697 96.421 ;
     RECT  40.215 96.331 42.318 96.449 ;
     RECT  42.3 96.449 42.318 96.485 ;
     RECT  83.415 96.421 84.402 96.557 ;
     RECT  20.52 96.601 20.538 96.719 ;
     RECT  18.615 95.675 18.897 96.811 ;
     RECT  39.348 96.835 39.366 96.989 ;
     RECT  40.215 96.449 41.454 96.989 ;
     RECT  42.48 96.601 42.498 96.989 ;
     RECT  18.252 96.811 18.897 97.025 ;
     RECT  20.484 97.141 20.502 97.259 ;
     RECT  42.516 97.141 42.534 97.259 ;
     RECT  51.015 94.733 51.297 97.411 ;
     RECT  40.215 96.989 41.418 97.501 ;
     RECT  85.5 96.151 85.518 97.501 ;
     RECT  0.108 97.141 0.126 97.529 ;
     RECT  47.88 97.411 47.898 97.529 ;
     RECT  3.96 97.099 3.978 97.565 ;
     RECT  39.888 97.501 41.418 97.673 ;
     RECT  50.544 97.411 51.297 97.681 ;
     RECT  2.415 95.597 2.697 97.771 ;
     RECT  7.815 63.545 8.097 97.771 ;
     RECT  50.472 97.681 51.297 97.799 ;
     RECT  85.5 97.501 85.554 97.805 ;
     RECT  2.304 97.771 2.697 97.808 ;
     RECT  42.228 97.771 42.246 97.808 ;
     RECT  39.924 97.673 41.418 97.871 ;
     RECT  18.615 97.025 18.897 97.915 ;
     RECT  18.615 97.915 18.954 98.069 ;
     RECT  40.215 97.871 41.418 98.251 ;
     RECT  38.772 98.041 38.79 98.447 ;
     RECT  20.268 98.185 20.286 98.455 ;
     RECT  20.268 98.455 20.574 98.609 ;
     RECT  7.416 97.771 8.097 98.645 ;
     RECT  40.215 98.251 41.778 98.725 ;
     RECT  20.268 98.609 20.394 98.761 ;
     RECT  85.5 97.805 85.518 98.765 ;
     RECT  83.415 96.557 83.697 98.851 ;
     RECT  10.26 98.761 10.278 98.879 ;
     RECT  40.104 98.725 41.778 98.879 ;
     RECT  20.052 98.761 20.394 98.915 ;
     RECT  2.415 97.808 2.697 99.019 ;
     RECT  2.415 99.019 2.79 99.059 ;
     RECT  83.415 98.851 84.402 99.101 ;
     RECT  40.215 98.879 41.778 99.149 ;
     RECT  40.215 99.149 41.562 99.185 ;
     RECT  49.86 99.157 49.878 99.293 ;
     RECT  2.415 99.059 2.697 99.355 ;
     RECT  86.292 99.259 86.31 99.389 ;
     RECT  7.815 98.645 8.097 99.403 ;
     RECT  2.304 99.355 2.697 99.419 ;
     RECT  20.376 98.915 20.394 99.419 ;
     RECT  48.312 99.301 48.33 99.419 ;
     RECT  7.704 99.403 8.097 99.691 ;
     RECT  84.924 99.661 84.942 99.725 ;
     RECT  18.615 98.069 18.897 99.733 ;
     RECT  38.772 99.301 38.79 99.761 ;
     RECT  40.215 99.185 41.274 99.931 ;
     RECT  18.615 99.733 19.422 99.959 ;
     RECT  43.524 99.841 43.542 99.959 ;
     RECT  49.212 99.841 49.23 99.959 ;
     RECT  7.416 99.691 8.097 99.979 ;
     RECT  7.416 99.979 8.154 99.995 ;
     RECT  85.5 99.931 85.518 100.013 ;
     RECT  40.215 99.931 41.49 100.111 ;
     RECT  50.184 100.273 50.202 100.349 ;
     RECT  40.215 100.111 41.85 100.381 ;
     RECT  40.215 100.381 41.994 100.499 ;
     RECT  40.215 100.499 41.346 100.535 ;
     RECT  10.368 100.507 10.386 100.651 ;
     RECT  10.368 100.651 10.854 100.769 ;
     RECT  20.016 100.075 20.07 100.777 ;
     RECT  7.815 99.995 8.154 100.805 ;
     RECT  20.016 100.777 20.214 100.805 ;
     RECT  20.196 100.805 20.214 100.949 ;
     RECT  40.215 100.535 41.31 101.039 ;
     RECT  86.292 100.651 86.31 101.039 ;
     RECT  43.056 100.921 43.074 101.047 ;
     RECT  43.056 101.047 43.146 101.147 ;
     RECT  40.215 101.039 41.166 101.261 ;
     RECT  0.108 100.651 0.126 101.309 ;
     RECT  42.948 101.191 42.966 101.309 ;
     RECT  50.256 100.921 50.274 101.309 ;
     RECT  85.464 101.272 85.482 101.309 ;
     RECT  3.96 100.603 3.978 101.357 ;
     RECT  10.368 100.769 10.386 101.489 ;
     RECT  2.415 99.419 2.697 101.551 ;
     RECT  83.415 99.101 83.697 101.551 ;
     RECT  2.304 101.551 2.697 101.597 ;
     RECT  83.415 101.551 84.402 101.597 ;
     RECT  7.815 100.805 8.097 101.659 ;
     RECT  6.84 101.563 6.858 101.693 ;
     RECT  20.16 101.659 20.178 101.759 ;
     RECT  10.332 101.731 10.35 101.849 ;
     RECT  7.815 101.659 8.154 101.899 ;
     RECT  40.215 101.261 41.094 102.271 ;
     RECT  7.416 101.899 8.154 102.425 ;
     RECT  20.376 102.361 20.394 102.461 ;
     RECT  2.415 101.597 2.697 102.523 ;
     RECT  2.304 102.523 2.697 102.569 ;
     RECT  40.215 102.271 41.202 102.739 ;
     RECT  39.924 102.739 41.202 102.839 ;
     RECT  85.5 101.821 85.518 102.892 ;
     RECT  2.415 102.569 2.697 102.901 ;
     RECT  20.196 102.811 20.214 102.901 ;
     RECT  20.016 102.901 20.214 102.929 ;
     RECT  2.415 102.901 2.79 102.941 ;
     RECT  20.016 102.929 20.106 103.073 ;
     RECT  43.812 103.045 43.83 103.081 ;
     RECT  0.108 103.051 0.126 103.181 ;
     RECT  85.5 102.892 85.554 103.181 ;
     RECT  43.812 103.081 44.478 103.199 ;
     RECT  43.812 103.199 44.262 103.235 ;
     RECT  21.96 103.171 22.158 103.271 ;
     RECT  21.96 103.271 21.978 103.343 ;
     RECT  38.772 101.281 38.79 103.343 ;
     RECT  43.812 103.235 43.83 103.343 ;
     RECT  40.14 102.839 41.202 103.621 ;
     RECT  20.088 103.073 20.106 103.649 ;
     RECT  40.104 103.621 41.202 103.711 ;
     RECT  51.015 97.799 51.297 103.711 ;
     RECT  7.416 102.425 8.097 103.771 ;
     RECT  7.416 103.771 8.154 103.775 ;
     RECT  39.816 103.711 41.202 103.811 ;
     RECT  19.944 103.855 19.962 104.009 ;
     RECT  85.5 103.181 85.518 104.141 ;
     RECT  38.772 104.125 38.79 104.279 ;
     RECT  50.688 103.711 51.297 104.395 ;
     RECT  83.415 101.597 83.697 104.395 ;
     RECT  40.215 103.811 41.202 104.431 ;
     RECT  3.96 104.395 3.978 104.459 ;
     RECT  10.368 104.287 10.386 104.459 ;
     RECT  50.544 104.395 51.297 104.459 ;
     RECT  0.108 104.431 0.126 104.477 ;
     RECT  86.292 104.431 86.31 104.477 ;
     RECT  83.415 104.395 83.826 104.521 ;
     RECT  20.376 104.431 20.61 104.549 ;
     RECT  7.815 103.775 8.154 104.585 ;
     RECT  20.376 104.549 20.394 104.621 ;
     RECT  7.815 104.585 8.097 104.683 ;
     RECT  2.415 102.941 2.697 104.701 ;
     RECT  39.168 104.359 39.366 104.701 ;
     RECT  2.304 104.701 2.697 104.765 ;
     RECT  83.415 104.521 84.402 104.765 ;
     RECT  10.044 104.701 10.062 104.819 ;
     RECT  40.215 104.431 41.238 104.819 ;
     RECT  19.62 104.701 19.638 104.855 ;
     RECT  39.168 104.701 39.402 104.855 ;
     RECT  40.215 104.819 41.094 104.855 ;
     RECT  45.615 30.335 45.897 104.971 ;
     RECT  45.615 104.971 46.17 105.089 ;
     RECT  47.7 104.863 47.718 105.101 ;
     RECT  44.1 105.061 44.118 105.205 ;
     RECT  44.1 105.205 44.442 105.241 ;
     RECT  22.068 105.097 22.086 105.269 ;
     RECT  7.704 104.683 8.097 105.355 ;
     RECT  11.304 105.241 11.322 105.359 ;
     RECT  44.1 105.241 44.586 105.511 ;
     RECT  21.888 105.475 21.906 105.629 ;
     RECT  50.184 105.511 50.202 105.629 ;
     RECT  7.416 105.355 8.097 105.665 ;
     RECT  44.1 105.511 44.622 105.665 ;
     RECT  85.5 105.331 85.518 105.725 ;
     RECT  42.66 105.511 42.786 105.737 ;
     RECT  44.604 105.665 44.622 105.737 ;
     RECT  40.215 104.855 40.986 105.745 ;
     RECT  39.888 105.745 40.986 105.899 ;
     RECT  19.944 105.781 19.962 105.935 ;
     RECT  40.068 105.899 40.986 105.935 ;
     RECT  7.704 105.665 8.097 106.027 ;
     RECT  51.015 104.459 51.297 106.027 ;
     RECT  40.104 105.935 40.986 106.051 ;
     RECT  51.015 106.027 51.426 106.079 ;
     RECT  40.104 106.051 41.13 106.169 ;
     RECT  7.704 106.027 8.154 106.205 ;
     RECT  2.415 104.765 2.697 106.312 ;
     RECT  2.304 106.312 2.697 106.349 ;
     RECT  42.084 106.321 42.102 106.411 ;
     RECT  41.796 106.411 42.102 106.439 ;
     RECT  7.704 106.205 8.097 106.475 ;
     RECT  41.796 106.439 41.958 106.589 ;
     RECT  20.052 106.321 20.07 106.591 ;
     RECT  20.052 106.591 20.322 106.709 ;
     RECT  40.104 106.169 41.058 106.789 ;
     RECT  40.068 106.789 41.058 106.951 ;
     RECT  0.108 106.651 0.126 106.979 ;
     RECT  10.224 105.781 10.242 106.979 ;
     RECT  39.888 106.951 41.058 106.979 ;
     RECT  86.292 106.315 86.31 106.979 ;
     RECT  19.944 106.861 19.962 107.015 ;
     RECT  3.96 106.681 3.978 107.021 ;
     RECT  39.888 106.979 41.022 107.123 ;
     RECT  41.796 106.589 41.814 107.249 ;
     RECT  18.615 99.959 18.897 107.611 ;
     RECT  39.924 107.123 41.022 107.755 ;
     RECT  83.415 104.765 83.697 107.761 ;
     RECT  18.252 107.611 18.897 107.825 ;
     RECT  83.415 107.761 84.402 107.933 ;
     RECT  20.484 107.941 20.502 108.059 ;
     RECT  7.815 106.475 8.097 108.187 ;
     RECT  39.924 107.755 41.094 108.211 ;
     RECT  3.96 108.187 3.978 108.239 ;
     RECT  0.108 108.211 0.126 108.269 ;
     RECT  38.772 105.331 38.79 108.329 ;
     RECT  7.416 108.187 8.097 108.365 ;
     RECT  10.26 108.301 10.278 108.401 ;
     RECT  13.215 95.549 13.497 108.472 ;
     RECT  2.415 106.349 2.697 108.481 ;
     RECT  13.104 108.472 13.497 108.509 ;
     RECT  2.304 108.481 2.697 108.557 ;
     RECT  20.196 108.481 20.214 108.599 ;
     RECT  86.292 108.523 86.31 108.599 ;
     RECT  18.504 107.825 18.897 108.635 ;
     RECT  39.924 108.211 41.238 108.635 ;
     RECT  40.215 108.635 41.238 108.751 ;
     RECT  20.484 109.021 20.502 109.139 ;
     RECT  38.916 108.841 39.366 109.175 ;
     RECT  40.215 108.751 41.346 109.183 ;
     RECT  50.184 109.417 50.202 109.517 ;
     RECT  38.772 109.417 38.79 109.679 ;
     RECT  40.215 109.183 41.562 109.997 ;
     RECT  40.215 109.997 41.238 110.045 ;
     RECT  51.015 106.079 51.297 110.101 ;
     RECT  0.144 110.101 0.162 110.141 ;
     RECT  10.08 110.059 10.098 110.191 ;
     RECT  13.215 108.509 13.497 110.191 ;
     RECT  42.948 110.101 42.966 110.219 ;
     RECT  20.016 110.203 20.034 110.227 ;
     RECT  86.292 110.107 86.31 110.255 ;
     RECT  50.796 110.101 51.297 110.291 ;
     RECT  40.215 110.045 40.986 110.371 ;
     RECT  46.728 110.227 46.746 110.399 ;
     RECT  34.815 85.919 35.097 110.461 ;
     RECT  0.108 110.443 0.126 110.489 ;
     RECT  42.696 110.371 42.714 110.489 ;
     RECT  3.96 110.059 3.978 110.525 ;
     RECT  34.776 110.461 35.097 110.561 ;
     RECT  2.415 108.557 2.697 110.731 ;
     RECT  40.176 110.371 40.986 110.731 ;
     RECT  39.708 110.731 40.986 110.759 ;
     RECT  2.304 110.731 2.697 110.768 ;
     RECT  10.08 110.191 10.242 110.768 ;
     RECT  13.104 110.191 13.497 110.768 ;
     RECT  20.016 110.227 20.214 110.827 ;
     RECT  6.84 110.731 6.858 110.861 ;
     RECT  19.908 110.827 20.214 110.903 ;
     RECT  20.304 110.911 20.322 111.029 ;
     RECT  41.796 110.911 41.814 111.029 ;
     RECT  50.184 110.911 50.202 111.029 ;
     RECT  85.5 107.221 85.518 111.101 ;
     RECT  39.708 110.759 40.878 111.173 ;
     RECT  10.008 110.827 10.026 111.403 ;
     RECT  39.708 111.173 40.698 111.415 ;
     RECT  84.924 111.271 84.942 111.437 ;
     RECT  9.972 111.403 10.026 111.541 ;
     RECT  9.972 111.541 10.17 111.605 ;
     RECT  18.615 108.635 18.897 111.643 ;
     RECT  14.832 110.731 14.85 111.677 ;
     RECT  7.815 108.365 8.097 111.691 ;
     RECT  83.415 107.933 83.697 111.691 ;
     RECT  18.615 111.643 19.422 111.713 ;
     RECT  10.152 111.605 10.17 111.839 ;
     RECT  83.415 111.691 83.79 111.839 ;
     RECT  19.8 111.721 19.818 111.847 ;
     RECT  7.416 111.691 8.097 111.875 ;
     RECT  19.8 111.847 19.998 111.875 ;
     RECT  2.415 110.768 2.697 111.979 ;
     RECT  39.564 111.415 40.698 111.991 ;
     RECT  2.415 111.979 2.79 112.019 ;
     RECT  19.98 111.875 19.998 112.019 ;
     RECT  22.788 111.991 22.806 112.109 ;
     RECT  84.888 112.027 84.906 112.109 ;
     RECT  39.564 111.991 40.77 112.145 ;
     RECT  2.415 112.019 2.697 112.315 ;
     RECT  2.304 112.315 2.697 112.379 ;
     RECT  86.292 112.315 86.31 112.379 ;
     RECT  38.772 112.351 38.79 112.451 ;
     RECT  83.415 111.839 83.697 112.621 ;
     RECT  7.704 111.875 8.097 112.651 ;
     RECT  20.088 112.657 20.106 112.829 ;
     RECT  7.416 112.651 8.097 112.955 ;
     RECT  7.815 112.955 8.097 112.987 ;
     RECT  83.415 112.621 84.402 113.021 ;
     RECT  40.215 112.145 40.77 113.035 ;
     RECT  40.104 113.035 40.77 113.071 ;
     RECT  10.26 113.071 10.278 113.189 ;
     RECT  20.052 113.071 20.07 113.225 ;
     RECT  18.615 111.713 18.897 113.275 ;
     RECT  40.104 113.071 40.878 113.305 ;
     RECT  41.616 112.075 41.634 113.305 ;
     RECT  40.104 113.305 41.634 113.341 ;
     RECT  40.104 113.341 42.282 113.431 ;
     RECT  39.456 113.431 42.282 113.459 ;
     RECT  18.252 113.275 18.897 113.495 ;
     RECT  41.94 113.459 41.958 113.495 ;
     RECT  39.456 113.459 41.166 113.575 ;
     RECT  85.5 113.161 85.518 113.645 ;
     RECT  10.044 113.611 10.062 113.729 ;
     RECT  42.876 113.611 42.894 113.729 ;
     RECT  52.452 113.611 52.47 113.729 ;
     RECT  7.815 112.987 8.154 113.765 ;
     RECT  19.62 113.611 19.638 113.765 ;
     RECT  7.815 113.765 8.097 113.851 ;
     RECT  83.415 113.021 83.826 113.933 ;
     RECT  39.168 113.575 41.166 113.999 ;
     RECT  7.416 113.851 8.097 114.035 ;
     RECT  0.108 113.611 0.126 114.269 ;
     RECT  10.224 114.151 10.242 114.269 ;
     RECT  43.308 114.151 43.326 114.269 ;
     RECT  48.456 114.151 48.474 114.269 ;
     RECT  86.292 114.232 86.31 114.269 ;
     RECT  19.944 114.151 19.962 114.305 ;
     RECT  3.96 113.563 3.978 114.317 ;
     RECT  39.888 113.999 41.166 114.413 ;
     RECT  40.068 114.413 41.166 114.511 ;
     RECT  18.615 113.495 18.897 114.547 ;
     RECT  7.815 114.035 8.097 114.571 ;
     RECT  40.068 114.511 41.418 114.575 ;
     RECT  18.615 114.547 19.422 114.809 ;
     RECT  20.16 114.925 20.178 115.079 ;
     RECT  51.015 110.291 51.297 115.195 ;
     RECT  50.436 115.195 51.297 115.259 ;
     RECT  10.224 115.231 10.242 115.349 ;
     RECT  7.815 114.571 8.154 115.385 ;
     RECT  19.944 115.231 20.07 115.385 ;
     RECT  2.415 112.379 2.697 115.483 ;
     RECT  7.815 115.385 8.097 115.483 ;
     RECT  43.596 115.429 43.614 115.501 ;
     RECT  2.304 115.483 2.697 115.529 ;
     RECT  43.596 115.501 44.442 115.529 ;
     RECT  85.5 114.511 85.518 115.591 ;
     RECT  22.032 115.501 22.05 115.619 ;
     RECT  43.812 115.529 44.442 115.619 ;
     RECT  40.215 114.575 41.418 115.627 ;
     RECT  7.704 115.483 8.097 115.655 ;
     RECT  43.812 115.619 43.83 115.655 ;
     RECT  40.215 115.627 41.526 115.663 ;
     RECT  46.728 115.591 46.746 115.691 ;
     RECT  84.924 115.591 85.518 115.853 ;
     RECT  2.415 115.529 2.697 115.861 ;
     RECT  10.26 115.771 10.278 115.889 ;
     RECT  40.215 115.663 41.922 115.889 ;
     RECT  2.415 115.861 2.79 115.901 ;
     RECT  20.052 115.385 20.07 116.131 ;
     RECT  40.215 115.889 41.67 116.159 ;
     RECT  20.052 116.131 20.502 116.231 ;
     RECT  38.772 114.115 38.79 116.311 ;
     RECT  19.764 116.311 20.034 116.429 ;
     RECT  38.772 116.311 39.078 116.581 ;
     RECT  38.772 116.581 39.294 116.735 ;
     RECT  7.815 115.655 8.097 116.779 ;
     RECT  10.26 116.851 10.278 116.969 ;
     RECT  7.416 116.779 8.097 117.005 ;
     RECT  20.016 116.429 20.034 117.005 ;
     RECT  40.215 116.159 41.094 117.049 ;
     RECT  85.5 115.853 85.518 117.101 ;
     RECT  20.196 117.121 20.214 117.239 ;
     RECT  39.816 117.049 41.094 117.239 ;
     RECT  38.772 116.735 38.79 117.355 ;
     RECT  83.415 113.933 83.697 117.403 ;
     RECT  38.196 117.355 38.79 117.509 ;
     RECT  83.415 117.403 84.366 117.509 ;
     RECT  39.816 117.239 40.95 117.545 ;
     RECT  10.044 117.481 10.062 117.581 ;
     RECT  0.108 117.403 0.126 117.779 ;
     RECT  42.948 117.661 42.966 117.779 ;
     RECT  48.672 117.661 48.69 117.779 ;
     RECT  86.292 117.739 86.31 117.779 ;
     RECT  38.772 117.509 38.79 117.815 ;
     RECT  3.96 117.751 3.978 117.821 ;
     RECT  20.268 117.661 20.286 118.057 ;
     RECT  40.215 117.545 40.95 118.201 ;
     RECT  20.124 118.057 20.322 118.229 ;
     RECT  10.26 118.201 10.278 118.319 ;
     RECT  40.215 118.201 40.986 118.471 ;
     RECT  40.215 118.471 41.13 118.561 ;
     RECT  39.96 118.561 41.13 118.705 ;
     RECT  39.78 118.705 41.13 118.859 ;
     RECT  18.615 114.809 18.897 118.987 ;
     RECT  19.908 118.831 19.926 119.003 ;
     RECT  51.015 115.259 51.297 119.101 ;
     RECT  18.252 118.987 18.897 119.165 ;
     RECT  50.4 119.101 51.297 119.213 ;
     RECT  2.415 115.901 2.697 119.272 ;
     RECT  13.215 110.768 13.497 119.272 ;
     RECT  56.415 89.609 56.697 119.272 ;
     RECT  67.215 94.877 67.497 119.272 ;
     RECT  78.015 94.733 78.297 119.272 ;
     RECT  2.304 119.272 2.697 119.309 ;
     RECT  13.104 119.272 13.497 119.309 ;
     RECT  56.304 119.272 56.697 119.309 ;
     RECT  67.104 119.272 67.497 119.309 ;
     RECT  77.904 119.272 78.297 119.309 ;
     RECT  39.816 118.859 41.13 119.399 ;
     RECT  43.776 119.371 43.794 119.407 ;
     RECT  18.504 119.165 18.897 119.435 ;
     RECT  43.344 119.407 43.794 119.551 ;
     RECT  42.516 119.479 42.534 119.579 ;
     RECT  0.108 119.611 0.126 119.669 ;
     RECT  21.492 119.551 21.51 119.669 ;
     RECT  40.215 119.399 40.878 119.669 ;
     RECT  43.344 119.551 43.938 119.669 ;
     RECT  3.96 119.641 3.978 119.693 ;
     RECT  43.344 119.669 43.362 119.705 ;
     RECT  20.304 119.821 20.322 119.939 ;
     RECT  34.815 110.561 35.097 120.181 ;
     RECT  40.215 119.669 40.842 120.209 ;
     RECT  7.815 117.005 8.097 120.235 ;
     RECT  34.776 120.181 35.097 120.281 ;
     RECT  7.416 120.235 8.097 120.515 ;
     RECT  18.615 119.435 18.897 120.571 ;
     RECT  51.015 119.213 51.297 120.859 ;
     RECT  40.215 120.209 40.698 120.901 ;
     RECT  50.652 120.859 51.297 120.929 ;
     RECT  38.772 118.975 38.79 121.019 ;
     RECT  40.032 120.901 40.698 121.055 ;
     RECT  39.24 121.135 39.258 121.171 ;
     RECT  3.96 121.147 3.978 121.199 ;
     RECT  0.108 121.171 0.126 121.229 ;
     RECT  39.24 121.171 39.438 121.289 ;
     RECT  18.615 120.571 18.954 121.325 ;
     RECT  39.42 121.289 39.438 121.325 ;
     RECT  40.215 121.055 40.698 121.441 ;
     RECT  2.415 119.309 2.697 121.531 ;
     RECT  13.215 119.309 13.497 121.531 ;
     RECT  18.615 121.325 18.897 121.531 ;
     RECT  42.12 121.441 42.138 121.559 ;
     RECT  49.104 121.441 49.122 121.559 ;
     RECT  2.304 121.531 2.697 121.568 ;
     RECT  13.104 121.531 13.497 121.568 ;
     RECT  18.504 121.531 18.897 121.595 ;
     RECT  37.116 121.531 37.134 121.703 ;
     RECT  20.268 121.711 20.286 121.829 ;
     RECT  37.044 121.711 37.062 121.865 ;
     RECT  18.615 121.595 18.897 122.443 ;
     RECT  40.215 121.441 40.878 122.521 ;
     RECT  38.772 122.485 38.79 122.639 ;
     RECT  42.12 122.587 42.138 122.639 ;
     RECT  18.252 122.443 18.897 122.675 ;
     RECT  85.5 118.021 85.518 122.813 ;
     RECT  42.264 122.791 42.282 122.909 ;
     RECT  40.215 122.521 40.914 123.025 ;
     RECT  40.215 123.025 41.022 123.061 ;
     RECT  2.415 121.568 2.697 123.115 ;
     RECT  13.215 121.568 13.497 123.151 ;
     RECT  2.304 123.115 2.697 123.179 ;
     RECT  84.888 123.115 84.906 123.179 ;
     RECT  13.104 123.151 13.497 123.197 ;
     RECT  18.504 122.675 18.897 123.215 ;
     RECT  37.044 122.881 37.062 123.251 ;
     RECT  40.215 123.061 41.238 123.421 ;
     RECT  0.108 123.403 0.126 123.449 ;
     RECT  42.3 123.331 42.318 123.449 ;
     RECT  49.212 123.331 49.23 123.449 ;
     RECT  86.292 123.403 86.31 123.449 ;
     RECT  3.96 123.421 3.978 123.485 ;
     RECT  39.816 123.421 41.238 123.521 ;
     RECT  40.215 123.521 41.238 124.141 ;
     RECT  51.015 120.929 51.297 124.231 ;
     RECT  18.615 123.215 18.897 124.363 ;
     RECT  20.484 124.411 20.502 124.529 ;
     RECT  42.732 124.411 42.75 124.529 ;
     RECT  48.564 124.411 48.582 124.529 ;
     RECT  3.96 124.651 3.978 124.709 ;
     RECT  0.108 124.681 0.126 124.733 ;
     RECT  37.044 124.339 37.062 124.799 ;
     RECT  2.415 123.179 2.697 124.939 ;
     RECT  40.215 124.141 41.31 124.951 ;
     RECT  50.616 124.231 51.297 124.951 ;
     RECT  2.415 124.939 2.79 124.979 ;
     RECT  20.412 124.951 20.43 125.069 ;
     RECT  43.164 124.951 43.182 125.069 ;
     RECT  50.184 124.951 51.297 125.069 ;
     RECT  86.292 124.987 86.31 125.069 ;
     RECT  40.212 124.951 41.31 125.077 ;
     RECT  50.796 125.069 51.297 125.077 ;
     RECT  39.42 124.843 39.438 125.185 ;
     RECT  18.615 124.363 18.954 125.221 ;
     RECT  39.06 125.185 39.438 125.221 ;
     RECT  40.212 125.077 41.742 125.221 ;
     RECT  50.796 125.077 51.75 125.249 ;
     RECT  2.415 124.979 2.697 125.311 ;
     RECT  7.815 120.515 8.097 125.323 ;
     RECT  10.008 125.221 10.026 125.339 ;
     RECT  39.06 125.221 41.886 125.339 ;
     RECT  18.615 125.221 19.602 125.347 ;
     RECT  2.304 125.311 2.697 125.357 ;
     RECT  7.704 125.323 8.097 125.375 ;
     RECT  18.615 125.347 19.782 125.375 ;
     RECT  39.276 125.339 41.238 125.375 ;
     RECT  19.764 125.375 19.782 125.519 ;
     RECT  85.5 123.691 85.518 125.581 ;
     RECT  34.815 120.281 35.097 125.617 ;
     RECT  39.384 125.375 41.238 125.645 ;
     RECT  84.924 125.581 85.518 125.645 ;
     RECT  34.776 125.617 35.097 125.753 ;
     RECT  39.852 125.645 41.238 125.915 ;
     RECT  18.615 125.375 18.897 125.947 ;
     RECT  18.252 125.947 18.897 126.185 ;
     RECT  41.976 126.229 41.994 126.265 ;
     RECT  41.976 126.265 42.39 126.301 ;
     RECT  41.976 126.301 42.534 126.329 ;
     RECT  45.615 105.089 45.897 126.391 ;
     RECT  21.24 126.301 21.258 126.419 ;
     RECT  42.3 126.329 42.534 126.419 ;
     RECT  42.3 126.419 42.426 126.455 ;
     RECT  67.215 119.309 67.497 126.499 ;
     RECT  2.415 125.357 2.697 126.523 ;
     RECT  14.724 126.427 14.742 126.523 ;
     RECT  18.615 126.185 18.897 126.523 ;
     RECT  50.076 126.499 50.094 126.523 ;
     RECT  51.015 125.249 51.297 126.523 ;
     RECT  61.815 94.733 62.097 126.523 ;
     RECT  78.015 119.309 78.297 126.523 ;
     RECT  45 126.391 45.897 126.527 ;
     RECT  14.724 126.523 14.85 126.557 ;
     RECT  2.415 126.523 2.862 126.653 ;
     RECT  14.832 126.557 14.85 126.653 ;
     RECT  50.076 126.523 51.297 126.653 ;
     RECT  61.815 126.523 62.73 126.653 ;
     RECT  78.015 126.523 78.678 126.653 ;
     RECT  82.62 126.523 82.638 126.653 ;
     RECT  42.408 126.455 42.426 126.689 ;
     RECT  48.672 126.571 48.69 126.689 ;
     RECT  18.615 126.523 18.954 126.725 ;
     RECT  6.84 126.523 6.858 126.749 ;
     RECT  10.836 126.523 10.854 126.749 ;
     RECT  50.724 126.653 51.297 126.749 ;
     RECT  58.68 126.523 58.698 126.749 ;
     RECT  66.708 126.499 67.497 126.749 ;
     RECT  74.664 126.523 74.682 126.749 ;
     RECT  86.292 126.571 86.31 126.749 ;
     RECT  37.044 126.121 37.062 126.959 ;
     RECT  40.215 125.915 41.238 126.959 ;
     RECT  40.215 126.959 41.022 127.111 ;
     RECT  85.5 125.645 85.518 127.192 ;
     RECT  0.108 126.571 0.126 127.229 ;
     RECT  20.268 127.111 20.286 127.229 ;
     RECT  85.464 127.192 85.518 127.229 ;
     RECT  40.104 127.111 41.022 127.265 ;
     RECT  3.96 126.931 3.978 127.277 ;
     RECT  20.484 127.381 20.502 127.499 ;
     RECT  83.415 117.509 83.697 127.741 ;
     RECT  18.615 126.725 18.897 128.155 ;
     RECT  85.5 127.229 85.518 128.189 ;
     RECT  40.215 127.265 41.022 128.191 ;
     RECT  38.772 128.155 38.79 128.309 ;
     RECT  13.215 123.197 13.497 128.443 ;
     RECT  2.415 126.653 2.697 128.461 ;
     RECT  39.348 128.425 39.366 128.461 ;
     RECT  40.215 128.191 41.13 128.461 ;
     RECT  13.104 128.443 13.497 128.489 ;
     RECT  2.304 128.461 2.697 128.525 ;
     RECT  51.015 126.749 51.297 128.683 ;
     RECT  39.348 128.461 41.13 128.687 ;
     RECT  0.108 128.683 0.126 128.813 ;
     RECT  86.292 128.683 86.31 128.813 ;
     RECT  50.868 128.683 51.297 128.849 ;
     RECT  18.252 128.155 18.897 128.885 ;
     RECT  83.415 127.741 84.402 129.149 ;
     RECT  39.348 128.687 41.094 129.155 ;
     RECT  39.348 129.155 39.366 129.271 ;
     RECT  38.772 129.271 39.366 129.389 ;
     RECT  41.868 129.361 41.886 129.397 ;
     RECT  38.808 129.389 39.366 129.425 ;
     RECT  41.868 129.397 42.39 129.437 ;
     RECT  48.816 129.361 48.834 129.437 ;
     RECT  41.868 129.437 41.886 129.461 ;
     RECT  18.615 128.885 18.897 129.739 ;
     RECT  40.104 129.155 41.094 129.929 ;
     RECT  51.015 128.849 51.297 129.937 ;
     RECT  50.616 129.937 51.297 130.013 ;
     RECT  2.415 128.525 2.697 130.072 ;
     RECT  13.215 128.489 13.497 130.072 ;
     RECT  56.415 119.309 56.697 130.072 ;
     RECT  67.215 126.749 67.497 130.072 ;
     RECT  78.015 126.653 78.297 130.072 ;
     RECT  18.615 129.739 18.954 130.075 ;
     RECT  40.215 129.929 41.094 130.081 ;
     RECT  2.304 130.072 2.697 130.109 ;
     RECT  13.104 130.072 13.497 130.109 ;
     RECT  56.304 130.072 56.697 130.109 ;
     RECT  67.104 130.072 67.497 130.109 ;
     RECT  77.904 130.072 78.297 130.109 ;
     RECT  38.808 129.425 38.826 130.199 ;
     RECT  18.504 130.075 18.954 130.235 ;
     RECT  43.992 130.315 44.01 130.351 ;
     RECT  0.108 130.351 0.126 130.397 ;
     RECT  38.772 130.315 38.79 130.469 ;
     RECT  43.884 130.351 44.154 130.469 ;
     RECT  18.615 130.235 18.954 130.505 ;
     RECT  43.884 130.469 43.902 130.505 ;
     RECT  40.215 130.081 41.13 130.549 ;
     RECT  40.215 130.549 41.166 130.621 ;
     RECT  0.144 130.699 0.162 130.739 ;
     RECT  40.215 130.621 41.238 130.739 ;
     RECT  86.292 130.699 86.31 130.739 ;
     RECT  3.96 130.315 3.978 130.781 ;
     RECT  40.215 130.739 41.094 130.891 ;
     RECT  40.104 130.891 41.094 130.925 ;
     RECT  20.268 130.891 20.286 131.009 ;
     RECT  40.104 130.925 40.986 131.009 ;
     RECT  20.484 131.161 20.502 131.279 ;
     RECT  42.84 131.083 43.182 131.359 ;
     RECT  42.768 131.359 43.182 131.459 ;
     RECT  85.5 129.631 85.518 131.521 ;
     RECT  40.104 131.009 40.95 131.629 ;
     RECT  84.924 131.521 85.518 131.693 ;
     RECT  39.996 131.629 40.95 131.803 ;
     RECT  42.84 131.459 43.11 131.819 ;
     RECT  47.376 131.701 47.394 131.819 ;
     RECT  42.84 131.819 42.858 131.837 ;
     RECT  39.996 131.803 41.166 131.935 ;
     RECT  18.615 130.505 18.897 131.947 ;
     RECT  85.5 131.693 85.518 131.981 ;
     RECT  39.708 131.935 41.166 132.089 ;
     RECT  18.615 131.947 18.954 132.125 ;
     RECT  13.215 130.109 13.497 132.232 ;
     RECT  18.615 132.125 18.897 132.235 ;
     RECT  2.415 130.109 2.697 132.241 ;
     RECT  39.816 132.089 41.166 132.241 ;
     RECT  13.104 132.232 13.497 132.269 ;
     RECT  2.304 132.241 2.697 132.317 ;
     RECT  18.504 132.235 18.897 132.395 ;
     RECT  0.108 132.571 0.126 132.629 ;
     RECT  38.772 131.629 38.79 132.629 ;
     RECT  39.816 132.241 41.31 132.629 ;
     RECT  86.292 132.283 86.31 132.629 ;
     RECT  3.96 132.601 3.978 132.653 ;
     RECT  39.816 132.629 41.166 132.809 ;
     RECT  51.015 130.013 51.297 133.195 ;
     RECT  39.816 132.809 41.022 133.241 ;
     RECT  43.344 133.321 43.362 133.439 ;
     RECT  51.015 133.195 51.966 133.447 ;
     RECT  18.615 132.395 18.897 133.531 ;
     RECT  40.032 133.241 41.022 133.619 ;
     RECT  46.764 133.483 46.782 133.619 ;
     RECT  20.268 133.591 20.286 133.709 ;
     RECT  50.4 133.447 51.966 133.709 ;
     RECT  18.615 133.531 18.954 133.819 ;
     RECT  52.02 133.717 52.038 133.889 ;
     RECT  85.5 132.871 85.518 133.901 ;
     RECT  40.068 133.619 41.022 133.963 ;
     RECT  3.96 133.819 3.978 134.159 ;
     RECT  0.144 133.861 0.162 134.189 ;
     RECT  86.292 134.155 86.31 134.249 ;
     RECT  18.252 133.819 18.954 134.285 ;
     RECT  40.068 133.963 41.094 134.401 ;
     RECT  2.415 132.317 2.697 134.485 ;
     RECT  13.215 132.269 13.497 134.485 ;
     RECT  83.415 129.149 83.697 134.485 ;
     RECT  39.996 134.401 41.238 134.491 ;
     RECT  2.304 134.485 2.697 134.525 ;
     RECT  13.104 134.485 13.497 134.525 ;
     RECT  83.415 134.485 84.402 134.525 ;
     RECT  18.252 134.285 18.897 134.555 ;
     RECT  39.708 134.491 41.238 134.555 ;
     RECT  21.708 134.671 21.726 134.789 ;
     RECT  85.5 134.761 85.518 134.813 ;
     RECT  38.772 133.825 38.79 134.897 ;
     RECT  40.215 134.555 41.238 134.905 ;
     RECT  40.215 134.905 41.31 134.941 ;
     RECT  43.452 134.905 43.47 134.941 ;
     RECT  40.215 134.941 41.67 135.059 ;
     RECT  51.015 133.709 51.297 135.067 ;
     RECT  40.215 135.059 41.526 135.095 ;
     RECT  43.2 134.941 43.614 135.095 ;
     RECT  43.596 135.095 43.614 135.131 ;
     RECT  50.292 135.067 51.297 135.149 ;
     RECT  83.415 134.525 83.697 135.301 ;
     RECT  40.215 135.095 41.13 135.445 ;
     RECT  83.415 135.301 83.826 135.485 ;
     RECT  39.78 135.445 41.13 135.599 ;
     RECT  39.96 135.599 41.13 135.635 ;
     RECT  50.22 135.739 50.238 135.779 ;
     RECT  20.484 135.751 20.502 135.869 ;
     RECT  2.415 134.525 2.697 136.075 ;
     RECT  40.104 135.635 41.13 136.075 ;
     RECT  84.924 135.841 84.942 136.109 ;
     RECT  13.215 134.525 13.497 136.111 ;
     RECT  18.615 134.555 18.897 136.123 ;
     RECT  2.304 136.075 2.697 136.139 ;
     RECT  40.104 136.075 41.49 136.139 ;
     RECT  13.104 136.111 13.497 136.157 ;
     RECT  18.504 136.123 18.897 136.175 ;
     RECT  0.108 136.363 0.126 136.409 ;
     RECT  20.52 136.291 20.934 136.409 ;
     RECT  86.292 136.363 86.31 136.409 ;
     RECT  3.96 136.381 3.978 136.445 ;
     RECT  40.215 136.139 41.49 136.445 ;
     RECT  41.832 136.525 41.994 136.561 ;
     RECT  83.415 135.485 83.697 136.651 ;
     RECT  83.415 136.651 84.402 137.069 ;
     RECT  20.52 136.409 20.538 137.219 ;
     RECT  41.832 136.561 42.174 137.219 ;
     RECT  41.832 137.219 41.85 137.255 ;
     RECT  18.615 136.175 18.897 137.323 ;
     RECT  83.415 137.069 83.826 137.357 ;
     RECT  38.772 137.335 38.79 137.489 ;
     RECT  18.252 137.323 18.897 137.525 ;
     RECT  40.215 136.445 41.094 137.641 ;
     RECT  3.96 137.611 3.978 137.669 ;
     RECT  0.144 137.641 0.162 137.693 ;
     RECT  40.215 137.641 41.562 138.029 ;
     RECT  40.215 138.029 41.238 138.035 ;
     RECT  0.108 137.947 0.126 138.077 ;
     RECT  49.428 137.911 49.446 138.077 ;
     RECT  86.292 137.947 86.31 138.077 ;
     RECT  2.415 136.139 2.697 138.271 ;
     RECT  13.215 136.157 13.497 138.271 ;
     RECT  18.615 137.525 18.897 138.283 ;
     RECT  20.484 137.641 20.502 138.299 ;
     RECT  2.304 138.271 2.697 138.317 ;
     RECT  13.104 138.271 13.497 138.317 ;
     RECT  40.215 138.035 41.13 138.371 ;
     RECT  19.98 138.541 19.998 138.641 ;
     RECT  40.215 138.371 41.094 138.721 ;
     RECT  83.415 137.357 83.697 138.811 ;
     RECT  18.504 138.283 18.897 138.907 ;
     RECT  83.415 138.811 84.402 138.941 ;
     RECT  85.5 137.461 85.518 139.081 ;
     RECT  38.772 138.685 38.79 139.109 ;
     RECT  18.252 138.907 18.897 139.145 ;
     RECT  2.415 138.317 2.697 139.243 ;
     RECT  13.215 138.317 13.497 139.243 ;
     RECT  84.924 139.081 85.518 139.277 ;
     RECT  2.304 139.243 2.697 139.289 ;
     RECT  13.104 139.243 13.497 139.289 ;
     RECT  20.412 139.261 20.43 139.379 ;
     RECT  18.504 139.145 18.897 139.415 ;
     RECT  39.744 138.721 41.094 139.495 ;
     RECT  85.5 139.277 85.518 139.565 ;
     RECT  2.415 139.289 2.697 139.621 ;
     RECT  18.615 139.415 18.897 139.621 ;
     RECT  7.815 125.375 8.097 139.627 ;
     RECT  7.416 139.627 8.097 139.685 ;
     RECT  18.615 139.621 19.314 139.793 ;
     RECT  51.015 135.149 51.297 139.801 ;
     RECT  50.004 139.621 50.022 139.805 ;
     RECT  83.415 138.941 83.697 139.891 ;
     RECT  86.292 139.771 86.31 139.901 ;
     RECT  0.108 139.867 0.126 139.919 ;
     RECT  20.52 139.801 20.538 139.919 ;
     RECT  42.66 139.801 42.678 139.919 ;
     RECT  50.832 139.801 51.297 139.919 ;
     RECT  3.96 139.891 3.978 139.949 ;
     RECT  39.492 139.495 41.094 140.035 ;
     RECT  2.415 139.621 2.79 140.099 ;
     RECT  39.276 140.035 41.094 140.189 ;
     RECT  83.415 139.891 84.402 140.189 ;
     RECT  39.492 140.189 41.022 140.225 ;
     RECT  20.484 140.341 20.502 140.459 ;
     RECT  83.415 140.189 83.826 140.525 ;
     RECT  51.015 139.919 51.297 140.827 ;
     RECT  51.015 140.827 51.426 140.909 ;
     RECT  38.196 140.773 38.214 140.999 ;
     RECT  40.104 140.225 41.022 141.007 ;
     RECT  18.615 139.793 18.897 141.115 ;
     RECT  40.104 141.007 41.526 141.151 ;
     RECT  42.588 140.971 42.606 141.151 ;
     RECT  40.104 141.151 42.75 141.179 ;
     RECT  42.192 141.179 42.75 141.241 ;
     RECT  20.952 141.151 20.97 141.269 ;
     RECT  18.615 141.115 18.954 141.305 ;
     RECT  42.192 141.241 42.822 141.305 ;
     RECT  42.264 141.305 42.822 141.341 ;
     RECT  13.215 139.289 13.497 141.403 ;
     RECT  18.615 141.305 18.897 141.403 ;
     RECT  56.415 130.109 56.697 141.403 ;
     RECT  67.215 130.109 67.497 141.403 ;
     RECT  78.015 130.109 78.297 141.403 ;
     RECT  83.415 140.525 83.697 141.403 ;
     RECT  2.415 140.099 2.697 141.421 ;
     RECT  13.104 141.403 13.497 141.449 ;
     RECT  39.348 141.313 39.366 141.449 ;
     RECT  42.264 141.341 42.282 141.449 ;
     RECT  56.304 141.403 56.697 141.449 ;
     RECT  67.104 141.403 67.497 141.449 ;
     RECT  77.904 141.403 78.297 141.449 ;
     RECT  83.304 141.403 83.697 141.449 ;
     RECT  2.304 141.421 2.697 141.485 ;
     RECT  20.592 141.421 20.61 141.539 ;
     RECT  18.504 141.403 18.897 141.575 ;
     RECT  40.104 141.179 41.202 141.655 ;
     RECT  2.415 141.485 2.697 141.781 ;
     RECT  39.492 141.655 41.202 141.809 ;
     RECT  2.415 141.781 2.79 141.821 ;
     RECT  39.708 141.809 41.202 141.845 ;
     RECT  7.815 139.685 8.097 142.075 ;
     RECT  40.215 141.845 41.202 142.231 ;
     RECT  20.376 142.195 20.394 142.349 ;
     RECT  40.215 142.231 41.31 142.349 ;
     RECT  7.815 142.075 8.154 142.385 ;
     RECT  7.815 142.385 8.097 142.411 ;
     RECT  43.56 142.459 43.578 142.465 ;
     RECT  43.38 142.465 43.578 142.501 ;
     RECT  42.192 142.429 42.21 142.529 ;
     RECT  21.672 142.501 21.69 142.591 ;
     RECT  21.456 142.591 21.69 142.619 ;
     RECT  43.38 142.501 43.722 142.619 ;
     RECT  49.644 142.501 49.662 142.619 ;
     RECT  7.416 142.411 8.097 142.655 ;
     RECT  43.38 142.619 43.398 142.655 ;
     RECT  21.456 142.619 21.474 142.691 ;
     RECT  18.615 141.575 18.897 142.699 ;
     RECT  46.728 142.501 46.746 142.727 ;
     RECT  38.772 142.627 38.79 142.799 ;
     RECT  20.412 142.771 20.43 142.889 ;
     RECT  18.615 142.699 18.954 142.925 ;
     RECT  2.415 141.821 2.697 143.032 ;
     RECT  13.215 141.449 13.497 143.032 ;
     RECT  18.615 142.925 18.897 143.035 ;
     RECT  40.215 142.349 41.202 143.041 ;
     RECT  2.304 143.032 2.697 143.069 ;
     RECT  13.104 143.032 13.497 143.069 ;
     RECT  39.924 143.041 41.202 143.131 ;
     RECT  38.196 143.005 38.214 143.159 ;
     RECT  18.252 143.035 18.897 143.195 ;
     RECT  7.815 142.655 8.097 143.275 ;
     RECT  39.924 143.131 41.454 143.311 ;
     RECT  20.304 143.311 20.322 143.401 ;
     RECT  20.124 143.401 20.322 143.429 ;
     RECT  39.924 143.311 41.634 143.429 ;
     RECT  7.815 143.275 8.154 143.465 ;
     RECT  20.124 143.429 20.214 143.573 ;
     RECT  0.108 143.311 0.126 143.699 ;
     RECT  86.292 143.659 86.31 143.699 ;
     RECT  3.96 143.275 3.978 143.741 ;
     RECT  39.924 143.429 40.986 143.803 ;
     RECT  39.78 143.803 40.986 143.843 ;
     RECT  20.196 143.573 20.214 143.969 ;
     RECT  38.772 143.545 38.79 144.005 ;
     RECT  85.5 140.971 85.518 144.317 ;
     RECT  39.816 143.843 40.986 144.481 ;
     RECT  39.816 144.481 41.382 144.545 ;
     RECT  7.815 143.465 8.097 144.619 ;
     RECT  83.415 141.449 83.697 144.619 ;
     RECT  18.615 143.195 18.897 144.661 ;
     RECT  51.015 140.909 51.297 144.661 ;
     RECT  42.768 144.661 42.894 144.751 ;
     RECT  14.832 144.661 14.85 144.779 ;
     RECT  42.768 144.751 42.966 144.779 ;
     RECT  51.015 144.661 51.354 144.779 ;
     RECT  83.415 144.619 84.366 144.779 ;
     RECT  7.416 144.619 8.097 144.815 ;
     RECT  18.615 144.661 19.422 144.815 ;
     RECT  42.948 144.779 42.966 144.851 ;
     RECT  7.704 144.815 8.097 144.907 ;
     RECT  40.215 144.545 41.382 144.931 ;
     RECT  48.924 144.907 48.942 144.959 ;
     RECT  38.772 144.895 38.79 145.049 ;
     RECT  40.215 144.931 41.418 145.049 ;
     RECT  7.704 144.907 8.154 145.085 ;
     RECT  2.415 143.069 2.697 145.201 ;
     RECT  2.304 145.201 2.697 145.277 ;
     RECT  40.215 145.049 41.238 145.319 ;
     RECT  85.464 145.243 85.482 145.319 ;
     RECT  40.215 145.319 41.094 145.378 ;
     RECT  20.448 145.021 20.466 145.705 ;
     RECT  20.16 145.705 20.466 145.741 ;
     RECT  20.16 145.741 20.502 145.859 ;
     RECT  7.704 145.085 8.097 145.867 ;
     RECT  18.615 144.815 18.897 145.903 ;
     RECT  18.615 145.903 19.422 146.129 ;
     RECT  7.416 145.867 8.097 146.165 ;
     RECT  40.215 145.378 41.022 146.371 ;
     RECT  20.16 145.859 20.394 146.399 ;
     RECT  7.815 146.165 8.097 146.491 ;
     RECT  20.16 146.399 20.178 146.551 ;
     RECT  38.772 146.137 38.79 146.669 ;
     RECT  40.176 146.371 41.022 146.785 ;
     RECT  10.26 146.551 10.278 146.939 ;
     RECT  39.996 146.785 41.022 146.939 ;
     RECT  20.016 146.551 20.178 146.975 ;
     RECT  40.14 146.939 41.022 146.975 ;
     RECT  42.264 146.947 42.282 146.983 ;
     RECT  42.264 146.983 42.426 147.005 ;
     RECT  40.176 146.975 41.022 147.019 ;
     RECT  83.415 144.779 83.697 147.067 ;
     RECT  3.96 146.779 3.978 147.119 ;
     RECT  48.276 147.067 48.294 147.119 ;
     RECT  83.415 147.067 83.826 147.119 ;
     RECT  0.108 146.821 0.126 147.149 ;
     RECT  86.292 147.091 86.31 147.149 ;
     RECT  39.348 147.019 39.366 147.209 ;
     RECT  42.408 147.005 42.426 147.209 ;
     RECT  7.815 146.491 8.154 147.245 ;
     RECT  40.176 147.019 41.094 147.245 ;
     RECT  20.448 147.181 20.466 147.353 ;
     RECT  2.415 145.277 2.697 147.451 ;
     RECT  7.815 147.245 8.097 147.451 ;
     RECT  42.624 147.361 42.642 147.479 ;
     RECT  48.024 147.361 48.042 147.479 ;
     RECT  85.5 145.561 85.518 147.485 ;
     RECT  2.304 147.451 2.697 147.488 ;
     RECT  38.772 147.451 38.79 147.551 ;
     RECT  18.615 146.129 18.897 147.595 ;
     RECT  18.615 147.595 19.422 147.749 ;
     RECT  84.924 147.721 84.942 147.821 ;
     RECT  40.215 147.245 40.95 147.991 ;
     RECT  83.415 147.119 83.697 147.991 ;
     RECT  10.332 147.901 10.35 148.019 ;
     RECT  39.708 147.991 40.95 148.091 ;
     RECT  83.415 147.991 84.402 148.109 ;
     RECT  18.615 147.749 18.954 148.289 ;
     RECT  20.16 147.829 20.178 148.441 ;
     RECT  41.94 148.405 41.958 148.441 ;
     RECT  41.94 148.441 42.318 148.445 ;
     RECT  20.016 148.441 20.178 148.531 ;
     RECT  42.084 148.445 42.318 148.559 ;
     RECT  47.916 148.441 47.934 148.559 ;
     RECT  20.016 148.531 20.214 148.631 ;
     RECT  10.224 148.441 10.242 148.801 ;
     RECT  38.772 148.675 38.79 148.829 ;
     RECT  42.084 148.559 42.102 148.829 ;
     RECT  7.416 147.451 8.097 148.865 ;
     RECT  10.224 148.801 10.278 148.901 ;
     RECT  39.924 148.091 40.95 148.945 ;
     RECT  2.415 147.488 2.697 149.035 ;
     RECT  85.5 148.261 85.518 149.069 ;
     RECT  2.304 149.035 2.697 149.099 ;
     RECT  10.116 148.981 10.134 149.099 ;
     RECT  39.348 148.945 40.986 149.099 ;
     RECT  19.692 148.981 19.71 149.135 ;
     RECT  39.528 149.099 40.986 149.135 ;
     RECT  39.708 149.135 40.986 149.251 ;
     RECT  48.816 149.251 48.834 149.405 ;
     RECT  39.708 149.251 41.13 149.441 ;
     RECT  40.215 149.441 41.13 149.549 ;
     RECT  19.908 149.485 19.926 149.639 ;
     RECT  7.704 148.865 8.097 149.659 ;
     RECT  84.924 149.611 84.942 149.693 ;
     RECT  20.052 149.755 20.07 149.909 ;
     RECT  7.416 149.659 8.097 149.945 ;
     RECT  7.815 149.945 8.097 150.283 ;
     RECT  85.5 149.881 85.518 150.317 ;
     RECT  40.215 149.549 40.986 150.331 ;
     RECT  40.215 150.331 41.346 150.421 ;
     RECT  7.815 150.283 8.154 150.485 ;
     RECT  39.924 150.421 41.346 150.529 ;
     RECT  83.415 148.109 83.697 150.571 ;
     RECT  20.448 150.421 20.466 150.601 ;
     RECT  43.524 149.899 43.542 150.601 ;
     RECT  48.456 150.457 48.474 150.605 ;
     RECT  39.924 150.529 41.454 150.629 ;
     RECT  83.415 150.571 83.826 150.629 ;
     RECT  20.448 150.601 20.934 150.719 ;
     RECT  43.524 150.601 43.686 150.719 ;
     RECT  39.924 150.629 41.094 150.755 ;
     RECT  42.624 150.457 42.642 150.755 ;
     RECT  20.448 150.719 20.718 150.791 ;
     RECT  0.108 150.601 0.126 150.989 ;
     RECT  86.292 150.601 86.31 150.989 ;
     RECT  3.96 150.571 3.978 151.037 ;
     RECT  37.044 150.961 37.062 151.061 ;
     RECT  2.415 149.099 2.697 151.231 ;
     RECT  40.215 150.755 41.094 151.259 ;
     RECT  43.2 151.141 43.218 151.259 ;
     RECT  50.184 151.141 50.202 151.259 ;
     RECT  2.304 151.231 2.697 151.277 ;
     RECT  85.5 151.231 85.518 151.277 ;
     RECT  7.815 150.485 8.097 151.339 ;
     RECT  6.84 151.243 6.858 151.373 ;
     RECT  20.34 151.267 20.358 151.439 ;
     RECT  10.368 150.187 10.386 151.529 ;
     RECT  7.815 151.339 8.154 151.579 ;
     RECT  20.196 151.501 20.214 151.601 ;
     RECT  84.924 151.501 84.942 151.613 ;
     RECT  83.415 150.629 83.697 151.771 ;
     RECT  7.416 151.579 8.154 151.835 ;
     RECT  40.215 151.259 40.986 151.915 ;
     RECT  10.116 151.951 10.134 152.069 ;
     RECT  39.492 151.915 40.986 152.069 ;
     RECT  7.704 151.835 8.154 152.105 ;
     RECT  19.8 151.951 19.818 152.105 ;
     RECT  39.708 152.069 40.986 152.105 ;
     RECT  2.415 151.277 2.697 152.203 ;
     RECT  40.215 152.105 40.986 152.221 ;
     RECT  2.304 152.203 2.697 152.249 ;
     RECT  42.372 152.149 42.39 152.339 ;
     RECT  45.615 126.527 45.897 152.347 ;
     RECT  7.704 152.105 8.097 152.375 ;
     RECT  46.8 152.311 46.818 152.411 ;
     RECT  45 152.347 45.897 152.447 ;
     RECT  40.215 152.221 41.022 152.491 ;
     RECT  10.26 152.347 10.386 152.519 ;
     RECT  83.415 151.771 84.402 152.573 ;
     RECT  2.415 152.249 2.697 152.581 ;
     RECT  40.215 152.491 41.13 152.609 ;
     RECT  2.415 152.581 2.79 152.621 ;
     RECT  37.044 152.311 37.062 152.681 ;
     RECT  51.015 144.779 51.297 152.761 ;
     RECT  0.108 152.827 0.126 152.879 ;
     RECT  10.26 152.519 10.278 152.879 ;
     RECT  38.772 152.725 38.79 152.879 ;
     RECT  40.215 152.609 41.022 152.879 ;
     RECT  41.94 152.711 42.102 152.879 ;
     RECT  86.292 152.203 86.31 152.879 ;
     RECT  3.96 152.851 3.978 152.909 ;
     RECT  51.015 152.761 51.426 152.909 ;
     RECT  83.415 152.573 83.826 152.909 ;
     RECT  20.124 152.491 20.538 152.915 ;
     RECT  20.52 152.915 20.538 153.149 ;
     RECT  7.815 152.375 8.097 153.163 ;
     RECT  18.615 148.289 18.897 153.265 ;
     RECT  41.94 152.879 41.958 153.341 ;
     RECT  18.615 153.265 19.746 153.419 ;
     RECT  7.416 153.163 8.097 153.451 ;
     RECT  40.215 152.879 40.986 153.571 ;
     RECT  39.6 153.571 40.986 153.725 ;
     RECT  19.62 153.419 19.746 153.931 ;
     RECT  34.815 125.753 35.097 153.967 ;
     RECT  19.62 153.931 20.286 154.031 ;
     RECT  34.776 153.967 35.097 154.067 ;
     RECT  39.42 153.967 39.438 154.075 ;
     RECT  3.96 154.075 3.978 154.139 ;
     RECT  0.144 154.111 0.162 154.157 ;
     RECT  10.044 154.111 10.062 154.229 ;
     RECT  7.416 153.451 8.154 154.265 ;
     RECT  19.62 154.031 19.638 154.265 ;
     RECT  39.24 154.075 39.438 154.265 ;
     RECT  2.415 152.621 2.697 154.381 ;
     RECT  42.084 154.345 42.102 154.381 ;
     RECT  43.02 154.219 43.038 154.381 ;
     RECT  2.304 154.381 2.697 154.445 ;
     RECT  21.096 154.471 21.114 154.507 ;
     RECT  39.24 154.265 39.366 154.507 ;
     RECT  42.084 154.381 43.182 154.535 ;
     RECT  38.772 154.507 39.366 154.607 ;
     RECT  42.084 154.535 42.102 154.607 ;
     RECT  21.096 154.507 21.294 154.643 ;
     RECT  51.015 152.909 51.297 154.651 ;
     RECT  21.276 154.643 21.294 154.679 ;
     RECT  43.056 154.535 43.182 154.769 ;
     RECT  34.815 154.067 35.097 154.921 ;
     RECT  50.472 154.651 51.297 154.921 ;
     RECT  7.416 154.265 8.097 155.035 ;
     RECT  43.38 154.921 43.398 155.035 ;
     RECT  10.332 154.921 10.35 155.039 ;
     RECT  34.776 154.921 35.097 155.039 ;
     RECT  43.38 155.035 43.578 155.039 ;
     RECT  50.4 154.921 51.297 155.069 ;
     RECT  7.416 155.035 8.154 155.075 ;
     RECT  39.348 154.607 39.366 155.075 ;
     RECT  20.16 154.849 20.178 155.155 ;
     RECT  20.16 155.155 20.25 155.309 ;
     RECT  85.5 153.121 85.518 155.405 ;
     RECT  40.215 153.725 40.986 155.425 ;
     RECT  40.14 155.425 40.986 155.461 ;
     RECT  10.26 155.461 10.278 155.579 ;
     RECT  40.14 155.461 41.022 155.579 ;
     RECT  20.124 155.461 20.142 155.615 ;
     RECT  43.56 155.039 43.578 155.731 ;
     RECT  42.192 155.587 42.21 155.759 ;
     RECT  46.656 155.659 46.674 155.759 ;
     RECT  43.56 155.731 43.722 155.849 ;
     RECT  7.815 155.075 8.154 155.885 ;
     RECT  43.56 155.849 43.578 155.885 ;
     RECT  2.415 154.445 2.697 155.992 ;
     RECT  21.636 155.821 21.654 155.993 ;
     RECT  7.815 155.885 8.097 155.995 ;
     RECT  2.304 155.992 2.697 156.029 ;
     RECT  7.704 155.995 8.097 156.155 ;
     RECT  40.14 155.579 40.986 156.271 ;
     RECT  20.052 156.271 20.07 156.361 ;
     RECT  19.836 156.361 20.07 156.389 ;
     RECT  84.888 156.331 84.906 156.389 ;
     RECT  39.6 156.271 40.986 156.533 ;
     RECT  19.836 156.389 19.998 156.631 ;
     RECT  0.108 156.331 0.126 156.659 ;
     RECT  86.292 155.995 86.31 156.659 ;
     RECT  3.96 156.361 3.978 156.701 ;
     RECT  19.728 156.631 19.998 156.731 ;
     RECT  39.6 156.533 40.878 156.731 ;
     RECT  38.772 155.731 38.79 157.081 ;
     RECT  39.6 156.731 40.734 157.081 ;
     RECT  18.615 153.419 18.897 157.207 ;
     RECT  38.772 157.081 40.734 157.235 ;
     RECT  7.815 156.155 8.097 157.243 ;
     RECT  85.5 156.901 85.518 157.277 ;
     RECT  18.615 157.207 18.954 157.469 ;
     RECT  7.416 157.243 8.097 157.505 ;
     RECT  39.924 157.235 40.734 157.505 ;
     RECT  84.924 157.441 84.942 157.613 ;
     RECT  19.98 156.731 19.998 157.621 ;
     RECT  40.14 157.505 40.734 157.621 ;
     RECT  38.772 157.235 38.79 157.739 ;
     RECT  40.14 157.621 40.986 157.739 ;
     RECT  10.26 157.621 10.278 157.891 ;
     RECT  19.98 157.621 20.142 157.891 ;
     RECT  10.044 157.891 10.278 158.009 ;
     RECT  0.108 157.915 0.126 158.045 ;
     RECT  19.692 157.891 20.142 158.045 ;
     RECT  39.276 157.981 39.294 158.081 ;
     RECT  2.415 156.029 2.697 158.161 ;
     RECT  2.304 158.161 2.697 158.237 ;
     RECT  20.016 158.045 20.142 158.251 ;
     RECT  10.26 158.009 10.278 158.279 ;
     RECT  7.704 157.505 8.097 158.315 ;
     RECT  20.016 158.251 20.214 158.315 ;
     RECT  40.14 157.739 40.77 158.315 ;
     RECT  20.196 158.315 20.214 158.351 ;
     RECT  51.015 155.069 51.297 158.557 ;
     RECT  86.292 157.915 86.31 158.585 ;
     RECT  42.012 158.521 42.03 158.665 ;
     RECT  40.215 158.315 40.77 158.701 ;
     RECT  42.804 158.665 42.966 158.717 ;
     RECT  43.776 158.629 43.794 158.729 ;
     RECT  51.015 158.557 51.534 158.729 ;
     RECT  42.948 158.717 42.966 158.819 ;
     RECT  7.815 158.315 8.097 158.827 ;
     RECT  20.232 158.665 20.25 158.855 ;
     RECT  41.832 158.665 42.03 158.855 ;
     RECT  41.832 158.855 41.85 158.927 ;
     RECT  7.815 158.827 8.55 158.963 ;
     RECT  40.215 158.701 40.878 159.205 ;
     RECT  39.78 159.205 40.878 159.359 ;
     RECT  40.104 159.359 40.878 159.403 ;
     RECT  7.815 158.963 8.097 159.499 ;
     RECT  19.908 159.331 19.926 159.503 ;
     RECT  40.104 159.403 40.95 159.595 ;
     RECT  38.772 158.791 38.79 159.629 ;
     RECT  3.96 159.739 3.978 159.809 ;
     RECT  85.5 158.521 85.518 159.871 ;
     RECT  20.052 159.781 20.07 159.935 ;
     RECT  40.104 159.595 41.058 160.015 ;
     RECT  40.104 160.015 41.094 160.051 ;
     RECT  18.615 157.469 18.897 160.141 ;
     RECT  0.108 159.781 0.126 160.157 ;
     RECT  84.924 159.871 85.518 160.157 ;
     RECT  40.104 160.051 41.238 160.169 ;
     RECT  7.416 159.499 8.097 160.205 ;
     RECT  38.952 160.141 38.97 160.241 ;
     RECT  2.415 158.237 2.697 160.411 ;
     RECT  40.104 160.169 40.914 160.411 ;
     RECT  85.5 160.157 85.518 160.445 ;
     RECT  2.304 160.411 2.697 160.448 ;
     RECT  7.815 160.205 8.097 160.507 ;
     RECT  6.84 160.411 6.858 160.541 ;
     RECT  39.996 160.411 40.914 160.583 ;
     RECT  20.016 160.447 20.034 160.619 ;
     RECT  51.015 158.729 51.297 160.681 ;
     RECT  10.26 159.601 10.278 160.709 ;
     RECT  18.615 160.141 18.954 160.717 ;
     RECT  40.176 160.583 40.914 160.745 ;
     RECT  50.652 160.681 51.297 160.781 ;
     RECT  39.348 160.681 39.438 161.095 ;
     RECT  84.924 160.987 84.942 161.117 ;
     RECT  52.92 160.987 52.938 161.159 ;
     RECT  40.215 160.745 40.914 161.249 ;
     RECT  7.815 160.507 8.154 161.285 ;
     RECT  18.615 160.717 19.638 161.285 ;
     RECT  39.24 161.095 39.438 161.285 ;
     RECT  40.215 161.249 40.554 161.309 ;
     RECT  43.488 161.257 43.506 161.309 ;
     RECT  39.24 161.285 39.366 161.321 ;
     RECT  41.616 161.293 41.634 161.429 ;
     RECT  46.764 161.371 46.782 161.429 ;
     RECT  21.564 161.401 21.582 161.491 ;
     RECT  21.348 161.491 21.582 161.519 ;
     RECT  43.236 161.401 43.434 161.519 ;
     RECT  43.236 161.519 43.254 161.555 ;
     RECT  21.348 161.519 21.366 161.591 ;
     RECT  39.24 161.321 39.33 161.635 ;
     RECT  2.415 160.448 2.697 161.659 ;
     RECT  2.415 161.659 2.79 161.699 ;
     RECT  10.044 161.131 10.062 161.789 ;
     RECT  39.132 161.635 39.33 161.789 ;
     RECT  18.615 161.285 19.602 161.825 ;
     RECT  39.312 161.789 39.33 161.825 ;
     RECT  48.672 161.833 48.69 161.933 ;
     RECT  2.415 161.699 2.697 161.995 ;
     RECT  86.292 161.707 86.31 162.029 ;
     RECT  40.215 161.309 40.497 162.031 ;
     RECT  7.815 161.285 8.097 162.043 ;
     RECT  40.215 162.031 40.554 162.043 ;
     RECT  2.304 161.995 2.697 162.059 ;
     RECT  40.215 162.043 40.914 162.211 ;
     RECT  41.652 161.755 41.922 162.211 ;
     RECT  10.368 162.067 10.386 162.239 ;
     RECT  40.215 162.211 41.922 162.329 ;
     RECT  7.704 162.043 8.097 162.331 ;
     RECT  40.215 162.329 41.742 162.409 ;
     RECT  85.5 162.301 85.518 162.571 ;
     RECT  7.416 162.331 8.097 162.619 ;
     RECT  39.996 162.409 41.742 162.635 ;
     RECT  84.924 162.571 85.518 162.653 ;
     RECT  38.772 162.571 38.79 162.707 ;
     RECT  20.664 162.715 20.682 162.869 ;
     RECT  85.5 162.653 85.518 162.989 ;
     RECT  40.215 162.635 41.742 163.139 ;
     RECT  7.416 162.619 8.154 163.175 ;
     RECT  10.368 163.111 10.386 163.175 ;
     RECT  40.215 163.139 41.562 163.175 ;
     RECT  10.224 163.291 10.242 163.409 ;
     RECT  43.056 163.291 43.074 163.409 ;
     RECT  47.916 163.291 47.934 163.409 ;
     RECT  7.815 163.175 8.154 163.445 ;
     RECT  20.016 163.291 20.214 163.589 ;
     RECT  10.044 163.651 10.17 163.751 ;
     RECT  39.24 163.651 39.258 163.823 ;
     RECT  20.016 163.589 20.07 163.831 ;
     RECT  0.108 163.291 0.126 163.949 ;
     RECT  10.152 163.751 10.17 163.949 ;
     RECT  86.292 163.291 86.31 163.949 ;
     RECT  3.96 163.243 3.978 163.997 ;
     RECT  40.215 163.175 41.094 164.101 ;
     RECT  2.415 162.059 2.697 164.191 ;
     RECT  40.215 164.101 41.202 164.191 ;
     RECT  40.104 164.191 41.202 164.203 ;
     RECT  2.304 164.191 2.697 164.237 ;
     RECT  7.815 163.445 8.097 164.299 ;
     RECT  6.84 164.203 6.858 164.333 ;
     RECT  40.104 164.203 41.85 164.363 ;
     RECT  40.215 164.363 41.85 164.371 ;
     RECT  19.8 163.831 20.07 164.399 ;
     RECT  10.26 164.371 10.278 164.489 ;
     RECT  7.815 164.299 8.154 164.539 ;
     RECT  20.304 164.461 20.322 164.561 ;
     RECT  18.615 161.825 18.897 164.605 ;
     RECT  18.615 164.605 19.422 164.759 ;
     RECT  85.5 164.191 85.518 164.875 ;
     RECT  40.215 164.371 41.994 164.911 ;
     RECT  51.015 160.781 51.297 165.001 ;
     RECT  20.376 164.911 20.394 165.029 ;
     RECT  40.215 164.911 43.11 165.029 ;
     RECT  49.716 164.911 49.734 165.029 ;
     RECT  7.416 164.539 8.154 165.065 ;
     RECT  84.888 164.875 85.518 165.065 ;
     RECT  51.015 165.001 51.354 165.137 ;
     RECT  40.215 165.029 42.354 165.145 ;
     RECT  2.415 164.237 2.697 165.163 ;
     RECT  85.5 165.065 85.518 165.197 ;
     RECT  2.304 165.163 2.697 165.209 ;
     RECT  14.832 165.181 14.85 165.299 ;
     RECT  40.104 165.145 42.354 165.299 ;
     RECT  7.416 165.065 8.097 165.335 ;
     RECT  2.415 165.209 2.697 165.541 ;
     RECT  40.215 165.299 42.354 165.569 ;
     RECT  2.415 165.541 2.79 165.581 ;
     RECT  0.144 165.787 0.162 165.839 ;
     RECT  10.26 165.451 10.278 165.839 ;
     RECT  40.215 165.569 41.094 165.839 ;
     RECT  47.916 165.721 47.934 165.839 ;
     RECT  86.292 165.499 86.31 165.839 ;
     RECT  3.96 165.811 3.978 165.869 ;
     RECT  20.052 165.451 20.07 165.875 ;
     RECT  41.904 165.569 42.354 165.991 ;
     RECT  41.904 165.991 42.426 166.109 ;
     RECT  49.104 165.991 49.122 166.109 ;
     RECT  41.904 166.109 41.922 166.402 ;
     RECT  7.815 165.335 8.097 166.459 ;
     RECT  49.68 166.459 49.698 166.559 ;
     RECT  20.232 166.225 20.25 166.621 ;
     RECT  20.232 166.621 20.394 166.721 ;
     RECT  38.772 166.657 38.862 166.801 ;
     RECT  40.215 165.839 40.95 166.801 ;
     RECT  38.772 166.801 41.094 166.955 ;
     RECT  83.415 152.909 83.697 167.035 ;
     RECT  3.96 167.035 3.978 167.099 ;
     RECT  49.572 167.035 49.59 167.099 ;
     RECT  83.415 167.035 83.826 167.099 ;
     RECT  0.108 167.071 0.126 167.117 ;
     RECT  86.292 167.071 86.31 167.117 ;
     RECT  20.052 166.801 20.07 167.161 ;
     RECT  40.215 166.955 41.094 167.179 ;
     RECT  7.815 166.459 8.154 167.225 ;
     RECT  40.215 167.179 41.202 167.225 ;
     RECT  19.836 167.161 20.07 167.261 ;
     RECT  7.815 167.225 8.097 167.323 ;
     RECT  2.415 165.581 2.697 167.341 ;
     RECT  2.304 167.341 2.697 167.405 ;
     RECT  51.015 165.137 51.297 167.431 ;
     RECT  38.772 166.955 39.33 167.459 ;
     RECT  50.688 167.431 51.297 167.707 ;
     RECT  10.26 166.801 10.278 167.729 ;
     RECT  40.215 167.225 41.13 167.729 ;
     RECT  20.052 167.261 20.07 167.765 ;
     RECT  50.688 167.707 51.39 167.837 ;
     RECT  50.688 167.837 51.297 167.881 ;
     RECT  41.868 167.881 41.886 167.999 ;
     RECT  50.292 167.881 51.297 167.999 ;
     RECT  7.704 167.323 8.097 168.043 ;
     RECT  18.615 164.759 18.897 168.115 ;
     RECT  38.772 167.459 38.79 168.143 ;
     RECT  18.615 168.115 19.422 168.269 ;
     RECT  40.215 167.729 41.058 168.277 ;
     RECT  20.268 168.421 20.286 168.511 ;
     RECT  20.052 168.511 20.286 168.539 ;
     RECT  40.104 168.277 41.058 168.691 ;
     RECT  85.5 166.081 85.518 168.701 ;
     RECT  38.196 168.655 38.214 168.809 ;
     RECT  7.416 168.043 8.097 168.845 ;
     RECT  2.415 167.405 2.697 168.952 ;
     RECT  40.104 168.691 41.202 168.961 ;
     RECT  2.304 168.952 2.697 168.989 ;
     RECT  20.052 168.539 20.106 169.051 ;
     RECT  85.464 168.955 85.482 169.079 ;
     RECT  7.704 168.845 8.097 169.115 ;
     RECT  39.78 168.961 41.202 169.159 ;
     RECT  42.228 169.003 42.246 169.159 ;
     RECT  43.884 169.051 43.902 169.159 ;
     RECT  39.78 169.159 42.246 169.195 ;
     RECT  19.908 169.051 20.106 169.223 ;
     RECT  39.348 169.195 42.246 169.231 ;
     RECT  43.884 169.159 44.514 169.259 ;
     RECT  47.988 169.087 48.006 169.259 ;
     RECT  19.944 169.223 20.106 169.321 ;
     RECT  83.415 167.099 83.697 169.321 ;
     RECT  39.348 169.231 42.39 169.349 ;
     RECT  49.14 169.231 49.158 169.373 ;
     RECT  19.944 169.321 20.502 169.421 ;
     RECT  0.108 169.291 0.126 169.619 ;
     RECT  10.224 169.501 10.242 169.619 ;
     RECT  86.292 169.291 86.31 169.619 ;
     RECT  3.96 169.321 3.978 169.661 ;
     RECT  39.816 169.349 42.39 169.691 ;
     RECT  83.415 169.321 83.826 169.861 ;
     RECT  83.415 169.861 84.402 169.949 ;
     RECT  39.924 169.691 42.39 169.961 ;
     RECT  19.944 169.421 20.034 170.159 ;
     RECT  40.14 169.961 42.39 170.159 ;
     RECT  43.884 169.259 43.902 170.159 ;
     RECT  47.88 170.041 47.898 170.159 ;
     RECT  7.815 169.115 8.097 170.251 ;
     RECT  85.5 170.131 85.518 170.285 ;
     RECT  45.615 152.447 45.897 170.401 ;
     RECT  14.832 170.311 14.85 170.429 ;
     RECT  40.14 170.159 41.454 170.429 ;
     RECT  43.2 170.392 43.362 170.429 ;
     RECT  7.416 170.251 8.097 170.465 ;
     RECT  19.872 170.311 19.89 170.465 ;
     RECT  40.14 170.429 41.238 170.465 ;
     RECT  45.615 170.401 46.35 170.573 ;
     RECT  83.415 169.949 83.697 170.671 ;
     RECT  42.192 170.159 42.39 170.699 ;
     RECT  43.344 170.429 43.362 170.699 ;
     RECT  49.392 170.581 49.41 170.699 ;
     RECT  20.988 170.671 21.006 170.707 ;
     RECT  38.772 170.545 38.79 170.707 ;
     RECT  38.772 170.707 39.33 170.735 ;
     RECT  42.264 170.699 42.39 170.735 ;
     RECT  7.704 170.465 8.097 170.827 ;
     RECT  39.312 170.735 39.33 170.827 ;
     RECT  40.14 170.465 40.914 170.827 ;
     RECT  20.988 170.707 21.186 170.843 ;
     RECT  3.96 170.827 3.978 170.879 ;
     RECT  21.168 170.843 21.186 170.879 ;
     RECT  0.144 170.851 0.162 170.909 ;
     RECT  83.415 170.671 84.402 170.909 ;
     RECT  7.704 170.827 8.154 171.005 ;
     RECT  49.572 170.941 49.59 171.053 ;
     RECT  56.415 141.449 56.697 171.112 ;
     RECT  67.215 141.449 67.497 171.112 ;
     RECT  78.015 141.449 78.297 171.112 ;
     RECT  19.908 170.941 19.926 171.113 ;
     RECT  83.415 170.909 83.697 171.115 ;
     RECT  2.415 168.989 2.697 171.121 ;
     RECT  56.304 171.112 56.697 171.149 ;
     RECT  67.104 171.112 67.497 171.149 ;
     RECT  77.904 171.112 78.297 171.149 ;
     RECT  83.304 171.115 83.697 171.155 ;
     RECT  2.304 171.121 2.697 171.197 ;
     RECT  39.312 170.827 40.914 171.239 ;
     RECT  42.408 171.121 42.426 171.239 ;
     RECT  7.704 171.005 8.097 171.499 ;
     RECT  20.196 171.391 20.214 171.509 ;
     RECT  39.924 171.239 40.914 171.545 ;
     RECT  40.14 171.545 40.914 171.625 ;
     RECT  7.416 171.499 8.097 171.815 ;
     RECT  7.815 171.815 8.097 171.835 ;
     RECT  85.5 171.481 85.518 171.869 ;
     RECT  20.16 171.895 20.178 172.049 ;
     RECT  7.815 171.835 8.154 172.085 ;
     RECT  40.14 171.625 40.986 172.123 ;
     RECT  48.348 172.093 48.366 172.157 ;
     RECT  40.14 172.123 41.31 172.355 ;
     RECT  42.948 172.471 42.966 172.597 ;
     RECT  38.772 171.751 38.79 172.661 ;
     RECT  42.948 172.597 43.038 172.669 ;
     RECT  42.3 172.669 43.038 172.697 ;
     RECT  83.415 171.155 83.697 172.699 ;
     RECT  48.6 172.471 48.762 172.769 ;
     RECT  83.415 172.699 83.826 172.769 ;
     RECT  10.368 172.597 10.386 173.039 ;
     RECT  40.215 172.355 41.31 173.101 ;
     RECT  42.3 172.697 42.462 173.101 ;
     RECT  0.108 172.741 0.126 173.129 ;
     RECT  42.156 173.101 42.462 173.129 ;
     RECT  49.212 173.011 49.23 173.129 ;
     RECT  86.292 172.459 86.31 173.129 ;
     RECT  3.96 172.699 3.978 173.165 ;
     RECT  19.908 173.101 19.926 173.273 ;
     RECT  39.78 173.101 41.31 173.273 ;
     RECT  39.996 173.273 41.31 173.275 ;
     RECT  42.156 173.129 42.174 173.275 ;
     RECT  7.815 172.085 8.097 173.419 ;
     RECT  39.996 173.275 42.174 173.543 ;
     RECT  20.016 173.407 20.034 173.579 ;
     RECT  10.26 173.551 10.278 173.669 ;
     RECT  7.815 173.419 8.154 173.707 ;
     RECT  40.212 173.543 42.174 174.209 ;
     RECT  7.416 173.707 8.154 174.245 ;
     RECT  40.215 174.209 42.174 174.479 ;
     RECT  7.416 174.245 8.097 174.515 ;
     RECT  41.616 174.479 42.174 174.515 ;
     RECT  20.664 174.451 20.862 174.551 ;
     RECT  38.772 174.451 38.79 174.551 ;
     RECT  2.415 171.197 2.697 174.619 ;
     RECT  20.664 174.551 20.682 174.623 ;
     RECT  18.615 168.269 18.897 174.631 ;
     RECT  2.415 174.619 2.79 174.659 ;
     RECT  42.156 174.515 42.174 174.659 ;
     RECT  10.008 174.631 10.026 174.749 ;
     RECT  49.428 174.631 49.446 174.749 ;
     RECT  18.615 174.631 19.53 174.785 ;
     RECT  2.415 174.659 2.697 174.991 ;
     RECT  39.348 174.901 39.366 174.991 ;
     RECT  40.215 174.479 40.806 174.991 ;
     RECT  56.415 171.149 56.697 174.991 ;
     RECT  67.215 171.149 67.497 174.991 ;
     RECT  78.015 171.149 78.297 174.991 ;
     RECT  39.348 174.991 40.806 175.019 ;
     RECT  47.304 174.901 47.322 175.019 ;
     RECT  2.304 174.991 2.697 175.037 ;
     RECT  56.304 174.991 56.697 175.037 ;
     RECT  67.104 174.991 67.497 175.037 ;
     RECT  77.904 174.991 78.297 175.037 ;
     RECT  7.815 174.515 8.097 175.099 ;
     RECT  6.84 175.003 6.858 175.133 ;
     RECT  19.908 175.135 19.926 175.289 ;
     RECT  7.815 175.099 8.154 175.291 ;
     RECT  39.348 175.019 40.698 175.325 ;
     RECT  20.124 175.405 20.142 175.559 ;
     RECT  7.416 175.291 8.154 175.595 ;
     RECT  40.212 175.325 40.698 175.739 ;
     RECT  49.68 175.627 49.698 175.739 ;
     RECT  20.304 175.711 20.322 175.829 ;
     RECT  39.348 175.325 39.366 175.865 ;
     RECT  43.38 175.909 43.398 175.945 ;
     RECT  43.38 175.945 44.01 175.981 ;
     RECT  43.38 175.981 44.082 176.009 ;
     RECT  21.924 175.981 21.942 176.071 ;
     RECT  21.744 176.071 21.942 176.099 ;
     RECT  43.596 176.009 44.082 176.135 ;
     RECT  40.215 175.739 40.698 176.155 ;
     RECT  83.415 172.769 83.697 176.203 ;
     RECT  48.456 176.107 48.474 176.237 ;
     RECT  21.744 176.099 21.762 176.243 ;
     RECT  44.064 176.135 44.082 176.279 ;
     RECT  83.415 176.203 83.826 176.279 ;
     RECT  7.815 175.595 8.154 176.405 ;
     RECT  40.215 176.155 41.418 176.521 ;
     RECT  20.736 176.521 20.754 176.639 ;
     RECT  40.215 176.521 41.562 176.683 ;
     RECT  40.212 176.683 41.562 176.881 ;
     RECT  0.108 176.251 0.126 176.909 ;
     RECT  10.224 176.791 10.242 176.909 ;
     RECT  86.292 176.251 86.31 176.909 ;
     RECT  19.944 176.791 19.962 176.945 ;
     RECT  3.96 176.203 3.978 176.957 ;
     RECT  39.888 176.881 41.562 177.053 ;
     RECT  7.815 176.405 8.097 177.211 ;
     RECT  40.068 177.053 41.562 177.215 ;
     RECT  18.615 174.785 18.897 177.223 ;
     RECT  41.544 177.215 41.562 177.251 ;
     RECT  18.615 177.223 18.954 177.449 ;
     RECT  7.416 177.211 8.097 177.485 ;
     RECT  20.052 177.565 20.07 177.719 ;
     RECT  7.704 177.485 8.097 177.835 ;
     RECT  51.015 167.999 51.297 177.835 ;
     RECT  50.436 177.835 51.297 177.899 ;
     RECT  40.215 177.215 40.77 177.989 ;
     RECT  7.704 177.835 8.154 178.025 ;
     RECT  2.415 175.037 2.697 178.123 ;
     RECT  42.156 177.997 42.174 178.141 ;
     RECT  43.236 178.105 43.254 178.141 ;
     RECT  2.304 178.123 2.697 178.169 ;
     RECT  42.156 178.141 43.398 178.169 ;
     RECT  21.276 178.141 21.294 178.231 ;
     RECT  21.096 178.231 21.294 178.259 ;
     RECT  42.84 178.169 43.398 178.259 ;
     RECT  42.84 178.259 43.254 178.295 ;
     RECT  43.128 178.295 43.254 178.367 ;
     RECT  43.236 178.367 43.254 178.397 ;
     RECT  21.096 178.259 21.114 178.403 ;
     RECT  40.215 177.989 40.698 178.411 ;
     RECT  51.015 177.899 51.297 178.411 ;
     RECT  83.415 176.279 83.697 178.459 ;
     RECT  2.415 178.169 2.697 178.501 ;
     RECT  38.772 176.107 38.79 178.529 ;
     RECT  83.415 178.459 83.79 178.529 ;
     RECT  2.415 178.501 2.79 178.541 ;
     RECT  51.015 178.411 51.39 178.541 ;
     RECT  19.908 178.501 19.926 178.673 ;
     RECT  39.96 178.411 40.698 178.771 ;
     RECT  7.704 178.025 8.097 178.795 ;
     RECT  85.5 173.371 85.518 178.829 ;
     RECT  18.615 177.449 18.897 178.915 ;
     RECT  18.615 178.915 18.954 179.069 ;
     RECT  84.924 179.041 84.942 179.117 ;
     RECT  39.924 178.771 40.698 179.221 ;
     RECT  83.415 178.529 83.697 179.311 ;
     RECT  19.836 179.185 19.854 179.339 ;
     RECT  39.852 179.221 40.698 179.375 ;
     RECT  44.028 179.563 44.046 179.725 ;
     RECT  40.212 179.375 40.698 179.753 ;
     RECT  43.596 179.725 44.046 179.761 ;
     RECT  42.768 179.689 42.786 179.789 ;
     RECT  21.924 179.761 21.942 179.851 ;
     RECT  21.744 179.851 21.942 179.879 ;
     RECT  43.596 179.761 44.226 179.915 ;
     RECT  21.744 179.879 21.762 180.023 ;
     RECT  44.208 179.915 44.226 180.059 ;
     RECT  83.415 179.311 84.402 180.077 ;
     RECT  40.215 179.753 40.698 180.265 ;
     RECT  40.215 180.265 40.842 180.301 ;
     RECT  85.5 179.581 85.518 180.379 ;
     RECT  0.108 180.031 0.126 180.419 ;
     RECT  10.044 180.121 10.062 180.419 ;
     RECT  19.692 180.301 19.71 180.455 ;
     RECT  84.888 180.379 85.518 180.455 ;
     RECT  3.96 179.995 3.978 180.461 ;
     RECT  39.276 180.121 39.294 180.491 ;
     RECT  42.804 180.427 42.822 180.527 ;
     RECT  40.215 180.301 41.13 180.571 ;
     RECT  40.14 180.571 41.13 180.661 ;
     RECT  42.264 180.571 42.282 180.689 ;
     RECT  39.6 180.661 41.13 180.833 ;
     RECT  7.416 178.795 8.097 180.995 ;
     RECT  7.815 180.995 8.097 181.003 ;
     RECT  20.232 180.805 20.25 181.075 ;
     RECT  20.232 181.075 20.358 181.229 ;
     RECT  51.015 178.541 51.297 181.291 ;
     RECT  50.76 181.291 51.297 181.409 ;
     RECT  39.924 180.833 41.13 181.435 ;
     RECT  10.152 181.381 10.17 181.499 ;
     RECT  38.196 181.237 38.214 181.499 ;
     RECT  19.8 181.381 20.142 181.535 ;
     RECT  39.924 181.435 41.166 181.535 ;
     RECT  40.176 181.535 41.166 181.651 ;
     RECT  7.815 181.003 8.154 181.805 ;
     RECT  10.26 181.741 10.386 181.805 ;
     RECT  49.968 181.813 49.986 181.853 ;
     RECT  56.415 175.037 56.697 181.912 ;
     RECT  67.215 175.037 67.497 181.912 ;
     RECT  78.015 175.037 78.297 181.912 ;
     RECT  7.815 181.805 8.097 181.915 ;
     RECT  83.415 180.077 83.697 181.915 ;
     RECT  2.415 178.541 2.697 181.921 ;
     RECT  56.304 181.912 56.697 181.949 ;
     RECT  67.104 181.912 67.497 181.949 ;
     RECT  77.904 181.912 78.297 181.949 ;
     RECT  83.304 181.915 83.697 181.955 ;
     RECT  2.304 181.921 2.697 181.997 ;
     RECT  10.26 181.805 10.278 182.039 ;
     RECT  38.772 181.615 38.79 182.039 ;
     RECT  7.704 181.915 8.097 182.075 ;
     RECT  20.124 181.535 20.142 182.075 ;
     RECT  0.108 182.251 0.126 182.309 ;
     RECT  40.176 181.651 41.31 182.309 ;
     RECT  3.96 182.281 3.978 182.333 ;
     RECT  40.176 182.309 40.986 182.345 ;
     RECT  7.815 182.075 8.097 182.587 ;
     RECT  18.615 179.069 18.897 182.695 ;
     RECT  40.176 182.345 40.734 182.695 ;
     RECT  38.916 182.551 38.934 182.723 ;
     RECT  39.78 182.695 40.734 182.731 ;
     RECT  18.615 182.695 19.494 182.849 ;
     RECT  39.096 182.731 40.734 182.849 ;
     RECT  7.815 182.587 8.154 182.875 ;
     RECT  39.096 182.849 39.114 182.921 ;
     RECT  50.22 182.857 50.238 183.029 ;
     RECT  39.924 182.849 40.734 183.155 ;
     RECT  34.815 155.039 35.097 183.235 ;
     RECT  40.215 183.155 40.734 183.271 ;
     RECT  10.152 183.271 10.17 183.389 ;
     RECT  34.776 183.235 35.097 183.389 ;
     RECT  19.8 183.271 19.818 183.425 ;
     RECT  38.772 183.505 38.79 183.659 ;
     RECT  7.416 182.875 8.154 183.695 ;
     RECT  3.96 183.787 3.978 183.839 ;
     RECT  0.108 183.811 0.126 183.869 ;
     RECT  86.292 183.835 86.31 183.929 ;
     RECT  19.908 183.901 19.926 183.937 ;
     RECT  19.908 183.937 20.106 184.073 ;
     RECT  20.088 184.073 20.106 184.109 ;
     RECT  2.415 181.997 2.697 184.171 ;
     RECT  2.304 184.171 2.697 184.208 ;
     RECT  6.84 184.171 6.858 184.301 ;
     RECT  18.615 182.849 18.897 184.315 ;
     RECT  40.215 183.271 40.986 184.351 ;
     RECT  20.304 184.207 20.322 184.379 ;
     RECT  7.815 183.695 8.154 184.459 ;
     RECT  18.615 184.315 18.954 184.469 ;
     RECT  22.824 184.351 22.842 184.469 ;
     RECT  39.924 184.351 40.986 184.621 ;
     RECT  39.924 184.621 41.13 184.711 ;
     RECT  39.888 184.711 41.13 184.883 ;
     RECT  19.944 184.855 19.962 185.009 ;
     RECT  7.416 184.459 8.154 185.045 ;
     RECT  85.5 180.455 85.518 185.453 ;
     RECT  38.772 185.125 38.79 185.549 ;
     RECT  10.368 185.557 10.386 185.729 ;
     RECT  18.615 184.469 18.897 185.791 ;
     RECT  19.764 185.701 19.782 185.791 ;
     RECT  39.06 185.701 39.078 185.791 ;
     RECT  42.876 185.701 42.894 185.791 ;
     RECT  42.768 185.791 42.894 185.803 ;
     RECT  18.615 185.791 19.782 185.819 ;
     RECT  47.664 185.701 47.682 185.819 ;
     RECT  40.14 184.883 41.13 185.827 ;
     RECT  7.416 185.045 8.097 185.855 ;
     RECT  39.06 185.791 39.366 185.855 ;
     RECT  45.615 170.573 45.897 185.947 ;
     RECT  18.615 185.819 19.206 185.963 ;
     RECT  42.768 185.803 43.038 185.971 ;
     RECT  45.615 185.947 46.026 185.999 ;
     RECT  21.384 185.971 21.402 186.061 ;
     RECT  86.292 185.755 86.31 186.077 ;
     RECT  0.108 185.659 0.126 186.089 ;
     RECT  21.204 186.061 21.402 186.089 ;
     RECT  42.768 185.971 43.182 186.089 ;
     RECT  3.96 186.061 3.978 186.125 ;
     RECT  9.144 186.088 9.162 186.125 ;
     RECT  39.348 185.855 39.366 186.125 ;
     RECT  42.768 186.089 42.786 186.125 ;
     RECT  21.204 186.089 21.222 186.233 ;
     RECT  40.14 185.827 41.202 186.241 ;
     RECT  39.456 186.241 41.202 186.269 ;
     RECT  51.015 181.409 51.297 186.331 ;
     RECT  18.615 185.963 18.897 186.367 ;
     RECT  7.815 185.855 8.097 186.379 ;
     RECT  39.456 186.269 40.734 186.503 ;
     RECT  18.252 186.367 18.897 186.629 ;
     RECT  37.908 186.241 37.926 186.629 ;
     RECT  7.815 186.379 8.154 186.665 ;
     RECT  39.924 186.503 40.734 186.665 ;
     RECT  84.924 186.601 84.942 186.701 ;
     RECT  41.472 186.709 41.67 186.781 ;
     RECT  20.124 186.745 20.142 186.899 ;
     RECT  41.472 186.781 41.85 186.899 ;
     RECT  40.104 186.665 40.734 186.971 ;
     RECT  41.832 186.899 41.85 186.971 ;
     RECT  50.652 186.331 51.297 187.003 ;
     RECT  10.08 187.003 10.098 187.051 ;
     RECT  50.436 187.003 51.297 187.079 ;
     RECT  10.08 187.051 10.278 187.205 ;
     RECT  42.66 187.141 42.678 187.285 ;
     RECT  10.26 187.205 10.278 187.291 ;
     RECT  42.66 187.285 42.93 187.321 ;
     RECT  3.96 187.291 3.978 187.349 ;
     RECT  38.772 187.249 38.79 187.349 ;
     RECT  0.108 187.321 0.126 187.373 ;
     RECT  85.5 187.141 85.518 187.373 ;
     RECT  21.456 187.321 21.474 187.411 ;
     RECT  21.24 187.411 21.474 187.439 ;
     RECT  41.976 187.321 43.002 187.439 ;
     RECT  10.26 187.291 10.674 187.475 ;
     RECT  42.66 187.439 42.678 187.475 ;
     RECT  21.24 187.439 21.258 187.511 ;
     RECT  40.104 186.971 40.698 187.555 ;
     RECT  2.415 184.208 2.697 187.579 ;
     RECT  83.415 181.955 83.697 187.591 ;
     RECT  49.536 187.483 49.554 187.613 ;
     RECT  2.415 187.579 2.79 187.619 ;
     RECT  83.415 187.591 83.79 187.661 ;
     RECT  10.26 187.475 10.278 187.709 ;
     RECT  40.032 187.555 40.698 187.709 ;
     RECT  20.052 187.051 20.07 187.745 ;
     RECT  9.144 187.717 9.162 187.757 ;
     RECT  2.415 187.619 2.697 187.951 ;
     RECT  45.615 185.999 45.897 187.951 ;
     RECT  45.615 187.951 46.206 187.987 ;
     RECT  2.304 187.951 2.697 187.997 ;
     RECT  84.924 187.951 84.942 187.997 ;
     RECT  7.815 186.665 8.097 188.059 ;
     RECT  18.615 186.629 18.897 188.059 ;
     RECT  45.615 187.987 46.818 188.087 ;
     RECT  6.84 187.579 6.858 188.093 ;
     RECT  40.032 187.709 40.662 188.221 ;
     RECT  18.252 188.059 18.897 188.249 ;
     RECT  45.615 188.087 46.206 188.249 ;
     RECT  7.815 188.059 8.586 188.285 ;
     RECT  48.348 188.023 48.366 188.285 ;
     RECT  39.78 188.221 40.662 188.393 ;
     RECT  19.908 188.365 19.926 188.519 ;
     RECT  41.904 188.401 41.922 188.519 ;
     RECT  47.916 188.401 47.934 188.519 ;
     RECT  39.996 188.393 40.662 188.563 ;
     RECT  38.196 188.527 38.214 188.699 ;
     RECT  19.944 188.671 20.178 188.789 ;
     RECT  19.944 188.789 20.142 188.861 ;
     RECT  2.415 187.997 2.697 188.923 ;
     RECT  2.304 188.923 2.697 188.969 ;
     RECT  39.168 188.905 39.186 189.059 ;
     RECT  10.008 188.251 10.026 189.067 ;
     RECT  6.84 188.923 6.858 189.101 ;
     RECT  9.864 189.067 10.062 189.104 ;
     RECT  39.996 188.563 40.698 189.211 ;
     RECT  38.772 189.175 38.79 189.329 ;
     RECT  9.9 189.104 10.062 189.365 ;
     RECT  20.124 188.861 20.142 189.571 ;
     RECT  0.108 189.211 0.126 189.599 ;
     RECT  10.08 189.481 10.278 189.599 ;
     RECT  10.08 189.599 10.098 189.635 ;
     RECT  20.124 189.571 20.322 189.671 ;
     RECT  39.816 189.211 40.698 189.779 ;
     RECT  0.144 189.832 0.162 189.869 ;
     RECT  86.292 189.832 86.31 189.869 ;
     RECT  3.96 189.163 3.978 189.917 ;
     RECT  6.84 189.877 6.858 189.917 ;
     RECT  19.62 189.841 19.782 189.941 ;
     RECT  39.816 189.779 40.497 190.021 ;
     RECT  7.815 188.285 8.097 190.171 ;
     RECT  39.132 190.021 40.497 190.175 ;
     RECT  18.615 188.249 18.897 190.255 ;
     RECT  7.416 190.171 8.097 190.445 ;
     RECT  10.116 190.561 10.134 190.679 ;
     RECT  3.996 190.507 4.014 190.715 ;
     RECT  19.692 189.941 19.782 190.715 ;
     RECT  39.348 190.175 40.497 190.723 ;
     RECT  19.728 190.715 19.782 190.831 ;
     RECT  14.832 190.831 14.85 190.949 ;
     RECT  19.728 190.831 20.178 190.949 ;
     RECT  18.615 190.255 18.954 190.985 ;
     RECT  56.415 181.949 56.697 191.083 ;
     RECT  67.215 181.949 67.497 191.083 ;
     RECT  78.015 181.949 78.297 191.083 ;
     RECT  83.415 187.661 83.697 191.083 ;
     RECT  2.415 188.969 2.697 191.101 ;
     RECT  39.348 190.723 40.554 191.101 ;
     RECT  48.492 191.083 48.51 191.129 ;
     RECT  56.304 191.083 56.697 191.129 ;
     RECT  67.104 191.083 67.497 191.129 ;
     RECT  77.904 191.083 78.297 191.129 ;
     RECT  83.304 191.083 83.697 191.129 ;
     RECT  2.304 191.101 2.697 191.165 ;
     RECT  39.348 191.101 40.698 191.219 ;
     RECT  6.84 190.795 6.858 191.261 ;
     RECT  19.728 190.949 19.746 191.291 ;
     RECT  42.264 190.939 42.282 191.371 ;
     RECT  85.5 188.491 85.518 191.453 ;
     RECT  2.415 191.165 2.697 191.461 ;
     RECT  42.264 191.371 42.426 191.489 ;
     RECT  20.664 191.461 20.682 191.497 ;
     RECT  2.415 191.461 2.79 191.501 ;
     RECT  9.144 191.227 9.162 191.525 ;
     RECT  38.772 191.335 38.79 191.525 ;
     RECT  39.708 191.219 40.554 191.525 ;
     RECT  41.472 191.371 41.49 191.525 ;
     RECT  51.015 187.079 51.297 191.641 ;
     RECT  20.664 191.497 20.862 191.669 ;
     RECT  83.415 191.129 83.697 191.731 ;
     RECT  7.815 190.445 8.097 191.755 ;
     RECT  41.868 191.641 41.886 191.759 ;
     RECT  51.015 191.641 51.498 191.759 ;
     RECT  39.708 191.525 40.497 191.939 ;
     RECT  2.415 191.501 2.697 191.987 ;
     RECT  13.215 143.069 13.497 191.987 ;
     RECT  18.615 190.985 18.897 191.987 ;
     RECT  24.015 15.629 24.297 191.987 ;
     RECT  29.415 64.625 29.697 191.987 ;
     RECT  34.815 183.389 35.097 191.987 ;
     RECT  40.104 191.939 40.497 191.987 ;
     RECT  45.615 188.249 45.897 191.987 ;
     RECT  51.015 191.759 51.297 191.987 ;
     RECT  56.415 191.129 56.697 191.987 ;
     RECT  61.815 126.653 62.097 191.987 ;
     RECT  67.215 191.129 67.497 191.987 ;
     RECT  72.615 2.413 72.897 191.987 ;
     RECT  78.015 191.129 78.297 191.987 ;
     RECT  20.088 191.911 20.178 192.029 ;
     RECT  51.015 191.987 51.174 192.029 ;
     RECT  7.815 191.755 8.154 192.043 ;
     RECT  40.104 191.987 40.305 192.065 ;
     RECT  86.292 191.755 86.31 192.065 ;
     RECT  83.415 191.731 83.826 192.077 ;
     RECT  7.815 192.043 8.226 192.101 ;
     RECT  14.832 192.001 14.85 192.101 ;
     RECT  38.88 192.001 38.898 192.101 ;
     RECT  51.015 192.029 51.105 192.181 ;
     RECT  20.16 192.029 20.178 192.209 ;
     RECT  49.032 192.037 49.05 192.209 ;
     RECT  50.724 192.181 51.105 192.221 ;
     RECT  2.415 191.987 2.505 192.257 ;
     RECT  7.815 192.101 7.905 192.257 ;
     RECT  13.215 191.987 13.305 192.257 ;
     RECT  18.615 191.987 18.705 192.257 ;
     RECT  24.015 191.987 24.105 192.257 ;
     RECT  29.415 191.987 29.505 192.257 ;
     RECT  34.815 191.987 34.905 192.257 ;
     RECT  40.215 192.065 40.305 192.257 ;
     RECT  45.615 191.987 45.705 192.257 ;
     RECT  51.015 192.221 51.105 192.257 ;
     RECT  56.415 191.987 56.505 192.257 ;
     RECT  61.815 191.987 61.905 192.257 ;
     RECT  67.215 191.987 67.305 192.257 ;
     RECT  72.615 191.987 72.705 192.257 ;
     RECT  78.015 191.987 78.105 192.257 ;
     RECT  83.415 192.077 83.505 192.257 ;
    LAYER M4 ;
     RECT  0.06 7.008 0.137 7.032 ;
     RECT  0.06 10.272 0.137 10.296 ;
     RECT  0.06 17.424 0.137 192.072 ;
     RECT  0.137 177.216 0.173 192.072 ;
     RECT  0.06 2.688 2.408 2.712 ;
     RECT  0.06 4.848 2.408 4.872 ;
     RECT  0.06 9.168 2.408 9.192 ;
     RECT  0.06 11.328 2.408 11.352 ;
     RECT  0.06 13.488 2.408 13.512 ;
     RECT  0.06 15.648 2.408 15.672 ;
     RECT  0.137 17.424 2.408 63.624 ;
     RECT  0.137 64.896 2.408 76.632 ;
     RECT  0.137 77.856 2.408 100.344 ;
     RECT  0.137 101.568 2.408 113.304 ;
     RECT  0.137 114.576 2.408 175.944 ;
     RECT  0.173 177.216 2.408 188.952 ;
     RECT  0.173 190.176 2.408 192.072 ;
     RECT  2.408 2.148 2.512 192.252 ;
     RECT  2.512 2.418 2.704 192.072 ;
     RECT  2.704 17.424 3.949 63.624 ;
     RECT  2.704 64.896 3.949 76.632 ;
     RECT  2.704 77.856 3.949 100.344 ;
     RECT  2.704 101.568 3.949 113.304 ;
     RECT  2.704 114.576 3.949 175.944 ;
     RECT  2.704 177.216 3.949 188.952 ;
     RECT  2.704 190.176 3.949 192.072 ;
     RECT  2.704 4.8 6.829 4.824 ;
     RECT  2.704 2.64 7.808 2.664 ;
     RECT  6.829 4.8 7.808 4.968 ;
     RECT  2.704 9.12 7.808 9.144 ;
     RECT  3.949 10.32 7.808 10.344 ;
     RECT  2.704 11.376 7.808 11.4 ;
     RECT  2.704 13.44 7.808 13.464 ;
     RECT  2.704 15.6 7.808 15.624 ;
     RECT  3.949 17.424 7.808 192.072 ;
     RECT  7.808 2.148 7.912 192.252 ;
     RECT  7.912 2.418 8.104 192.072 ;
     RECT  8.104 17.424 8.165 18.024 ;
     RECT  8.104 19.008 8.165 21.816 ;
     RECT  8.104 22.8 8.165 22.824 ;
     RECT  8.104 27.168 8.165 27.192 ;
     RECT  8.104 28.176 8.165 30.984 ;
     RECT  8.104 31.968 8.165 32.616 ;
     RECT  8.104 37.344 8.165 37.992 ;
     RECT  8.104 39.024 8.165 39.912 ;
     RECT  8.104 41.136 8.165 41.784 ;
     RECT  8.104 43.392 8.165 43.416 ;
     RECT  8.104 47.856 8.165 48.792 ;
     RECT  8.104 50.352 8.165 50.952 ;
     RECT  8.104 51.936 8.165 52.584 ;
     RECT  8.104 54.144 8.165 54.744 ;
     RECT  8.104 57.936 8.165 58.536 ;
     RECT  8.104 59.52 8.165 97.128 ;
     RECT  8.104 99.984 8.165 100.632 ;
     RECT  8.104 101.664 8.165 102.264 ;
     RECT  8.104 103.776 8.165 104.424 ;
     RECT  8.104 106.032 8.165 106.056 ;
     RECT  8.104 112.992 8.165 113.592 ;
     RECT  8.104 114.576 8.165 115.224 ;
     RECT  8.104 116.448 8.165 144.936 ;
     RECT  8.104 146.496 8.165 147.096 ;
     RECT  8.104 150.288 8.165 150.312 ;
     RECT  8.104 151.344 8.165 151.896 ;
     RECT  8.104 153.456 8.165 155.688 ;
     RECT  8.104 160.512 8.165 161.112 ;
     RECT  8.104 162.624 8.165 163.272 ;
     RECT  8.104 164.304 8.165 164.904 ;
     RECT  8.104 166.464 8.165 167.064 ;
     RECT  8.104 170.832 8.165 170.856 ;
     RECT  8.104 171.84 8.165 171.864 ;
     RECT  8.104 173.424 8.165 174.072 ;
     RECT  8.104 175.104 8.165 176.232 ;
     RECT  8.104 177.84 8.165 177.864 ;
     RECT  8.104 181.008 8.165 184.824 ;
     RECT  8.104 191.232 8.237 192.072 ;
     RECT  8.104 158.832 8.561 158.856 ;
     RECT  8.104 4.944 8.633 4.968 ;
     RECT  8.104 186.096 9.173 189.624 ;
     RECT  8.237 191.232 9.173 191.496 ;
     RECT  9.173 187.008 9.929 189.624 ;
     RECT  9.929 187.008 10.037 188.616 ;
     RECT  10.037 187.008 10.109 187.32 ;
     RECT  9.929 189.6 10.109 189.624 ;
     RECT  10.109 187.296 10.685 187.32 ;
     RECT  8.104 11.376 11.549 11.4 ;
     RECT  8.104 13.44 13.208 13.464 ;
     RECT  8.104 15.6 13.208 15.624 ;
     RECT  8.165 39.888 13.208 39.912 ;
     RECT  8.165 47.856 13.208 48.456 ;
     RECT  8.165 52.224 13.208 52.248 ;
     RECT  8.104 55.728 13.208 56.904 ;
     RECT  8.165 60.144 13.208 62.808 ;
     RECT  8.165 63.888 13.208 97.128 ;
     RECT  8.104 107.28 13.208 112.008 ;
     RECT  8.165 113.28 13.208 113.304 ;
     RECT  8.165 116.448 13.208 144.312 ;
     RECT  13.208 2.148 13.312 192.252 ;
     RECT  13.312 2.418 13.504 191.982 ;
     RECT  13.504 39.888 14.821 39.912 ;
     RECT  14.821 39.888 14.861 40.056 ;
     RECT  13.504 13.44 18.608 13.464 ;
     RECT  13.504 15.6 18.608 15.624 ;
     RECT  14.861 40.032 18.608 40.056 ;
     RECT  13.504 47.856 18.608 48.456 ;
     RECT  13.504 52.224 18.608 52.248 ;
     RECT  13.504 55.728 18.608 56.904 ;
     RECT  13.504 60.144 18.608 62.808 ;
     RECT  13.504 63.888 18.608 97.128 ;
     RECT  13.504 107.28 18.608 112.008 ;
     RECT  13.504 113.28 18.608 113.304 ;
     RECT  13.504 116.448 18.608 144.312 ;
     RECT  18.608 2.148 18.712 192.252 ;
     RECT  18.712 2.418 18.904 191.982 ;
     RECT  18.904 63.888 18.965 63.912 ;
     RECT  18.904 69.312 18.965 69.336 ;
     RECT  18.904 70.896 18.965 71.496 ;
     RECT  18.904 74.688 18.965 74.712 ;
     RECT  18.904 78.48 18.965 78.504 ;
     RECT  18.904 80.256 18.965 80.664 ;
     RECT  18.904 82.272 18.965 84.456 ;
     RECT  18.904 89.232 18.965 89.832 ;
     RECT  18.904 91.44 18.965 91.464 ;
     RECT  18.904 93.024 18.965 93.048 ;
     RECT  18.904 95.232 18.965 95.256 ;
     RECT  18.904 120.576 18.965 121.176 ;
     RECT  18.904 124.368 18.965 124.392 ;
     RECT  18.904 126.528 18.965 126.552 ;
     RECT  18.904 129.744 18.965 130.344 ;
     RECT  18.904 131.952 18.965 131.976 ;
     RECT  18.904 133.536 18.965 134.136 ;
     RECT  18.904 141.12 18.965 141.144 ;
     RECT  18.904 142.704 18.965 142.728 ;
     RECT  18.904 110.208 19.433 111.672 ;
     RECT  18.965 82.944 19.649 82.968 ;
     RECT  18.965 80.256 19.757 80.28 ;
     RECT  19.433 110.208 19.937 110.856 ;
     RECT  19.937 110.208 20.045 110.232 ;
     RECT  18.904 13.44 24.008 13.464 ;
     RECT  18.904 15.6 24.008 15.624 ;
     RECT  24.008 2.148 24.112 192.252 ;
     RECT  24.112 2.418 24.304 191.982 ;
     RECT  28.897 2.832 28.969 2.856 ;
     RECT  29.105 1.728 29.189 1.752 ;
     RECT  28.969 2.784 29.408 2.856 ;
     RECT  24.304 13.44 29.408 13.464 ;
     RECT  24.304 15.6 29.408 15.624 ;
     RECT  29.408 2.148 29.512 192.252 ;
     RECT  29.512 2.418 29.704 191.982 ;
     RECT  29.704 2.784 30.131 3.192 ;
     RECT  29.704 13.584 30.131 13.608 ;
     RECT  31.265 1.728 31.349 1.752 ;
     RECT  33.433 0.096 33.517 0.12 ;
     RECT  30.131 2.784 34.808 2.808 ;
     RECT  29.704 15.6 34.808 15.624 ;
     RECT  29.704 38.784 34.808 38.808 ;
     RECT  34.808 2.148 34.912 192.252 ;
     RECT  34.912 2.418 35.104 191.982 ;
     RECT  35.104 2.784 36.461 2.808 ;
     RECT  35.104 38.4 36.901 38.808 ;
     RECT  37.753 1.728 37.837 1.752 ;
     RECT  35.104 15.6 38.761 15.624 ;
     RECT  38.761 15.504 38.801 15.624 ;
     RECT  38.545 2.784 39.589 2.808 ;
     RECT  39.913 0.576 39.997 0.6 ;
     RECT  39.445 66.096 40.021 66.12 ;
     RECT  36.901 38.4 40.049 39.048 ;
     RECT  39.985 189.36 40.093 189.384 ;
     RECT  39.589 2.784 40.208 2.856 ;
     RECT  38.801 15.504 40.208 15.528 ;
     RECT  40.069 29.76 40.208 29.784 ;
     RECT  40.069 34.08 40.208 34.104 ;
     RECT  40.069 36.096 40.208 36.12 ;
     RECT  40.049 38.4 40.208 40.008 ;
     RECT  39.841 50.016 40.208 50.04 ;
     RECT  40.021 65.664 40.208 66.12 ;
     RECT  39.829 80.352 40.208 80.376 ;
     RECT  39.829 82.944 40.208 82.968 ;
     RECT  40.129 103.056 40.208 103.08 ;
     RECT  40.165 117.504 40.208 117.528 ;
     RECT  39.409 124.848 40.208 124.872 ;
     RECT  40.201 128.976 40.208 129 ;
     RECT  39.769 143.808 40.208 143.832 ;
     RECT  39.949 170.832 40.208 170.856 ;
     RECT  40.201 176.688 40.208 176.712 ;
     RECT  40.093 189.36 40.208 190.296 ;
     RECT  40.208 2.148 40.312 192.252 ;
     RECT  40.312 2.418 40.504 191.982 ;
     RECT  40.504 176.16 40.565 176.712 ;
     RECT  40.504 177.84 40.565 178.392 ;
     RECT  40.504 146.496 40.601 146.52 ;
     RECT  40.565 178.368 40.601 178.392 ;
     RECT  40.504 38.208 40.643 39.624 ;
     RECT  40.504 63.216 40.643 64.392 ;
     RECT  40.504 159.216 40.643 162.072 ;
     RECT  40.504 186.72 40.673 186.984 ;
     RECT  40.504 174.912 40.691 175.032 ;
     RECT  40.504 153.84 40.717 154.488 ;
     RECT  40.643 159.216 40.732 160.728 ;
     RECT  40.504 75.6 40.78 75.624 ;
     RECT  40.504 104.256 40.787 105.48 ;
     RECT  40.504 113.424 40.787 113.64 ;
     RECT  40.504 115.104 40.787 118.008 ;
     RECT  40.504 128.976 40.787 132.888 ;
     RECT  40.504 182.784 40.787 182.808 ;
     RECT  40.717 153.84 40.817 153.864 ;
     RECT  40.504 61.008 40.883 61.032 ;
     RECT  40.732 159.6 40.883 160.728 ;
     RECT  40.504 59.808 40.925 59.832 ;
     RECT  40.643 38.208 40.931 38.424 ;
     RECT  40.504 41.856 40.931 41.88 ;
     RECT  40.504 56.16 40.931 56.184 ;
     RECT  40.504 99.6 40.931 101.304 ;
     RECT  40.787 115.104 40.931 116.856 ;
     RECT  40.504 170.832 40.931 171 ;
     RECT  40.691 175.008 40.931 175.032 ;
     RECT  40.787 117.984 40.933 118.008 ;
     RECT  40.504 49.008 40.997 50.568 ;
     RECT  40.504 143.136 40.997 145.368 ;
     RECT  40.504 65.376 41.02 66.216 ;
     RECT  40.504 46.944 41.027 47.736 ;
     RECT  40.997 49.008 41.027 49.128 ;
     RECT  41.027 49.008 41.069 49.032 ;
     RECT  40.504 102.816 41.069 103.272 ;
     RECT  40.883 159.6 41.069 160.056 ;
     RECT  40.643 63.216 41.075 64.056 ;
     RECT  40.787 105.456 41.075 105.48 ;
     RECT  40.504 106.56 41.075 107.784 ;
     RECT  40.931 115.104 41.075 116.04 ;
     RECT  40.504 43.536 41.105 44.472 ;
     RECT  40.504 76.944 41.105 76.968 ;
     RECT  41.075 107.76 41.105 107.784 ;
     RECT  40.504 133.968 41.105 136.104 ;
     RECT  40.997 144.768 41.105 145.368 ;
     RECT  41.075 63.216 41.113 63.816 ;
     RECT  40.787 104.256 41.116 104.28 ;
     RECT  40.997 50.544 41.123 50.568 ;
     RECT  40.504 82.944 41.123 82.968 ;
     RECT  40.504 85.872 41.123 85.896 ;
     RECT  40.787 129.936 41.123 132.792 ;
     RECT  41.105 135.024 41.141 136.104 ;
     RECT  40.504 124.992 41.149 126.312 ;
     RECT  41.123 130.656 41.149 132.792 ;
     RECT  40.504 139.632 41.149 139.656 ;
     RECT  40.504 142.08 41.164 142.104 ;
     RECT  40.504 91.2 41.171 92.952 ;
     RECT  41.069 103.056 41.171 103.272 ;
     RECT  41.171 91.2 41.212 92.088 ;
     RECT  40.931 99.6 41.212 101.256 ;
     RECT  41.027 47.28 41.213 47.736 ;
     RECT  41.212 91.2 41.213 91.32 ;
     RECT  40.504 26.4 41.219 27.24 ;
     RECT  40.643 39.6 41.219 39.624 ;
     RECT  40.504 108.816 41.219 108.84 ;
     RECT  41.105 144.768 41.249 144.792 ;
     RECT  40.504 109.92 41.26 110.04 ;
     RECT  40.504 149.376 41.267 149.496 ;
     RECT  40.504 67.488 41.285 68.376 ;
     RECT  41.26 109.968 41.293 110.04 ;
     RECT  40.504 123.792 41.293 123.96 ;
     RECT  41.149 124.992 41.315 125.112 ;
     RECT  41.267 149.472 41.315 149.496 ;
     RECT  40.504 169.296 41.315 169.32 ;
     RECT  40.504 30.288 41.321 30.84 ;
     RECT  40.504 172.128 41.321 172.152 ;
     RECT  41.212 99.6 41.349 100.296 ;
     RECT  40.504 24.288 41.363 24.312 ;
     RECT  40.504 19.392 41.411 20.28 ;
     RECT  41.321 30.72 41.411 30.84 ;
     RECT  40.504 34.704 41.411 34.824 ;
     RECT  40.565 176.16 41.429 176.184 ;
     RECT  40.504 33.408 41.452 33.432 ;
     RECT  41.149 131.088 41.459 132.792 ;
     RECT  41.285 67.776 41.465 68.376 ;
     RECT  40.997 143.136 41.465 143.16 ;
     RECT  40.504 16.8 41.468 16.824 ;
     RECT  40.504 31.872 41.501 31.896 ;
     RECT  41.213 91.296 41.501 91.32 ;
     RECT  40.504 78.624 41.507 78.888 ;
     RECT  41.141 136.08 41.507 136.104 ;
     RECT  40.504 138 41.507 138.024 ;
     RECT  41.213 47.28 41.537 47.304 ;
     RECT  41.075 116.016 41.537 116.04 ;
     RECT  40.504 13.632 41.555 13.656 ;
     RECT  41.468 16.8 41.555 17.352 ;
     RECT  40.504 28.848 41.557 28.92 ;
     RECT  41.411 30.816 41.557 30.84 ;
     RECT  41.557 28.848 41.603 29.4 ;
     RECT  41.557 30.816 41.603 31.368 ;
     RECT  41.411 34.704 41.603 34.728 ;
     RECT  40.931 38.208 41.603 38.232 ;
     RECT  41.516 177.216 41.603 177.24 ;
     RECT  40.504 181.44 41.603 181.464 ;
     RECT  41.293 109.968 41.617 109.992 ;
     RECT  40.643 162.048 41.641 162.072 ;
     RECT  40.504 74.592 41.645 74.616 ;
     RECT  41.557 112.08 41.645 112.104 ;
     RECT  40.787 113.424 41.645 113.448 ;
     RECT  41.02 65.376 41.681 65.4 ;
     RECT  40.504 98.256 41.681 98.28 ;
     RECT  40.673 186.72 41.681 186.744 ;
     RECT  41.113 63.792 41.753 63.816 ;
     RECT  41.507 78.864 41.753 78.888 ;
     RECT  41.315 125.088 41.753 125.112 ;
     RECT  40.504 173.28 41.753 173.304 ;
     RECT  41.603 31.344 41.789 31.368 ;
     RECT  41.641 161.76 41.843 162.6 ;
     RECT  40.504 166.464 41.845 167.208 ;
     RECT  41.349 100.272 41.861 100.296 ;
     RECT  41.797 164.208 41.884 164.232 ;
     RECT  41.9 152.736 41.929 152.76 ;
     RECT  41.845 166.368 41.933 167.208 ;
     RECT  41.075 106.56 41.969 106.584 ;
     RECT  41.9 148.416 41.987 148.44 ;
     RECT  41.929 152.736 41.987 153.336 ;
     RECT  41.989 45.648 42.076 45.672 ;
     RECT  41.603 29.376 42.113 29.4 ;
     RECT  40.504 165.264 42.113 165.288 ;
     RECT  41.965 1.728 42.131 1.752 ;
     RECT  41.069 160.032 42.133 160.056 ;
     RECT  41.843 161.76 42.133 161.784 ;
     RECT  42.092 122.592 42.179 122.616 ;
     RECT  41.293 123.936 42.179 123.96 ;
     RECT  42.133 159.6 42.179 160.056 ;
     RECT  42.133 161.28 42.179 161.784 ;
     RECT  40.504 79.92 42.217 80.136 ;
     RECT  41.933 167.184 42.227 167.208 ;
     RECT  42.181 169.008 42.268 169.032 ;
     RECT  42.188 85.344 42.275 85.368 ;
     RECT  41.941 146.976 42.293 147 ;
     RECT  42.236 74.832 42.323 75.192 ;
     RECT  41.219 27.216 42.329 27.24 ;
     RECT  42.229 96.336 42.329 96.36 ;
     RECT  40.504 15.504 42.365 15.528 ;
     RECT  42.332 129.408 42.373 129.432 ;
     RECT  41.459 131.088 42.373 131.832 ;
     RECT  42.181 170.16 42.401 170.184 ;
     RECT  41.149 126.288 42.419 126.312 ;
     RECT  42.373 129.408 42.419 131.832 ;
     RECT  41.411 19.392 42.431 19.416 ;
     RECT  41.105 43.536 42.437 43.56 ;
     RECT  42.431 19.392 42.469 19.512 ;
     RECT  42.287 23.712 42.611 23.736 ;
     RECT  42.524 25.056 42.611 25.08 ;
     RECT  41.965 136.752 42.659 136.776 ;
     RECT  42.217 79.632 42.709 80.136 ;
     RECT  42.469 18.768 42.725 19.512 ;
     RECT  42.725 19.344 42.755 19.512 ;
     RECT  41.465 67.776 42.755 67.8 ;
     RECT  42.709 79.632 42.755 80.328 ;
     RECT  42.179 159.6 42.757 159.624 ;
     RECT  42.757 158.688 42.803 159.624 ;
     RECT  42.764 187.296 42.851 187.32 ;
     RECT  42.253 190.944 42.851 190.968 ;
     RECT  42.419 130.224 42.869 131.832 ;
     RECT  42.565 26.112 42.947 26.136 ;
     RECT  41.987 153.312 43.004 153.336 ;
     RECT  43.004 153.312 43.091 154.248 ;
     RECT  42.803 158.688 43.091 158.712 ;
     RECT  42.757 31.92 43.139 31.944 ;
     RECT  42.901 29.76 43.185 30.024 ;
     RECT  43.093 170.4 43.229 170.424 ;
     RECT  43.148 56.928 43.235 56.952 ;
     RECT  41.171 103.056 43.235 103.08 ;
     RECT  42.869 130.224 43.331 131.112 ;
     RECT  43.093 178.368 43.331 178.392 ;
     RECT  42.805 185.808 43.331 185.832 ;
     RECT  42.133 119.424 43.373 119.448 ;
     RECT  42.421 70.224 43.441 70.248 ;
     RECT  42.323 74.832 43.441 74.856 ;
     RECT  43.441 74.688 43.481 74.856 ;
     RECT  41.141 135.024 43.481 135.048 ;
     RECT  43.484 150.432 43.513 150.456 ;
     RECT  42.179 161.28 43.517 161.304 ;
     RECT  43.441 70.224 43.525 70.584 ;
     RECT  43.481 74.688 43.525 74.712 ;
     RECT  43.189 52.416 43.532 52.44 ;
     RECT  43.505 155.04 43.532 155.064 ;
     RECT  43.513 149.904 43.571 150.456 ;
     RECT  42.755 80.304 43.589 80.328 ;
     RECT  43.532 155.04 43.589 155.592 ;
     RECT  41.893 55.872 43.619 55.896 ;
     RECT  42.217 60.144 43.619 60.168 ;
     RECT  42.552 140.976 43.619 141 ;
     RECT  43.532 142.464 43.619 142.488 ;
     RECT  43.571 149.904 43.619 149.928 ;
     RECT  43.589 155.568 43.619 155.592 ;
     RECT  43.58 39.888 43.667 39.912 ;
     RECT  43.621 47.568 43.693 47.592 ;
     RECT  42.168 92.832 43.693 92.856 ;
     RECT  42.755 19.344 43.729 19.368 ;
     RECT  43.693 47.568 43.733 48.456 ;
     RECT  43.693 92.352 43.733 92.856 ;
     RECT  43.729 19.2 43.769 19.368 ;
     RECT  43.532 52.32 43.805 52.44 ;
     RECT  43.733 48.432 43.811 48.456 ;
     RECT  43.805 52.32 43.811 52.344 ;
     RECT  43.733 92.352 43.861 92.376 ;
     RECT  43.82 66.624 43.907 66.648 ;
     RECT  43.801 70.128 43.907 70.152 ;
     RECT  42.229 88.32 43.907 88.344 ;
     RECT  43.861 91.44 43.907 92.376 ;
     RECT  43.331 130.32 44.021 130.344 ;
     RECT  43.573 175.968 44.051 175.992 ;
     RECT  43.973 179.568 44.057 179.592 ;
     RECT  42.229 82.128 44.165 82.152 ;
     RECT  43.573 65.568 44.273 65.592 ;
     RECT  43.907 91.44 44.273 91.464 ;
     RECT  43.765 119.376 44.339 119.4 ;
     RECT  42.217 97.776 44.435 97.8 ;
     RECT  44.348 103.104 44.435 103.128 ;
     RECT  44.252 115.536 44.435 115.56 ;
     RECT  44.089 105.408 44.496 105.432 ;
     RECT  41.555 16.8 44.869 16.824 ;
     RECT  44.869 16.8 45.565 17.112 ;
     RECT  45.565 5.568 45.608 5.592 ;
     RECT  45.421 13.056 45.608 13.08 ;
     RECT  45.601 14.208 45.608 14.232 ;
     RECT  45.565 16.656 45.608 17.112 ;
     RECT  43.769 19.2 45.608 19.224 ;
     RECT  42.325 21.168 45.608 21.192 ;
     RECT  43.185 29.76 45.608 29.784 ;
     RECT  45.608 2.148 45.712 192.252 ;
     RECT  45.712 2.418 45.904 191.982 ;
     RECT  45.904 13.056 46.019 13.08 ;
     RECT  45.904 14.208 46.019 14.232 ;
     RECT  45.904 16.656 46.019 16.68 ;
     RECT  45.904 5.04 46.109 7.368 ;
     RECT  46.109 5.184 46.211 7.368 ;
     RECT  45.904 10.416 46.361 10.44 ;
     RECT  45.904 29.76 46.433 29.784 ;
     RECT  46.211 5.184 46.577 6.888 ;
     RECT  45.904 11.712 46.613 11.736 ;
     RECT  45.904 39.888 46.793 40.056 ;
     RECT  46.577 5.328 47.009 6.888 ;
     RECT  47.009 5.328 47.117 6.6 ;
     RECT  47.117 6.144 47.225 6.6 ;
     RECT  47.225 6.144 47.297 6.168 ;
     RECT  48.337 172.128 48.589 172.152 ;
     RECT  45.904 161.376 48.661 161.4 ;
     RECT  46.793 40.032 49.417 40.056 ;
     RECT  48.337 188.256 49.525 188.28 ;
     RECT  45.904 170.544 49.561 170.568 ;
     RECT  49.417 22.8 49.633 22.824 ;
     RECT  49.561 167.04 49.669 167.064 ;
     RECT  48.445 176.208 49.669 176.232 ;
     RECT  50.209 135.744 50.281 135.768 ;
     RECT  45.904 155.664 50.389 155.688 ;
     RECT  49.525 187.584 50.425 188.28 ;
     RECT  47.941 92.4 50.497 92.424 ;
     RECT  47.689 105.072 50.533 105.096 ;
     RECT  48.805 129.408 50.605 129.432 ;
     RECT  48.661 161.376 50.641 161.928 ;
     RECT  45.904 185.952 50.641 185.976 ;
     RECT  50.425 187.008 50.641 188.28 ;
     RECT  49.129 26.832 50.677 26.856 ;
     RECT  49.309 32.592 50.677 32.616 ;
     RECT  47.581 62.784 50.677 62.808 ;
     RECT  50.533 104.4 50.677 105.096 ;
     RECT  50.065 126.624 50.677 126.648 ;
     RECT  49.669 166.464 50.677 167.064 ;
     RECT  50.677 126.528 50.713 126.648 ;
     RECT  49.957 181.824 50.749 181.848 ;
     RECT  50.677 83.856 50.857 83.88 ;
     RECT  50.605 129.408 50.857 130.008 ;
     RECT  49.417 17.664 51.008 17.688 ;
     RECT  49.633 22.8 51.008 23.592 ;
     RECT  50.677 26.832 51.008 27.48 ;
     RECT  50.677 31.968 51.008 32.616 ;
     RECT  49.417 34.896 51.008 34.92 ;
     RECT  48.985 37.056 51.008 37.08 ;
     RECT  49.417 40.032 51.008 40.584 ;
     RECT  48.481 43.392 51.008 43.416 ;
     RECT  49.741 47.952 51.008 47.976 ;
     RECT  50.389 57.6 51.008 57.624 ;
     RECT  50.389 58.752 51.008 58.776 ;
     RECT  50.677 62.688 51.008 62.808 ;
     RECT  49.849 66.288 51.008 66.312 ;
     RECT  49.561 75.264 51.008 75.288 ;
     RECT  50.857 83.232 51.008 83.88 ;
     RECT  47.257 86.736 51.008 86.76 ;
     RECT  50.641 90.096 51.008 90.12 ;
     RECT  50.497 91.872 51.008 92.424 ;
     RECT  49.633 95.904 51.008 95.928 ;
     RECT  50.533 97.536 51.008 97.56 ;
     RECT  49.849 99.264 51.008 99.288 ;
     RECT  50.173 100.32 51.008 100.344 ;
     RECT  50.677 103.776 51.008 105.096 ;
     RECT  50.173 109.488 51.008 109.512 ;
     RECT  50.425 115.2 51.008 115.224 ;
     RECT  50.389 119.184 51.008 119.208 ;
     RECT  50.641 120.864 51.008 120.888 ;
     RECT  50.605 124.368 51.008 124.392 ;
     RECT  50.713 126.528 51.008 126.744 ;
     RECT  50.857 128.688 51.008 130.008 ;
     RECT  50.281 135.12 51.008 135.768 ;
     RECT  49.417 138.048 51.008 138.072 ;
     RECT  49.993 139.776 51.008 139.8 ;
     RECT  48.913 144.912 51.008 144.936 ;
     RECT  48.265 147.072 51.008 147.096 ;
     RECT  48.805 149.376 51.008 149.4 ;
     RECT  48.445 150.576 51.008 150.6 ;
     RECT  50.389 155.04 51.008 155.688 ;
     RECT  50.641 160.752 51.008 161.928 ;
     RECT  50.677 166.464 51.008 167.832 ;
     RECT  49.129 169.344 51.008 169.368 ;
     RECT  49.561 170.544 51.008 171.048 ;
     RECT  48.589 172.128 51.008 172.728 ;
     RECT  49.669 175.632 51.008 176.232 ;
     RECT  50.425 177.84 51.008 177.864 ;
     RECT  50.749 181.296 51.008 181.848 ;
     RECT  50.641 185.952 51.008 188.28 ;
     RECT  48.481 191.088 51.008 191.112 ;
     RECT  50.713 192.192 51.008 192.216 ;
     RECT  51.008 2.148 51.112 192.252 ;
     RECT  51.112 2.418 51.304 191.982 ;
     RECT  51.304 22.8 51.401 23.592 ;
     RECT  51.304 66.192 51.401 66.312 ;
     RECT  51.304 166.464 51.401 167.832 ;
     RECT  54.476 0.528 54.563 0.552 ;
     RECT  51.304 94.704 54.601 94.728 ;
     RECT  54.601 94.512 54.707 94.728 ;
     RECT  54.707 94.608 54.709 94.728 ;
     RECT  54.709 94.608 54.749 94.872 ;
     RECT  51.304 17.76 56.408 17.784 ;
     RECT  51.401 22.8 56.408 23.448 ;
     RECT  51.304 25.584 56.408 27.48 ;
     RECT  51.304 29.088 56.408 29.112 ;
     RECT  51.304 31.968 56.408 32.616 ;
     RECT  51.304 34.896 56.408 34.92 ;
     RECT  51.304 37.056 56.408 37.08 ;
     RECT  51.304 39.888 56.408 40.584 ;
     RECT  51.304 43.392 56.408 43.416 ;
     RECT  51.304 48.096 56.408 49.08 ;
     RECT  51.304 51.216 56.408 51.24 ;
     RECT  51.304 53.088 56.408 53.112 ;
     RECT  51.304 57.6 56.408 58.92 ;
     RECT  51.304 60.528 56.408 60.552 ;
     RECT  51.304 62.784 56.408 62.808 ;
     RECT  51.401 66.192 56.408 66.216 ;
     RECT  51.304 73.104 56.408 73.128 ;
     RECT  51.304 74.352 56.408 75.288 ;
     RECT  51.304 78.192 56.408 78.792 ;
     RECT  51.304 82.56 56.408 83.88 ;
     RECT  51.304 86.064 56.408 86.76 ;
     RECT  51.304 88.944 56.408 90.12 ;
     RECT  51.304 91.872 56.408 92.424 ;
     RECT  54.749 94.848 56.408 94.872 ;
     RECT  51.304 95.904 56.408 95.928 ;
     RECT  51.304 97.536 56.408 97.56 ;
     RECT  51.304 99.264 56.408 99.288 ;
     RECT  51.304 100.32 56.408 100.344 ;
     RECT  51.304 103.776 56.408 106.056 ;
     RECT  51.304 109.488 56.408 109.512 ;
     RECT  51.304 115.2 56.408 115.224 ;
     RECT  51.304 119.28 56.408 119.304 ;
     RECT  51.304 120.864 56.408 120.888 ;
     RECT  51.304 124.368 56.408 124.392 ;
     RECT  51.304 126.72 56.408 126.744 ;
     RECT  51.304 128.688 56.408 130.104 ;
     RECT  51.304 133.2 56.408 133.224 ;
     RECT  51.304 135.12 56.408 135.768 ;
     RECT  51.304 138.048 56.408 138.072 ;
     RECT  51.304 139.776 56.408 139.8 ;
     RECT  51.304 140.832 56.408 141.432 ;
     RECT  51.304 144.912 56.408 144.936 ;
     RECT  51.304 147.072 56.408 147.096 ;
     RECT  51.304 149.376 56.408 149.4 ;
     RECT  51.304 150.576 56.408 150.6 ;
     RECT  51.304 152.88 56.408 152.904 ;
     RECT  51.304 155.04 56.408 155.688 ;
     RECT  51.304 160.752 56.408 161.928 ;
     RECT  51.401 166.464 56.408 167.736 ;
     RECT  51.304 169.344 56.408 169.368 ;
     RECT  51.304 170.544 56.408 171.144 ;
     RECT  51.304 172.128 56.408 172.728 ;
     RECT  51.304 175.008 56.408 176.232 ;
     RECT  51.304 177.84 56.408 178.536 ;
     RECT  51.304 181.296 56.408 181.944 ;
     RECT  51.304 185.952 56.408 188.28 ;
     RECT  51.304 191.088 56.408 191.112 ;
     RECT  56.408 2.148 56.512 192.252 ;
     RECT  56.512 2.418 56.704 191.982 ;
     RECT  56.704 62.784 58.669 62.808 ;
     RECT  56.704 94.848 58.669 94.872 ;
     RECT  56.704 126.72 58.669 126.744 ;
     RECT  58.669 62.688 58.773 62.808 ;
     RECT  58.669 94.608 58.773 94.872 ;
     RECT  58.669 126.528 58.773 126.744 ;
     RECT  56.704 17.76 61.808 17.784 ;
     RECT  56.704 22.8 61.808 23.448 ;
     RECT  56.704 25.584 61.808 27.48 ;
     RECT  56.704 29.088 61.808 29.112 ;
     RECT  56.704 31.968 61.808 32.616 ;
     RECT  56.704 34.896 61.808 34.92 ;
     RECT  56.704 37.056 61.808 37.08 ;
     RECT  56.704 39.888 61.808 40.584 ;
     RECT  56.704 43.392 61.808 43.416 ;
     RECT  56.704 48.096 61.808 49.08 ;
     RECT  56.704 51.216 61.808 51.24 ;
     RECT  56.704 53.088 61.808 53.112 ;
     RECT  56.704 57.6 61.808 58.92 ;
     RECT  56.704 60.528 61.808 60.552 ;
     RECT  58.773 62.784 61.808 62.808 ;
     RECT  56.704 66.192 61.808 66.216 ;
     RECT  56.704 73.104 61.808 73.128 ;
     RECT  56.704 74.352 61.808 75.288 ;
     RECT  56.704 78.192 61.808 78.792 ;
     RECT  56.704 82.56 61.808 83.88 ;
     RECT  56.704 86.064 61.808 86.76 ;
     RECT  56.704 88.944 61.808 90.12 ;
     RECT  56.704 91.872 61.808 92.424 ;
     RECT  58.773 94.848 61.808 94.872 ;
     RECT  56.704 95.904 61.808 95.928 ;
     RECT  56.704 97.536 61.808 97.56 ;
     RECT  56.704 99.264 61.808 99.288 ;
     RECT  56.704 100.32 61.808 100.344 ;
     RECT  56.704 103.776 61.808 106.056 ;
     RECT  56.704 109.488 61.808 109.512 ;
     RECT  56.704 115.2 61.808 115.224 ;
     RECT  56.704 119.28 61.808 119.304 ;
     RECT  56.704 120.864 61.808 120.888 ;
     RECT  56.704 124.368 61.808 124.392 ;
     RECT  58.773 126.72 61.808 126.744 ;
     RECT  56.704 128.688 61.808 130.104 ;
     RECT  56.704 133.2 61.808 133.224 ;
     RECT  56.704 135.12 61.808 135.768 ;
     RECT  56.704 138.048 61.808 138.072 ;
     RECT  56.704 139.776 61.808 139.8 ;
     RECT  56.704 140.832 61.808 141.432 ;
     RECT  56.704 144.912 61.808 144.936 ;
     RECT  56.704 147.072 61.808 147.096 ;
     RECT  56.704 149.376 61.808 149.4 ;
     RECT  56.704 150.576 61.808 150.6 ;
     RECT  56.704 152.88 61.808 152.904 ;
     RECT  56.704 155.04 61.808 155.688 ;
     RECT  56.704 160.752 61.808 161.928 ;
     RECT  56.704 166.464 61.808 167.736 ;
     RECT  56.704 169.344 61.808 169.368 ;
     RECT  56.704 170.544 61.808 171.144 ;
     RECT  56.704 172.128 61.808 172.728 ;
     RECT  56.704 175.008 61.808 176.232 ;
     RECT  56.704 177.84 61.808 178.536 ;
     RECT  56.704 181.296 61.808 181.944 ;
     RECT  56.704 185.952 61.808 188.28 ;
     RECT  56.704 191.088 61.808 191.112 ;
     RECT  61.808 2.148 61.912 192.252 ;
     RECT  61.912 2.418 62.104 191.982 ;
     RECT  62.104 94.512 62.675 94.872 ;
     RECT  62.104 126.528 62.675 126.744 ;
     RECT  62.675 94.512 62.677 94.728 ;
     RECT  62.104 39.888 62.741 40.584 ;
     RECT  62.677 94.608 62.741 94.728 ;
     RECT  62.675 126.528 62.741 126.648 ;
     RECT  62.104 62.784 66.661 62.808 ;
     RECT  62.741 94.704 66.661 94.728 ;
     RECT  62.741 126.624 66.661 126.648 ;
     RECT  66.661 94.608 66.697 94.728 ;
     RECT  66.661 126.528 66.697 126.648 ;
     RECT  62.104 17.76 67.208 17.784 ;
     RECT  62.104 22.8 67.208 23.448 ;
     RECT  62.104 25.584 67.208 27.48 ;
     RECT  62.104 29.088 67.208 29.112 ;
     RECT  62.104 31.968 67.208 32.616 ;
     RECT  62.104 34.896 67.208 34.92 ;
     RECT  62.104 37.056 67.208 37.08 ;
     RECT  62.741 40.032 67.208 40.584 ;
     RECT  62.104 43.392 67.208 43.416 ;
     RECT  62.104 48.096 67.208 49.08 ;
     RECT  62.104 51.216 67.208 51.24 ;
     RECT  62.104 53.088 67.208 53.112 ;
     RECT  62.104 57.6 67.208 58.92 ;
     RECT  62.104 60.528 67.208 60.552 ;
     RECT  66.661 62.688 67.208 62.808 ;
     RECT  62.104 66.192 67.208 66.216 ;
     RECT  62.104 73.104 67.208 73.128 ;
     RECT  62.104 74.352 67.208 75.288 ;
     RECT  62.104 78.192 67.208 78.792 ;
     RECT  62.104 82.56 67.208 83.88 ;
     RECT  62.104 86.064 67.208 86.76 ;
     RECT  62.104 88.944 67.208 90.12 ;
     RECT  62.104 91.872 67.208 92.424 ;
     RECT  66.697 94.608 67.208 94.872 ;
     RECT  62.104 95.904 67.208 95.928 ;
     RECT  62.104 97.536 67.208 97.56 ;
     RECT  62.104 99.264 67.208 99.288 ;
     RECT  62.104 100.32 67.208 100.344 ;
     RECT  62.104 103.776 67.208 106.056 ;
     RECT  62.104 109.488 67.208 109.512 ;
     RECT  62.104 115.2 67.208 115.224 ;
     RECT  62.104 119.28 67.208 119.304 ;
     RECT  62.104 120.864 67.208 120.888 ;
     RECT  62.104 124.368 67.208 124.392 ;
     RECT  66.697 126.528 67.208 126.744 ;
     RECT  62.104 128.688 67.208 130.104 ;
     RECT  62.104 133.2 67.208 133.224 ;
     RECT  62.104 135.12 67.208 135.768 ;
     RECT  62.104 138.048 67.208 138.072 ;
     RECT  62.104 139.776 67.208 139.8 ;
     RECT  62.104 140.832 67.208 141.432 ;
     RECT  62.104 144.912 67.208 144.936 ;
     RECT  62.104 147.072 67.208 147.096 ;
     RECT  62.104 149.376 67.208 149.4 ;
     RECT  62.104 150.576 67.208 150.6 ;
     RECT  62.104 152.88 67.208 152.904 ;
     RECT  62.104 155.04 67.208 155.688 ;
     RECT  62.104 160.752 67.208 161.928 ;
     RECT  62.104 166.464 67.208 167.736 ;
     RECT  62.104 169.344 67.208 169.368 ;
     RECT  62.104 170.544 67.208 171.144 ;
     RECT  62.104 172.128 67.208 172.728 ;
     RECT  62.104 175.008 67.208 176.232 ;
     RECT  62.104 177.84 67.208 178.536 ;
     RECT  62.104 181.296 67.208 181.944 ;
     RECT  62.104 185.952 67.208 188.28 ;
     RECT  62.104 191.088 67.208 191.112 ;
     RECT  67.208 2.148 67.312 192.252 ;
     RECT  67.312 2.418 67.504 191.982 ;
     RECT  67.504 62.784 70.597 62.808 ;
     RECT  70.597 62.688 70.733 62.808 ;
     RECT  67.504 17.76 72.608 17.784 ;
     RECT  67.504 22.8 72.608 23.448 ;
     RECT  67.504 25.584 72.608 27.48 ;
     RECT  67.504 29.088 72.608 29.112 ;
     RECT  67.504 31.968 72.608 32.616 ;
     RECT  67.504 34.896 72.608 34.92 ;
     RECT  67.504 37.056 72.608 37.08 ;
     RECT  67.504 39.888 72.608 40.584 ;
     RECT  67.504 43.392 72.608 43.416 ;
     RECT  67.504 48.096 72.608 49.08 ;
     RECT  67.504 51.216 72.608 51.24 ;
     RECT  67.504 53.088 72.608 53.112 ;
     RECT  67.504 57.6 72.608 58.92 ;
     RECT  67.504 60.528 72.608 60.552 ;
     RECT  70.733 62.784 72.608 62.808 ;
     RECT  67.504 66.192 72.608 66.216 ;
     RECT  67.504 73.104 72.608 73.128 ;
     RECT  67.504 74.352 72.608 75.288 ;
     RECT  67.504 78.192 72.608 78.792 ;
     RECT  67.504 82.56 72.608 83.88 ;
     RECT  67.504 86.064 72.608 86.76 ;
     RECT  67.504 88.944 72.608 90.12 ;
     RECT  67.504 91.872 72.608 92.424 ;
     RECT  67.504 94.848 72.608 94.872 ;
     RECT  67.504 95.904 72.608 95.928 ;
     RECT  67.504 97.536 72.608 97.56 ;
     RECT  67.504 99.264 72.608 99.288 ;
     RECT  67.504 100.32 72.608 100.344 ;
     RECT  67.504 103.776 72.608 106.056 ;
     RECT  67.504 109.488 72.608 109.512 ;
     RECT  67.504 115.2 72.608 115.224 ;
     RECT  67.504 119.28 72.608 119.304 ;
     RECT  67.504 120.864 72.608 120.888 ;
     RECT  67.504 124.368 72.608 124.392 ;
     RECT  67.504 126.72 72.608 126.744 ;
     RECT  67.504 128.688 72.608 130.104 ;
     RECT  67.504 133.2 72.608 133.224 ;
     RECT  67.504 135.12 72.608 135.768 ;
     RECT  67.504 138.048 72.608 138.072 ;
     RECT  67.504 139.776 72.608 139.8 ;
     RECT  67.504 140.832 72.608 141.432 ;
     RECT  67.504 144.912 72.608 144.936 ;
     RECT  67.504 147.072 72.608 147.096 ;
     RECT  67.504 149.376 72.608 149.4 ;
     RECT  67.504 150.576 72.608 150.6 ;
     RECT  67.504 152.88 72.608 152.904 ;
     RECT  67.504 155.04 72.608 155.688 ;
     RECT  67.504 160.752 72.608 161.928 ;
     RECT  67.504 166.464 72.608 167.736 ;
     RECT  67.504 169.344 72.608 169.368 ;
     RECT  67.504 170.544 72.608 171.144 ;
     RECT  67.504 172.128 72.608 172.728 ;
     RECT  67.504 175.008 72.608 176.232 ;
     RECT  67.504 177.84 72.608 178.536 ;
     RECT  67.504 181.296 72.608 181.944 ;
     RECT  67.504 185.952 72.608 188.28 ;
     RECT  67.504 191.088 72.608 191.112 ;
     RECT  72.608 2.148 72.712 192.252 ;
     RECT  72.712 2.418 72.904 191.982 ;
     RECT  72.904 62.784 74.629 62.808 ;
     RECT  72.904 94.848 74.629 94.872 ;
     RECT  72.904 126.72 74.629 126.744 ;
     RECT  74.629 94.608 74.713 94.872 ;
     RECT  74.629 126.528 74.713 126.744 ;
     RECT  74.629 62.688 74.765 62.808 ;
     RECT  72.904 17.76 78.008 17.784 ;
     RECT  72.904 22.8 78.008 23.448 ;
     RECT  72.904 25.584 78.008 27.48 ;
     RECT  72.904 29.088 78.008 29.112 ;
     RECT  72.904 31.968 78.008 32.616 ;
     RECT  72.904 34.896 78.008 34.92 ;
     RECT  72.904 37.056 78.008 37.08 ;
     RECT  72.904 39.888 78.008 40.584 ;
     RECT  72.904 43.392 78.008 43.416 ;
     RECT  72.904 48.096 78.008 49.08 ;
     RECT  72.904 51.216 78.008 51.24 ;
     RECT  72.904 53.088 78.008 53.112 ;
     RECT  72.904 57.6 78.008 58.92 ;
     RECT  72.904 60.528 78.008 60.552 ;
     RECT  74.765 62.784 78.008 62.808 ;
     RECT  72.904 66.192 78.008 66.216 ;
     RECT  72.904 73.104 78.008 73.128 ;
     RECT  72.904 74.352 78.008 75.288 ;
     RECT  72.904 78.192 78.008 78.792 ;
     RECT  72.904 82.56 78.008 83.88 ;
     RECT  72.904 86.064 78.008 86.76 ;
     RECT  72.904 88.944 78.008 90.12 ;
     RECT  72.904 91.872 78.008 92.424 ;
     RECT  74.713 94.848 78.008 94.872 ;
     RECT  72.904 95.904 78.008 95.928 ;
     RECT  72.904 97.536 78.008 97.56 ;
     RECT  72.904 99.264 78.008 99.288 ;
     RECT  72.904 100.32 78.008 100.344 ;
     RECT  72.904 103.776 78.008 106.056 ;
     RECT  72.904 109.488 78.008 109.512 ;
     RECT  72.904 115.2 78.008 115.224 ;
     RECT  72.904 119.28 78.008 119.304 ;
     RECT  72.904 120.864 78.008 120.888 ;
     RECT  72.904 124.368 78.008 124.392 ;
     RECT  74.713 126.72 78.008 126.744 ;
     RECT  72.904 128.688 78.008 130.104 ;
     RECT  72.904 133.2 78.008 133.224 ;
     RECT  72.904 135.12 78.008 135.768 ;
     RECT  72.904 138.048 78.008 138.072 ;
     RECT  72.904 139.776 78.008 139.8 ;
     RECT  72.904 140.832 78.008 141.432 ;
     RECT  72.904 144.912 78.008 144.936 ;
     RECT  72.904 147.072 78.008 147.096 ;
     RECT  72.904 149.376 78.008 149.4 ;
     RECT  72.904 150.576 78.008 150.6 ;
     RECT  72.904 152.88 78.008 152.904 ;
     RECT  72.904 155.04 78.008 155.688 ;
     RECT  72.904 160.752 78.008 161.928 ;
     RECT  72.904 166.464 78.008 167.736 ;
     RECT  72.904 169.344 78.008 169.368 ;
     RECT  72.904 170.544 78.008 171.144 ;
     RECT  72.904 172.128 78.008 172.728 ;
     RECT  72.904 175.008 78.008 176.232 ;
     RECT  72.904 177.84 78.008 178.536 ;
     RECT  72.904 181.296 78.008 181.944 ;
     RECT  72.904 185.952 78.008 188.28 ;
     RECT  72.904 191.088 78.008 191.112 ;
     RECT  78.008 2.148 78.112 192.252 ;
     RECT  78.112 2.418 78.304 191.982 ;
     RECT  78.304 94.608 78.659 94.872 ;
     RECT  78.304 126.528 78.659 126.744 ;
     RECT  78.304 39.888 78.689 40.584 ;
     RECT  78.304 62.688 78.689 62.808 ;
     RECT  78.659 94.608 78.689 94.728 ;
     RECT  78.659 126.528 78.689 126.648 ;
     RECT  78.689 62.784 82.609 62.808 ;
     RECT  78.689 94.704 82.609 94.728 ;
     RECT  78.689 126.624 82.609 126.648 ;
     RECT  82.609 94.608 82.645 94.728 ;
     RECT  82.609 126.528 82.645 126.648 ;
     RECT  78.304 53.088 83.185 53.112 ;
     RECT  78.304 17.76 83.408 17.784 ;
     RECT  78.304 22.8 83.408 23.448 ;
     RECT  78.304 25.584 83.408 27.48 ;
     RECT  78.304 29.088 83.408 29.112 ;
     RECT  78.304 31.968 83.408 32.616 ;
     RECT  78.304 34.896 83.408 34.92 ;
     RECT  78.304 37.056 83.408 37.08 ;
     RECT  78.689 40.032 83.408 40.584 ;
     RECT  78.304 43.392 83.408 43.416 ;
     RECT  78.304 48.096 83.408 49.08 ;
     RECT  78.304 51.216 83.408 51.24 ;
     RECT  83.185 52.992 83.408 53.112 ;
     RECT  78.304 57.6 83.408 58.92 ;
     RECT  78.304 60.528 83.408 60.552 ;
     RECT  82.609 62.688 83.408 62.808 ;
     RECT  78.304 66.192 83.408 66.216 ;
     RECT  78.304 73.104 83.408 73.128 ;
     RECT  78.304 74.352 83.408 75.288 ;
     RECT  78.304 78.192 83.408 78.792 ;
     RECT  78.304 82.56 83.408 83.88 ;
     RECT  78.304 86.064 83.408 86.76 ;
     RECT  78.304 88.944 83.408 90.12 ;
     RECT  78.304 91.872 83.408 92.424 ;
     RECT  82.645 94.608 83.408 94.872 ;
     RECT  78.304 95.904 83.408 95.928 ;
     RECT  78.304 97.536 83.408 97.56 ;
     RECT  78.304 99.264 83.408 99.288 ;
     RECT  78.304 100.32 83.408 100.344 ;
     RECT  78.304 103.776 83.408 106.056 ;
     RECT  78.304 109.488 83.408 109.512 ;
     RECT  78.304 115.2 83.408 115.224 ;
     RECT  78.304 119.28 83.408 119.304 ;
     RECT  78.304 120.864 83.408 120.888 ;
     RECT  78.304 124.368 83.408 124.392 ;
     RECT  82.645 126.528 83.408 126.744 ;
     RECT  78.304 128.688 83.408 130.104 ;
     RECT  78.304 133.2 83.408 133.224 ;
     RECT  78.304 135.12 83.408 135.768 ;
     RECT  78.304 138.048 83.408 138.072 ;
     RECT  78.304 139.776 83.408 139.8 ;
     RECT  78.304 140.832 83.408 141.432 ;
     RECT  78.304 144.912 83.408 144.936 ;
     RECT  78.304 147.072 83.408 147.096 ;
     RECT  78.304 149.376 83.408 149.4 ;
     RECT  78.304 150.576 83.408 150.6 ;
     RECT  78.304 152.88 83.408 152.904 ;
     RECT  78.304 155.04 83.408 155.688 ;
     RECT  78.304 160.752 83.408 161.928 ;
     RECT  78.304 166.464 83.408 167.736 ;
     RECT  78.304 169.344 83.408 169.368 ;
     RECT  78.304 170.544 83.408 171.144 ;
     RECT  78.304 172.128 83.408 172.728 ;
     RECT  78.304 175.008 83.408 176.232 ;
     RECT  78.304 177.84 83.408 178.536 ;
     RECT  78.304 181.296 83.408 181.944 ;
     RECT  78.304 185.952 83.408 188.28 ;
     RECT  78.304 191.088 83.408 191.112 ;
     RECT  83.408 2.148 83.512 192.252 ;
     RECT  83.512 2.418 83.704 192.072 ;
     RECT  83.704 34.896 83.837 34.92 ;
     RECT  83.704 40.032 83.837 40.584 ;
     RECT  83.704 51.216 83.837 51.24 ;
     RECT  83.704 147.072 83.837 147.096 ;
     RECT  83.704 150.576 83.837 150.6 ;
     RECT  83.704 151.872 83.837 152.904 ;
     RECT  83.704 166.464 83.837 167.736 ;
     RECT  83.704 169.344 83.837 172.728 ;
     RECT  83.704 175.008 83.837 176.232 ;
     RECT  83.704 48.096 84.877 49.08 ;
     RECT  83.704 94.848 84.877 94.872 ;
     RECT  83.704 95.904 84.877 96.552 ;
     RECT  83.704 155.04 84.877 155.688 ;
     RECT  83.704 177.84 84.877 180.072 ;
     RECT  83.704 181.296 84.877 181.992 ;
     RECT  83.704 19.008 84.913 19.032 ;
     RECT  83.704 25.632 84.913 29.16 ;
     RECT  83.704 31.968 84.913 32.616 ;
     RECT  83.704 36.432 84.913 37.368 ;
     RECT  83.837 40.032 84.913 40.056 ;
     RECT  83.704 41.808 84.913 42.12 ;
     RECT  83.704 43.392 84.913 43.416 ;
     RECT  84.877 47.472 84.913 49.704 ;
     RECT  83.704 52.992 84.913 53.112 ;
     RECT  84.877 55.056 84.913 55.08 ;
     RECT  83.704 64.896 84.913 64.92 ;
     RECT  83.704 68.688 84.913 68.712 ;
     RECT  83.704 70.896 84.913 70.92 ;
     RECT  83.704 72.144 84.913 75.336 ;
     RECT  83.704 78.192 84.913 78.84 ;
     RECT  83.704 86.064 84.913 86.76 ;
     RECT  83.704 88.32 84.913 90.12 ;
     RECT  83.704 99.072 84.913 99.288 ;
     RECT  83.704 100.32 84.913 100.344 ;
     RECT  83.704 111.696 84.913 113.928 ;
     RECT  83.704 115.2 84.913 115.224 ;
     RECT  83.704 148.08 84.913 148.104 ;
     RECT  83.704 149.376 84.913 149.4 ;
     RECT  83.837 151.872 84.913 152.568 ;
     RECT  83.704 160.752 84.913 161.928 ;
     RECT  84.913 19.008 85.453 19.656 ;
     RECT  83.704 20.928 85.453 20.952 ;
     RECT  84.913 99.072 85.453 100.344 ;
     RECT  83.704 101.568 85.453 101.592 ;
     RECT  83.704 126.72 85.453 126.744 ;
     RECT  83.704 127.824 85.453 130.104 ;
     RECT  83.704 144.624 85.453 144.936 ;
     RECT  83.837 169.92 85.453 172.152 ;
     RECT  84.877 94.848 85.477 96.552 ;
     RECT  83.704 97.536 85.477 97.56 ;
     RECT  83.704 17.424 85.489 17.784 ;
     RECT  85.453 19.008 85.489 20.952 ;
     RECT  83.704 22.512 85.489 24.408 ;
     RECT  84.913 25.632 85.489 30.408 ;
     RECT  84.913 31.68 85.489 32.616 ;
     RECT  84.913 35.136 85.489 35.16 ;
     RECT  84.913 36.432 85.489 37.992 ;
     RECT  84.913 39.552 85.489 40.056 ;
     RECT  84.913 41.472 85.489 42.12 ;
     RECT  84.913 43.392 85.489 49.704 ;
     RECT  84.913 52.56 85.489 55.08 ;
     RECT  83.704 57.6 85.489 61.128 ;
     RECT  83.704 62.784 85.489 62.808 ;
     RECT  84.913 64.56 85.489 64.92 ;
     RECT  83.704 66.144 85.489 66.168 ;
     RECT  84.913 68.688 85.489 69 ;
     RECT  84.913 70.272 85.489 70.92 ;
     RECT  84.913 72.144 85.489 75.672 ;
     RECT  84.913 78.192 85.489 79.8 ;
     RECT  83.704 82.608 85.489 83.88 ;
     RECT  84.913 85.44 85.489 90.12 ;
     RECT  83.704 91.872 85.489 93.048 ;
     RECT  85.477 94.848 85.489 97.56 ;
     RECT  85.453 99.072 85.489 101.592 ;
     RECT  83.704 103.776 85.489 106.056 ;
     RECT  83.704 107.904 85.489 107.928 ;
     RECT  83.704 109.488 85.489 109.512 ;
     RECT  84.913 111.408 85.489 113.928 ;
     RECT  84.913 115.2 85.489 115.848 ;
     RECT  83.704 117.408 85.489 117.432 ;
     RECT  83.704 119.28 85.489 119.304 ;
     RECT  83.704 120.864 85.489 120.888 ;
     RECT  84.877 123.12 85.489 123.144 ;
     RECT  83.704 124.368 85.489 124.392 ;
     RECT  84.913 125.616 85.489 125.64 ;
     RECT  85.453 126.72 85.489 130.104 ;
     RECT  84.913 131.664 85.489 131.688 ;
     RECT  83.704 133.2 85.489 133.224 ;
     RECT  83.704 134.496 85.489 141.48 ;
     RECT  85.453 144.624 85.489 145.272 ;
     RECT  84.913 147.792 85.489 148.104 ;
     RECT  84.913 149.376 85.489 149.688 ;
     RECT  84.913 151.584 85.489 152.568 ;
     RECT  84.877 155.04 85.489 156.36 ;
     RECT  84.913 157.584 85.489 157.608 ;
     RECT  84.913 160.128 85.489 162.648 ;
     RECT  84.877 164.88 85.489 164.904 ;
     RECT  83.837 166.464 85.489 166.488 ;
     RECT  83.837 167.712 85.489 167.736 ;
     RECT  85.453 168.96 85.489 172.152 ;
     RECT  83.837 175.008 85.489 175.656 ;
     RECT  84.877 177.84 85.489 181.992 ;
     RECT  83.704 185.952 85.489 188.28 ;
     RECT  83.704 191.136 85.489 192.072 ;
     RECT  85.489 17.424 86.281 106.056 ;
     RECT  85.489 107.28 86.281 157.608 ;
     RECT  85.489 158.832 86.281 162.984 ;
     RECT  85.489 164.208 86.281 172.152 ;
     RECT  85.489 173.424 86.281 192.072 ;
     RECT  86.281 2.688 86.364 2.712 ;
     RECT  86.281 7.008 86.364 7.032 ;
     RECT  86.281 9.168 86.364 9.192 ;
     RECT  83.704 10.272 86.364 10.296 ;
     RECT  86.281 11.328 86.364 11.352 ;
     RECT  85.489 12.432 86.364 12.456 ;
     RECT  86.281 17.424 86.364 192.072 ;
    LAYER M5 ;
     RECT  33.456 0.016 33.48 0.131 ;
     RECT  54.528 0.016 54.552 0.563 ;
     RECT  39.936 0.016 39.96 0.611 ;
     RECT  29.136 0.016 29.16 1.763 ;
     RECT  31.296 0.016 31.32 1.763 ;
     RECT  37.776 0.016 37.8 1.763 ;
     RECT  42.096 0.016 42.12 1.763 ;
     RECT  2.4 2.137 2.52 2.151 ;
     RECT  7.8 2.137 7.92 2.151 ;
     RECT  13.2 2.137 13.32 2.151 ;
     RECT  18.6 2.137 18.72 2.151 ;
     RECT  24 2.137 24.12 2.151 ;
     RECT  29.4 2.137 29.52 2.151 ;
     RECT  34.8 2.137 34.92 2.151 ;
     RECT  40.2 2.137 40.32 2.151 ;
     RECT  45.6 2.137 45.72 2.151 ;
     RECT  51 2.137 51.12 2.151 ;
     RECT  56.4 2.137 56.52 2.151 ;
     RECT  61.8 2.137 61.92 2.151 ;
     RECT  67.2 2.137 67.32 2.151 ;
     RECT  72.6 2.137 72.72 2.151 ;
     RECT  78 2.137 78.12 2.151 ;
     RECT  83.4 2.137 83.52 2.151 ;
     RECT  40.2 2.151 40.512 2.821 ;
     RECT  29.4 2.151 29.712 3.157 ;
     RECT  45.6 2.151 45.912 5.029 ;
     RECT  45.6 5.029 46.008 7.333 ;
     RECT  45.6 7.333 46.2 10.451 ;
     RECT  45.6 10.451 45.912 11.701 ;
     RECT  29.4 3.157 30.12 13.619 ;
     RECT  45.6 11.701 46.008 16.691 ;
     RECT  40.08 2.821 40.512 16.789 ;
     RECT  41.52 13.621 41.544 16.789 ;
     RECT  45.6 16.691 45.912 17.077 ;
     RECT  40.08 16.789 41.544 17.363 ;
     RECT  44.88 17.077 45.912 19.235 ;
     RECT  42.48 18.757 42.504 19.333 ;
     RECT  40.08 17.363 41.352 19.381 ;
     RECT  42.48 19.333 42.744 19.523 ;
     RECT  40.08 19.381 41.4 20.291 ;
     RECT  42.72 19.523 42.744 21.157 ;
     RECT  42.336 21.157 42.744 21.203 ;
     RECT  42.336 21.203 42.36 23.701 ;
     RECT  42.336 23.701 42.6 23.747 ;
     RECT  42.576 23.747 42.6 26.101 ;
     RECT  42.576 26.101 42.936 26.147 ;
     RECT  40.08 20.291 41.352 28.837 ;
     RECT  42.912 26.147 42.936 29.989 ;
     RECT  42.912 29.989 43.128 30.035 ;
     RECT  40.08 28.837 41.592 31.379 ;
     RECT  43.104 30.035 43.128 31.955 ;
     RECT  40.08 31.379 41.4 34.693 ;
     RECT  40.08 34.693 41.592 34.835 ;
     RECT  40.08 34.835 40.512 38.197 ;
     RECT  41.568 34.835 41.592 38.197 ;
     RECT  40.08 38.197 41.592 38.243 ;
     RECT  29.4 13.619 30.024 38.819 ;
     RECT  36.912 38.677 36.936 39.059 ;
     RECT  40.08 38.243 40.92 39.589 ;
     RECT  40.08 39.589 41.208 40.019 ;
     RECT  40.2 40.019 41.208 43.525 ;
     RECT  40.2 43.525 42.024 43.571 ;
     RECT  42 43.571 42.024 45.683 ;
     RECT  40.2 43.571 40.92 46.933 ;
     RECT  40.2 46.933 41.016 47.269 ;
     RECT  43.632 39.877 43.656 47.603 ;
     RECT  40.2 47.269 41.112 50.579 ;
     RECT  0.192 51.205 0.216 51.395 ;
     RECT  43.776 48.421 43.8 52.309 ;
     RECT  43.584 52.309 43.8 52.355 ;
     RECT  43.584 52.355 43.608 55.907 ;
     RECT  43.2 56.917 43.224 60.133 ;
     RECT  43.2 60.133 43.608 60.179 ;
     RECT  7.8 2.151 8.112 62.677 ;
     RECT  51 2.151 51.312 62.677 ;
     RECT  67.2 2.151 67.512 62.677 ;
     RECT  83.4 2.151 83.712 62.677 ;
     RECT  6.816 62.677 8.112 62.819 ;
     RECT  10.8 62.677 10.92 62.819 ;
     RECT  50.688 62.677 51.312 62.819 ;
     RECT  58.704 62.677 58.728 62.819 ;
     RECT  66.672 62.677 67.512 62.819 ;
     RECT  70.608 62.677 70.632 62.819 ;
     RECT  74.64 62.677 74.664 62.819 ;
     RECT  82.656 62.677 83.712 62.819 ;
     RECT  40.2 50.579 40.92 63.205 ;
     RECT  40.2 63.205 41.064 64.067 ;
     RECT  40.2 64.067 40.92 65.365 ;
     RECT  43.584 60.179 43.608 65.557 ;
     RECT  43.584 65.557 43.896 65.603 ;
     RECT  40.2 65.365 40.968 66.085 ;
     RECT  39.456 66.085 40.968 66.227 ;
     RECT  39.456 66.227 40.92 67.765 ;
     RECT  43.872 65.603 43.896 70.163 ;
     RECT  42.72 67.765 42.744 70.213 ;
     RECT  42.432 70.213 42.744 70.259 ;
     RECT  43.488 70.549 43.512 74.723 ;
     RECT  42.432 70.259 42.456 75.157 ;
     RECT  39.456 67.765 41.016 78.613 ;
     RECT  42.288 75.157 42.456 78.613 ;
     RECT  39.456 78.613 42.456 79.621 ;
     RECT  39.456 79.621 42.744 79.955 ;
     RECT  42.432 79.955 42.744 80.147 ;
     RECT  42.72 80.147 42.744 82.117 ;
     RECT  42.24 82.117 42.744 82.163 ;
     RECT  42.24 82.163 42.264 88.355 ;
     RECT  43.872 88.309 43.896 92.387 ;
     RECT  39.456 79.955 41.16 92.963 ;
     RECT  61.8 2.151 62.112 94.501 ;
     RECT  2.4 2.151 2.712 94.597 ;
     RECT  7.8 62.819 8.112 94.597 ;
     RECT  67.2 62.819 67.512 94.597 ;
     RECT  78 2.151 78.312 94.597 ;
     RECT  83.4 62.819 83.712 94.597 ;
     RECT  6.816 94.597 8.112 94.739 ;
     RECT  54.672 94.501 54.696 94.739 ;
     RECT  66.672 94.597 67.512 94.739 ;
     RECT  2.4 94.597 2.856 94.883 ;
     RECT  10.8 94.597 10.824 94.883 ;
     RECT  14.784 94.501 14.808 94.883 ;
     RECT  58.704 94.597 58.728 94.883 ;
     RECT  61.8 94.501 62.664 94.883 ;
     RECT  74.64 94.597 74.664 94.883 ;
     RECT  78 94.597 78.648 94.883 ;
     RECT  82.656 94.597 83.712 94.883 ;
     RECT  42.24 92.821 42.264 96.371 ;
     RECT  85.488 97.381 85.512 97.571 ;
     RECT  39.456 92.963 41.016 98.245 ;
     RECT  39.456 98.245 41.304 99.635 ;
     RECT  39.456 99.635 41.16 103.283 ;
     RECT  39.456 103.283 40.776 104.245 ;
     RECT  39.456 104.245 41.064 105.491 ;
     RECT  39.456 105.491 40.776 107.125 ;
     RECT  39.456 107.125 41.064 107.795 ;
     RECT  39.456 107.795 40.68 108.805 ;
     RECT  39.456 108.805 41.208 109.957 ;
     RECT  39.456 109.957 41.592 112.115 ;
     RECT  44.4 97.765 44.424 115.525 ;
     RECT  44.304 115.525 44.424 115.571 ;
     RECT  44.304 115.571 44.328 119.411 ;
     RECT  39.456 112.115 41.256 119.413 ;
     RECT  39.456 119.413 42.168 123.827 ;
     RECT  41.712 123.827 42.168 123.971 ;
     RECT  39.456 123.827 40.68 124.883 ;
     RECT  40.2 124.883 40.68 124.981 ;
     RECT  41.712 123.971 41.736 124.981 ;
     RECT  40.2 124.981 41.736 125.123 ;
     RECT  43.2 103.045 43.224 126.277 ;
     RECT  2.4 94.883 2.712 126.517 ;
     RECT  7.8 94.739 8.112 126.517 ;
     RECT  51 62.819 51.312 126.517 ;
     RECT  61.8 94.883 62.112 126.517 ;
     RECT  67.2 94.739 67.512 126.517 ;
     RECT  78 94.883 78.312 126.517 ;
     RECT  83.4 94.883 83.712 126.517 ;
     RECT  6.816 126.517 8.112 126.659 ;
     RECT  50.688 126.517 51.312 126.659 ;
     RECT  66.672 126.517 67.512 126.659 ;
     RECT  2.4 126.517 2.856 126.755 ;
     RECT  10.8 126.517 10.824 126.755 ;
     RECT  14.784 126.421 14.808 126.755 ;
     RECT  58.704 126.517 58.728 126.755 ;
     RECT  61.8 126.517 62.664 126.755 ;
     RECT  74.64 126.517 74.664 126.755 ;
     RECT  78 126.517 78.648 126.755 ;
     RECT  82.656 126.517 83.712 126.755 ;
     RECT  42.384 126.277 43.224 130.213 ;
     RECT  42.384 130.213 43.32 130.259 ;
     RECT  40.2 125.123 41.304 131.077 ;
     RECT  43.2 130.259 43.32 131.123 ;
     RECT  43.2 131.123 43.224 135.013 ;
     RECT  40.2 131.077 41.496 138.035 ;
     RECT  42.624 135.013 43.224 140.965 ;
     RECT  42.624 140.965 43.608 141.011 ;
     RECT  40.2 138.035 41.256 146.965 ;
     RECT  43.2 141.011 43.608 149.939 ;
     RECT  40.2 146.965 41.976 152.771 ;
     RECT  43.2 149.939 43.56 153.301 ;
     RECT  43.056 153.301 43.56 155.557 ;
     RECT  43.056 155.557 43.608 158.677 ;
     RECT  40.2 152.771 41.304 159.589 ;
     RECT  42.768 158.677 43.608 159.589 ;
     RECT  40.2 159.589 43.608 159.635 ;
     RECT  40.2 159.635 42.168 161.795 ;
     RECT  40.2 161.795 41.832 164.243 ;
     RECT  40.2 164.243 41.304 166.357 ;
     RECT  40.2 166.357 41.88 167.173 ;
     RECT  40.2 167.173 42.216 169.331 ;
     RECT  42.192 169.331 42.216 170.195 ;
     RECT  43.2 159.635 43.608 170.389 ;
     RECT  40.2 169.331 40.92 175.043 ;
     RECT  43.104 170.389 43.608 175.957 ;
     RECT  40.2 175.043 40.68 176.195 ;
     RECT  40.2 176.195 40.632 177.205 ;
     RECT  43.104 175.957 44.04 178.403 ;
     RECT  43.2 178.403 44.04 179.603 ;
     RECT  40.2 177.205 41.592 181.475 ;
     RECT  40.2 181.475 40.776 182.819 ;
     RECT  43.2 179.603 43.32 185.797 ;
     RECT  42.816 185.797 43.32 185.843 ;
     RECT  40.2 182.819 40.632 186.995 ;
     RECT  42.816 185.843 43.224 190.979 ;
     RECT  51 126.659 51.312 192.181 ;
     RECT  2.4 126.755 2.712 192.249 ;
     RECT  7.8 126.659 8.112 192.249 ;
     RECT  13.2 2.151 13.512 192.249 ;
     RECT  18.6 2.151 18.912 192.249 ;
     RECT  24 2.151 24.312 192.249 ;
     RECT  29.4 38.819 29.712 192.249 ;
     RECT  34.8 2.151 35.112 192.249 ;
     RECT  40.2 186.995 40.512 192.249 ;
     RECT  45.6 19.235 45.912 192.249 ;
     RECT  50.736 192.181 51.312 192.249 ;
     RECT  56.4 2.151 56.712 192.249 ;
     RECT  61.8 126.755 62.112 192.249 ;
     RECT  67.2 126.659 67.512 192.249 ;
     RECT  72.6 2.151 72.912 192.249 ;
     RECT  78 126.755 78.312 192.249 ;
     RECT  83.4 126.755 83.712 192.249 ;
     RECT  2.4 192.249 2.52 192.263 ;
     RECT  7.8 192.249 7.92 192.263 ;
     RECT  13.2 192.249 13.32 192.263 ;
     RECT  18.6 192.249 18.72 192.263 ;
     RECT  24 192.249 24.12 192.263 ;
     RECT  29.4 192.249 29.52 192.263 ;
     RECT  34.8 192.249 34.92 192.263 ;
     RECT  40.2 192.249 40.32 192.263 ;
     RECT  45.6 192.249 45.72 192.263 ;
     RECT  50.736 192.249 51.12 192.263 ;
     RECT  56.4 192.249 56.52 192.263 ;
     RECT  61.8 192.249 61.92 192.263 ;
     RECT  67.2 192.249 67.32 192.263 ;
     RECT  72.6 192.249 72.72 192.263 ;
     RECT  78 192.249 78.12 192.263 ;
     RECT  83.4 192.249 83.52 192.263 ;
     RECT  43.2 190.979 43.224 194.384 ;
     RECT  50.736 192.263 50.76 194.384 ;
  END
END ot_s81hd_lsc_rf
END LIBRARY
